VERSION 5.8 ;
BUSBITCHARS "[]" ;
DIVIDERCHAR "/" ;
UNITS
    DATABASE MICRONS 1000 ;
END UNITS

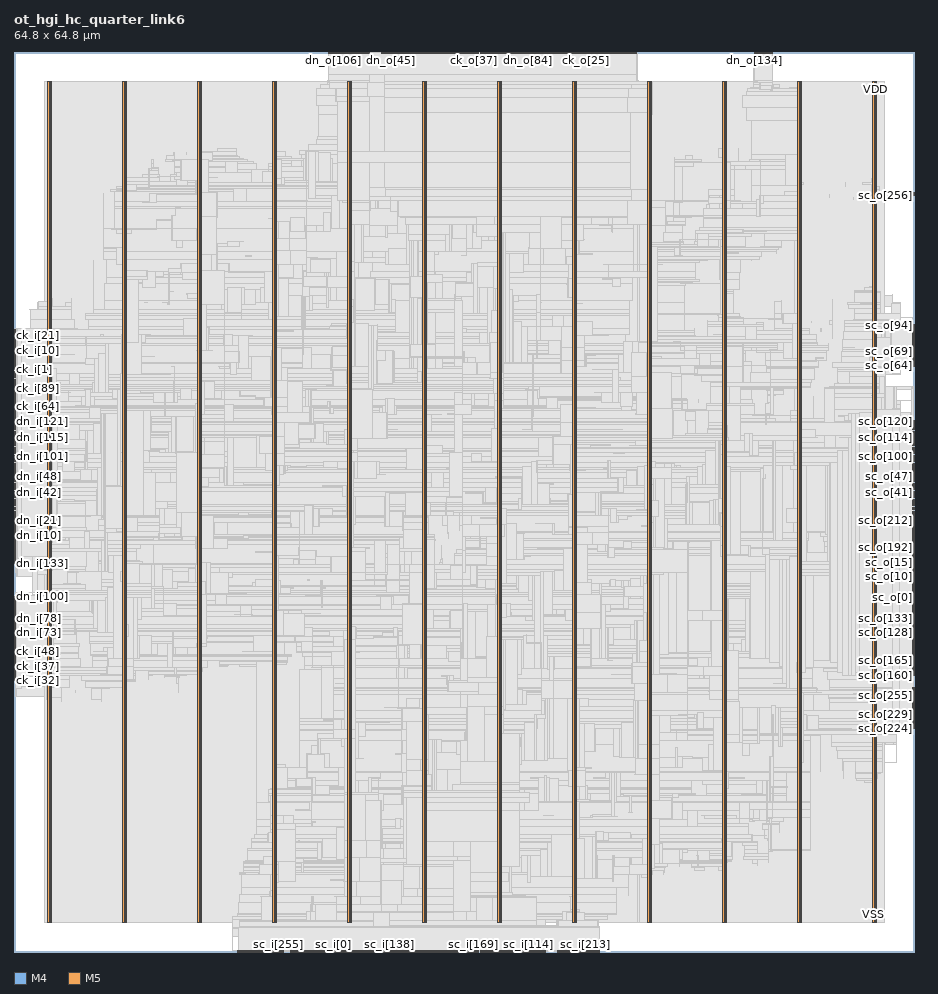
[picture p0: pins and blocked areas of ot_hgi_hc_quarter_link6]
MACRO ot_hgi_hc_quarter_link6
  FOREIGN ot_hgi_hc_quarter_link6 0 0 ;
  CLASS BLOCK ;
  SIZE 64.8 BY 64.8 ;
  PIN ck_i[0]
    DIRECTION INPUT ;
    USE SIGNAL ;
    PORT
      LAYER M4 ;
        RECT  0 41.808 0.084 41.832 ;
    END
  END ck_i[0]
  PIN ck_i[10]
    DIRECTION INPUT ;
    USE SIGNAL ;
    PORT
      LAYER M4 ;
        RECT  0 42.768 0.084 42.792 ;
    END
  END ck_i[10]
  PIN ck_i[11]
    DIRECTION INPUT ;
    USE SIGNAL ;
    PORT
      LAYER M4 ;
        RECT  0 42.864 0.084 42.888 ;
    END
  END ck_i[11]
  PIN ck_i[12]
    DIRECTION INPUT ;
    USE SIGNAL ;
    PORT
      LAYER M4 ;
        RECT  0 42.96 0.084 42.984 ;
    END
  END ck_i[12]
  PIN ck_i[13]
    DIRECTION INPUT ;
    USE SIGNAL ;
    PORT
      LAYER M4 ;
        RECT  0 43.056 0.084 43.08 ;
    END
  END ck_i[13]
  PIN ck_i[14]
    DIRECTION INPUT ;
    USE SIGNAL ;
    PORT
      LAYER M4 ;
        RECT  0 43.152 0.084 43.176 ;
    END
  END ck_i[14]
  PIN ck_i[15]
    DIRECTION INPUT ;
    USE SIGNAL ;
    PORT
      LAYER M4 ;
        RECT  0 43.248 0.084 43.272 ;
    END
  END ck_i[15]
  PIN ck_i[16]
    DIRECTION INPUT ;
    USE SIGNAL ;
    PORT
      LAYER M4 ;
        RECT  0 43.344 0.084 43.368 ;
    END
  END ck_i[16]
  PIN ck_i[17]
    DIRECTION INPUT ;
    USE SIGNAL ;
    PORT
      LAYER M4 ;
        RECT  0 43.44 0.084 43.464 ;
    END
  END ck_i[17]
  PIN ck_i[18]
    DIRECTION INPUT ;
    USE SIGNAL ;
    PORT
      LAYER M4 ;
        RECT  0 43.536 0.084 43.56 ;
    END
  END ck_i[18]
  PIN ck_i[19]
    DIRECTION INPUT ;
    USE SIGNAL ;
    PORT
      LAYER M4 ;
        RECT  0 43.632 0.084 43.656 ;
    END
  END ck_i[19]
  PIN ck_i[1]
    DIRECTION INPUT ;
    USE SIGNAL ;
    PORT
      LAYER M4 ;
        RECT  0 41.904 0.084 41.928 ;
    END
  END ck_i[1]
  PIN ck_i[20]
    DIRECTION INPUT ;
    USE SIGNAL ;
    PORT
      LAYER M4 ;
        RECT  0 43.728 0.084 43.752 ;
    END
  END ck_i[20]
  PIN ck_i[21]
    DIRECTION INPUT ;
    USE SIGNAL ;
    PORT
      LAYER M4 ;
        RECT  0 43.824 0.084 43.848 ;
    END
  END ck_i[21]
  PIN ck_i[22]
    DIRECTION INPUT ;
    USE SIGNAL ;
    PORT
      LAYER M4 ;
        RECT  0 43.92 0.084 43.944 ;
    END
  END ck_i[22]
  PIN ck_i[23]
    DIRECTION INPUT ;
    USE SIGNAL ;
    PORT
      LAYER M4 ;
        RECT  0 44.016 0.084 44.04 ;
    END
  END ck_i[23]
  PIN ck_i[24]
    DIRECTION INPUT ;
    USE SIGNAL ;
    PORT
      LAYER M4 ;
        RECT  0 44.112 0.084 44.136 ;
    END
  END ck_i[24]
  PIN ck_i[25]
    DIRECTION INPUT ;
    USE SIGNAL ;
    PORT
      LAYER M4 ;
        RECT  0 44.208 0.084 44.232 ;
    END
  END ck_i[25]
  PIN ck_i[26]
    DIRECTION INPUT ;
    USE SIGNAL ;
    PORT
      LAYER M4 ;
        RECT  0 44.304 0.084 44.328 ;
    END
  END ck_i[26]
  PIN ck_i[27]
    DIRECTION INPUT ;
    USE SIGNAL ;
    PORT
      LAYER M4 ;
        RECT  0 44.4 0.084 44.424 ;
    END
  END ck_i[27]
  PIN ck_i[28]
    DIRECTION INPUT ;
    USE SIGNAL ;
    PORT
      LAYER M4 ;
        RECT  0 44.496 0.084 44.52 ;
    END
  END ck_i[28]
  PIN ck_i[29]
    DIRECTION INPUT ;
    USE SIGNAL ;
    PORT
      LAYER M4 ;
        RECT  0 44.592 0.084 44.616 ;
    END
  END ck_i[29]
  PIN ck_i[2]
    DIRECTION INPUT ;
    USE SIGNAL ;
    PORT
      LAYER M4 ;
        RECT  0 42 0.084 42.024 ;
    END
  END ck_i[2]
  PIN ck_i[30]
    DIRECTION INPUT ;
    USE SIGNAL ;
    PORT
      LAYER M4 ;
        RECT  0 44.688 0.084 44.712 ;
    END
  END ck_i[30]
  PIN ck_i[31]
    DIRECTION INPUT ;
    USE SIGNAL ;
    PORT
      LAYER M4 ;
        RECT  0 44.784 0.084 44.808 ;
    END
  END ck_i[31]
  PIN ck_i[32]
    DIRECTION INPUT ;
    USE SIGNAL ;
    PORT
      LAYER M4 ;
        RECT  0 19.536 0.084 19.56 ;
    END
  END ck_i[32]
  PIN ck_i[33]
    DIRECTION INPUT ;
    USE SIGNAL ;
    PORT
      LAYER M4 ;
        RECT  0 19.632 0.084 19.656 ;
    END
  END ck_i[33]
  PIN ck_i[34]
    DIRECTION INPUT ;
    USE SIGNAL ;
    PORT
      LAYER M4 ;
        RECT  0 19.728 0.084 19.752 ;
    END
  END ck_i[34]
  PIN ck_i[35]
    DIRECTION INPUT ;
    USE SIGNAL ;
    PORT
      LAYER M4 ;
        RECT  0 19.824 0.084 19.848 ;
    END
  END ck_i[35]
  PIN ck_i[36]
    DIRECTION INPUT ;
    USE SIGNAL ;
    PORT
      LAYER M4 ;
        RECT  0 19.92 0.084 19.944 ;
    END
  END ck_i[36]
  PIN ck_i[37]
    DIRECTION INPUT ;
    USE SIGNAL ;
    PORT
      LAYER M4 ;
        RECT  0 20.016 0.084 20.04 ;
    END
  END ck_i[37]
  PIN ck_i[38]
    DIRECTION INPUT ;
    USE SIGNAL ;
    PORT
      LAYER M4 ;
        RECT  0 20.112 0.084 20.136 ;
    END
  END ck_i[38]
  PIN ck_i[39]
    DIRECTION INPUT ;
    USE SIGNAL ;
    PORT
      LAYER M4 ;
        RECT  0 20.208 0.084 20.232 ;
    END
  END ck_i[39]
  PIN ck_i[3]
    DIRECTION INPUT ;
    USE SIGNAL ;
    PORT
      LAYER M4 ;
        RECT  0 42.096 0.084 42.12 ;
    END
  END ck_i[3]
  PIN ck_i[40]
    DIRECTION INPUT ;
    USE SIGNAL ;
    PORT
      LAYER M4 ;
        RECT  0 20.304 0.084 20.328 ;
    END
  END ck_i[40]
  PIN ck_i[41]
    DIRECTION INPUT ;
    USE SIGNAL ;
    PORT
      LAYER M4 ;
        RECT  0 20.4 0.084 20.424 ;
    END
  END ck_i[41]
  PIN ck_i[42]
    DIRECTION INPUT ;
    USE SIGNAL ;
    PORT
      LAYER M4 ;
        RECT  0 20.496 0.084 20.52 ;
    END
  END ck_i[42]
  PIN ck_i[43]
    DIRECTION INPUT ;
    USE SIGNAL ;
    PORT
      LAYER M4 ;
        RECT  0 20.592 0.084 20.616 ;
    END
  END ck_i[43]
  PIN ck_i[44]
    DIRECTION INPUT ;
    USE SIGNAL ;
    PORT
      LAYER M4 ;
        RECT  0 20.688 0.084 20.712 ;
    END
  END ck_i[44]
  PIN ck_i[45]
    DIRECTION INPUT ;
    USE SIGNAL ;
    PORT
      LAYER M4 ;
        RECT  0 20.784 0.084 20.808 ;
    END
  END ck_i[45]
  PIN ck_i[46]
    DIRECTION INPUT ;
    USE SIGNAL ;
    PORT
      LAYER M4 ;
        RECT  0 20.88 0.084 20.904 ;
    END
  END ck_i[46]
  PIN ck_i[47]
    DIRECTION INPUT ;
    USE SIGNAL ;
    PORT
      LAYER M4 ;
        RECT  0 20.976 0.084 21 ;
    END
  END ck_i[47]
  PIN ck_i[48]
    DIRECTION INPUT ;
    USE SIGNAL ;
    PORT
      LAYER M4 ;
        RECT  0 21.072 0.084 21.096 ;
    END
  END ck_i[48]
  PIN ck_i[49]
    DIRECTION INPUT ;
    USE SIGNAL ;
    PORT
      LAYER M4 ;
        RECT  0 21.168 0.084 21.192 ;
    END
  END ck_i[49]
  PIN ck_i[4]
    DIRECTION INPUT ;
    USE SIGNAL ;
    PORT
      LAYER M4 ;
        RECT  0 42.192 0.084 42.216 ;
    END
  END ck_i[4]
  PIN ck_i[50]
    DIRECTION INPUT ;
    USE SIGNAL ;
    PORT
      LAYER M4 ;
        RECT  0 21.264 0.084 21.288 ;
    END
  END ck_i[50]
  PIN ck_i[51]
    DIRECTION INPUT ;
    USE SIGNAL ;
    PORT
      LAYER M4 ;
        RECT  0 21.36 0.084 21.384 ;
    END
  END ck_i[51]
  PIN ck_i[52]
    DIRECTION INPUT ;
    USE SIGNAL ;
    PORT
      LAYER M4 ;
        RECT  0 21.456 0.084 21.48 ;
    END
  END ck_i[52]
  PIN ck_i[53]
    DIRECTION INPUT ;
    USE SIGNAL ;
    PORT
      LAYER M4 ;
        RECT  0 21.552 0.084 21.576 ;
    END
  END ck_i[53]
  PIN ck_i[54]
    DIRECTION INPUT ;
    USE SIGNAL ;
    PORT
      LAYER M4 ;
        RECT  0 21.648 0.084 21.672 ;
    END
  END ck_i[54]
  PIN ck_i[55]
    DIRECTION INPUT ;
    USE SIGNAL ;
    PORT
      LAYER M4 ;
        RECT  0 21.744 0.084 21.768 ;
    END
  END ck_i[55]
  PIN ck_i[56]
    DIRECTION INPUT ;
    USE SIGNAL ;
    PORT
      LAYER M4 ;
        RECT  0 21.84 0.084 21.864 ;
    END
  END ck_i[56]
  PIN ck_i[57]
    DIRECTION INPUT ;
    USE SIGNAL ;
    PORT
      LAYER M4 ;
        RECT  0 21.936 0.084 21.96 ;
    END
  END ck_i[57]
  PIN ck_i[58]
    DIRECTION INPUT ;
    USE SIGNAL ;
    PORT
      LAYER M4 ;
        RECT  0 22.032 0.084 22.056 ;
    END
  END ck_i[58]
  PIN ck_i[59]
    DIRECTION INPUT ;
    USE SIGNAL ;
    PORT
      LAYER M4 ;
        RECT  0 22.128 0.084 22.152 ;
    END
  END ck_i[59]
  PIN ck_i[5]
    DIRECTION INPUT ;
    USE SIGNAL ;
    PORT
      LAYER M4 ;
        RECT  0 42.288 0.084 42.312 ;
    END
  END ck_i[5]
  PIN ck_i[60]
    DIRECTION INPUT ;
    USE SIGNAL ;
    PORT
      LAYER M4 ;
        RECT  0 22.224 0.084 22.248 ;
    END
  END ck_i[60]
  PIN ck_i[61]
    DIRECTION INPUT ;
    USE SIGNAL ;
    PORT
      LAYER M4 ;
        RECT  0 22.32 0.084 22.344 ;
    END
  END ck_i[61]
  PIN ck_i[62]
    DIRECTION INPUT ;
    USE SIGNAL ;
    PORT
      LAYER M4 ;
        RECT  0 22.416 0.084 22.44 ;
    END
  END ck_i[62]
  PIN ck_i[63]
    DIRECTION INPUT ;
    USE SIGNAL ;
    PORT
      LAYER M4 ;
        RECT  0 22.512 0.084 22.536 ;
    END
  END ck_i[63]
  PIN ck_i[64]
    DIRECTION INPUT ;
    USE SIGNAL ;
    PORT
      LAYER M4 ;
        RECT  0 38.736 0.084 38.76 ;
    END
  END ck_i[64]
  PIN ck_i[65]
    DIRECTION INPUT ;
    USE SIGNAL ;
    PORT
      LAYER M4 ;
        RECT  0 38.832 0.084 38.856 ;
    END
  END ck_i[65]
  PIN ck_i[66]
    DIRECTION INPUT ;
    USE SIGNAL ;
    PORT
      LAYER M4 ;
        RECT  0 38.928 0.084 38.952 ;
    END
  END ck_i[66]
  PIN ck_i[67]
    DIRECTION INPUT ;
    USE SIGNAL ;
    PORT
      LAYER M4 ;
        RECT  0 39.024 0.084 39.048 ;
    END
  END ck_i[67]
  PIN ck_i[68]
    DIRECTION INPUT ;
    USE SIGNAL ;
    PORT
      LAYER M4 ;
        RECT  0 39.12 0.084 39.144 ;
    END
  END ck_i[68]
  PIN ck_i[69]
    DIRECTION INPUT ;
    USE SIGNAL ;
    PORT
      LAYER M4 ;
        RECT  0 39.216 0.084 39.24 ;
    END
  END ck_i[69]
  PIN ck_i[6]
    DIRECTION INPUT ;
    USE SIGNAL ;
    PORT
      LAYER M4 ;
        RECT  0 42.384 0.084 42.408 ;
    END
  END ck_i[6]
  PIN ck_i[70]
    DIRECTION INPUT ;
    USE SIGNAL ;
    PORT
      LAYER M4 ;
        RECT  0 39.312 0.084 39.336 ;
    END
  END ck_i[70]
  PIN ck_i[71]
    DIRECTION INPUT ;
    USE SIGNAL ;
    PORT
      LAYER M4 ;
        RECT  0 39.408 0.084 39.432 ;
    END
  END ck_i[71]
  PIN ck_i[72]
    DIRECTION INPUT ;
    USE SIGNAL ;
    PORT
      LAYER M4 ;
        RECT  0 39.504 0.084 39.528 ;
    END
  END ck_i[72]
  PIN ck_i[73]
    DIRECTION INPUT ;
    USE SIGNAL ;
    PORT
      LAYER M4 ;
        RECT  0 39.6 0.084 39.624 ;
    END
  END ck_i[73]
  PIN ck_i[74]
    DIRECTION INPUT ;
    USE SIGNAL ;
    PORT
      LAYER M4 ;
        RECT  0 39.696 0.084 39.72 ;
    END
  END ck_i[74]
  PIN ck_i[75]
    DIRECTION INPUT ;
    USE SIGNAL ;
    PORT
      LAYER M4 ;
        RECT  0 39.792 0.084 39.816 ;
    END
  END ck_i[75]
  PIN ck_i[76]
    DIRECTION INPUT ;
    USE SIGNAL ;
    PORT
      LAYER M4 ;
        RECT  0 39.888 0.084 39.912 ;
    END
  END ck_i[76]
  PIN ck_i[77]
    DIRECTION INPUT ;
    USE SIGNAL ;
    PORT
      LAYER M4 ;
        RECT  0 39.984 0.084 40.008 ;
    END
  END ck_i[77]
  PIN ck_i[78]
    DIRECTION INPUT ;
    USE SIGNAL ;
    PORT
      LAYER M4 ;
        RECT  0 40.08 0.084 40.104 ;
    END
  END ck_i[78]
  PIN ck_i[79]
    DIRECTION INPUT ;
    USE SIGNAL ;
    PORT
      LAYER M4 ;
        RECT  0 40.176 0.084 40.2 ;
    END
  END ck_i[79]
  PIN ck_i[7]
    DIRECTION INPUT ;
    USE SIGNAL ;
    PORT
      LAYER M4 ;
        RECT  0 42.48 0.084 42.504 ;
    END
  END ck_i[7]
  PIN ck_i[80]
    DIRECTION INPUT ;
    USE SIGNAL ;
    PORT
      LAYER M4 ;
        RECT  0 40.272 0.084 40.296 ;
    END
  END ck_i[80]
  PIN ck_i[81]
    DIRECTION INPUT ;
    USE SIGNAL ;
    PORT
      LAYER M4 ;
        RECT  0 40.368 0.084 40.392 ;
    END
  END ck_i[81]
  PIN ck_i[82]
    DIRECTION INPUT ;
    USE SIGNAL ;
    PORT
      LAYER M4 ;
        RECT  0 40.464 0.084 40.488 ;
    END
  END ck_i[82]
  PIN ck_i[83]
    DIRECTION INPUT ;
    USE SIGNAL ;
    PORT
      LAYER M4 ;
        RECT  0 40.56 0.084 40.584 ;
    END
  END ck_i[83]
  PIN ck_i[84]
    DIRECTION INPUT ;
    USE SIGNAL ;
    PORT
      LAYER M4 ;
        RECT  0 40.656 0.084 40.68 ;
    END
  END ck_i[84]
  PIN ck_i[85]
    DIRECTION INPUT ;
    USE SIGNAL ;
    PORT
      LAYER M4 ;
        RECT  0 40.752 0.084 40.776 ;
    END
  END ck_i[85]
  PIN ck_i[86]
    DIRECTION INPUT ;
    USE SIGNAL ;
    PORT
      LAYER M4 ;
        RECT  0 40.848 0.084 40.872 ;
    END
  END ck_i[86]
  PIN ck_i[87]
    DIRECTION INPUT ;
    USE SIGNAL ;
    PORT
      LAYER M4 ;
        RECT  0 40.944 0.084 40.968 ;
    END
  END ck_i[87]
  PIN ck_i[88]
    DIRECTION INPUT ;
    USE SIGNAL ;
    PORT
      LAYER M4 ;
        RECT  0 41.04 0.084 41.064 ;
    END
  END ck_i[88]
  PIN ck_i[89]
    DIRECTION INPUT ;
    USE SIGNAL ;
    PORT
      LAYER M4 ;
        RECT  0 41.136 0.084 41.16 ;
    END
  END ck_i[89]
  PIN ck_i[8]
    DIRECTION INPUT ;
    USE SIGNAL ;
    PORT
      LAYER M4 ;
        RECT  0 42.576 0.084 42.6 ;
    END
  END ck_i[8]
  PIN ck_i[9]
    DIRECTION INPUT ;
    USE SIGNAL ;
    PORT
      LAYER M4 ;
        RECT  0 42.672 0.084 42.696 ;
    END
  END ck_i[9]
  PIN ck_o[0]
    DIRECTION OUTPUT ;
    USE SIGNAL ;
    PORT
      LAYER M5 ;
        RECT  38.736 64.716 38.76 64.8 ;
    END
  END ck_o[0]
  PIN ck_o[10]
    DIRECTION OUTPUT ;
    USE SIGNAL ;
    PORT
      LAYER M5 ;
        RECT  39.696 64.716 39.72 64.8 ;
    END
  END ck_o[10]
  PIN ck_o[11]
    DIRECTION OUTPUT ;
    USE SIGNAL ;
    PORT
      LAYER M5 ;
        RECT  39.792 64.716 39.816 64.8 ;
    END
  END ck_o[11]
  PIN ck_o[12]
    DIRECTION OUTPUT ;
    USE SIGNAL ;
    PORT
      LAYER M5 ;
        RECT  39.888 64.716 39.912 64.8 ;
    END
  END ck_o[12]
  PIN ck_o[13]
    DIRECTION OUTPUT ;
    USE SIGNAL ;
    PORT
      LAYER M5 ;
        RECT  39.984 64.716 40.008 64.8 ;
    END
  END ck_o[13]
  PIN ck_o[14]
    DIRECTION OUTPUT ;
    USE SIGNAL ;
    PORT
      LAYER M5 ;
        RECT  40.08 64.716 40.104 64.8 ;
    END
  END ck_o[14]
  PIN ck_o[15]
    DIRECTION OUTPUT ;
    USE SIGNAL ;
    PORT
      LAYER M5 ;
        RECT  40.176 64.716 40.2 64.8 ;
    END
  END ck_o[15]
  PIN ck_o[16]
    DIRECTION OUTPUT ;
    USE SIGNAL ;
    PORT
      LAYER M5 ;
        RECT  40.272 64.716 40.296 64.8 ;
    END
  END ck_o[16]
  PIN ck_o[17]
    DIRECTION OUTPUT ;
    USE SIGNAL ;
    PORT
      LAYER M5 ;
        RECT  40.368 64.716 40.392 64.8 ;
    END
  END ck_o[17]
  PIN ck_o[18]
    DIRECTION OUTPUT ;
    USE SIGNAL ;
    PORT
      LAYER M5 ;
        RECT  40.464 64.716 40.488 64.8 ;
    END
  END ck_o[18]
  PIN ck_o[19]
    DIRECTION OUTPUT ;
    USE SIGNAL ;
    PORT
      LAYER M5 ;
        RECT  40.56 64.716 40.584 64.8 ;
    END
  END ck_o[19]
  PIN ck_o[1]
    DIRECTION OUTPUT ;
    USE SIGNAL ;
    PORT
      LAYER M5 ;
        RECT  38.832 64.716 38.856 64.8 ;
    END
  END ck_o[1]
  PIN ck_o[20]
    DIRECTION OUTPUT ;
    USE SIGNAL ;
    PORT
      LAYER M5 ;
        RECT  40.656 64.716 40.68 64.8 ;
    END
  END ck_o[20]
  PIN ck_o[21]
    DIRECTION OUTPUT ;
    USE SIGNAL ;
    PORT
      LAYER M5 ;
        RECT  40.752 64.716 40.776 64.8 ;
    END
  END ck_o[21]
  PIN ck_o[22]
    DIRECTION OUTPUT ;
    USE SIGNAL ;
    PORT
      LAYER M5 ;
        RECT  40.848 64.716 40.872 64.8 ;
    END
  END ck_o[22]
  PIN ck_o[23]
    DIRECTION OUTPUT ;
    USE SIGNAL ;
    PORT
      LAYER M5 ;
        RECT  40.944 64.716 40.968 64.8 ;
    END
  END ck_o[23]
  PIN ck_o[24]
    DIRECTION OUTPUT ;
    USE SIGNAL ;
    PORT
      LAYER M5 ;
        RECT  41.04 64.716 41.064 64.8 ;
    END
  END ck_o[24]
  PIN ck_o[25]
    DIRECTION OUTPUT ;
    USE SIGNAL ;
    PORT
      LAYER M5 ;
        RECT  41.136 64.716 41.16 64.8 ;
    END
  END ck_o[25]
  PIN ck_o[26]
    DIRECTION OUTPUT ;
    USE SIGNAL ;
    PORT
      LAYER M5 ;
        RECT  41.232 64.716 41.256 64.8 ;
    END
  END ck_o[26]
  PIN ck_o[27]
    DIRECTION OUTPUT ;
    USE SIGNAL ;
    PORT
      LAYER M5 ;
        RECT  41.328 64.716 41.352 64.8 ;
    END
  END ck_o[27]
  PIN ck_o[28]
    DIRECTION OUTPUT ;
    USE SIGNAL ;
    PORT
      LAYER M5 ;
        RECT  41.424 64.716 41.448 64.8 ;
    END
  END ck_o[28]
  PIN ck_o[29]
    DIRECTION OUTPUT ;
    USE SIGNAL ;
    PORT
      LAYER M5 ;
        RECT  41.52 64.716 41.544 64.8 ;
    END
  END ck_o[29]
  PIN ck_o[2]
    DIRECTION OUTPUT ;
    USE SIGNAL ;
    PORT
      LAYER M5 ;
        RECT  38.928 64.716 38.952 64.8 ;
    END
  END ck_o[2]
  PIN ck_o[30]
    DIRECTION OUTPUT ;
    USE SIGNAL ;
    PORT
      LAYER M5 ;
        RECT  41.616 64.716 41.64 64.8 ;
    END
  END ck_o[30]
  PIN ck_o[31]
    DIRECTION OUTPUT ;
    USE SIGNAL ;
    PORT
      LAYER M5 ;
        RECT  41.712 64.716 41.736 64.8 ;
    END
  END ck_o[31]
  PIN ck_o[32]
    DIRECTION OUTPUT ;
    USE SIGNAL ;
    PORT
      LAYER M5 ;
        RECT  32.592 64.716 32.616 64.8 ;
    END
  END ck_o[32]
  PIN ck_o[33]
    DIRECTION OUTPUT ;
    USE SIGNAL ;
    PORT
      LAYER M5 ;
        RECT  32.688 64.716 32.712 64.8 ;
    END
  END ck_o[33]
  PIN ck_o[34]
    DIRECTION OUTPUT ;
    USE SIGNAL ;
    PORT
      LAYER M5 ;
        RECT  32.784 64.716 32.808 64.8 ;
    END
  END ck_o[34]
  PIN ck_o[35]
    DIRECTION OUTPUT ;
    USE SIGNAL ;
    PORT
      LAYER M5 ;
        RECT  32.88 64.716 32.904 64.8 ;
    END
  END ck_o[35]
  PIN ck_o[36]
    DIRECTION OUTPUT ;
    USE SIGNAL ;
    PORT
      LAYER M5 ;
        RECT  32.976 64.716 33 64.8 ;
    END
  END ck_o[36]
  PIN ck_o[37]
    DIRECTION OUTPUT ;
    USE SIGNAL ;
    PORT
      LAYER M5 ;
        RECT  33.072 64.716 33.096 64.8 ;
    END
  END ck_o[37]
  PIN ck_o[38]
    DIRECTION OUTPUT ;
    USE SIGNAL ;
    PORT
      LAYER M5 ;
        RECT  33.168 64.716 33.192 64.8 ;
    END
  END ck_o[38]
  PIN ck_o[39]
    DIRECTION OUTPUT ;
    USE SIGNAL ;
    PORT
      LAYER M5 ;
        RECT  33.264 64.716 33.288 64.8 ;
    END
  END ck_o[39]
  PIN ck_o[3]
    DIRECTION OUTPUT ;
    USE SIGNAL ;
    PORT
      LAYER M5 ;
        RECT  39.024 64.716 39.048 64.8 ;
    END
  END ck_o[3]
  PIN ck_o[40]
    DIRECTION OUTPUT ;
    USE SIGNAL ;
    PORT
      LAYER M5 ;
        RECT  33.36 64.716 33.384 64.8 ;
    END
  END ck_o[40]
  PIN ck_o[41]
    DIRECTION OUTPUT ;
    USE SIGNAL ;
    PORT
      LAYER M5 ;
        RECT  33.456 64.716 33.48 64.8 ;
    END
  END ck_o[41]
  PIN ck_o[42]
    DIRECTION OUTPUT ;
    USE SIGNAL ;
    PORT
      LAYER M5 ;
        RECT  33.552 64.716 33.576 64.8 ;
    END
  END ck_o[42]
  PIN ck_o[43]
    DIRECTION OUTPUT ;
    USE SIGNAL ;
    PORT
      LAYER M5 ;
        RECT  33.648 64.716 33.672 64.8 ;
    END
  END ck_o[43]
  PIN ck_o[44]
    DIRECTION OUTPUT ;
    USE SIGNAL ;
    PORT
      LAYER M5 ;
        RECT  33.744 64.716 33.768 64.8 ;
    END
  END ck_o[44]
  PIN ck_o[45]
    DIRECTION OUTPUT ;
    USE SIGNAL ;
    PORT
      LAYER M5 ;
        RECT  33.84 64.716 33.864 64.8 ;
    END
  END ck_o[45]
  PIN ck_o[46]
    DIRECTION OUTPUT ;
    USE SIGNAL ;
    PORT
      LAYER M5 ;
        RECT  33.936 64.716 33.96 64.8 ;
    END
  END ck_o[46]
  PIN ck_o[47]
    DIRECTION OUTPUT ;
    USE SIGNAL ;
    PORT
      LAYER M5 ;
        RECT  34.032 64.716 34.056 64.8 ;
    END
  END ck_o[47]
  PIN ck_o[48]
    DIRECTION OUTPUT ;
    USE SIGNAL ;
    PORT
      LAYER M5 ;
        RECT  34.128 64.716 34.152 64.8 ;
    END
  END ck_o[48]
  PIN ck_o[49]
    DIRECTION OUTPUT ;
    USE SIGNAL ;
    PORT
      LAYER M5 ;
        RECT  34.224 64.716 34.248 64.8 ;
    END
  END ck_o[49]
  PIN ck_o[4]
    DIRECTION OUTPUT ;
    USE SIGNAL ;
    PORT
      LAYER M5 ;
        RECT  39.12 64.716 39.144 64.8 ;
    END
  END ck_o[4]
  PIN ck_o[50]
    DIRECTION OUTPUT ;
    USE SIGNAL ;
    PORT
      LAYER M5 ;
        RECT  34.32 64.716 34.344 64.8 ;
    END
  END ck_o[50]
  PIN ck_o[51]
    DIRECTION OUTPUT ;
    USE SIGNAL ;
    PORT
      LAYER M5 ;
        RECT  34.416 64.716 34.44 64.8 ;
    END
  END ck_o[51]
  PIN ck_o[52]
    DIRECTION OUTPUT ;
    USE SIGNAL ;
    PORT
      LAYER M5 ;
        RECT  34.512 64.716 34.536 64.8 ;
    END
  END ck_o[52]
  PIN ck_o[53]
    DIRECTION OUTPUT ;
    USE SIGNAL ;
    PORT
      LAYER M5 ;
        RECT  34.608 64.716 34.632 64.8 ;
    END
  END ck_o[53]
  PIN ck_o[54]
    DIRECTION OUTPUT ;
    USE SIGNAL ;
    PORT
      LAYER M5 ;
        RECT  34.704 64.716 34.728 64.8 ;
    END
  END ck_o[54]
  PIN ck_o[55]
    DIRECTION OUTPUT ;
    USE SIGNAL ;
    PORT
      LAYER M5 ;
        RECT  34.8 64.716 34.824 64.8 ;
    END
  END ck_o[55]
  PIN ck_o[56]
    DIRECTION OUTPUT ;
    USE SIGNAL ;
    PORT
      LAYER M5 ;
        RECT  34.896 64.716 34.92 64.8 ;
    END
  END ck_o[56]
  PIN ck_o[57]
    DIRECTION OUTPUT ;
    USE SIGNAL ;
    PORT
      LAYER M5 ;
        RECT  34.992 64.716 35.016 64.8 ;
    END
  END ck_o[57]
  PIN ck_o[58]
    DIRECTION OUTPUT ;
    USE SIGNAL ;
    PORT
      LAYER M5 ;
        RECT  35.088 64.716 35.112 64.8 ;
    END
  END ck_o[58]
  PIN ck_o[59]
    DIRECTION OUTPUT ;
    USE SIGNAL ;
    PORT
      LAYER M5 ;
        RECT  35.184 64.716 35.208 64.8 ;
    END
  END ck_o[59]
  PIN ck_o[5]
    DIRECTION OUTPUT ;
    USE SIGNAL ;
    PORT
      LAYER M5 ;
        RECT  39.216 64.716 39.24 64.8 ;
    END
  END ck_o[5]
  PIN ck_o[60]
    DIRECTION OUTPUT ;
    USE SIGNAL ;
    PORT
      LAYER M5 ;
        RECT  35.28 64.716 35.304 64.8 ;
    END
  END ck_o[60]
  PIN ck_o[61]
    DIRECTION OUTPUT ;
    USE SIGNAL ;
    PORT
      LAYER M5 ;
        RECT  35.376 64.716 35.4 64.8 ;
    END
  END ck_o[61]
  PIN ck_o[62]
    DIRECTION OUTPUT ;
    USE SIGNAL ;
    PORT
      LAYER M5 ;
        RECT  35.472 64.716 35.496 64.8 ;
    END
  END ck_o[62]
  PIN ck_o[63]
    DIRECTION OUTPUT ;
    USE SIGNAL ;
    PORT
      LAYER M5 ;
        RECT  35.568 64.716 35.592 64.8 ;
    END
  END ck_o[63]
  PIN ck_o[64]
    DIRECTION OUTPUT ;
    USE SIGNAL ;
    PORT
      LAYER M5 ;
        RECT  29.52 64.716 29.544 64.8 ;
    END
  END ck_o[64]
  PIN ck_o[65]
    DIRECTION OUTPUT ;
    USE SIGNAL ;
    PORT
      LAYER M5 ;
        RECT  29.616 64.716 29.64 64.8 ;
    END
  END ck_o[65]
  PIN ck_o[66]
    DIRECTION OUTPUT ;
    USE SIGNAL ;
    PORT
      LAYER M5 ;
        RECT  29.712 64.716 29.736 64.8 ;
    END
  END ck_o[66]
  PIN ck_o[67]
    DIRECTION OUTPUT ;
    USE SIGNAL ;
    PORT
      LAYER M5 ;
        RECT  29.808 64.716 29.832 64.8 ;
    END
  END ck_o[67]
  PIN ck_o[68]
    DIRECTION OUTPUT ;
    USE SIGNAL ;
    PORT
      LAYER M5 ;
        RECT  29.904 64.716 29.928 64.8 ;
    END
  END ck_o[68]
  PIN ck_o[69]
    DIRECTION OUTPUT ;
    USE SIGNAL ;
    PORT
      LAYER M5 ;
        RECT  30 64.716 30.024 64.8 ;
    END
  END ck_o[69]
  PIN ck_o[6]
    DIRECTION OUTPUT ;
    USE SIGNAL ;
    PORT
      LAYER M5 ;
        RECT  39.312 64.716 39.336 64.8 ;
    END
  END ck_o[6]
  PIN ck_o[70]
    DIRECTION OUTPUT ;
    USE SIGNAL ;
    PORT
      LAYER M5 ;
        RECT  30.096 64.716 30.12 64.8 ;
    END
  END ck_o[70]
  PIN ck_o[71]
    DIRECTION OUTPUT ;
    USE SIGNAL ;
    PORT
      LAYER M5 ;
        RECT  30.192 64.716 30.216 64.8 ;
    END
  END ck_o[71]
  PIN ck_o[72]
    DIRECTION OUTPUT ;
    USE SIGNAL ;
    PORT
      LAYER M5 ;
        RECT  30.288 64.716 30.312 64.8 ;
    END
  END ck_o[72]
  PIN ck_o[73]
    DIRECTION OUTPUT ;
    USE SIGNAL ;
    PORT
      LAYER M5 ;
        RECT  30.384 64.716 30.408 64.8 ;
    END
  END ck_o[73]
  PIN ck_o[74]
    DIRECTION OUTPUT ;
    USE SIGNAL ;
    PORT
      LAYER M5 ;
        RECT  30.48 64.716 30.504 64.8 ;
    END
  END ck_o[74]
  PIN ck_o[75]
    DIRECTION OUTPUT ;
    USE SIGNAL ;
    PORT
      LAYER M5 ;
        RECT  30.576 64.716 30.6 64.8 ;
    END
  END ck_o[75]
  PIN ck_o[76]
    DIRECTION OUTPUT ;
    USE SIGNAL ;
    PORT
      LAYER M5 ;
        RECT  30.672 64.716 30.696 64.8 ;
    END
  END ck_o[76]
  PIN ck_o[77]
    DIRECTION OUTPUT ;
    USE SIGNAL ;
    PORT
      LAYER M5 ;
        RECT  30.768 64.716 30.792 64.8 ;
    END
  END ck_o[77]
  PIN ck_o[78]
    DIRECTION OUTPUT ;
    USE SIGNAL ;
    PORT
      LAYER M5 ;
        RECT  30.864 64.716 30.888 64.8 ;
    END
  END ck_o[78]
  PIN ck_o[79]
    DIRECTION OUTPUT ;
    USE SIGNAL ;
    PORT
      LAYER M5 ;
        RECT  30.96 64.716 30.984 64.8 ;
    END
  END ck_o[79]
  PIN ck_o[7]
    DIRECTION OUTPUT ;
    USE SIGNAL ;
    PORT
      LAYER M5 ;
        RECT  39.408 64.716 39.432 64.8 ;
    END
  END ck_o[7]
  PIN ck_o[80]
    DIRECTION OUTPUT ;
    USE SIGNAL ;
    PORT
      LAYER M5 ;
        RECT  31.056 64.716 31.08 64.8 ;
    END
  END ck_o[80]
  PIN ck_o[81]
    DIRECTION OUTPUT ;
    USE SIGNAL ;
    PORT
      LAYER M5 ;
        RECT  31.152 64.716 31.176 64.8 ;
    END
  END ck_o[81]
  PIN ck_o[82]
    DIRECTION OUTPUT ;
    USE SIGNAL ;
    PORT
      LAYER M5 ;
        RECT  31.248 64.716 31.272 64.8 ;
    END
  END ck_o[82]
  PIN ck_o[83]
    DIRECTION OUTPUT ;
    USE SIGNAL ;
    PORT
      LAYER M5 ;
        RECT  31.344 64.716 31.368 64.8 ;
    END
  END ck_o[83]
  PIN ck_o[84]
    DIRECTION OUTPUT ;
    USE SIGNAL ;
    PORT
      LAYER M5 ;
        RECT  31.44 64.716 31.464 64.8 ;
    END
  END ck_o[84]
  PIN ck_o[85]
    DIRECTION OUTPUT ;
    USE SIGNAL ;
    PORT
      LAYER M5 ;
        RECT  31.536 64.716 31.56 64.8 ;
    END
  END ck_o[85]
  PIN ck_o[86]
    DIRECTION OUTPUT ;
    USE SIGNAL ;
    PORT
      LAYER M5 ;
        RECT  31.632 64.716 31.656 64.8 ;
    END
  END ck_o[86]
  PIN ck_o[87]
    DIRECTION OUTPUT ;
    USE SIGNAL ;
    PORT
      LAYER M5 ;
        RECT  31.728 64.716 31.752 64.8 ;
    END
  END ck_o[87]
  PIN ck_o[88]
    DIRECTION OUTPUT ;
    USE SIGNAL ;
    PORT
      LAYER M5 ;
        RECT  31.824 64.716 31.848 64.8 ;
    END
  END ck_o[88]
  PIN ck_o[89]
    DIRECTION OUTPUT ;
    USE SIGNAL ;
    PORT
      LAYER M5 ;
        RECT  31.92 64.716 31.944 64.8 ;
    END
  END ck_o[89]
  PIN ck_o[8]
    DIRECTION OUTPUT ;
    USE SIGNAL ;
    PORT
      LAYER M5 ;
        RECT  39.504 64.716 39.528 64.8 ;
    END
  END ck_o[8]
  PIN ck_o[9]
    DIRECTION OUTPUT ;
    USE SIGNAL ;
    PORT
      LAYER M5 ;
        RECT  39.6 64.716 39.624 64.8 ;
    END
  END ck_o[9]
  PIN clk
    DIRECTION INPUT ;
    USE SIGNAL ;
    PORT
      LAYER M4 ;
        RECT  0 41.232 0.084 41.256 ;
    END
  END clk
  PIN dn_i[0]
    DIRECTION INPUT ;
    USE SIGNAL ;
    PORT
      LAYER M4 ;
        RECT  0 41.328 0.084 41.352 ;
    END
  END dn_i[0]
  PIN dn_i[100]
    DIRECTION INPUT ;
    USE SIGNAL ;
    PORT
      LAYER M4 ;
        RECT  0 25.584 0.084 25.608 ;
    END
  END dn_i[100]
  PIN dn_i[101]
    DIRECTION INPUT ;
    USE SIGNAL ;
    PORT
      LAYER M4 ;
        RECT  0 35.664 0.084 35.688 ;
    END
  END dn_i[101]
  PIN dn_i[102]
    DIRECTION INPUT ;
    USE SIGNAL ;
    PORT
      LAYER M4 ;
        RECT  0 35.76 0.084 35.784 ;
    END
  END dn_i[102]
  PIN dn_i[103]
    DIRECTION INPUT ;
    USE SIGNAL ;
    PORT
      LAYER M4 ;
        RECT  0 35.856 0.084 35.88 ;
    END
  END dn_i[103]
  PIN dn_i[104]
    DIRECTION INPUT ;
    USE SIGNAL ;
    PORT
      LAYER M4 ;
        RECT  0 35.952 0.084 35.976 ;
    END
  END dn_i[104]
  PIN dn_i[105]
    DIRECTION INPUT ;
    USE SIGNAL ;
    PORT
      LAYER M4 ;
        RECT  0 36.048 0.084 36.072 ;
    END
  END dn_i[105]
  PIN dn_i[106]
    DIRECTION INPUT ;
    USE SIGNAL ;
    PORT
      LAYER M4 ;
        RECT  0 36.144 0.084 36.168 ;
    END
  END dn_i[106]
  PIN dn_i[107]
    DIRECTION INPUT ;
    USE SIGNAL ;
    PORT
      LAYER M4 ;
        RECT  0 36.24 0.084 36.264 ;
    END
  END dn_i[107]
  PIN dn_i[108]
    DIRECTION INPUT ;
    USE SIGNAL ;
    PORT
      LAYER M4 ;
        RECT  0 36.336 0.084 36.36 ;
    END
  END dn_i[108]
  PIN dn_i[109]
    DIRECTION INPUT ;
    USE SIGNAL ;
    PORT
      LAYER M4 ;
        RECT  0 36.432 0.084 36.456 ;
    END
  END dn_i[109]
  PIN dn_i[10]
    DIRECTION INPUT ;
    USE SIGNAL ;
    PORT
      LAYER M4 ;
        RECT  0 30 0.084 30.024 ;
    END
  END dn_i[10]
  PIN dn_i[110]
    DIRECTION INPUT ;
    USE SIGNAL ;
    PORT
      LAYER M4 ;
        RECT  0 36.528 0.084 36.552 ;
    END
  END dn_i[110]
  PIN dn_i[111]
    DIRECTION INPUT ;
    USE SIGNAL ;
    PORT
      LAYER M4 ;
        RECT  0 36.624 0.084 36.648 ;
    END
  END dn_i[111]
  PIN dn_i[112]
    DIRECTION INPUT ;
    USE SIGNAL ;
    PORT
      LAYER M4 ;
        RECT  0 36.72 0.084 36.744 ;
    END
  END dn_i[112]
  PIN dn_i[113]
    DIRECTION INPUT ;
    USE SIGNAL ;
    PORT
      LAYER M4 ;
        RECT  0 36.816 0.084 36.84 ;
    END
  END dn_i[113]
  PIN dn_i[114]
    DIRECTION INPUT ;
    USE SIGNAL ;
    PORT
      LAYER M4 ;
        RECT  0 36.912 0.084 36.936 ;
    END
  END dn_i[114]
  PIN dn_i[115]
    DIRECTION INPUT ;
    USE SIGNAL ;
    PORT
      LAYER M4 ;
        RECT  0 37.008 0.084 37.032 ;
    END
  END dn_i[115]
  PIN dn_i[116]
    DIRECTION INPUT ;
    USE SIGNAL ;
    PORT
      LAYER M4 ;
        RECT  0 37.104 0.084 37.128 ;
    END
  END dn_i[116]
  PIN dn_i[117]
    DIRECTION INPUT ;
    USE SIGNAL ;
    PORT
      LAYER M4 ;
        RECT  0 37.2 0.084 37.224 ;
    END
  END dn_i[117]
  PIN dn_i[118]
    DIRECTION INPUT ;
    USE SIGNAL ;
    PORT
      LAYER M4 ;
        RECT  0 37.296 0.084 37.32 ;
    END
  END dn_i[118]
  PIN dn_i[119]
    DIRECTION INPUT ;
    USE SIGNAL ;
    PORT
      LAYER M4 ;
        RECT  0 37.392 0.084 37.416 ;
    END
  END dn_i[119]
  PIN dn_i[11]
    DIRECTION INPUT ;
    USE SIGNAL ;
    PORT
      LAYER M4 ;
        RECT  0 30.096 0.084 30.12 ;
    END
  END dn_i[11]
  PIN dn_i[120]
    DIRECTION INPUT ;
    USE SIGNAL ;
    PORT
      LAYER M4 ;
        RECT  0 37.488 0.084 37.512 ;
    END
  END dn_i[120]
  PIN dn_i[121]
    DIRECTION INPUT ;
    USE SIGNAL ;
    PORT
      LAYER M4 ;
        RECT  0 37.584 0.084 37.608 ;
    END
  END dn_i[121]
  PIN dn_i[122]
    DIRECTION INPUT ;
    USE SIGNAL ;
    PORT
      LAYER M4 ;
        RECT  0 37.68 0.084 37.704 ;
    END
  END dn_i[122]
  PIN dn_i[123]
    DIRECTION INPUT ;
    USE SIGNAL ;
    PORT
      LAYER M4 ;
        RECT  0 37.776 0.084 37.8 ;
    END
  END dn_i[123]
  PIN dn_i[124]
    DIRECTION INPUT ;
    USE SIGNAL ;
    PORT
      LAYER M4 ;
        RECT  0 37.872 0.084 37.896 ;
    END
  END dn_i[124]
  PIN dn_i[125]
    DIRECTION INPUT ;
    USE SIGNAL ;
    PORT
      LAYER M4 ;
        RECT  0 37.968 0.084 37.992 ;
    END
  END dn_i[125]
  PIN dn_i[126]
    DIRECTION INPUT ;
    USE SIGNAL ;
    PORT
      LAYER M4 ;
        RECT  0 38.064 0.084 38.088 ;
    END
  END dn_i[126]
  PIN dn_i[127]
    DIRECTION INPUT ;
    USE SIGNAL ;
    PORT
      LAYER M4 ;
        RECT  0 38.16 0.084 38.184 ;
    END
  END dn_i[127]
  PIN dn_i[128]
    DIRECTION INPUT ;
    USE SIGNAL ;
    PORT
      LAYER M4 ;
        RECT  0 38.256 0.084 38.28 ;
    END
  END dn_i[128]
  PIN dn_i[129]
    DIRECTION INPUT ;
    USE SIGNAL ;
    PORT
      LAYER M4 ;
        RECT  0 38.352 0.084 38.376 ;
    END
  END dn_i[129]
  PIN dn_i[12]
    DIRECTION INPUT ;
    USE SIGNAL ;
    PORT
      LAYER M4 ;
        RECT  0 30.192 0.084 30.216 ;
    END
  END dn_i[12]
  PIN dn_i[130]
    DIRECTION INPUT ;
    USE SIGNAL ;
    PORT
      LAYER M4 ;
        RECT  0 38.448 0.084 38.472 ;
    END
  END dn_i[130]
  PIN dn_i[131]
    DIRECTION INPUT ;
    USE SIGNAL ;
    PORT
      LAYER M4 ;
        RECT  0 38.544 0.084 38.568 ;
    END
  END dn_i[131]
  PIN dn_i[132]
    DIRECTION INPUT ;
    USE SIGNAL ;
    PORT
      LAYER M4 ;
        RECT  0 38.64 0.084 38.664 ;
    END
  END dn_i[132]
  PIN dn_i[133]
    DIRECTION INPUT ;
    USE SIGNAL ;
    PORT
      LAYER M4 ;
        RECT  0 27.984 0.084 28.008 ;
    END
  END dn_i[133]
  PIN dn_i[134]
    DIRECTION INPUT ;
    USE SIGNAL ;
    PORT
      LAYER M4 ;
        RECT  0 28.08 0.084 28.104 ;
    END
  END dn_i[134]
  PIN dn_i[135]
    DIRECTION INPUT ;
    USE SIGNAL ;
    PORT
      LAYER M4 ;
        RECT  0 28.176 0.084 28.2 ;
    END
  END dn_i[135]
  PIN dn_i[136]
    DIRECTION INPUT ;
    USE SIGNAL ;
    PORT
      LAYER M4 ;
        RECT  0 28.272 0.084 28.296 ;
    END
  END dn_i[136]
  PIN dn_i[137]
    DIRECTION INPUT ;
    USE SIGNAL ;
    PORT
      LAYER M4 ;
        RECT  0 28.368 0.084 28.392 ;
    END
  END dn_i[137]
  PIN dn_i[138]
    DIRECTION INPUT ;
    USE SIGNAL ;
    PORT
      LAYER M4 ;
        RECT  0 28.464 0.084 28.488 ;
    END
  END dn_i[138]
  PIN dn_i[139]
    DIRECTION INPUT ;
    USE SIGNAL ;
    PORT
      LAYER M4 ;
        RECT  0 28.56 0.084 28.584 ;
    END
  END dn_i[139]
  PIN dn_i[13]
    DIRECTION INPUT ;
    USE SIGNAL ;
    PORT
      LAYER M4 ;
        RECT  0 30.288 0.084 30.312 ;
    END
  END dn_i[13]
  PIN dn_i[14]
    DIRECTION INPUT ;
    USE SIGNAL ;
    PORT
      LAYER M4 ;
        RECT  0 30.384 0.084 30.408 ;
    END
  END dn_i[14]
  PIN dn_i[15]
    DIRECTION INPUT ;
    USE SIGNAL ;
    PORT
      LAYER M4 ;
        RECT  0 30.48 0.084 30.504 ;
    END
  END dn_i[15]
  PIN dn_i[16]
    DIRECTION INPUT ;
    USE SIGNAL ;
    PORT
      LAYER M4 ;
        RECT  0 30.576 0.084 30.6 ;
    END
  END dn_i[16]
  PIN dn_i[17]
    DIRECTION INPUT ;
    USE SIGNAL ;
    PORT
      LAYER M4 ;
        RECT  0 30.672 0.084 30.696 ;
    END
  END dn_i[17]
  PIN dn_i[18]
    DIRECTION INPUT ;
    USE SIGNAL ;
    PORT
      LAYER M4 ;
        RECT  0 30.768 0.084 30.792 ;
    END
  END dn_i[18]
  PIN dn_i[19]
    DIRECTION INPUT ;
    USE SIGNAL ;
    PORT
      LAYER M4 ;
        RECT  0 30.864 0.084 30.888 ;
    END
  END dn_i[19]
  PIN dn_i[1]
    DIRECTION INPUT ;
    USE SIGNAL ;
    PORT
      LAYER M4 ;
        RECT  0 41.424 0.084 41.448 ;
    END
  END dn_i[1]
  PIN dn_i[20]
    DIRECTION INPUT ;
    USE SIGNAL ;
    PORT
      LAYER M4 ;
        RECT  0 30.96 0.084 30.984 ;
    END
  END dn_i[20]
  PIN dn_i[21]
    DIRECTION INPUT ;
    USE SIGNAL ;
    PORT
      LAYER M4 ;
        RECT  0 31.056 0.084 31.08 ;
    END
  END dn_i[21]
  PIN dn_i[22]
    DIRECTION INPUT ;
    USE SIGNAL ;
    PORT
      LAYER M4 ;
        RECT  0 31.152 0.084 31.176 ;
    END
  END dn_i[22]
  PIN dn_i[23]
    DIRECTION INPUT ;
    USE SIGNAL ;
    PORT
      LAYER M4 ;
        RECT  0 31.248 0.084 31.272 ;
    END
  END dn_i[23]
  PIN dn_i[24]
    DIRECTION INPUT ;
    USE SIGNAL ;
    PORT
      LAYER M4 ;
        RECT  0 31.344 0.084 31.368 ;
    END
  END dn_i[24]
  PIN dn_i[25]
    DIRECTION INPUT ;
    USE SIGNAL ;
    PORT
      LAYER M4 ;
        RECT  0 31.44 0.084 31.464 ;
    END
  END dn_i[25]
  PIN dn_i[26]
    DIRECTION INPUT ;
    USE SIGNAL ;
    PORT
      LAYER M4 ;
        RECT  0 31.536 0.084 31.56 ;
    END
  END dn_i[26]
  PIN dn_i[27]
    DIRECTION INPUT ;
    USE SIGNAL ;
    PORT
      LAYER M4 ;
        RECT  0 31.632 0.084 31.656 ;
    END
  END dn_i[27]
  PIN dn_i[28]
    DIRECTION INPUT ;
    USE SIGNAL ;
    PORT
      LAYER M4 ;
        RECT  0 31.728 0.084 31.752 ;
    END
  END dn_i[28]
  PIN dn_i[29]
    DIRECTION INPUT ;
    USE SIGNAL ;
    PORT
      LAYER M4 ;
        RECT  0 31.824 0.084 31.848 ;
    END
  END dn_i[29]
  PIN dn_i[2]
    DIRECTION INPUT ;
    USE SIGNAL ;
    PORT
      LAYER M4 ;
        RECT  0 41.52 0.084 41.544 ;
    END
  END dn_i[2]
  PIN dn_i[30]
    DIRECTION INPUT ;
    USE SIGNAL ;
    PORT
      LAYER M4 ;
        RECT  0 31.92 0.084 31.944 ;
    END
  END dn_i[30]
  PIN dn_i[31]
    DIRECTION INPUT ;
    USE SIGNAL ;
    PORT
      LAYER M4 ;
        RECT  0 32.016 0.084 32.04 ;
    END
  END dn_i[31]
  PIN dn_i[32]
    DIRECTION INPUT ;
    USE SIGNAL ;
    PORT
      LAYER M4 ;
        RECT  0 32.112 0.084 32.136 ;
    END
  END dn_i[32]
  PIN dn_i[33]
    DIRECTION INPUT ;
    USE SIGNAL ;
    PORT
      LAYER M4 ;
        RECT  0 32.208 0.084 32.232 ;
    END
  END dn_i[33]
  PIN dn_i[34]
    DIRECTION INPUT ;
    USE SIGNAL ;
    PORT
      LAYER M4 ;
        RECT  0 32.304 0.084 32.328 ;
    END
  END dn_i[34]
  PIN dn_i[35]
    DIRECTION INPUT ;
    USE SIGNAL ;
    PORT
      LAYER M4 ;
        RECT  0 32.4 0.084 32.424 ;
    END
  END dn_i[35]
  PIN dn_i[36]
    DIRECTION INPUT ;
    USE SIGNAL ;
    PORT
      LAYER M4 ;
        RECT  0 32.496 0.084 32.52 ;
    END
  END dn_i[36]
  PIN dn_i[37]
    DIRECTION INPUT ;
    USE SIGNAL ;
    PORT
      LAYER M4 ;
        RECT  0 32.592 0.084 32.616 ;
    END
  END dn_i[37]
  PIN dn_i[38]
    DIRECTION INPUT ;
    USE SIGNAL ;
    PORT
      LAYER M4 ;
        RECT  0 32.688 0.084 32.712 ;
    END
  END dn_i[38]
  PIN dn_i[39]
    DIRECTION INPUT ;
    USE SIGNAL ;
    PORT
      LAYER M4 ;
        RECT  0 32.784 0.084 32.808 ;
    END
  END dn_i[39]
  PIN dn_i[3]
    DIRECTION INPUT ;
    USE SIGNAL ;
    PORT
      LAYER M4 ;
        RECT  0 41.616 0.084 41.64 ;
    END
  END dn_i[3]
  PIN dn_i[40]
    DIRECTION INPUT ;
    USE SIGNAL ;
    PORT
      LAYER M4 ;
        RECT  0 32.88 0.084 32.904 ;
    END
  END dn_i[40]
  PIN dn_i[41]
    DIRECTION INPUT ;
    USE SIGNAL ;
    PORT
      LAYER M4 ;
        RECT  0 32.976 0.084 33 ;
    END
  END dn_i[41]
  PIN dn_i[42]
    DIRECTION INPUT ;
    USE SIGNAL ;
    PORT
      LAYER M4 ;
        RECT  0 33.072 0.084 33.096 ;
    END
  END dn_i[42]
  PIN dn_i[43]
    DIRECTION INPUT ;
    USE SIGNAL ;
    PORT
      LAYER M4 ;
        RECT  0 33.168 0.084 33.192 ;
    END
  END dn_i[43]
  PIN dn_i[44]
    DIRECTION INPUT ;
    USE SIGNAL ;
    PORT
      LAYER M4 ;
        RECT  0 33.264 0.084 33.288 ;
    END
  END dn_i[44]
  PIN dn_i[45]
    DIRECTION INPUT ;
    USE SIGNAL ;
    PORT
      LAYER M4 ;
        RECT  0 33.36 0.084 33.384 ;
    END
  END dn_i[45]
  PIN dn_i[46]
    DIRECTION INPUT ;
    USE SIGNAL ;
    PORT
      LAYER M4 ;
        RECT  0 33.456 0.084 33.48 ;
    END
  END dn_i[46]
  PIN dn_i[47]
    DIRECTION INPUT ;
    USE SIGNAL ;
    PORT
      LAYER M4 ;
        RECT  0 33.552 0.084 33.576 ;
    END
  END dn_i[47]
  PIN dn_i[48]
    DIRECTION INPUT ;
    USE SIGNAL ;
    PORT
      LAYER M4 ;
        RECT  0 33.648 0.084 33.672 ;
    END
  END dn_i[48]
  PIN dn_i[49]
    DIRECTION INPUT ;
    USE SIGNAL ;
    PORT
      LAYER M4 ;
        RECT  0 33.744 0.084 33.768 ;
    END
  END dn_i[49]
  PIN dn_i[4]
    DIRECTION INPUT ;
    USE SIGNAL ;
    PORT
      LAYER M4 ;
        RECT  0 41.712 0.084 41.736 ;
    END
  END dn_i[4]
  PIN dn_i[50]
    DIRECTION INPUT ;
    USE SIGNAL ;
    PORT
      LAYER M4 ;
        RECT  0 33.84 0.084 33.864 ;
    END
  END dn_i[50]
  PIN dn_i[51]
    DIRECTION INPUT ;
    USE SIGNAL ;
    PORT
      LAYER M4 ;
        RECT  0 33.936 0.084 33.96 ;
    END
  END dn_i[51]
  PIN dn_i[52]
    DIRECTION INPUT ;
    USE SIGNAL ;
    PORT
      LAYER M4 ;
        RECT  0 34.032 0.084 34.056 ;
    END
  END dn_i[52]
  PIN dn_i[53]
    DIRECTION INPUT ;
    USE SIGNAL ;
    PORT
      LAYER M4 ;
        RECT  0 34.128 0.084 34.152 ;
    END
  END dn_i[53]
  PIN dn_i[54]
    DIRECTION INPUT ;
    USE SIGNAL ;
    PORT
      LAYER M4 ;
        RECT  0 34.224 0.084 34.248 ;
    END
  END dn_i[54]
  PIN dn_i[55]
    DIRECTION INPUT ;
    USE SIGNAL ;
    PORT
      LAYER M4 ;
        RECT  0 34.32 0.084 34.344 ;
    END
  END dn_i[55]
  PIN dn_i[56]
    DIRECTION INPUT ;
    USE SIGNAL ;
    PORT
      LAYER M4 ;
        RECT  0 34.416 0.084 34.44 ;
    END
  END dn_i[56]
  PIN dn_i[57]
    DIRECTION INPUT ;
    USE SIGNAL ;
    PORT
      LAYER M4 ;
        RECT  0 34.512 0.084 34.536 ;
    END
  END dn_i[57]
  PIN dn_i[58]
    DIRECTION INPUT ;
    USE SIGNAL ;
    PORT
      LAYER M4 ;
        RECT  0 34.608 0.084 34.632 ;
    END
  END dn_i[58]
  PIN dn_i[59]
    DIRECTION INPUT ;
    USE SIGNAL ;
    PORT
      LAYER M4 ;
        RECT  0 34.704 0.084 34.728 ;
    END
  END dn_i[59]
  PIN dn_i[5]
    DIRECTION INPUT ;
    USE SIGNAL ;
    PORT
      LAYER M4 ;
        RECT  0 29.52 0.084 29.544 ;
    END
  END dn_i[5]
  PIN dn_i[60]
    DIRECTION INPUT ;
    USE SIGNAL ;
    PORT
      LAYER M4 ;
        RECT  0 34.8 0.084 34.824 ;
    END
  END dn_i[60]
  PIN dn_i[61]
    DIRECTION INPUT ;
    USE SIGNAL ;
    PORT
      LAYER M4 ;
        RECT  0 34.896 0.084 34.92 ;
    END
  END dn_i[61]
  PIN dn_i[62]
    DIRECTION INPUT ;
    USE SIGNAL ;
    PORT
      LAYER M4 ;
        RECT  0 34.992 0.084 35.016 ;
    END
  END dn_i[62]
  PIN dn_i[63]
    DIRECTION INPUT ;
    USE SIGNAL ;
    PORT
      LAYER M4 ;
        RECT  0 35.088 0.084 35.112 ;
    END
  END dn_i[63]
  PIN dn_i[64]
    DIRECTION INPUT ;
    USE SIGNAL ;
    PORT
      LAYER M4 ;
        RECT  0 35.184 0.084 35.208 ;
    END
  END dn_i[64]
  PIN dn_i[65]
    DIRECTION INPUT ;
    USE SIGNAL ;
    PORT
      LAYER M4 ;
        RECT  0 35.28 0.084 35.304 ;
    END
  END dn_i[65]
  PIN dn_i[66]
    DIRECTION INPUT ;
    USE SIGNAL ;
    PORT
      LAYER M4 ;
        RECT  0 35.376 0.084 35.4 ;
    END
  END dn_i[66]
  PIN dn_i[67]
    DIRECTION INPUT ;
    USE SIGNAL ;
    PORT
      LAYER M4 ;
        RECT  0 35.472 0.084 35.496 ;
    END
  END dn_i[67]
  PIN dn_i[68]
    DIRECTION INPUT ;
    USE SIGNAL ;
    PORT
      LAYER M4 ;
        RECT  0 35.568 0.084 35.592 ;
    END
  END dn_i[68]
  PIN dn_i[69]
    DIRECTION INPUT ;
    USE SIGNAL ;
    PORT
      LAYER M4 ;
        RECT  0 22.608 0.084 22.632 ;
    END
  END dn_i[69]
  PIN dn_i[6]
    DIRECTION INPUT ;
    USE SIGNAL ;
    PORT
      LAYER M4 ;
        RECT  0 29.616 0.084 29.64 ;
    END
  END dn_i[6]
  PIN dn_i[70]
    DIRECTION INPUT ;
    USE SIGNAL ;
    PORT
      LAYER M4 ;
        RECT  0 22.704 0.084 22.728 ;
    END
  END dn_i[70]
  PIN dn_i[71]
    DIRECTION INPUT ;
    USE SIGNAL ;
    PORT
      LAYER M4 ;
        RECT  0 22.8 0.084 22.824 ;
    END
  END dn_i[71]
  PIN dn_i[72]
    DIRECTION INPUT ;
    USE SIGNAL ;
    PORT
      LAYER M4 ;
        RECT  0 22.896 0.084 22.92 ;
    END
  END dn_i[72]
  PIN dn_i[73]
    DIRECTION INPUT ;
    USE SIGNAL ;
    PORT
      LAYER M4 ;
        RECT  0 22.992 0.084 23.016 ;
    END
  END dn_i[73]
  PIN dn_i[74]
    DIRECTION INPUT ;
    USE SIGNAL ;
    PORT
      LAYER M4 ;
        RECT  0 23.088 0.084 23.112 ;
    END
  END dn_i[74]
  PIN dn_i[75]
    DIRECTION INPUT ;
    USE SIGNAL ;
    PORT
      LAYER M4 ;
        RECT  0 23.184 0.084 23.208 ;
    END
  END dn_i[75]
  PIN dn_i[76]
    DIRECTION INPUT ;
    USE SIGNAL ;
    PORT
      LAYER M4 ;
        RECT  0 23.28 0.084 23.304 ;
    END
  END dn_i[76]
  PIN dn_i[77]
    DIRECTION INPUT ;
    USE SIGNAL ;
    PORT
      LAYER M4 ;
        RECT  0 23.376 0.084 23.4 ;
    END
  END dn_i[77]
  PIN dn_i[78]
    DIRECTION INPUT ;
    USE SIGNAL ;
    PORT
      LAYER M4 ;
        RECT  0 23.472 0.084 23.496 ;
    END
  END dn_i[78]
  PIN dn_i[79]
    DIRECTION INPUT ;
    USE SIGNAL ;
    PORT
      LAYER M4 ;
        RECT  0 23.568 0.084 23.592 ;
    END
  END dn_i[79]
  PIN dn_i[7]
    DIRECTION INPUT ;
    USE SIGNAL ;
    PORT
      LAYER M4 ;
        RECT  0 29.712 0.084 29.736 ;
    END
  END dn_i[7]
  PIN dn_i[80]
    DIRECTION INPUT ;
    USE SIGNAL ;
    PORT
      LAYER M4 ;
        RECT  0 23.664 0.084 23.688 ;
    END
  END dn_i[80]
  PIN dn_i[81]
    DIRECTION INPUT ;
    USE SIGNAL ;
    PORT
      LAYER M4 ;
        RECT  0 23.76 0.084 23.784 ;
    END
  END dn_i[81]
  PIN dn_i[82]
    DIRECTION INPUT ;
    USE SIGNAL ;
    PORT
      LAYER M4 ;
        RECT  0 23.856 0.084 23.88 ;
    END
  END dn_i[82]
  PIN dn_i[83]
    DIRECTION INPUT ;
    USE SIGNAL ;
    PORT
      LAYER M4 ;
        RECT  0 23.952 0.084 23.976 ;
    END
  END dn_i[83]
  PIN dn_i[84]
    DIRECTION INPUT ;
    USE SIGNAL ;
    PORT
      LAYER M4 ;
        RECT  0 24.048 0.084 24.072 ;
    END
  END dn_i[84]
  PIN dn_i[85]
    DIRECTION INPUT ;
    USE SIGNAL ;
    PORT
      LAYER M4 ;
        RECT  0 24.144 0.084 24.168 ;
    END
  END dn_i[85]
  PIN dn_i[86]
    DIRECTION INPUT ;
    USE SIGNAL ;
    PORT
      LAYER M4 ;
        RECT  0 24.24 0.084 24.264 ;
    END
  END dn_i[86]
  PIN dn_i[87]
    DIRECTION INPUT ;
    USE SIGNAL ;
    PORT
      LAYER M4 ;
        RECT  0 24.336 0.084 24.36 ;
    END
  END dn_i[87]
  PIN dn_i[88]
    DIRECTION INPUT ;
    USE SIGNAL ;
    PORT
      LAYER M4 ;
        RECT  0 24.432 0.084 24.456 ;
    END
  END dn_i[88]
  PIN dn_i[89]
    DIRECTION INPUT ;
    USE SIGNAL ;
    PORT
      LAYER M4 ;
        RECT  0 24.528 0.084 24.552 ;
    END
  END dn_i[89]
  PIN dn_i[8]
    DIRECTION INPUT ;
    USE SIGNAL ;
    PORT
      LAYER M4 ;
        RECT  0 29.808 0.084 29.832 ;
    END
  END dn_i[8]
  PIN dn_i[90]
    DIRECTION INPUT ;
    USE SIGNAL ;
    PORT
      LAYER M4 ;
        RECT  0 24.624 0.084 24.648 ;
    END
  END dn_i[90]
  PIN dn_i[91]
    DIRECTION INPUT ;
    USE SIGNAL ;
    PORT
      LAYER M4 ;
        RECT  0 24.72 0.084 24.744 ;
    END
  END dn_i[91]
  PIN dn_i[92]
    DIRECTION INPUT ;
    USE SIGNAL ;
    PORT
      LAYER M4 ;
        RECT  0 24.816 0.084 24.84 ;
    END
  END dn_i[92]
  PIN dn_i[93]
    DIRECTION INPUT ;
    USE SIGNAL ;
    PORT
      LAYER M4 ;
        RECT  0 24.912 0.084 24.936 ;
    END
  END dn_i[93]
  PIN dn_i[94]
    DIRECTION INPUT ;
    USE SIGNAL ;
    PORT
      LAYER M4 ;
        RECT  0 25.008 0.084 25.032 ;
    END
  END dn_i[94]
  PIN dn_i[95]
    DIRECTION INPUT ;
    USE SIGNAL ;
    PORT
      LAYER M4 ;
        RECT  0 25.104 0.084 25.128 ;
    END
  END dn_i[95]
  PIN dn_i[96]
    DIRECTION INPUT ;
    USE SIGNAL ;
    PORT
      LAYER M4 ;
        RECT  0 25.2 0.084 25.224 ;
    END
  END dn_i[96]
  PIN dn_i[97]
    DIRECTION INPUT ;
    USE SIGNAL ;
    PORT
      LAYER M4 ;
        RECT  0 25.296 0.084 25.32 ;
    END
  END dn_i[97]
  PIN dn_i[98]
    DIRECTION INPUT ;
    USE SIGNAL ;
    PORT
      LAYER M4 ;
        RECT  0 25.392 0.084 25.416 ;
    END
  END dn_i[98]
  PIN dn_i[99]
    DIRECTION INPUT ;
    USE SIGNAL ;
    PORT
      LAYER M4 ;
        RECT  0 25.488 0.084 25.512 ;
    END
  END dn_i[99]
  PIN dn_i[9]
    DIRECTION INPUT ;
    USE SIGNAL ;
    PORT
      LAYER M4 ;
        RECT  0 29.904 0.084 29.928 ;
    END
  END dn_i[9]
  PIN dn_o[0]
    DIRECTION OUTPUT ;
    USE SIGNAL ;
    PORT
      LAYER M5 ;
        RECT  32.016 64.716 32.04 64.8 ;
    END
  END dn_o[0]
  PIN dn_o[100]
    DIRECTION OUTPUT ;
    USE SIGNAL ;
    PORT
      LAYER M5 ;
        RECT  38.544 64.716 38.568 64.8 ;
    END
  END dn_o[100]
  PIN dn_o[101]
    DIRECTION OUTPUT ;
    USE SIGNAL ;
    PORT
      LAYER M5 ;
        RECT  38.64 64.716 38.664 64.8 ;
    END
  END dn_o[101]
  PIN dn_o[102]
    DIRECTION OUTPUT ;
    USE SIGNAL ;
    PORT
      LAYER M5 ;
        RECT  22.608 64.716 22.632 64.8 ;
    END
  END dn_o[102]
  PIN dn_o[103]
    DIRECTION OUTPUT ;
    USE SIGNAL ;
    PORT
      LAYER M5 ;
        RECT  22.704 64.716 22.728 64.8 ;
    END
  END dn_o[103]
  PIN dn_o[104]
    DIRECTION OUTPUT ;
    USE SIGNAL ;
    PORT
      LAYER M5 ;
        RECT  22.8 64.716 22.824 64.8 ;
    END
  END dn_o[104]
  PIN dn_o[105]
    DIRECTION OUTPUT ;
    USE SIGNAL ;
    PORT
      LAYER M5 ;
        RECT  22.896 64.716 22.92 64.8 ;
    END
  END dn_o[105]
  PIN dn_o[106]
    DIRECTION OUTPUT ;
    USE SIGNAL ;
    PORT
      LAYER M5 ;
        RECT  22.992 64.716 23.016 64.8 ;
    END
  END dn_o[106]
  PIN dn_o[107]
    DIRECTION OUTPUT ;
    USE SIGNAL ;
    PORT
      LAYER M5 ;
        RECT  23.088 64.716 23.112 64.8 ;
    END
  END dn_o[107]
  PIN dn_o[108]
    DIRECTION OUTPUT ;
    USE SIGNAL ;
    PORT
      LAYER M5 ;
        RECT  23.184 64.716 23.208 64.8 ;
    END
  END dn_o[108]
  PIN dn_o[109]
    DIRECTION OUTPUT ;
    USE SIGNAL ;
    PORT
      LAYER M5 ;
        RECT  23.28 64.716 23.304 64.8 ;
    END
  END dn_o[109]
  PIN dn_o[10]
    DIRECTION OUTPUT ;
    USE SIGNAL ;
    PORT
      LAYER M5 ;
        RECT  42.192 64.716 42.216 64.8 ;
    END
  END dn_o[10]
  PIN dn_o[110]
    DIRECTION OUTPUT ;
    USE SIGNAL ;
    PORT
      LAYER M5 ;
        RECT  23.376 64.716 23.4 64.8 ;
    END
  END dn_o[110]
  PIN dn_o[111]
    DIRECTION OUTPUT ;
    USE SIGNAL ;
    PORT
      LAYER M5 ;
        RECT  23.472 64.716 23.496 64.8 ;
    END
  END dn_o[111]
  PIN dn_o[112]
    DIRECTION OUTPUT ;
    USE SIGNAL ;
    PORT
      LAYER M5 ;
        RECT  23.568 64.716 23.592 64.8 ;
    END
  END dn_o[112]
  PIN dn_o[113]
    DIRECTION OUTPUT ;
    USE SIGNAL ;
    PORT
      LAYER M5 ;
        RECT  23.664 64.716 23.688 64.8 ;
    END
  END dn_o[113]
  PIN dn_o[114]
    DIRECTION OUTPUT ;
    USE SIGNAL ;
    PORT
      LAYER M5 ;
        RECT  23.76 64.716 23.784 64.8 ;
    END
  END dn_o[114]
  PIN dn_o[115]
    DIRECTION OUTPUT ;
    USE SIGNAL ;
    PORT
      LAYER M5 ;
        RECT  23.856 64.716 23.88 64.8 ;
    END
  END dn_o[115]
  PIN dn_o[116]
    DIRECTION OUTPUT ;
    USE SIGNAL ;
    PORT
      LAYER M5 ;
        RECT  23.952 64.716 23.976 64.8 ;
    END
  END dn_o[116]
  PIN dn_o[117]
    DIRECTION OUTPUT ;
    USE SIGNAL ;
    PORT
      LAYER M5 ;
        RECT  24.048 64.716 24.072 64.8 ;
    END
  END dn_o[117]
  PIN dn_o[118]
    DIRECTION OUTPUT ;
    USE SIGNAL ;
    PORT
      LAYER M5 ;
        RECT  24.144 64.716 24.168 64.8 ;
    END
  END dn_o[118]
  PIN dn_o[119]
    DIRECTION OUTPUT ;
    USE SIGNAL ;
    PORT
      LAYER M5 ;
        RECT  24.24 64.716 24.264 64.8 ;
    END
  END dn_o[119]
  PIN dn_o[11]
    DIRECTION OUTPUT ;
    USE SIGNAL ;
    PORT
      LAYER M5 ;
        RECT  42.288 64.716 42.312 64.8 ;
    END
  END dn_o[11]
  PIN dn_o[120]
    DIRECTION OUTPUT ;
    USE SIGNAL ;
    PORT
      LAYER M5 ;
        RECT  24.336 64.716 24.36 64.8 ;
    END
  END dn_o[120]
  PIN dn_o[121]
    DIRECTION OUTPUT ;
    USE SIGNAL ;
    PORT
      LAYER M5 ;
        RECT  24.432 64.716 24.456 64.8 ;
    END
  END dn_o[121]
  PIN dn_o[122]
    DIRECTION OUTPUT ;
    USE SIGNAL ;
    PORT
      LAYER M5 ;
        RECT  24.528 64.716 24.552 64.8 ;
    END
  END dn_o[122]
  PIN dn_o[123]
    DIRECTION OUTPUT ;
    USE SIGNAL ;
    PORT
      LAYER M5 ;
        RECT  24.624 64.716 24.648 64.8 ;
    END
  END dn_o[123]
  PIN dn_o[124]
    DIRECTION OUTPUT ;
    USE SIGNAL ;
    PORT
      LAYER M5 ;
        RECT  24.72 64.716 24.744 64.8 ;
    END
  END dn_o[124]
  PIN dn_o[125]
    DIRECTION OUTPUT ;
    USE SIGNAL ;
    PORT
      LAYER M5 ;
        RECT  24.816 64.716 24.84 64.8 ;
    END
  END dn_o[125]
  PIN dn_o[126]
    DIRECTION OUTPUT ;
    USE SIGNAL ;
    PORT
      LAYER M5 ;
        RECT  24.912 64.716 24.936 64.8 ;
    END
  END dn_o[126]
  PIN dn_o[127]
    DIRECTION OUTPUT ;
    USE SIGNAL ;
    PORT
      LAYER M5 ;
        RECT  25.008 64.716 25.032 64.8 ;
    END
  END dn_o[127]
  PIN dn_o[128]
    DIRECTION OUTPUT ;
    USE SIGNAL ;
    PORT
      LAYER M5 ;
        RECT  25.104 64.716 25.128 64.8 ;
    END
  END dn_o[128]
  PIN dn_o[129]
    DIRECTION OUTPUT ;
    USE SIGNAL ;
    PORT
      LAYER M5 ;
        RECT  25.2 64.716 25.224 64.8 ;
    END
  END dn_o[129]
  PIN dn_o[12]
    DIRECTION OUTPUT ;
    USE SIGNAL ;
    PORT
      LAYER M5 ;
        RECT  42.384 64.716 42.408 64.8 ;
    END
  END dn_o[12]
  PIN dn_o[130]
    DIRECTION OUTPUT ;
    USE SIGNAL ;
    PORT
      LAYER M5 ;
        RECT  25.296 64.716 25.32 64.8 ;
    END
  END dn_o[130]
  PIN dn_o[131]
    DIRECTION OUTPUT ;
    USE SIGNAL ;
    PORT
      LAYER M5 ;
        RECT  25.392 64.716 25.416 64.8 ;
    END
  END dn_o[131]
  PIN dn_o[132]
    DIRECTION OUTPUT ;
    USE SIGNAL ;
    PORT
      LAYER M5 ;
        RECT  25.488 64.716 25.512 64.8 ;
    END
  END dn_o[132]
  PIN dn_o[133]
    DIRECTION OUTPUT ;
    USE SIGNAL ;
    PORT
      LAYER M5 ;
        RECT  25.584 64.716 25.608 64.8 ;
    END
  END dn_o[133]
  PIN dn_o[134]
    DIRECTION OUTPUT ;
    USE SIGNAL ;
    PORT
      LAYER M5 ;
        RECT  53.328 64.716 53.352 64.8 ;
    END
  END dn_o[134]
  PIN dn_o[135]
    DIRECTION OUTPUT ;
    USE SIGNAL ;
    PORT
      LAYER M5 ;
        RECT  53.424 64.716 53.448 64.8 ;
    END
  END dn_o[135]
  PIN dn_o[136]
    DIRECTION OUTPUT ;
    USE SIGNAL ;
    PORT
      LAYER M5 ;
        RECT  53.52 64.716 53.544 64.8 ;
    END
  END dn_o[136]
  PIN dn_o[137]
    DIRECTION OUTPUT ;
    USE SIGNAL ;
    PORT
      LAYER M5 ;
        RECT  53.616 64.716 53.64 64.8 ;
    END
  END dn_o[137]
  PIN dn_o[138]
    DIRECTION OUTPUT ;
    USE SIGNAL ;
    PORT
      LAYER M5 ;
        RECT  53.712 64.716 53.736 64.8 ;
    END
  END dn_o[138]
  PIN dn_o[139]
    DIRECTION OUTPUT ;
    USE SIGNAL ;
    PORT
      LAYER M5 ;
        RECT  53.808 64.716 53.832 64.8 ;
    END
  END dn_o[139]
  PIN dn_o[13]
    DIRECTION OUTPUT ;
    USE SIGNAL ;
    PORT
      LAYER M5 ;
        RECT  42.48 64.716 42.504 64.8 ;
    END
  END dn_o[13]
  PIN dn_o[14]
    DIRECTION OUTPUT ;
    USE SIGNAL ;
    PORT
      LAYER M5 ;
        RECT  42.576 64.716 42.6 64.8 ;
    END
  END dn_o[14]
  PIN dn_o[15]
    DIRECTION OUTPUT ;
    USE SIGNAL ;
    PORT
      LAYER M5 ;
        RECT  42.672 64.716 42.696 64.8 ;
    END
  END dn_o[15]
  PIN dn_o[16]
    DIRECTION OUTPUT ;
    USE SIGNAL ;
    PORT
      LAYER M5 ;
        RECT  42.768 64.716 42.792 64.8 ;
    END
  END dn_o[16]
  PIN dn_o[17]
    DIRECTION OUTPUT ;
    USE SIGNAL ;
    PORT
      LAYER M5 ;
        RECT  42.864 64.716 42.888 64.8 ;
    END
  END dn_o[17]
  PIN dn_o[18]
    DIRECTION OUTPUT ;
    USE SIGNAL ;
    PORT
      LAYER M5 ;
        RECT  42.96 64.716 42.984 64.8 ;
    END
  END dn_o[18]
  PIN dn_o[19]
    DIRECTION OUTPUT ;
    USE SIGNAL ;
    PORT
      LAYER M5 ;
        RECT  43.056 64.716 43.08 64.8 ;
    END
  END dn_o[19]
  PIN dn_o[1]
    DIRECTION OUTPUT ;
    USE SIGNAL ;
    PORT
      LAYER M5 ;
        RECT  32.112 64.716 32.136 64.8 ;
    END
  END dn_o[1]
  PIN dn_o[20]
    DIRECTION OUTPUT ;
    USE SIGNAL ;
    PORT
      LAYER M5 ;
        RECT  43.152 64.716 43.176 64.8 ;
    END
  END dn_o[20]
  PIN dn_o[21]
    DIRECTION OUTPUT ;
    USE SIGNAL ;
    PORT
      LAYER M5 ;
        RECT  43.248 64.716 43.272 64.8 ;
    END
  END dn_o[21]
  PIN dn_o[22]
    DIRECTION OUTPUT ;
    USE SIGNAL ;
    PORT
      LAYER M5 ;
        RECT  43.344 64.716 43.368 64.8 ;
    END
  END dn_o[22]
  PIN dn_o[23]
    DIRECTION OUTPUT ;
    USE SIGNAL ;
    PORT
      LAYER M5 ;
        RECT  43.44 64.716 43.464 64.8 ;
    END
  END dn_o[23]
  PIN dn_o[24]
    DIRECTION OUTPUT ;
    USE SIGNAL ;
    PORT
      LAYER M5 ;
        RECT  43.536 64.716 43.56 64.8 ;
    END
  END dn_o[24]
  PIN dn_o[25]
    DIRECTION OUTPUT ;
    USE SIGNAL ;
    PORT
      LAYER M5 ;
        RECT  43.632 64.716 43.656 64.8 ;
    END
  END dn_o[25]
  PIN dn_o[26]
    DIRECTION OUTPUT ;
    USE SIGNAL ;
    PORT
      LAYER M5 ;
        RECT  43.728 64.716 43.752 64.8 ;
    END
  END dn_o[26]
  PIN dn_o[27]
    DIRECTION OUTPUT ;
    USE SIGNAL ;
    PORT
      LAYER M5 ;
        RECT  43.824 64.716 43.848 64.8 ;
    END
  END dn_o[27]
  PIN dn_o[28]
    DIRECTION OUTPUT ;
    USE SIGNAL ;
    PORT
      LAYER M5 ;
        RECT  43.92 64.716 43.944 64.8 ;
    END
  END dn_o[28]
  PIN dn_o[29]
    DIRECTION OUTPUT ;
    USE SIGNAL ;
    PORT
      LAYER M5 ;
        RECT  44.016 64.716 44.04 64.8 ;
    END
  END dn_o[29]
  PIN dn_o[2]
    DIRECTION OUTPUT ;
    USE SIGNAL ;
    PORT
      LAYER M5 ;
        RECT  32.208 64.716 32.232 64.8 ;
    END
  END dn_o[2]
  PIN dn_o[30]
    DIRECTION OUTPUT ;
    USE SIGNAL ;
    PORT
      LAYER M5 ;
        RECT  44.112 64.716 44.136 64.8 ;
    END
  END dn_o[30]
  PIN dn_o[31]
    DIRECTION OUTPUT ;
    USE SIGNAL ;
    PORT
      LAYER M5 ;
        RECT  44.208 64.716 44.232 64.8 ;
    END
  END dn_o[31]
  PIN dn_o[32]
    DIRECTION OUTPUT ;
    USE SIGNAL ;
    PORT
      LAYER M5 ;
        RECT  44.304 64.716 44.328 64.8 ;
    END
  END dn_o[32]
  PIN dn_o[33]
    DIRECTION OUTPUT ;
    USE SIGNAL ;
    PORT
      LAYER M5 ;
        RECT  44.4 64.716 44.424 64.8 ;
    END
  END dn_o[33]
  PIN dn_o[34]
    DIRECTION OUTPUT ;
    USE SIGNAL ;
    PORT
      LAYER M5 ;
        RECT  44.496 64.716 44.52 64.8 ;
    END
  END dn_o[34]
  PIN dn_o[35]
    DIRECTION OUTPUT ;
    USE SIGNAL ;
    PORT
      LAYER M5 ;
        RECT  44.592 64.716 44.616 64.8 ;
    END
  END dn_o[35]
  PIN dn_o[36]
    DIRECTION OUTPUT ;
    USE SIGNAL ;
    PORT
      LAYER M5 ;
        RECT  44.688 64.716 44.712 64.8 ;
    END
  END dn_o[36]
  PIN dn_o[37]
    DIRECTION OUTPUT ;
    USE SIGNAL ;
    PORT
      LAYER M5 ;
        RECT  44.784 64.716 44.808 64.8 ;
    END
  END dn_o[37]
  PIN dn_o[38]
    DIRECTION OUTPUT ;
    USE SIGNAL ;
    PORT
      LAYER M5 ;
        RECT  26.448 64.716 26.472 64.8 ;
    END
  END dn_o[38]
  PIN dn_o[39]
    DIRECTION OUTPUT ;
    USE SIGNAL ;
    PORT
      LAYER M5 ;
        RECT  26.544 64.716 26.568 64.8 ;
    END
  END dn_o[39]
  PIN dn_o[3]
    DIRECTION OUTPUT ;
    USE SIGNAL ;
    PORT
      LAYER M5 ;
        RECT  32.304 64.716 32.328 64.8 ;
    END
  END dn_o[3]
  PIN dn_o[40]
    DIRECTION OUTPUT ;
    USE SIGNAL ;
    PORT
      LAYER M5 ;
        RECT  26.64 64.716 26.664 64.8 ;
    END
  END dn_o[40]
  PIN dn_o[41]
    DIRECTION OUTPUT ;
    USE SIGNAL ;
    PORT
      LAYER M5 ;
        RECT  26.736 64.716 26.76 64.8 ;
    END
  END dn_o[41]
  PIN dn_o[42]
    DIRECTION OUTPUT ;
    USE SIGNAL ;
    PORT
      LAYER M5 ;
        RECT  26.832 64.716 26.856 64.8 ;
    END
  END dn_o[42]
  PIN dn_o[43]
    DIRECTION OUTPUT ;
    USE SIGNAL ;
    PORT
      LAYER M5 ;
        RECT  26.928 64.716 26.952 64.8 ;
    END
  END dn_o[43]
  PIN dn_o[44]
    DIRECTION OUTPUT ;
    USE SIGNAL ;
    PORT
      LAYER M5 ;
        RECT  27.024 64.716 27.048 64.8 ;
    END
  END dn_o[44]
  PIN dn_o[45]
    DIRECTION OUTPUT ;
    USE SIGNAL ;
    PORT
      LAYER M5 ;
        RECT  27.12 64.716 27.144 64.8 ;
    END
  END dn_o[45]
  PIN dn_o[46]
    DIRECTION OUTPUT ;
    USE SIGNAL ;
    PORT
      LAYER M5 ;
        RECT  27.216 64.716 27.24 64.8 ;
    END
  END dn_o[46]
  PIN dn_o[47]
    DIRECTION OUTPUT ;
    USE SIGNAL ;
    PORT
      LAYER M5 ;
        RECT  27.312 64.716 27.336 64.8 ;
    END
  END dn_o[47]
  PIN dn_o[48]
    DIRECTION OUTPUT ;
    USE SIGNAL ;
    PORT
      LAYER M5 ;
        RECT  27.408 64.716 27.432 64.8 ;
    END
  END dn_o[48]
  PIN dn_o[49]
    DIRECTION OUTPUT ;
    USE SIGNAL ;
    PORT
      LAYER M5 ;
        RECT  27.504 64.716 27.528 64.8 ;
    END
  END dn_o[49]
  PIN dn_o[4]
    DIRECTION OUTPUT ;
    USE SIGNAL ;
    PORT
      LAYER M5 ;
        RECT  32.4 64.716 32.424 64.8 ;
    END
  END dn_o[4]
  PIN dn_o[50]
    DIRECTION OUTPUT ;
    USE SIGNAL ;
    PORT
      LAYER M5 ;
        RECT  27.6 64.716 27.624 64.8 ;
    END
  END dn_o[50]
  PIN dn_o[51]
    DIRECTION OUTPUT ;
    USE SIGNAL ;
    PORT
      LAYER M5 ;
        RECT  27.696 64.716 27.72 64.8 ;
    END
  END dn_o[51]
  PIN dn_o[52]
    DIRECTION OUTPUT ;
    USE SIGNAL ;
    PORT
      LAYER M5 ;
        RECT  27.792 64.716 27.816 64.8 ;
    END
  END dn_o[52]
  PIN dn_o[53]
    DIRECTION OUTPUT ;
    USE SIGNAL ;
    PORT
      LAYER M5 ;
        RECT  27.888 64.716 27.912 64.8 ;
    END
  END dn_o[53]
  PIN dn_o[54]
    DIRECTION OUTPUT ;
    USE SIGNAL ;
    PORT
      LAYER M5 ;
        RECT  27.984 64.716 28.008 64.8 ;
    END
  END dn_o[54]
  PIN dn_o[55]
    DIRECTION OUTPUT ;
    USE SIGNAL ;
    PORT
      LAYER M5 ;
        RECT  28.08 64.716 28.104 64.8 ;
    END
  END dn_o[55]
  PIN dn_o[56]
    DIRECTION OUTPUT ;
    USE SIGNAL ;
    PORT
      LAYER M5 ;
        RECT  28.176 64.716 28.2 64.8 ;
    END
  END dn_o[56]
  PIN dn_o[57]
    DIRECTION OUTPUT ;
    USE SIGNAL ;
    PORT
      LAYER M5 ;
        RECT  28.272 64.716 28.296 64.8 ;
    END
  END dn_o[57]
  PIN dn_o[58]
    DIRECTION OUTPUT ;
    USE SIGNAL ;
    PORT
      LAYER M5 ;
        RECT  28.368 64.716 28.392 64.8 ;
    END
  END dn_o[58]
  PIN dn_o[59]
    DIRECTION OUTPUT ;
    USE SIGNAL ;
    PORT
      LAYER M5 ;
        RECT  28.464 64.716 28.488 64.8 ;
    END
  END dn_o[59]
  PIN dn_o[5]
    DIRECTION OUTPUT ;
    USE SIGNAL ;
    PORT
      LAYER M5 ;
        RECT  32.496 64.716 32.52 64.8 ;
    END
  END dn_o[5]
  PIN dn_o[60]
    DIRECTION OUTPUT ;
    USE SIGNAL ;
    PORT
      LAYER M5 ;
        RECT  28.56 64.716 28.584 64.8 ;
    END
  END dn_o[60]
  PIN dn_o[61]
    DIRECTION OUTPUT ;
    USE SIGNAL ;
    PORT
      LAYER M5 ;
        RECT  28.656 64.716 28.68 64.8 ;
    END
  END dn_o[61]
  PIN dn_o[62]
    DIRECTION OUTPUT ;
    USE SIGNAL ;
    PORT
      LAYER M5 ;
        RECT  28.752 64.716 28.776 64.8 ;
    END
  END dn_o[62]
  PIN dn_o[63]
    DIRECTION OUTPUT ;
    USE SIGNAL ;
    PORT
      LAYER M5 ;
        RECT  28.848 64.716 28.872 64.8 ;
    END
  END dn_o[63]
  PIN dn_o[64]
    DIRECTION OUTPUT ;
    USE SIGNAL ;
    PORT
      LAYER M5 ;
        RECT  28.944 64.716 28.968 64.8 ;
    END
  END dn_o[64]
  PIN dn_o[65]
    DIRECTION OUTPUT ;
    USE SIGNAL ;
    PORT
      LAYER M5 ;
        RECT  29.04 64.716 29.064 64.8 ;
    END
  END dn_o[65]
  PIN dn_o[66]
    DIRECTION OUTPUT ;
    USE SIGNAL ;
    PORT
      LAYER M5 ;
        RECT  29.136 64.716 29.16 64.8 ;
    END
  END dn_o[66]
  PIN dn_o[67]
    DIRECTION OUTPUT ;
    USE SIGNAL ;
    PORT
      LAYER M5 ;
        RECT  29.232 64.716 29.256 64.8 ;
    END
  END dn_o[67]
  PIN dn_o[68]
    DIRECTION OUTPUT ;
    USE SIGNAL ;
    PORT
      LAYER M5 ;
        RECT  29.328 64.716 29.352 64.8 ;
    END
  END dn_o[68]
  PIN dn_o[69]
    DIRECTION OUTPUT ;
    USE SIGNAL ;
    PORT
      LAYER M5 ;
        RECT  29.424 64.716 29.448 64.8 ;
    END
  END dn_o[69]
  PIN dn_o[6]
    DIRECTION OUTPUT ;
    USE SIGNAL ;
    PORT
      LAYER M5 ;
        RECT  41.808 64.716 41.832 64.8 ;
    END
  END dn_o[6]
  PIN dn_o[70]
    DIRECTION OUTPUT ;
    USE SIGNAL ;
    PORT
      LAYER M5 ;
        RECT  35.664 64.716 35.688 64.8 ;
    END
  END dn_o[70]
  PIN dn_o[71]
    DIRECTION OUTPUT ;
    USE SIGNAL ;
    PORT
      LAYER M5 ;
        RECT  35.76 64.716 35.784 64.8 ;
    END
  END dn_o[71]
  PIN dn_o[72]
    DIRECTION OUTPUT ;
    USE SIGNAL ;
    PORT
      LAYER M5 ;
        RECT  35.856 64.716 35.88 64.8 ;
    END
  END dn_o[72]
  PIN dn_o[73]
    DIRECTION OUTPUT ;
    USE SIGNAL ;
    PORT
      LAYER M5 ;
        RECT  35.952 64.716 35.976 64.8 ;
    END
  END dn_o[73]
  PIN dn_o[74]
    DIRECTION OUTPUT ;
    USE SIGNAL ;
    PORT
      LAYER M5 ;
        RECT  36.048 64.716 36.072 64.8 ;
    END
  END dn_o[74]
  PIN dn_o[75]
    DIRECTION OUTPUT ;
    USE SIGNAL ;
    PORT
      LAYER M5 ;
        RECT  36.144 64.716 36.168 64.8 ;
    END
  END dn_o[75]
  PIN dn_o[76]
    DIRECTION OUTPUT ;
    USE SIGNAL ;
    PORT
      LAYER M5 ;
        RECT  36.24 64.716 36.264 64.8 ;
    END
  END dn_o[76]
  PIN dn_o[77]
    DIRECTION OUTPUT ;
    USE SIGNAL ;
    PORT
      LAYER M5 ;
        RECT  36.336 64.716 36.36 64.8 ;
    END
  END dn_o[77]
  PIN dn_o[78]
    DIRECTION OUTPUT ;
    USE SIGNAL ;
    PORT
      LAYER M5 ;
        RECT  36.432 64.716 36.456 64.8 ;
    END
  END dn_o[78]
  PIN dn_o[79]
    DIRECTION OUTPUT ;
    USE SIGNAL ;
    PORT
      LAYER M5 ;
        RECT  36.528 64.716 36.552 64.8 ;
    END
  END dn_o[79]
  PIN dn_o[7]
    DIRECTION OUTPUT ;
    USE SIGNAL ;
    PORT
      LAYER M5 ;
        RECT  41.904 64.716 41.928 64.8 ;
    END
  END dn_o[7]
  PIN dn_o[80]
    DIRECTION OUTPUT ;
    USE SIGNAL ;
    PORT
      LAYER M5 ;
        RECT  36.624 64.716 36.648 64.8 ;
    END
  END dn_o[80]
  PIN dn_o[81]
    DIRECTION OUTPUT ;
    USE SIGNAL ;
    PORT
      LAYER M5 ;
        RECT  36.72 64.716 36.744 64.8 ;
    END
  END dn_o[81]
  PIN dn_o[82]
    DIRECTION OUTPUT ;
    USE SIGNAL ;
    PORT
      LAYER M5 ;
        RECT  36.816 64.716 36.84 64.8 ;
    END
  END dn_o[82]
  PIN dn_o[83]
    DIRECTION OUTPUT ;
    USE SIGNAL ;
    PORT
      LAYER M5 ;
        RECT  36.912 64.716 36.936 64.8 ;
    END
  END dn_o[83]
  PIN dn_o[84]
    DIRECTION OUTPUT ;
    USE SIGNAL ;
    PORT
      LAYER M5 ;
        RECT  37.008 64.716 37.032 64.8 ;
    END
  END dn_o[84]
  PIN dn_o[85]
    DIRECTION OUTPUT ;
    USE SIGNAL ;
    PORT
      LAYER M5 ;
        RECT  37.104 64.716 37.128 64.8 ;
    END
  END dn_o[85]
  PIN dn_o[86]
    DIRECTION OUTPUT ;
    USE SIGNAL ;
    PORT
      LAYER M5 ;
        RECT  37.2 64.716 37.224 64.8 ;
    END
  END dn_o[86]
  PIN dn_o[87]
    DIRECTION OUTPUT ;
    USE SIGNAL ;
    PORT
      LAYER M5 ;
        RECT  37.296 64.716 37.32 64.8 ;
    END
  END dn_o[87]
  PIN dn_o[88]
    DIRECTION OUTPUT ;
    USE SIGNAL ;
    PORT
      LAYER M5 ;
        RECT  37.392 64.716 37.416 64.8 ;
    END
  END dn_o[88]
  PIN dn_o[89]
    DIRECTION OUTPUT ;
    USE SIGNAL ;
    PORT
      LAYER M5 ;
        RECT  37.488 64.716 37.512 64.8 ;
    END
  END dn_o[89]
  PIN dn_o[8]
    DIRECTION OUTPUT ;
    USE SIGNAL ;
    PORT
      LAYER M5 ;
        RECT  42 64.716 42.024 64.8 ;
    END
  END dn_o[8]
  PIN dn_o[90]
    DIRECTION OUTPUT ;
    USE SIGNAL ;
    PORT
      LAYER M5 ;
        RECT  37.584 64.716 37.608 64.8 ;
    END
  END dn_o[90]
  PIN dn_o[91]
    DIRECTION OUTPUT ;
    USE SIGNAL ;
    PORT
      LAYER M5 ;
        RECT  37.68 64.716 37.704 64.8 ;
    END
  END dn_o[91]
  PIN dn_o[92]
    DIRECTION OUTPUT ;
    USE SIGNAL ;
    PORT
      LAYER M5 ;
        RECT  37.776 64.716 37.8 64.8 ;
    END
  END dn_o[92]
  PIN dn_o[93]
    DIRECTION OUTPUT ;
    USE SIGNAL ;
    PORT
      LAYER M5 ;
        RECT  37.872 64.716 37.896 64.8 ;
    END
  END dn_o[93]
  PIN dn_o[94]
    DIRECTION OUTPUT ;
    USE SIGNAL ;
    PORT
      LAYER M5 ;
        RECT  37.968 64.716 37.992 64.8 ;
    END
  END dn_o[94]
  PIN dn_o[95]
    DIRECTION OUTPUT ;
    USE SIGNAL ;
    PORT
      LAYER M5 ;
        RECT  38.064 64.716 38.088 64.8 ;
    END
  END dn_o[95]
  PIN dn_o[96]
    DIRECTION OUTPUT ;
    USE SIGNAL ;
    PORT
      LAYER M5 ;
        RECT  38.16 64.716 38.184 64.8 ;
    END
  END dn_o[96]
  PIN dn_o[97]
    DIRECTION OUTPUT ;
    USE SIGNAL ;
    PORT
      LAYER M5 ;
        RECT  38.256 64.716 38.28 64.8 ;
    END
  END dn_o[97]
  PIN dn_o[98]
    DIRECTION OUTPUT ;
    USE SIGNAL ;
    PORT
      LAYER M5 ;
        RECT  38.352 64.716 38.376 64.8 ;
    END
  END dn_o[98]
  PIN dn_o[99]
    DIRECTION OUTPUT ;
    USE SIGNAL ;
    PORT
      LAYER M5 ;
        RECT  38.448 64.716 38.472 64.8 ;
    END
  END dn_o[99]
  PIN dn_o[9]
    DIRECTION OUTPUT ;
    USE SIGNAL ;
    PORT
      LAYER M5 ;
        RECT  42.096 64.716 42.12 64.8 ;
    END
  END dn_o[9]
  PIN fb_i[0]
    DIRECTION INPUT ;
    USE SIGNAL ;
    PORT
      LAYER M4 ;
        RECT  0 28.656 0.084 28.68 ;
    END
  END fb_i[0]
  PIN fb_i[1]
    DIRECTION INPUT ;
    USE SIGNAL ;
    PORT
      LAYER M4 ;
        RECT  0 28.752 0.084 28.776 ;
    END
  END fb_i[1]
  PIN fb_i[2]
    DIRECTION INPUT ;
    USE SIGNAL ;
    PORT
      LAYER M4 ;
        RECT  0 28.848 0.084 28.872 ;
    END
  END fb_i[2]
  PIN fb_i[3]
    DIRECTION INPUT ;
    USE SIGNAL ;
    PORT
      LAYER M4 ;
        RECT  0 28.944 0.084 28.968 ;
    END
  END fb_i[3]
  PIN fb_i[4]
    DIRECTION INPUT ;
    USE SIGNAL ;
    PORT
      LAYER M4 ;
        RECT  0 29.04 0.084 29.064 ;
    END
  END fb_i[4]
  PIN fb_i[5]
    DIRECTION INPUT ;
    USE SIGNAL ;
    PORT
      LAYER M4 ;
        RECT  0 29.136 0.084 29.16 ;
    END
  END fb_i[5]
  PIN fb_i[6]
    DIRECTION INPUT ;
    USE SIGNAL ;
    PORT
      LAYER M4 ;
        RECT  0 29.232 0.084 29.256 ;
    END
  END fb_i[6]
  PIN fb_i[7]
    DIRECTION INPUT ;
    USE SIGNAL ;
    PORT
      LAYER M4 ;
        RECT  0 29.328 0.084 29.352 ;
    END
  END fb_i[7]
  PIN fb_o[0]
    DIRECTION OUTPUT ;
    USE SIGNAL ;
    PORT
      LAYER M5 ;
        RECT  53.904 64.716 53.928 64.8 ;
    END
  END fb_o[0]
  PIN fb_o[1]
    DIRECTION OUTPUT ;
    USE SIGNAL ;
    PORT
      LAYER M5 ;
        RECT  54 64.716 54.024 64.8 ;
    END
  END fb_o[1]
  PIN fb_o[2]
    DIRECTION OUTPUT ;
    USE SIGNAL ;
    PORT
      LAYER M5 ;
        RECT  54.096 64.716 54.12 64.8 ;
    END
  END fb_o[2]
  PIN fb_o[3]
    DIRECTION OUTPUT ;
    USE SIGNAL ;
    PORT
      LAYER M5 ;
        RECT  54.192 64.716 54.216 64.8 ;
    END
  END fb_o[3]
  PIN fb_o[4]
    DIRECTION OUTPUT ;
    USE SIGNAL ;
    PORT
      LAYER M5 ;
        RECT  54.288 64.716 54.312 64.8 ;
    END
  END fb_o[4]
  PIN fb_o[5]
    DIRECTION OUTPUT ;
    USE SIGNAL ;
    PORT
      LAYER M5 ;
        RECT  54.384 64.716 54.408 64.8 ;
    END
  END fb_o[5]
  PIN fb_o[6]
    DIRECTION OUTPUT ;
    USE SIGNAL ;
    PORT
      LAYER M5 ;
        RECT  54.48 64.716 54.504 64.8 ;
    END
  END fb_o[6]
  PIN fb_o[7]
    DIRECTION OUTPUT ;
    USE SIGNAL ;
    PORT
      LAYER M5 ;
        RECT  54.576 64.716 54.6 64.8 ;
    END
  END fb_o[7]
  PIN rst_n
    DIRECTION INPUT ;
    USE SIGNAL ;
    PORT
      LAYER M4 ;
        RECT  0 29.424 0.084 29.448 ;
    END
  END rst_n
  PIN sc_i[0]
    DIRECTION INPUT ;
    USE SIGNAL ;
    PORT
      LAYER M5 ;
        RECT  22.992 0 23.016 0.084 ;
    END
  END sc_i[0]
  PIN sc_i[100]
    DIRECTION INPUT ;
    USE SIGNAL ;
    PORT
      LAYER M5 ;
        RECT  35.664 0 35.688 0.084 ;
    END
  END sc_i[100]
  PIN sc_i[101]
    DIRECTION INPUT ;
    USE SIGNAL ;
    PORT
      LAYER M5 ;
        RECT  35.76 0 35.784 0.084 ;
    END
  END sc_i[101]
  PIN sc_i[102]
    DIRECTION INPUT ;
    USE SIGNAL ;
    PORT
      LAYER M5 ;
        RECT  35.856 0 35.88 0.084 ;
    END
  END sc_i[102]
  PIN sc_i[103]
    DIRECTION INPUT ;
    USE SIGNAL ;
    PORT
      LAYER M5 ;
        RECT  35.952 0 35.976 0.084 ;
    END
  END sc_i[103]
  PIN sc_i[104]
    DIRECTION INPUT ;
    USE SIGNAL ;
    PORT
      LAYER M5 ;
        RECT  36.048 0 36.072 0.084 ;
    END
  END sc_i[104]
  PIN sc_i[105]
    DIRECTION INPUT ;
    USE SIGNAL ;
    PORT
      LAYER M5 ;
        RECT  36.144 0 36.168 0.084 ;
    END
  END sc_i[105]
  PIN sc_i[106]
    DIRECTION INPUT ;
    USE SIGNAL ;
    PORT
      LAYER M5 ;
        RECT  36.24 0 36.264 0.084 ;
    END
  END sc_i[106]
  PIN sc_i[107]
    DIRECTION INPUT ;
    USE SIGNAL ;
    PORT
      LAYER M5 ;
        RECT  36.336 0 36.36 0.084 ;
    END
  END sc_i[107]
  PIN sc_i[108]
    DIRECTION INPUT ;
    USE SIGNAL ;
    PORT
      LAYER M5 ;
        RECT  36.432 0 36.456 0.084 ;
    END
  END sc_i[108]
  PIN sc_i[109]
    DIRECTION INPUT ;
    USE SIGNAL ;
    PORT
      LAYER M5 ;
        RECT  36.528 0 36.552 0.084 ;
    END
  END sc_i[109]
  PIN sc_i[10]
    DIRECTION INPUT ;
    USE SIGNAL ;
    PORT
      LAYER M5 ;
        RECT  23.952 0 23.976 0.084 ;
    END
  END sc_i[10]
  PIN sc_i[110]
    DIRECTION INPUT ;
    USE SIGNAL ;
    PORT
      LAYER M5 ;
        RECT  36.624 0 36.648 0.084 ;
    END
  END sc_i[110]
  PIN sc_i[111]
    DIRECTION INPUT ;
    USE SIGNAL ;
    PORT
      LAYER M5 ;
        RECT  36.72 0 36.744 0.084 ;
    END
  END sc_i[111]
  PIN sc_i[112]
    DIRECTION INPUT ;
    USE SIGNAL ;
    PORT
      LAYER M5 ;
        RECT  36.816 0 36.84 0.084 ;
    END
  END sc_i[112]
  PIN sc_i[113]
    DIRECTION INPUT ;
    USE SIGNAL ;
    PORT
      LAYER M5 ;
        RECT  36.912 0 36.936 0.084 ;
    END
  END sc_i[113]
  PIN sc_i[114]
    DIRECTION INPUT ;
    USE SIGNAL ;
    PORT
      LAYER M5 ;
        RECT  37.008 0 37.032 0.084 ;
    END
  END sc_i[114]
  PIN sc_i[115]
    DIRECTION INPUT ;
    USE SIGNAL ;
    PORT
      LAYER M5 ;
        RECT  37.104 0 37.128 0.084 ;
    END
  END sc_i[115]
  PIN sc_i[116]
    DIRECTION INPUT ;
    USE SIGNAL ;
    PORT
      LAYER M5 ;
        RECT  37.2 0 37.224 0.084 ;
    END
  END sc_i[116]
  PIN sc_i[117]
    DIRECTION INPUT ;
    USE SIGNAL ;
    PORT
      LAYER M5 ;
        RECT  37.296 0 37.32 0.084 ;
    END
  END sc_i[117]
  PIN sc_i[118]
    DIRECTION INPUT ;
    USE SIGNAL ;
    PORT
      LAYER M5 ;
        RECT  37.392 0 37.416 0.084 ;
    END
  END sc_i[118]
  PIN sc_i[119]
    DIRECTION INPUT ;
    USE SIGNAL ;
    PORT
      LAYER M5 ;
        RECT  37.488 0 37.512 0.084 ;
    END
  END sc_i[119]
  PIN sc_i[11]
    DIRECTION INPUT ;
    USE SIGNAL ;
    PORT
      LAYER M5 ;
        RECT  24.048 0 24.072 0.084 ;
    END
  END sc_i[11]
  PIN sc_i[120]
    DIRECTION INPUT ;
    USE SIGNAL ;
    PORT
      LAYER M5 ;
        RECT  37.584 0 37.608 0.084 ;
    END
  END sc_i[120]
  PIN sc_i[121]
    DIRECTION INPUT ;
    USE SIGNAL ;
    PORT
      LAYER M5 ;
        RECT  37.68 0 37.704 0.084 ;
    END
  END sc_i[121]
  PIN sc_i[122]
    DIRECTION INPUT ;
    USE SIGNAL ;
    PORT
      LAYER M5 ;
        RECT  37.776 0 37.8 0.084 ;
    END
  END sc_i[122]
  PIN sc_i[123]
    DIRECTION INPUT ;
    USE SIGNAL ;
    PORT
      LAYER M5 ;
        RECT  37.872 0 37.896 0.084 ;
    END
  END sc_i[123]
  PIN sc_i[124]
    DIRECTION INPUT ;
    USE SIGNAL ;
    PORT
      LAYER M5 ;
        RECT  37.968 0 37.992 0.084 ;
    END
  END sc_i[124]
  PIN sc_i[125]
    DIRECTION INPUT ;
    USE SIGNAL ;
    PORT
      LAYER M5 ;
        RECT  38.064 0 38.088 0.084 ;
    END
  END sc_i[125]
  PIN sc_i[126]
    DIRECTION INPUT ;
    USE SIGNAL ;
    PORT
      LAYER M5 ;
        RECT  38.16 0 38.184 0.084 ;
    END
  END sc_i[126]
  PIN sc_i[127]
    DIRECTION INPUT ;
    USE SIGNAL ;
    PORT
      LAYER M5 ;
        RECT  38.256 0 38.28 0.084 ;
    END
  END sc_i[127]
  PIN sc_i[128]
    DIRECTION INPUT ;
    USE SIGNAL ;
    PORT
      LAYER M5 ;
        RECT  26.064 0 26.088 0.084 ;
    END
  END sc_i[128]
  PIN sc_i[129]
    DIRECTION INPUT ;
    USE SIGNAL ;
    PORT
      LAYER M5 ;
        RECT  26.16 0 26.184 0.084 ;
    END
  END sc_i[129]
  PIN sc_i[12]
    DIRECTION INPUT ;
    USE SIGNAL ;
    PORT
      LAYER M5 ;
        RECT  24.144 0 24.168 0.084 ;
    END
  END sc_i[12]
  PIN sc_i[130]
    DIRECTION INPUT ;
    USE SIGNAL ;
    PORT
      LAYER M5 ;
        RECT  26.256 0 26.28 0.084 ;
    END
  END sc_i[130]
  PIN sc_i[131]
    DIRECTION INPUT ;
    USE SIGNAL ;
    PORT
      LAYER M5 ;
        RECT  26.352 0 26.376 0.084 ;
    END
  END sc_i[131]
  PIN sc_i[132]
    DIRECTION INPUT ;
    USE SIGNAL ;
    PORT
      LAYER M5 ;
        RECT  26.448 0 26.472 0.084 ;
    END
  END sc_i[132]
  PIN sc_i[133]
    DIRECTION INPUT ;
    USE SIGNAL ;
    PORT
      LAYER M5 ;
        RECT  26.544 0 26.568 0.084 ;
    END
  END sc_i[133]
  PIN sc_i[134]
    DIRECTION INPUT ;
    USE SIGNAL ;
    PORT
      LAYER M5 ;
        RECT  26.64 0 26.664 0.084 ;
    END
  END sc_i[134]
  PIN sc_i[135]
    DIRECTION INPUT ;
    USE SIGNAL ;
    PORT
      LAYER M5 ;
        RECT  26.736 0 26.76 0.084 ;
    END
  END sc_i[135]
  PIN sc_i[136]
    DIRECTION INPUT ;
    USE SIGNAL ;
    PORT
      LAYER M5 ;
        RECT  26.832 0 26.856 0.084 ;
    END
  END sc_i[136]
  PIN sc_i[137]
    DIRECTION INPUT ;
    USE SIGNAL ;
    PORT
      LAYER M5 ;
        RECT  26.928 0 26.952 0.084 ;
    END
  END sc_i[137]
  PIN sc_i[138]
    DIRECTION INPUT ;
    USE SIGNAL ;
    PORT
      LAYER M5 ;
        RECT  27.024 0 27.048 0.084 ;
    END
  END sc_i[138]
  PIN sc_i[139]
    DIRECTION INPUT ;
    USE SIGNAL ;
    PORT
      LAYER M5 ;
        RECT  27.12 0 27.144 0.084 ;
    END
  END sc_i[139]
  PIN sc_i[13]
    DIRECTION INPUT ;
    USE SIGNAL ;
    PORT
      LAYER M5 ;
        RECT  24.24 0 24.264 0.084 ;
    END
  END sc_i[13]
  PIN sc_i[140]
    DIRECTION INPUT ;
    USE SIGNAL ;
    PORT
      LAYER M5 ;
        RECT  27.216 0 27.24 0.084 ;
    END
  END sc_i[140]
  PIN sc_i[141]
    DIRECTION INPUT ;
    USE SIGNAL ;
    PORT
      LAYER M5 ;
        RECT  27.312 0 27.336 0.084 ;
    END
  END sc_i[141]
  PIN sc_i[142]
    DIRECTION INPUT ;
    USE SIGNAL ;
    PORT
      LAYER M5 ;
        RECT  27.408 0 27.432 0.084 ;
    END
  END sc_i[142]
  PIN sc_i[143]
    DIRECTION INPUT ;
    USE SIGNAL ;
    PORT
      LAYER M5 ;
        RECT  27.504 0 27.528 0.084 ;
    END
  END sc_i[143]
  PIN sc_i[144]
    DIRECTION INPUT ;
    USE SIGNAL ;
    PORT
      LAYER M5 ;
        RECT  27.6 0 27.624 0.084 ;
    END
  END sc_i[144]
  PIN sc_i[145]
    DIRECTION INPUT ;
    USE SIGNAL ;
    PORT
      LAYER M5 ;
        RECT  27.696 0 27.72 0.084 ;
    END
  END sc_i[145]
  PIN sc_i[146]
    DIRECTION INPUT ;
    USE SIGNAL ;
    PORT
      LAYER M5 ;
        RECT  27.792 0 27.816 0.084 ;
    END
  END sc_i[146]
  PIN sc_i[147]
    DIRECTION INPUT ;
    USE SIGNAL ;
    PORT
      LAYER M5 ;
        RECT  27.888 0 27.912 0.084 ;
    END
  END sc_i[147]
  PIN sc_i[148]
    DIRECTION INPUT ;
    USE SIGNAL ;
    PORT
      LAYER M5 ;
        RECT  27.984 0 28.008 0.084 ;
    END
  END sc_i[148]
  PIN sc_i[149]
    DIRECTION INPUT ;
    USE SIGNAL ;
    PORT
      LAYER M5 ;
        RECT  28.08 0 28.104 0.084 ;
    END
  END sc_i[149]
  PIN sc_i[14]
    DIRECTION INPUT ;
    USE SIGNAL ;
    PORT
      LAYER M5 ;
        RECT  24.336 0 24.36 0.084 ;
    END
  END sc_i[14]
  PIN sc_i[150]
    DIRECTION INPUT ;
    USE SIGNAL ;
    PORT
      LAYER M5 ;
        RECT  28.176 0 28.2 0.084 ;
    END
  END sc_i[150]
  PIN sc_i[151]
    DIRECTION INPUT ;
    USE SIGNAL ;
    PORT
      LAYER M5 ;
        RECT  28.272 0 28.296 0.084 ;
    END
  END sc_i[151]
  PIN sc_i[152]
    DIRECTION INPUT ;
    USE SIGNAL ;
    PORT
      LAYER M5 ;
        RECT  28.368 0 28.392 0.084 ;
    END
  END sc_i[152]
  PIN sc_i[153]
    DIRECTION INPUT ;
    USE SIGNAL ;
    PORT
      LAYER M5 ;
        RECT  28.464 0 28.488 0.084 ;
    END
  END sc_i[153]
  PIN sc_i[154]
    DIRECTION INPUT ;
    USE SIGNAL ;
    PORT
      LAYER M5 ;
        RECT  28.56 0 28.584 0.084 ;
    END
  END sc_i[154]
  PIN sc_i[155]
    DIRECTION INPUT ;
    USE SIGNAL ;
    PORT
      LAYER M5 ;
        RECT  28.656 0 28.68 0.084 ;
    END
  END sc_i[155]
  PIN sc_i[156]
    DIRECTION INPUT ;
    USE SIGNAL ;
    PORT
      LAYER M5 ;
        RECT  28.752 0 28.776 0.084 ;
    END
  END sc_i[156]
  PIN sc_i[157]
    DIRECTION INPUT ;
    USE SIGNAL ;
    PORT
      LAYER M5 ;
        RECT  28.848 0 28.872 0.084 ;
    END
  END sc_i[157]
  PIN sc_i[158]
    DIRECTION INPUT ;
    USE SIGNAL ;
    PORT
      LAYER M5 ;
        RECT  28.944 0 28.968 0.084 ;
    END
  END sc_i[158]
  PIN sc_i[159]
    DIRECTION INPUT ;
    USE SIGNAL ;
    PORT
      LAYER M5 ;
        RECT  29.04 0 29.064 0.084 ;
    END
  END sc_i[159]
  PIN sc_i[15]
    DIRECTION INPUT ;
    USE SIGNAL ;
    PORT
      LAYER M5 ;
        RECT  24.432 0 24.456 0.084 ;
    END
  END sc_i[15]
  PIN sc_i[160]
    DIRECTION INPUT ;
    USE SIGNAL ;
    PORT
      LAYER M5 ;
        RECT  32.208 0 32.232 0.084 ;
    END
  END sc_i[160]
  PIN sc_i[161]
    DIRECTION INPUT ;
    USE SIGNAL ;
    PORT
      LAYER M5 ;
        RECT  32.304 0 32.328 0.084 ;
    END
  END sc_i[161]
  PIN sc_i[162]
    DIRECTION INPUT ;
    USE SIGNAL ;
    PORT
      LAYER M5 ;
        RECT  32.4 0 32.424 0.084 ;
    END
  END sc_i[162]
  PIN sc_i[163]
    DIRECTION INPUT ;
    USE SIGNAL ;
    PORT
      LAYER M5 ;
        RECT  32.496 0 32.52 0.084 ;
    END
  END sc_i[163]
  PIN sc_i[164]
    DIRECTION INPUT ;
    USE SIGNAL ;
    PORT
      LAYER M5 ;
        RECT  32.592 0 32.616 0.084 ;
    END
  END sc_i[164]
  PIN sc_i[165]
    DIRECTION INPUT ;
    USE SIGNAL ;
    PORT
      LAYER M5 ;
        RECT  32.688 0 32.712 0.084 ;
    END
  END sc_i[165]
  PIN sc_i[166]
    DIRECTION INPUT ;
    USE SIGNAL ;
    PORT
      LAYER M5 ;
        RECT  32.784 0 32.808 0.084 ;
    END
  END sc_i[166]
  PIN sc_i[167]
    DIRECTION INPUT ;
    USE SIGNAL ;
    PORT
      LAYER M5 ;
        RECT  32.88 0 32.904 0.084 ;
    END
  END sc_i[167]
  PIN sc_i[168]
    DIRECTION INPUT ;
    USE SIGNAL ;
    PORT
      LAYER M5 ;
        RECT  32.976 0 33 0.084 ;
    END
  END sc_i[168]
  PIN sc_i[169]
    DIRECTION INPUT ;
    USE SIGNAL ;
    PORT
      LAYER M5 ;
        RECT  33.072 0 33.096 0.084 ;
    END
  END sc_i[169]
  PIN sc_i[16]
    DIRECTION INPUT ;
    USE SIGNAL ;
    PORT
      LAYER M5 ;
        RECT  24.528 0 24.552 0.084 ;
    END
  END sc_i[16]
  PIN sc_i[170]
    DIRECTION INPUT ;
    USE SIGNAL ;
    PORT
      LAYER M5 ;
        RECT  33.168 0 33.192 0.084 ;
    END
  END sc_i[170]
  PIN sc_i[171]
    DIRECTION INPUT ;
    USE SIGNAL ;
    PORT
      LAYER M5 ;
        RECT  33.264 0 33.288 0.084 ;
    END
  END sc_i[171]
  PIN sc_i[172]
    DIRECTION INPUT ;
    USE SIGNAL ;
    PORT
      LAYER M5 ;
        RECT  33.36 0 33.384 0.084 ;
    END
  END sc_i[172]
  PIN sc_i[173]
    DIRECTION INPUT ;
    USE SIGNAL ;
    PORT
      LAYER M5 ;
        RECT  33.456 0 33.48 0.084 ;
    END
  END sc_i[173]
  PIN sc_i[174]
    DIRECTION INPUT ;
    USE SIGNAL ;
    PORT
      LAYER M5 ;
        RECT  33.552 0 33.576 0.084 ;
    END
  END sc_i[174]
  PIN sc_i[175]
    DIRECTION INPUT ;
    USE SIGNAL ;
    PORT
      LAYER M5 ;
        RECT  33.648 0 33.672 0.084 ;
    END
  END sc_i[175]
  PIN sc_i[176]
    DIRECTION INPUT ;
    USE SIGNAL ;
    PORT
      LAYER M5 ;
        RECT  33.744 0 33.768 0.084 ;
    END
  END sc_i[176]
  PIN sc_i[177]
    DIRECTION INPUT ;
    USE SIGNAL ;
    PORT
      LAYER M5 ;
        RECT  33.84 0 33.864 0.084 ;
    END
  END sc_i[177]
  PIN sc_i[178]
    DIRECTION INPUT ;
    USE SIGNAL ;
    PORT
      LAYER M5 ;
        RECT  33.936 0 33.96 0.084 ;
    END
  END sc_i[178]
  PIN sc_i[179]
    DIRECTION INPUT ;
    USE SIGNAL ;
    PORT
      LAYER M5 ;
        RECT  34.032 0 34.056 0.084 ;
    END
  END sc_i[179]
  PIN sc_i[17]
    DIRECTION INPUT ;
    USE SIGNAL ;
    PORT
      LAYER M5 ;
        RECT  24.624 0 24.648 0.084 ;
    END
  END sc_i[17]
  PIN sc_i[180]
    DIRECTION INPUT ;
    USE SIGNAL ;
    PORT
      LAYER M5 ;
        RECT  34.128 0 34.152 0.084 ;
    END
  END sc_i[180]
  PIN sc_i[181]
    DIRECTION INPUT ;
    USE SIGNAL ;
    PORT
      LAYER M5 ;
        RECT  34.224 0 34.248 0.084 ;
    END
  END sc_i[181]
  PIN sc_i[182]
    DIRECTION INPUT ;
    USE SIGNAL ;
    PORT
      LAYER M5 ;
        RECT  34.32 0 34.344 0.084 ;
    END
  END sc_i[182]
  PIN sc_i[183]
    DIRECTION INPUT ;
    USE SIGNAL ;
    PORT
      LAYER M5 ;
        RECT  34.416 0 34.44 0.084 ;
    END
  END sc_i[183]
  PIN sc_i[184]
    DIRECTION INPUT ;
    USE SIGNAL ;
    PORT
      LAYER M5 ;
        RECT  34.512 0 34.536 0.084 ;
    END
  END sc_i[184]
  PIN sc_i[185]
    DIRECTION INPUT ;
    USE SIGNAL ;
    PORT
      LAYER M5 ;
        RECT  34.608 0 34.632 0.084 ;
    END
  END sc_i[185]
  PIN sc_i[186]
    DIRECTION INPUT ;
    USE SIGNAL ;
    PORT
      LAYER M5 ;
        RECT  34.704 0 34.728 0.084 ;
    END
  END sc_i[186]
  PIN sc_i[187]
    DIRECTION INPUT ;
    USE SIGNAL ;
    PORT
      LAYER M5 ;
        RECT  34.8 0 34.824 0.084 ;
    END
  END sc_i[187]
  PIN sc_i[188]
    DIRECTION INPUT ;
    USE SIGNAL ;
    PORT
      LAYER M5 ;
        RECT  34.896 0 34.92 0.084 ;
    END
  END sc_i[188]
  PIN sc_i[189]
    DIRECTION INPUT ;
    USE SIGNAL ;
    PORT
      LAYER M5 ;
        RECT  34.992 0 35.016 0.084 ;
    END
  END sc_i[189]
  PIN sc_i[18]
    DIRECTION INPUT ;
    USE SIGNAL ;
    PORT
      LAYER M5 ;
        RECT  24.72 0 24.744 0.084 ;
    END
  END sc_i[18]
  PIN sc_i[190]
    DIRECTION INPUT ;
    USE SIGNAL ;
    PORT
      LAYER M5 ;
        RECT  35.088 0 35.112 0.084 ;
    END
  END sc_i[190]
  PIN sc_i[191]
    DIRECTION INPUT ;
    USE SIGNAL ;
    PORT
      LAYER M5 ;
        RECT  35.184 0 35.208 0.084 ;
    END
  END sc_i[191]
  PIN sc_i[192]
    DIRECTION INPUT ;
    USE SIGNAL ;
    PORT
      LAYER M5 ;
        RECT  39.12 0 39.144 0.084 ;
    END
  END sc_i[192]
  PIN sc_i[193]
    DIRECTION INPUT ;
    USE SIGNAL ;
    PORT
      LAYER M5 ;
        RECT  39.216 0 39.24 0.084 ;
    END
  END sc_i[193]
  PIN sc_i[194]
    DIRECTION INPUT ;
    USE SIGNAL ;
    PORT
      LAYER M5 ;
        RECT  39.312 0 39.336 0.084 ;
    END
  END sc_i[194]
  PIN sc_i[195]
    DIRECTION INPUT ;
    USE SIGNAL ;
    PORT
      LAYER M5 ;
        RECT  39.408 0 39.432 0.084 ;
    END
  END sc_i[195]
  PIN sc_i[196]
    DIRECTION INPUT ;
    USE SIGNAL ;
    PORT
      LAYER M5 ;
        RECT  39.504 0 39.528 0.084 ;
    END
  END sc_i[196]
  PIN sc_i[197]
    DIRECTION INPUT ;
    USE SIGNAL ;
    PORT
      LAYER M5 ;
        RECT  39.6 0 39.624 0.084 ;
    END
  END sc_i[197]
  PIN sc_i[198]
    DIRECTION INPUT ;
    USE SIGNAL ;
    PORT
      LAYER M5 ;
        RECT  39.696 0 39.72 0.084 ;
    END
  END sc_i[198]
  PIN sc_i[199]
    DIRECTION INPUT ;
    USE SIGNAL ;
    PORT
      LAYER M5 ;
        RECT  39.792 0 39.816 0.084 ;
    END
  END sc_i[199]
  PIN sc_i[19]
    DIRECTION INPUT ;
    USE SIGNAL ;
    PORT
      LAYER M5 ;
        RECT  24.816 0 24.84 0.084 ;
    END
  END sc_i[19]
  PIN sc_i[1]
    DIRECTION INPUT ;
    USE SIGNAL ;
    PORT
      LAYER M5 ;
        RECT  23.088 0 23.112 0.084 ;
    END
  END sc_i[1]
  PIN sc_i[200]
    DIRECTION INPUT ;
    USE SIGNAL ;
    PORT
      LAYER M5 ;
        RECT  39.888 0 39.912 0.084 ;
    END
  END sc_i[200]
  PIN sc_i[201]
    DIRECTION INPUT ;
    USE SIGNAL ;
    PORT
      LAYER M5 ;
        RECT  39.984 0 40.008 0.084 ;
    END
  END sc_i[201]
  PIN sc_i[202]
    DIRECTION INPUT ;
    USE SIGNAL ;
    PORT
      LAYER M5 ;
        RECT  40.08 0 40.104 0.084 ;
    END
  END sc_i[202]
  PIN sc_i[203]
    DIRECTION INPUT ;
    USE SIGNAL ;
    PORT
      LAYER M5 ;
        RECT  40.176 0 40.2 0.084 ;
    END
  END sc_i[203]
  PIN sc_i[204]
    DIRECTION INPUT ;
    USE SIGNAL ;
    PORT
      LAYER M5 ;
        RECT  40.272 0 40.296 0.084 ;
    END
  END sc_i[204]
  PIN sc_i[205]
    DIRECTION INPUT ;
    USE SIGNAL ;
    PORT
      LAYER M5 ;
        RECT  40.368 0 40.392 0.084 ;
    END
  END sc_i[205]
  PIN sc_i[206]
    DIRECTION INPUT ;
    USE SIGNAL ;
    PORT
      LAYER M5 ;
        RECT  40.464 0 40.488 0.084 ;
    END
  END sc_i[206]
  PIN sc_i[207]
    DIRECTION INPUT ;
    USE SIGNAL ;
    PORT
      LAYER M5 ;
        RECT  40.56 0 40.584 0.084 ;
    END
  END sc_i[207]
  PIN sc_i[208]
    DIRECTION INPUT ;
    USE SIGNAL ;
    PORT
      LAYER M5 ;
        RECT  40.656 0 40.68 0.084 ;
    END
  END sc_i[208]
  PIN sc_i[209]
    DIRECTION INPUT ;
    USE SIGNAL ;
    PORT
      LAYER M5 ;
        RECT  40.752 0 40.776 0.084 ;
    END
  END sc_i[209]
  PIN sc_i[20]
    DIRECTION INPUT ;
    USE SIGNAL ;
    PORT
      LAYER M5 ;
        RECT  24.912 0 24.936 0.084 ;
    END
  END sc_i[20]
  PIN sc_i[210]
    DIRECTION INPUT ;
    USE SIGNAL ;
    PORT
      LAYER M5 ;
        RECT  40.848 0 40.872 0.084 ;
    END
  END sc_i[210]
  PIN sc_i[211]
    DIRECTION INPUT ;
    USE SIGNAL ;
    PORT
      LAYER M5 ;
        RECT  40.944 0 40.968 0.084 ;
    END
  END sc_i[211]
  PIN sc_i[212]
    DIRECTION INPUT ;
    USE SIGNAL ;
    PORT
      LAYER M5 ;
        RECT  41.04 0 41.064 0.084 ;
    END
  END sc_i[212]
  PIN sc_i[213]
    DIRECTION INPUT ;
    USE SIGNAL ;
    PORT
      LAYER M5 ;
        RECT  41.136 0 41.16 0.084 ;
    END
  END sc_i[213]
  PIN sc_i[214]
    DIRECTION INPUT ;
    USE SIGNAL ;
    PORT
      LAYER M5 ;
        RECT  41.232 0 41.256 0.084 ;
    END
  END sc_i[214]
  PIN sc_i[215]
    DIRECTION INPUT ;
    USE SIGNAL ;
    PORT
      LAYER M5 ;
        RECT  41.328 0 41.352 0.084 ;
    END
  END sc_i[215]
  PIN sc_i[216]
    DIRECTION INPUT ;
    USE SIGNAL ;
    PORT
      LAYER M5 ;
        RECT  41.424 0 41.448 0.084 ;
    END
  END sc_i[216]
  PIN sc_i[217]
    DIRECTION INPUT ;
    USE SIGNAL ;
    PORT
      LAYER M5 ;
        RECT  41.52 0 41.544 0.084 ;
    END
  END sc_i[217]
  PIN sc_i[218]
    DIRECTION INPUT ;
    USE SIGNAL ;
    PORT
      LAYER M5 ;
        RECT  41.616 0 41.64 0.084 ;
    END
  END sc_i[218]
  PIN sc_i[219]
    DIRECTION INPUT ;
    USE SIGNAL ;
    PORT
      LAYER M5 ;
        RECT  41.712 0 41.736 0.084 ;
    END
  END sc_i[219]
  PIN sc_i[21]
    DIRECTION INPUT ;
    USE SIGNAL ;
    PORT
      LAYER M5 ;
        RECT  25.008 0 25.032 0.084 ;
    END
  END sc_i[21]
  PIN sc_i[220]
    DIRECTION INPUT ;
    USE SIGNAL ;
    PORT
      LAYER M5 ;
        RECT  41.808 0 41.832 0.084 ;
    END
  END sc_i[220]
  PIN sc_i[221]
    DIRECTION INPUT ;
    USE SIGNAL ;
    PORT
      LAYER M5 ;
        RECT  41.904 0 41.928 0.084 ;
    END
  END sc_i[221]
  PIN sc_i[222]
    DIRECTION INPUT ;
    USE SIGNAL ;
    PORT
      LAYER M5 ;
        RECT  42 0 42.024 0.084 ;
    END
  END sc_i[222]
  PIN sc_i[223]
    DIRECTION INPUT ;
    USE SIGNAL ;
    PORT
      LAYER M5 ;
        RECT  42.096 0 42.12 0.084 ;
    END
  END sc_i[223]
  PIN sc_i[224]
    DIRECTION INPUT ;
    USE SIGNAL ;
    PORT
      LAYER M5 ;
        RECT  16.08 0 16.104 0.084 ;
    END
  END sc_i[224]
  PIN sc_i[225]
    DIRECTION INPUT ;
    USE SIGNAL ;
    PORT
      LAYER M5 ;
        RECT  16.176 0 16.2 0.084 ;
    END
  END sc_i[225]
  PIN sc_i[226]
    DIRECTION INPUT ;
    USE SIGNAL ;
    PORT
      LAYER M5 ;
        RECT  16.272 0 16.296 0.084 ;
    END
  END sc_i[226]
  PIN sc_i[227]
    DIRECTION INPUT ;
    USE SIGNAL ;
    PORT
      LAYER M5 ;
        RECT  16.368 0 16.392 0.084 ;
    END
  END sc_i[227]
  PIN sc_i[228]
    DIRECTION INPUT ;
    USE SIGNAL ;
    PORT
      LAYER M5 ;
        RECT  16.464 0 16.488 0.084 ;
    END
  END sc_i[228]
  PIN sc_i[229]
    DIRECTION INPUT ;
    USE SIGNAL ;
    PORT
      LAYER M5 ;
        RECT  16.56 0 16.584 0.084 ;
    END
  END sc_i[229]
  PIN sc_i[22]
    DIRECTION INPUT ;
    USE SIGNAL ;
    PORT
      LAYER M5 ;
        RECT  25.104 0 25.128 0.084 ;
    END
  END sc_i[22]
  PIN sc_i[230]
    DIRECTION INPUT ;
    USE SIGNAL ;
    PORT
      LAYER M5 ;
        RECT  16.656 0 16.68 0.084 ;
    END
  END sc_i[230]
  PIN sc_i[231]
    DIRECTION INPUT ;
    USE SIGNAL ;
    PORT
      LAYER M5 ;
        RECT  16.752 0 16.776 0.084 ;
    END
  END sc_i[231]
  PIN sc_i[232]
    DIRECTION INPUT ;
    USE SIGNAL ;
    PORT
      LAYER M5 ;
        RECT  16.848 0 16.872 0.084 ;
    END
  END sc_i[232]
  PIN sc_i[233]
    DIRECTION INPUT ;
    USE SIGNAL ;
    PORT
      LAYER M5 ;
        RECT  16.944 0 16.968 0.084 ;
    END
  END sc_i[233]
  PIN sc_i[234]
    DIRECTION INPUT ;
    USE SIGNAL ;
    PORT
      LAYER M5 ;
        RECT  17.04 0 17.064 0.084 ;
    END
  END sc_i[234]
  PIN sc_i[235]
    DIRECTION INPUT ;
    USE SIGNAL ;
    PORT
      LAYER M5 ;
        RECT  17.136 0 17.16 0.084 ;
    END
  END sc_i[235]
  PIN sc_i[236]
    DIRECTION INPUT ;
    USE SIGNAL ;
    PORT
      LAYER M5 ;
        RECT  17.232 0 17.256 0.084 ;
    END
  END sc_i[236]
  PIN sc_i[237]
    DIRECTION INPUT ;
    USE SIGNAL ;
    PORT
      LAYER M5 ;
        RECT  17.328 0 17.352 0.084 ;
    END
  END sc_i[237]
  PIN sc_i[238]
    DIRECTION INPUT ;
    USE SIGNAL ;
    PORT
      LAYER M5 ;
        RECT  17.424 0 17.448 0.084 ;
    END
  END sc_i[238]
  PIN sc_i[239]
    DIRECTION INPUT ;
    USE SIGNAL ;
    PORT
      LAYER M5 ;
        RECT  17.52 0 17.544 0.084 ;
    END
  END sc_i[239]
  PIN sc_i[23]
    DIRECTION INPUT ;
    USE SIGNAL ;
    PORT
      LAYER M5 ;
        RECT  25.2 0 25.224 0.084 ;
    END
  END sc_i[23]
  PIN sc_i[240]
    DIRECTION INPUT ;
    USE SIGNAL ;
    PORT
      LAYER M5 ;
        RECT  17.616 0 17.64 0.084 ;
    END
  END sc_i[240]
  PIN sc_i[241]
    DIRECTION INPUT ;
    USE SIGNAL ;
    PORT
      LAYER M5 ;
        RECT  17.712 0 17.736 0.084 ;
    END
  END sc_i[241]
  PIN sc_i[242]
    DIRECTION INPUT ;
    USE SIGNAL ;
    PORT
      LAYER M5 ;
        RECT  17.808 0 17.832 0.084 ;
    END
  END sc_i[242]
  PIN sc_i[243]
    DIRECTION INPUT ;
    USE SIGNAL ;
    PORT
      LAYER M5 ;
        RECT  17.904 0 17.928 0.084 ;
    END
  END sc_i[243]
  PIN sc_i[244]
    DIRECTION INPUT ;
    USE SIGNAL ;
    PORT
      LAYER M5 ;
        RECT  18 0 18.024 0.084 ;
    END
  END sc_i[244]
  PIN sc_i[245]
    DIRECTION INPUT ;
    USE SIGNAL ;
    PORT
      LAYER M5 ;
        RECT  18.096 0 18.12 0.084 ;
    END
  END sc_i[245]
  PIN sc_i[246]
    DIRECTION INPUT ;
    USE SIGNAL ;
    PORT
      LAYER M5 ;
        RECT  18.192 0 18.216 0.084 ;
    END
  END sc_i[246]
  PIN sc_i[247]
    DIRECTION INPUT ;
    USE SIGNAL ;
    PORT
      LAYER M5 ;
        RECT  18.288 0 18.312 0.084 ;
    END
  END sc_i[247]
  PIN sc_i[248]
    DIRECTION INPUT ;
    USE SIGNAL ;
    PORT
      LAYER M5 ;
        RECT  18.384 0 18.408 0.084 ;
    END
  END sc_i[248]
  PIN sc_i[249]
    DIRECTION INPUT ;
    USE SIGNAL ;
    PORT
      LAYER M5 ;
        RECT  18.48 0 18.504 0.084 ;
    END
  END sc_i[249]
  PIN sc_i[24]
    DIRECTION INPUT ;
    USE SIGNAL ;
    PORT
      LAYER M5 ;
        RECT  25.296 0 25.32 0.084 ;
    END
  END sc_i[24]
  PIN sc_i[250]
    DIRECTION INPUT ;
    USE SIGNAL ;
    PORT
      LAYER M5 ;
        RECT  18.576 0 18.6 0.084 ;
    END
  END sc_i[250]
  PIN sc_i[251]
    DIRECTION INPUT ;
    USE SIGNAL ;
    PORT
      LAYER M5 ;
        RECT  18.672 0 18.696 0.084 ;
    END
  END sc_i[251]
  PIN sc_i[252]
    DIRECTION INPUT ;
    USE SIGNAL ;
    PORT
      LAYER M5 ;
        RECT  18.768 0 18.792 0.084 ;
    END
  END sc_i[252]
  PIN sc_i[253]
    DIRECTION INPUT ;
    USE SIGNAL ;
    PORT
      LAYER M5 ;
        RECT  18.864 0 18.888 0.084 ;
    END
  END sc_i[253]
  PIN sc_i[254]
    DIRECTION INPUT ;
    USE SIGNAL ;
    PORT
      LAYER M5 ;
        RECT  18.96 0 18.984 0.084 ;
    END
  END sc_i[254]
  PIN sc_i[255]
    DIRECTION INPUT ;
    USE SIGNAL ;
    PORT
      LAYER M5 ;
        RECT  19.056 0 19.08 0.084 ;
    END
  END sc_i[255]
  PIN sc_i[256]
    DIRECTION INPUT ;
    USE SIGNAL ;
    PORT
      LAYER M5 ;
        RECT  19.152 0 19.176 0.084 ;
    END
  END sc_i[256]
  PIN sc_i[257]
    DIRECTION INPUT ;
    USE SIGNAL ;
    PORT
      LAYER M5 ;
        RECT  19.248 0 19.272 0.084 ;
    END
  END sc_i[257]
  PIN sc_i[258]
    DIRECTION INPUT ;
    USE SIGNAL ;
    PORT
      LAYER M5 ;
        RECT  19.344 0 19.368 0.084 ;
    END
  END sc_i[258]
  PIN sc_i[25]
    DIRECTION INPUT ;
    USE SIGNAL ;
    PORT
      LAYER M5 ;
        RECT  25.392 0 25.416 0.084 ;
    END
  END sc_i[25]
  PIN sc_i[26]
    DIRECTION INPUT ;
    USE SIGNAL ;
    PORT
      LAYER M5 ;
        RECT  25.488 0 25.512 0.084 ;
    END
  END sc_i[26]
  PIN sc_i[27]
    DIRECTION INPUT ;
    USE SIGNAL ;
    PORT
      LAYER M5 ;
        RECT  25.584 0 25.608 0.084 ;
    END
  END sc_i[27]
  PIN sc_i[28]
    DIRECTION INPUT ;
    USE SIGNAL ;
    PORT
      LAYER M5 ;
        RECT  25.68 0 25.704 0.084 ;
    END
  END sc_i[28]
  PIN sc_i[29]
    DIRECTION INPUT ;
    USE SIGNAL ;
    PORT
      LAYER M5 ;
        RECT  25.776 0 25.8 0.084 ;
    END
  END sc_i[29]
  PIN sc_i[2]
    DIRECTION INPUT ;
    USE SIGNAL ;
    PORT
      LAYER M5 ;
        RECT  23.184 0 23.208 0.084 ;
    END
  END sc_i[2]
  PIN sc_i[30]
    DIRECTION INPUT ;
    USE SIGNAL ;
    PORT
      LAYER M5 ;
        RECT  25.872 0 25.896 0.084 ;
    END
  END sc_i[30]
  PIN sc_i[31]
    DIRECTION INPUT ;
    USE SIGNAL ;
    PORT
      LAYER M5 ;
        RECT  25.968 0 25.992 0.084 ;
    END
  END sc_i[31]
  PIN sc_i[32]
    DIRECTION INPUT ;
    USE SIGNAL ;
    PORT
      LAYER M5 ;
        RECT  29.136 0 29.16 0.084 ;
    END
  END sc_i[32]
  PIN sc_i[33]
    DIRECTION INPUT ;
    USE SIGNAL ;
    PORT
      LAYER M5 ;
        RECT  29.232 0 29.256 0.084 ;
    END
  END sc_i[33]
  PIN sc_i[34]
    DIRECTION INPUT ;
    USE SIGNAL ;
    PORT
      LAYER M5 ;
        RECT  29.328 0 29.352 0.084 ;
    END
  END sc_i[34]
  PIN sc_i[35]
    DIRECTION INPUT ;
    USE SIGNAL ;
    PORT
      LAYER M5 ;
        RECT  29.424 0 29.448 0.084 ;
    END
  END sc_i[35]
  PIN sc_i[36]
    DIRECTION INPUT ;
    USE SIGNAL ;
    PORT
      LAYER M5 ;
        RECT  29.52 0 29.544 0.084 ;
    END
  END sc_i[36]
  PIN sc_i[37]
    DIRECTION INPUT ;
    USE SIGNAL ;
    PORT
      LAYER M5 ;
        RECT  29.616 0 29.64 0.084 ;
    END
  END sc_i[37]
  PIN sc_i[38]
    DIRECTION INPUT ;
    USE SIGNAL ;
    PORT
      LAYER M5 ;
        RECT  29.712 0 29.736 0.084 ;
    END
  END sc_i[38]
  PIN sc_i[39]
    DIRECTION INPUT ;
    USE SIGNAL ;
    PORT
      LAYER M5 ;
        RECT  29.808 0 29.832 0.084 ;
    END
  END sc_i[39]
  PIN sc_i[3]
    DIRECTION INPUT ;
    USE SIGNAL ;
    PORT
      LAYER M5 ;
        RECT  23.28 0 23.304 0.084 ;
    END
  END sc_i[3]
  PIN sc_i[40]
    DIRECTION INPUT ;
    USE SIGNAL ;
    PORT
      LAYER M5 ;
        RECT  29.904 0 29.928 0.084 ;
    END
  END sc_i[40]
  PIN sc_i[41]
    DIRECTION INPUT ;
    USE SIGNAL ;
    PORT
      LAYER M5 ;
        RECT  30 0 30.024 0.084 ;
    END
  END sc_i[41]
  PIN sc_i[42]
    DIRECTION INPUT ;
    USE SIGNAL ;
    PORT
      LAYER M5 ;
        RECT  30.096 0 30.12 0.084 ;
    END
  END sc_i[42]
  PIN sc_i[43]
    DIRECTION INPUT ;
    USE SIGNAL ;
    PORT
      LAYER M5 ;
        RECT  30.192 0 30.216 0.084 ;
    END
  END sc_i[43]
  PIN sc_i[44]
    DIRECTION INPUT ;
    USE SIGNAL ;
    PORT
      LAYER M5 ;
        RECT  30.288 0 30.312 0.084 ;
    END
  END sc_i[44]
  PIN sc_i[45]
    DIRECTION INPUT ;
    USE SIGNAL ;
    PORT
      LAYER M5 ;
        RECT  30.384 0 30.408 0.084 ;
    END
  END sc_i[45]
  PIN sc_i[46]
    DIRECTION INPUT ;
    USE SIGNAL ;
    PORT
      LAYER M5 ;
        RECT  30.48 0 30.504 0.084 ;
    END
  END sc_i[46]
  PIN sc_i[47]
    DIRECTION INPUT ;
    USE SIGNAL ;
    PORT
      LAYER M5 ;
        RECT  30.576 0 30.6 0.084 ;
    END
  END sc_i[47]
  PIN sc_i[48]
    DIRECTION INPUT ;
    USE SIGNAL ;
    PORT
      LAYER M5 ;
        RECT  30.672 0 30.696 0.084 ;
    END
  END sc_i[48]
  PIN sc_i[49]
    DIRECTION INPUT ;
    USE SIGNAL ;
    PORT
      LAYER M5 ;
        RECT  30.768 0 30.792 0.084 ;
    END
  END sc_i[49]
  PIN sc_i[4]
    DIRECTION INPUT ;
    USE SIGNAL ;
    PORT
      LAYER M5 ;
        RECT  23.376 0 23.4 0.084 ;
    END
  END sc_i[4]
  PIN sc_i[50]
    DIRECTION INPUT ;
    USE SIGNAL ;
    PORT
      LAYER M5 ;
        RECT  30.864 0 30.888 0.084 ;
    END
  END sc_i[50]
  PIN sc_i[51]
    DIRECTION INPUT ;
    USE SIGNAL ;
    PORT
      LAYER M5 ;
        RECT  30.96 0 30.984 0.084 ;
    END
  END sc_i[51]
  PIN sc_i[52]
    DIRECTION INPUT ;
    USE SIGNAL ;
    PORT
      LAYER M5 ;
        RECT  31.056 0 31.08 0.084 ;
    END
  END sc_i[52]
  PIN sc_i[53]
    DIRECTION INPUT ;
    USE SIGNAL ;
    PORT
      LAYER M5 ;
        RECT  31.152 0 31.176 0.084 ;
    END
  END sc_i[53]
  PIN sc_i[54]
    DIRECTION INPUT ;
    USE SIGNAL ;
    PORT
      LAYER M5 ;
        RECT  31.248 0 31.272 0.084 ;
    END
  END sc_i[54]
  PIN sc_i[55]
    DIRECTION INPUT ;
    USE SIGNAL ;
    PORT
      LAYER M5 ;
        RECT  31.344 0 31.368 0.084 ;
    END
  END sc_i[55]
  PIN sc_i[56]
    DIRECTION INPUT ;
    USE SIGNAL ;
    PORT
      LAYER M5 ;
        RECT  31.44 0 31.464 0.084 ;
    END
  END sc_i[56]
  PIN sc_i[57]
    DIRECTION INPUT ;
    USE SIGNAL ;
    PORT
      LAYER M5 ;
        RECT  31.536 0 31.56 0.084 ;
    END
  END sc_i[57]
  PIN sc_i[58]
    DIRECTION INPUT ;
    USE SIGNAL ;
    PORT
      LAYER M5 ;
        RECT  31.632 0 31.656 0.084 ;
    END
  END sc_i[58]
  PIN sc_i[59]
    DIRECTION INPUT ;
    USE SIGNAL ;
    PORT
      LAYER M5 ;
        RECT  31.728 0 31.752 0.084 ;
    END
  END sc_i[59]
  PIN sc_i[5]
    DIRECTION INPUT ;
    USE SIGNAL ;
    PORT
      LAYER M5 ;
        RECT  23.472 0 23.496 0.084 ;
    END
  END sc_i[5]
  PIN sc_i[60]
    DIRECTION INPUT ;
    USE SIGNAL ;
    PORT
      LAYER M5 ;
        RECT  31.824 0 31.848 0.084 ;
    END
  END sc_i[60]
  PIN sc_i[61]
    DIRECTION INPUT ;
    USE SIGNAL ;
    PORT
      LAYER M5 ;
        RECT  31.92 0 31.944 0.084 ;
    END
  END sc_i[61]
  PIN sc_i[62]
    DIRECTION INPUT ;
    USE SIGNAL ;
    PORT
      LAYER M5 ;
        RECT  32.016 0 32.04 0.084 ;
    END
  END sc_i[62]
  PIN sc_i[63]
    DIRECTION INPUT ;
    USE SIGNAL ;
    PORT
      LAYER M5 ;
        RECT  32.112 0 32.136 0.084 ;
    END
  END sc_i[63]
  PIN sc_i[64]
    DIRECTION INPUT ;
    USE SIGNAL ;
    PORT
      LAYER M5 ;
        RECT  19.92 0 19.944 0.084 ;
    END
  END sc_i[64]
  PIN sc_i[65]
    DIRECTION INPUT ;
    USE SIGNAL ;
    PORT
      LAYER M5 ;
        RECT  20.016 0 20.04 0.084 ;
    END
  END sc_i[65]
  PIN sc_i[66]
    DIRECTION INPUT ;
    USE SIGNAL ;
    PORT
      LAYER M5 ;
        RECT  20.112 0 20.136 0.084 ;
    END
  END sc_i[66]
  PIN sc_i[67]
    DIRECTION INPUT ;
    USE SIGNAL ;
    PORT
      LAYER M5 ;
        RECT  20.208 0 20.232 0.084 ;
    END
  END sc_i[67]
  PIN sc_i[68]
    DIRECTION INPUT ;
    USE SIGNAL ;
    PORT
      LAYER M5 ;
        RECT  20.304 0 20.328 0.084 ;
    END
  END sc_i[68]
  PIN sc_i[69]
    DIRECTION INPUT ;
    USE SIGNAL ;
    PORT
      LAYER M5 ;
        RECT  20.4 0 20.424 0.084 ;
    END
  END sc_i[69]
  PIN sc_i[6]
    DIRECTION INPUT ;
    USE SIGNAL ;
    PORT
      LAYER M5 ;
        RECT  23.568 0 23.592 0.084 ;
    END
  END sc_i[6]
  PIN sc_i[70]
    DIRECTION INPUT ;
    USE SIGNAL ;
    PORT
      LAYER M5 ;
        RECT  20.496 0 20.52 0.084 ;
    END
  END sc_i[70]
  PIN sc_i[71]
    DIRECTION INPUT ;
    USE SIGNAL ;
    PORT
      LAYER M5 ;
        RECT  20.592 0 20.616 0.084 ;
    END
  END sc_i[71]
  PIN sc_i[72]
    DIRECTION INPUT ;
    USE SIGNAL ;
    PORT
      LAYER M5 ;
        RECT  20.688 0 20.712 0.084 ;
    END
  END sc_i[72]
  PIN sc_i[73]
    DIRECTION INPUT ;
    USE SIGNAL ;
    PORT
      LAYER M5 ;
        RECT  20.784 0 20.808 0.084 ;
    END
  END sc_i[73]
  PIN sc_i[74]
    DIRECTION INPUT ;
    USE SIGNAL ;
    PORT
      LAYER M5 ;
        RECT  20.88 0 20.904 0.084 ;
    END
  END sc_i[74]
  PIN sc_i[75]
    DIRECTION INPUT ;
    USE SIGNAL ;
    PORT
      LAYER M5 ;
        RECT  20.976 0 21 0.084 ;
    END
  END sc_i[75]
  PIN sc_i[76]
    DIRECTION INPUT ;
    USE SIGNAL ;
    PORT
      LAYER M5 ;
        RECT  21.072 0 21.096 0.084 ;
    END
  END sc_i[76]
  PIN sc_i[77]
    DIRECTION INPUT ;
    USE SIGNAL ;
    PORT
      LAYER M5 ;
        RECT  21.168 0 21.192 0.084 ;
    END
  END sc_i[77]
  PIN sc_i[78]
    DIRECTION INPUT ;
    USE SIGNAL ;
    PORT
      LAYER M5 ;
        RECT  21.264 0 21.288 0.084 ;
    END
  END sc_i[78]
  PIN sc_i[79]
    DIRECTION INPUT ;
    USE SIGNAL ;
    PORT
      LAYER M5 ;
        RECT  21.36 0 21.384 0.084 ;
    END
  END sc_i[79]
  PIN sc_i[7]
    DIRECTION INPUT ;
    USE SIGNAL ;
    PORT
      LAYER M5 ;
        RECT  23.664 0 23.688 0.084 ;
    END
  END sc_i[7]
  PIN sc_i[80]
    DIRECTION INPUT ;
    USE SIGNAL ;
    PORT
      LAYER M5 ;
        RECT  21.456 0 21.48 0.084 ;
    END
  END sc_i[80]
  PIN sc_i[81]
    DIRECTION INPUT ;
    USE SIGNAL ;
    PORT
      LAYER M5 ;
        RECT  21.552 0 21.576 0.084 ;
    END
  END sc_i[81]
  PIN sc_i[82]
    DIRECTION INPUT ;
    USE SIGNAL ;
    PORT
      LAYER M5 ;
        RECT  21.648 0 21.672 0.084 ;
    END
  END sc_i[82]
  PIN sc_i[83]
    DIRECTION INPUT ;
    USE SIGNAL ;
    PORT
      LAYER M5 ;
        RECT  21.744 0 21.768 0.084 ;
    END
  END sc_i[83]
  PIN sc_i[84]
    DIRECTION INPUT ;
    USE SIGNAL ;
    PORT
      LAYER M5 ;
        RECT  21.84 0 21.864 0.084 ;
    END
  END sc_i[84]
  PIN sc_i[85]
    DIRECTION INPUT ;
    USE SIGNAL ;
    PORT
      LAYER M5 ;
        RECT  21.936 0 21.96 0.084 ;
    END
  END sc_i[85]
  PIN sc_i[86]
    DIRECTION INPUT ;
    USE SIGNAL ;
    PORT
      LAYER M5 ;
        RECT  22.032 0 22.056 0.084 ;
    END
  END sc_i[86]
  PIN sc_i[87]
    DIRECTION INPUT ;
    USE SIGNAL ;
    PORT
      LAYER M5 ;
        RECT  22.128 0 22.152 0.084 ;
    END
  END sc_i[87]
  PIN sc_i[88]
    DIRECTION INPUT ;
    USE SIGNAL ;
    PORT
      LAYER M5 ;
        RECT  22.224 0 22.248 0.084 ;
    END
  END sc_i[88]
  PIN sc_i[89]
    DIRECTION INPUT ;
    USE SIGNAL ;
    PORT
      LAYER M5 ;
        RECT  22.32 0 22.344 0.084 ;
    END
  END sc_i[89]
  PIN sc_i[8]
    DIRECTION INPUT ;
    USE SIGNAL ;
    PORT
      LAYER M5 ;
        RECT  23.76 0 23.784 0.084 ;
    END
  END sc_i[8]
  PIN sc_i[90]
    DIRECTION INPUT ;
    USE SIGNAL ;
    PORT
      LAYER M5 ;
        RECT  22.416 0 22.44 0.084 ;
    END
  END sc_i[90]
  PIN sc_i[91]
    DIRECTION INPUT ;
    USE SIGNAL ;
    PORT
      LAYER M5 ;
        RECT  22.512 0 22.536 0.084 ;
    END
  END sc_i[91]
  PIN sc_i[92]
    DIRECTION INPUT ;
    USE SIGNAL ;
    PORT
      LAYER M5 ;
        RECT  22.608 0 22.632 0.084 ;
    END
  END sc_i[92]
  PIN sc_i[93]
    DIRECTION INPUT ;
    USE SIGNAL ;
    PORT
      LAYER M5 ;
        RECT  22.704 0 22.728 0.084 ;
    END
  END sc_i[93]
  PIN sc_i[94]
    DIRECTION INPUT ;
    USE SIGNAL ;
    PORT
      LAYER M5 ;
        RECT  22.8 0 22.824 0.084 ;
    END
  END sc_i[94]
  PIN sc_i[95]
    DIRECTION INPUT ;
    USE SIGNAL ;
    PORT
      LAYER M5 ;
        RECT  22.896 0 22.92 0.084 ;
    END
  END sc_i[95]
  PIN sc_i[96]
    DIRECTION INPUT ;
    USE SIGNAL ;
    PORT
      LAYER M5 ;
        RECT  35.28 0 35.304 0.084 ;
    END
  END sc_i[96]
  PIN sc_i[97]
    DIRECTION INPUT ;
    USE SIGNAL ;
    PORT
      LAYER M5 ;
        RECT  35.376 0 35.4 0.084 ;
    END
  END sc_i[97]
  PIN sc_i[98]
    DIRECTION INPUT ;
    USE SIGNAL ;
    PORT
      LAYER M5 ;
        RECT  35.472 0 35.496 0.084 ;
    END
  END sc_i[98]
  PIN sc_i[99]
    DIRECTION INPUT ;
    USE SIGNAL ;
    PORT
      LAYER M5 ;
        RECT  35.568 0 35.592 0.084 ;
    END
  END sc_i[99]
  PIN sc_i[9]
    DIRECTION INPUT ;
    USE SIGNAL ;
    PORT
      LAYER M5 ;
        RECT  23.856 0 23.88 0.084 ;
    END
  END sc_i[9]
  PIN sc_o[0]
    DIRECTION OUTPUT ;
    USE SIGNAL ;
    PORT
      LAYER M4 ;
        RECT  64.716 26.064 64.8 26.088 ;
    END
  END sc_o[0]
  PIN sc_o[100]
    DIRECTION OUTPUT ;
    USE SIGNAL ;
    PORT
      LAYER M4 ;
        RECT  64.716 35.664 64.8 35.688 ;
    END
  END sc_o[100]
  PIN sc_o[101]
    DIRECTION OUTPUT ;
    USE SIGNAL ;
    PORT
      LAYER M4 ;
        RECT  64.716 35.76 64.8 35.784 ;
    END
  END sc_o[101]
  PIN sc_o[102]
    DIRECTION OUTPUT ;
    USE SIGNAL ;
    PORT
      LAYER M4 ;
        RECT  64.716 35.856 64.8 35.88 ;
    END
  END sc_o[102]
  PIN sc_o[103]
    DIRECTION OUTPUT ;
    USE SIGNAL ;
    PORT
      LAYER M4 ;
        RECT  64.716 35.952 64.8 35.976 ;
    END
  END sc_o[103]
  PIN sc_o[104]
    DIRECTION OUTPUT ;
    USE SIGNAL ;
    PORT
      LAYER M4 ;
        RECT  64.716 36.048 64.8 36.072 ;
    END
  END sc_o[104]
  PIN sc_o[105]
    DIRECTION OUTPUT ;
    USE SIGNAL ;
    PORT
      LAYER M4 ;
        RECT  64.716 36.144 64.8 36.168 ;
    END
  END sc_o[105]
  PIN sc_o[106]
    DIRECTION OUTPUT ;
    USE SIGNAL ;
    PORT
      LAYER M4 ;
        RECT  64.716 36.24 64.8 36.264 ;
    END
  END sc_o[106]
  PIN sc_o[107]
    DIRECTION OUTPUT ;
    USE SIGNAL ;
    PORT
      LAYER M4 ;
        RECT  64.716 36.336 64.8 36.36 ;
    END
  END sc_o[107]
  PIN sc_o[108]
    DIRECTION OUTPUT ;
    USE SIGNAL ;
    PORT
      LAYER M4 ;
        RECT  64.716 36.432 64.8 36.456 ;
    END
  END sc_o[108]
  PIN sc_o[109]
    DIRECTION OUTPUT ;
    USE SIGNAL ;
    PORT
      LAYER M4 ;
        RECT  64.716 36.528 64.8 36.552 ;
    END
  END sc_o[109]
  PIN sc_o[10]
    DIRECTION OUTPUT ;
    USE SIGNAL ;
    PORT
      LAYER M4 ;
        RECT  64.716 27.024 64.8 27.048 ;
    END
  END sc_o[10]
  PIN sc_o[110]
    DIRECTION OUTPUT ;
    USE SIGNAL ;
    PORT
      LAYER M4 ;
        RECT  64.716 36.624 64.8 36.648 ;
    END
  END sc_o[110]
  PIN sc_o[111]
    DIRECTION OUTPUT ;
    USE SIGNAL ;
    PORT
      LAYER M4 ;
        RECT  64.716 36.72 64.8 36.744 ;
    END
  END sc_o[111]
  PIN sc_o[112]
    DIRECTION OUTPUT ;
    USE SIGNAL ;
    PORT
      LAYER M4 ;
        RECT  64.716 36.816 64.8 36.84 ;
    END
  END sc_o[112]
  PIN sc_o[113]
    DIRECTION OUTPUT ;
    USE SIGNAL ;
    PORT
      LAYER M4 ;
        RECT  64.716 36.912 64.8 36.936 ;
    END
  END sc_o[113]
  PIN sc_o[114]
    DIRECTION OUTPUT ;
    USE SIGNAL ;
    PORT
      LAYER M4 ;
        RECT  64.716 37.008 64.8 37.032 ;
    END
  END sc_o[114]
  PIN sc_o[115]
    DIRECTION OUTPUT ;
    USE SIGNAL ;
    PORT
      LAYER M4 ;
        RECT  64.716 37.104 64.8 37.128 ;
    END
  END sc_o[115]
  PIN sc_o[116]
    DIRECTION OUTPUT ;
    USE SIGNAL ;
    PORT
      LAYER M4 ;
        RECT  64.716 37.2 64.8 37.224 ;
    END
  END sc_o[116]
  PIN sc_o[117]
    DIRECTION OUTPUT ;
    USE SIGNAL ;
    PORT
      LAYER M4 ;
        RECT  64.716 37.296 64.8 37.32 ;
    END
  END sc_o[117]
  PIN sc_o[118]
    DIRECTION OUTPUT ;
    USE SIGNAL ;
    PORT
      LAYER M4 ;
        RECT  64.716 37.392 64.8 37.416 ;
    END
  END sc_o[118]
  PIN sc_o[119]
    DIRECTION OUTPUT ;
    USE SIGNAL ;
    PORT
      LAYER M4 ;
        RECT  64.716 37.488 64.8 37.512 ;
    END
  END sc_o[119]
  PIN sc_o[11]
    DIRECTION OUTPUT ;
    USE SIGNAL ;
    PORT
      LAYER M4 ;
        RECT  64.716 27.12 64.8 27.144 ;
    END
  END sc_o[11]
  PIN sc_o[120]
    DIRECTION OUTPUT ;
    USE SIGNAL ;
    PORT
      LAYER M4 ;
        RECT  64.716 37.584 64.8 37.608 ;
    END
  END sc_o[120]
  PIN sc_o[121]
    DIRECTION OUTPUT ;
    USE SIGNAL ;
    PORT
      LAYER M4 ;
        RECT  64.716 37.68 64.8 37.704 ;
    END
  END sc_o[121]
  PIN sc_o[122]
    DIRECTION OUTPUT ;
    USE SIGNAL ;
    PORT
      LAYER M4 ;
        RECT  64.716 37.776 64.8 37.8 ;
    END
  END sc_o[122]
  PIN sc_o[123]
    DIRECTION OUTPUT ;
    USE SIGNAL ;
    PORT
      LAYER M4 ;
        RECT  64.716 37.872 64.8 37.896 ;
    END
  END sc_o[123]
  PIN sc_o[124]
    DIRECTION OUTPUT ;
    USE SIGNAL ;
    PORT
      LAYER M4 ;
        RECT  64.716 37.968 64.8 37.992 ;
    END
  END sc_o[124]
  PIN sc_o[125]
    DIRECTION OUTPUT ;
    USE SIGNAL ;
    PORT
      LAYER M4 ;
        RECT  64.716 38.064 64.8 38.088 ;
    END
  END sc_o[125]
  PIN sc_o[126]
    DIRECTION OUTPUT ;
    USE SIGNAL ;
    PORT
      LAYER M4 ;
        RECT  64.716 38.16 64.8 38.184 ;
    END
  END sc_o[126]
  PIN sc_o[127]
    DIRECTION OUTPUT ;
    USE SIGNAL ;
    PORT
      LAYER M4 ;
        RECT  64.716 38.256 64.8 38.28 ;
    END
  END sc_o[127]
  PIN sc_o[128]
    DIRECTION OUTPUT ;
    USE SIGNAL ;
    PORT
      LAYER M4 ;
        RECT  64.716 22.992 64.8 23.016 ;
    END
  END sc_o[128]
  PIN sc_o[129]
    DIRECTION OUTPUT ;
    USE SIGNAL ;
    PORT
      LAYER M4 ;
        RECT  64.716 23.088 64.8 23.112 ;
    END
  END sc_o[129]
  PIN sc_o[12]
    DIRECTION OUTPUT ;
    USE SIGNAL ;
    PORT
      LAYER M4 ;
        RECT  64.716 27.216 64.8 27.24 ;
    END
  END sc_o[12]
  PIN sc_o[130]
    DIRECTION OUTPUT ;
    USE SIGNAL ;
    PORT
      LAYER M4 ;
        RECT  64.716 23.184 64.8 23.208 ;
    END
  END sc_o[130]
  PIN sc_o[131]
    DIRECTION OUTPUT ;
    USE SIGNAL ;
    PORT
      LAYER M4 ;
        RECT  64.716 23.28 64.8 23.304 ;
    END
  END sc_o[131]
  PIN sc_o[132]
    DIRECTION OUTPUT ;
    USE SIGNAL ;
    PORT
      LAYER M4 ;
        RECT  64.716 23.376 64.8 23.4 ;
    END
  END sc_o[132]
  PIN sc_o[133]
    DIRECTION OUTPUT ;
    USE SIGNAL ;
    PORT
      LAYER M4 ;
        RECT  64.716 23.472 64.8 23.496 ;
    END
  END sc_o[133]
  PIN sc_o[134]
    DIRECTION OUTPUT ;
    USE SIGNAL ;
    PORT
      LAYER M4 ;
        RECT  64.716 23.568 64.8 23.592 ;
    END
  END sc_o[134]
  PIN sc_o[135]
    DIRECTION OUTPUT ;
    USE SIGNAL ;
    PORT
      LAYER M4 ;
        RECT  64.716 23.664 64.8 23.688 ;
    END
  END sc_o[135]
  PIN sc_o[136]
    DIRECTION OUTPUT ;
    USE SIGNAL ;
    PORT
      LAYER M4 ;
        RECT  64.716 23.76 64.8 23.784 ;
    END
  END sc_o[136]
  PIN sc_o[137]
    DIRECTION OUTPUT ;
    USE SIGNAL ;
    PORT
      LAYER M4 ;
        RECT  64.716 23.856 64.8 23.88 ;
    END
  END sc_o[137]
  PIN sc_o[138]
    DIRECTION OUTPUT ;
    USE SIGNAL ;
    PORT
      LAYER M4 ;
        RECT  64.716 23.952 64.8 23.976 ;
    END
  END sc_o[138]
  PIN sc_o[139]
    DIRECTION OUTPUT ;
    USE SIGNAL ;
    PORT
      LAYER M4 ;
        RECT  64.716 24.048 64.8 24.072 ;
    END
  END sc_o[139]
  PIN sc_o[13]
    DIRECTION OUTPUT ;
    USE SIGNAL ;
    PORT
      LAYER M4 ;
        RECT  64.716 27.312 64.8 27.336 ;
    END
  END sc_o[13]
  PIN sc_o[140]
    DIRECTION OUTPUT ;
    USE SIGNAL ;
    PORT
      LAYER M4 ;
        RECT  64.716 24.144 64.8 24.168 ;
    END
  END sc_o[140]
  PIN sc_o[141]
    DIRECTION OUTPUT ;
    USE SIGNAL ;
    PORT
      LAYER M4 ;
        RECT  64.716 24.24 64.8 24.264 ;
    END
  END sc_o[141]
  PIN sc_o[142]
    DIRECTION OUTPUT ;
    USE SIGNAL ;
    PORT
      LAYER M4 ;
        RECT  64.716 24.336 64.8 24.36 ;
    END
  END sc_o[142]
  PIN sc_o[143]
    DIRECTION OUTPUT ;
    USE SIGNAL ;
    PORT
      LAYER M4 ;
        RECT  64.716 24.432 64.8 24.456 ;
    END
  END sc_o[143]
  PIN sc_o[144]
    DIRECTION OUTPUT ;
    USE SIGNAL ;
    PORT
      LAYER M4 ;
        RECT  64.716 24.528 64.8 24.552 ;
    END
  END sc_o[144]
  PIN sc_o[145]
    DIRECTION OUTPUT ;
    USE SIGNAL ;
    PORT
      LAYER M4 ;
        RECT  64.716 24.624 64.8 24.648 ;
    END
  END sc_o[145]
  PIN sc_o[146]
    DIRECTION OUTPUT ;
    USE SIGNAL ;
    PORT
      LAYER M4 ;
        RECT  64.716 24.72 64.8 24.744 ;
    END
  END sc_o[146]
  PIN sc_o[147]
    DIRECTION OUTPUT ;
    USE SIGNAL ;
    PORT
      LAYER M4 ;
        RECT  64.716 24.816 64.8 24.84 ;
    END
  END sc_o[147]
  PIN sc_o[148]
    DIRECTION OUTPUT ;
    USE SIGNAL ;
    PORT
      LAYER M4 ;
        RECT  64.716 24.912 64.8 24.936 ;
    END
  END sc_o[148]
  PIN sc_o[149]
    DIRECTION OUTPUT ;
    USE SIGNAL ;
    PORT
      LAYER M4 ;
        RECT  64.716 25.008 64.8 25.032 ;
    END
  END sc_o[149]
  PIN sc_o[14]
    DIRECTION OUTPUT ;
    USE SIGNAL ;
    PORT
      LAYER M4 ;
        RECT  64.716 27.408 64.8 27.432 ;
    END
  END sc_o[14]
  PIN sc_o[150]
    DIRECTION OUTPUT ;
    USE SIGNAL ;
    PORT
      LAYER M4 ;
        RECT  64.716 25.104 64.8 25.128 ;
    END
  END sc_o[150]
  PIN sc_o[151]
    DIRECTION OUTPUT ;
    USE SIGNAL ;
    PORT
      LAYER M4 ;
        RECT  64.716 25.2 64.8 25.224 ;
    END
  END sc_o[151]
  PIN sc_o[152]
    DIRECTION OUTPUT ;
    USE SIGNAL ;
    PORT
      LAYER M4 ;
        RECT  64.716 25.296 64.8 25.32 ;
    END
  END sc_o[152]
  PIN sc_o[153]
    DIRECTION OUTPUT ;
    USE SIGNAL ;
    PORT
      LAYER M4 ;
        RECT  64.716 25.392 64.8 25.416 ;
    END
  END sc_o[153]
  PIN sc_o[154]
    DIRECTION OUTPUT ;
    USE SIGNAL ;
    PORT
      LAYER M4 ;
        RECT  64.716 25.488 64.8 25.512 ;
    END
  END sc_o[154]
  PIN sc_o[155]
    DIRECTION OUTPUT ;
    USE SIGNAL ;
    PORT
      LAYER M4 ;
        RECT  64.716 25.584 64.8 25.608 ;
    END
  END sc_o[155]
  PIN sc_o[156]
    DIRECTION OUTPUT ;
    USE SIGNAL ;
    PORT
      LAYER M4 ;
        RECT  64.716 25.68 64.8 25.704 ;
    END
  END sc_o[156]
  PIN sc_o[157]
    DIRECTION OUTPUT ;
    USE SIGNAL ;
    PORT
      LAYER M4 ;
        RECT  64.716 25.776 64.8 25.8 ;
    END
  END sc_o[157]
  PIN sc_o[158]
    DIRECTION OUTPUT ;
    USE SIGNAL ;
    PORT
      LAYER M4 ;
        RECT  64.716 25.872 64.8 25.896 ;
    END
  END sc_o[158]
  PIN sc_o[159]
    DIRECTION OUTPUT ;
    USE SIGNAL ;
    PORT
      LAYER M4 ;
        RECT  64.716 25.968 64.8 25.992 ;
    END
  END sc_o[159]
  PIN sc_o[15]
    DIRECTION OUTPUT ;
    USE SIGNAL ;
    PORT
      LAYER M4 ;
        RECT  64.716 27.504 64.8 27.528 ;
    END
  END sc_o[15]
  PIN sc_o[160]
    DIRECTION OUTPUT ;
    USE SIGNAL ;
    PORT
      LAYER M4 ;
        RECT  64.716 19.92 64.8 19.944 ;
    END
  END sc_o[160]
  PIN sc_o[161]
    DIRECTION OUTPUT ;
    USE SIGNAL ;
    PORT
      LAYER M4 ;
        RECT  64.716 20.016 64.8 20.04 ;
    END
  END sc_o[161]
  PIN sc_o[162]
    DIRECTION OUTPUT ;
    USE SIGNAL ;
    PORT
      LAYER M4 ;
        RECT  64.716 20.112 64.8 20.136 ;
    END
  END sc_o[162]
  PIN sc_o[163]
    DIRECTION OUTPUT ;
    USE SIGNAL ;
    PORT
      LAYER M4 ;
        RECT  64.716 20.208 64.8 20.232 ;
    END
  END sc_o[163]
  PIN sc_o[164]
    DIRECTION OUTPUT ;
    USE SIGNAL ;
    PORT
      LAYER M4 ;
        RECT  64.716 20.304 64.8 20.328 ;
    END
  END sc_o[164]
  PIN sc_o[165]
    DIRECTION OUTPUT ;
    USE SIGNAL ;
    PORT
      LAYER M4 ;
        RECT  64.716 20.4 64.8 20.424 ;
    END
  END sc_o[165]
  PIN sc_o[166]
    DIRECTION OUTPUT ;
    USE SIGNAL ;
    PORT
      LAYER M4 ;
        RECT  64.716 20.496 64.8 20.52 ;
    END
  END sc_o[166]
  PIN sc_o[167]
    DIRECTION OUTPUT ;
    USE SIGNAL ;
    PORT
      LAYER M4 ;
        RECT  64.716 20.592 64.8 20.616 ;
    END
  END sc_o[167]
  PIN sc_o[168]
    DIRECTION OUTPUT ;
    USE SIGNAL ;
    PORT
      LAYER M4 ;
        RECT  64.716 20.688 64.8 20.712 ;
    END
  END sc_o[168]
  PIN sc_o[169]
    DIRECTION OUTPUT ;
    USE SIGNAL ;
    PORT
      LAYER M4 ;
        RECT  64.716 20.784 64.8 20.808 ;
    END
  END sc_o[169]
  PIN sc_o[16]
    DIRECTION OUTPUT ;
    USE SIGNAL ;
    PORT
      LAYER M4 ;
        RECT  64.716 27.6 64.8 27.624 ;
    END
  END sc_o[16]
  PIN sc_o[170]
    DIRECTION OUTPUT ;
    USE SIGNAL ;
    PORT
      LAYER M4 ;
        RECT  64.716 20.88 64.8 20.904 ;
    END
  END sc_o[170]
  PIN sc_o[171]
    DIRECTION OUTPUT ;
    USE SIGNAL ;
    PORT
      LAYER M4 ;
        RECT  64.716 20.976 64.8 21 ;
    END
  END sc_o[171]
  PIN sc_o[172]
    DIRECTION OUTPUT ;
    USE SIGNAL ;
    PORT
      LAYER M4 ;
        RECT  64.716 21.072 64.8 21.096 ;
    END
  END sc_o[172]
  PIN sc_o[173]
    DIRECTION OUTPUT ;
    USE SIGNAL ;
    PORT
      LAYER M4 ;
        RECT  64.716 21.168 64.8 21.192 ;
    END
  END sc_o[173]
  PIN sc_o[174]
    DIRECTION OUTPUT ;
    USE SIGNAL ;
    PORT
      LAYER M4 ;
        RECT  64.716 21.264 64.8 21.288 ;
    END
  END sc_o[174]
  PIN sc_o[175]
    DIRECTION OUTPUT ;
    USE SIGNAL ;
    PORT
      LAYER M4 ;
        RECT  64.716 21.36 64.8 21.384 ;
    END
  END sc_o[175]
  PIN sc_o[176]
    DIRECTION OUTPUT ;
    USE SIGNAL ;
    PORT
      LAYER M4 ;
        RECT  64.716 21.456 64.8 21.48 ;
    END
  END sc_o[176]
  PIN sc_o[177]
    DIRECTION OUTPUT ;
    USE SIGNAL ;
    PORT
      LAYER M4 ;
        RECT  64.716 21.552 64.8 21.576 ;
    END
  END sc_o[177]
  PIN sc_o[178]
    DIRECTION OUTPUT ;
    USE SIGNAL ;
    PORT
      LAYER M4 ;
        RECT  64.716 21.648 64.8 21.672 ;
    END
  END sc_o[178]
  PIN sc_o[179]
    DIRECTION OUTPUT ;
    USE SIGNAL ;
    PORT
      LAYER M4 ;
        RECT  64.716 21.744 64.8 21.768 ;
    END
  END sc_o[179]
  PIN sc_o[17]
    DIRECTION OUTPUT ;
    USE SIGNAL ;
    PORT
      LAYER M4 ;
        RECT  64.716 27.696 64.8 27.72 ;
    END
  END sc_o[17]
  PIN sc_o[180]
    DIRECTION OUTPUT ;
    USE SIGNAL ;
    PORT
      LAYER M4 ;
        RECT  64.716 21.84 64.8 21.864 ;
    END
  END sc_o[180]
  PIN sc_o[181]
    DIRECTION OUTPUT ;
    USE SIGNAL ;
    PORT
      LAYER M4 ;
        RECT  64.716 21.936 64.8 21.96 ;
    END
  END sc_o[181]
  PIN sc_o[182]
    DIRECTION OUTPUT ;
    USE SIGNAL ;
    PORT
      LAYER M4 ;
        RECT  64.716 22.032 64.8 22.056 ;
    END
  END sc_o[182]
  PIN sc_o[183]
    DIRECTION OUTPUT ;
    USE SIGNAL ;
    PORT
      LAYER M4 ;
        RECT  64.716 22.128 64.8 22.152 ;
    END
  END sc_o[183]
  PIN sc_o[184]
    DIRECTION OUTPUT ;
    USE SIGNAL ;
    PORT
      LAYER M4 ;
        RECT  64.716 22.224 64.8 22.248 ;
    END
  END sc_o[184]
  PIN sc_o[185]
    DIRECTION OUTPUT ;
    USE SIGNAL ;
    PORT
      LAYER M4 ;
        RECT  64.716 22.32 64.8 22.344 ;
    END
  END sc_o[185]
  PIN sc_o[186]
    DIRECTION OUTPUT ;
    USE SIGNAL ;
    PORT
      LAYER M4 ;
        RECT  64.716 22.416 64.8 22.44 ;
    END
  END sc_o[186]
  PIN sc_o[187]
    DIRECTION OUTPUT ;
    USE SIGNAL ;
    PORT
      LAYER M4 ;
        RECT  64.716 22.512 64.8 22.536 ;
    END
  END sc_o[187]
  PIN sc_o[188]
    DIRECTION OUTPUT ;
    USE SIGNAL ;
    PORT
      LAYER M4 ;
        RECT  64.716 22.608 64.8 22.632 ;
    END
  END sc_o[188]
  PIN sc_o[189]
    DIRECTION OUTPUT ;
    USE SIGNAL ;
    PORT
      LAYER M4 ;
        RECT  64.716 22.704 64.8 22.728 ;
    END
  END sc_o[189]
  PIN sc_o[18]
    DIRECTION OUTPUT ;
    USE SIGNAL ;
    PORT
      LAYER M4 ;
        RECT  64.716 27.792 64.8 27.816 ;
    END
  END sc_o[18]
  PIN sc_o[190]
    DIRECTION OUTPUT ;
    USE SIGNAL ;
    PORT
      LAYER M4 ;
        RECT  64.716 22.8 64.8 22.824 ;
    END
  END sc_o[190]
  PIN sc_o[191]
    DIRECTION OUTPUT ;
    USE SIGNAL ;
    PORT
      LAYER M4 ;
        RECT  64.716 22.896 64.8 22.92 ;
    END
  END sc_o[191]
  PIN sc_o[192]
    DIRECTION OUTPUT ;
    USE SIGNAL ;
    PORT
      LAYER M4 ;
        RECT  64.716 29.136 64.8 29.16 ;
    END
  END sc_o[192]
  PIN sc_o[193]
    DIRECTION OUTPUT ;
    USE SIGNAL ;
    PORT
      LAYER M4 ;
        RECT  64.716 29.232 64.8 29.256 ;
    END
  END sc_o[193]
  PIN sc_o[194]
    DIRECTION OUTPUT ;
    USE SIGNAL ;
    PORT
      LAYER M4 ;
        RECT  64.716 29.328 64.8 29.352 ;
    END
  END sc_o[194]
  PIN sc_o[195]
    DIRECTION OUTPUT ;
    USE SIGNAL ;
    PORT
      LAYER M4 ;
        RECT  64.716 29.424 64.8 29.448 ;
    END
  END sc_o[195]
  PIN sc_o[196]
    DIRECTION OUTPUT ;
    USE SIGNAL ;
    PORT
      LAYER M4 ;
        RECT  64.716 29.52 64.8 29.544 ;
    END
  END sc_o[196]
  PIN sc_o[197]
    DIRECTION OUTPUT ;
    USE SIGNAL ;
    PORT
      LAYER M4 ;
        RECT  64.716 29.616 64.8 29.64 ;
    END
  END sc_o[197]
  PIN sc_o[198]
    DIRECTION OUTPUT ;
    USE SIGNAL ;
    PORT
      LAYER M4 ;
        RECT  64.716 29.712 64.8 29.736 ;
    END
  END sc_o[198]
  PIN sc_o[199]
    DIRECTION OUTPUT ;
    USE SIGNAL ;
    PORT
      LAYER M4 ;
        RECT  64.716 29.808 64.8 29.832 ;
    END
  END sc_o[199]
  PIN sc_o[19]
    DIRECTION OUTPUT ;
    USE SIGNAL ;
    PORT
      LAYER M4 ;
        RECT  64.716 27.888 64.8 27.912 ;
    END
  END sc_o[19]
  PIN sc_o[1]
    DIRECTION OUTPUT ;
    USE SIGNAL ;
    PORT
      LAYER M4 ;
        RECT  64.716 26.16 64.8 26.184 ;
    END
  END sc_o[1]
  PIN sc_o[200]
    DIRECTION OUTPUT ;
    USE SIGNAL ;
    PORT
      LAYER M4 ;
        RECT  64.716 29.904 64.8 29.928 ;
    END
  END sc_o[200]
  PIN sc_o[201]
    DIRECTION OUTPUT ;
    USE SIGNAL ;
    PORT
      LAYER M4 ;
        RECT  64.716 30 64.8 30.024 ;
    END
  END sc_o[201]
  PIN sc_o[202]
    DIRECTION OUTPUT ;
    USE SIGNAL ;
    PORT
      LAYER M4 ;
        RECT  64.716 30.096 64.8 30.12 ;
    END
  END sc_o[202]
  PIN sc_o[203]
    DIRECTION OUTPUT ;
    USE SIGNAL ;
    PORT
      LAYER M4 ;
        RECT  64.716 30.192 64.8 30.216 ;
    END
  END sc_o[203]
  PIN sc_o[204]
    DIRECTION OUTPUT ;
    USE SIGNAL ;
    PORT
      LAYER M4 ;
        RECT  64.716 30.288 64.8 30.312 ;
    END
  END sc_o[204]
  PIN sc_o[205]
    DIRECTION OUTPUT ;
    USE SIGNAL ;
    PORT
      LAYER M4 ;
        RECT  64.716 30.384 64.8 30.408 ;
    END
  END sc_o[205]
  PIN sc_o[206]
    DIRECTION OUTPUT ;
    USE SIGNAL ;
    PORT
      LAYER M4 ;
        RECT  64.716 30.48 64.8 30.504 ;
    END
  END sc_o[206]
  PIN sc_o[207]
    DIRECTION OUTPUT ;
    USE SIGNAL ;
    PORT
      LAYER M4 ;
        RECT  64.716 30.576 64.8 30.6 ;
    END
  END sc_o[207]
  PIN sc_o[208]
    DIRECTION OUTPUT ;
    USE SIGNAL ;
    PORT
      LAYER M4 ;
        RECT  64.716 30.672 64.8 30.696 ;
    END
  END sc_o[208]
  PIN sc_o[209]
    DIRECTION OUTPUT ;
    USE SIGNAL ;
    PORT
      LAYER M4 ;
        RECT  64.716 30.768 64.8 30.792 ;
    END
  END sc_o[209]
  PIN sc_o[20]
    DIRECTION OUTPUT ;
    USE SIGNAL ;
    PORT
      LAYER M4 ;
        RECT  64.716 27.984 64.8 28.008 ;
    END
  END sc_o[20]
  PIN sc_o[210]
    DIRECTION OUTPUT ;
    USE SIGNAL ;
    PORT
      LAYER M4 ;
        RECT  64.716 30.864 64.8 30.888 ;
    END
  END sc_o[210]
  PIN sc_o[211]
    DIRECTION OUTPUT ;
    USE SIGNAL ;
    PORT
      LAYER M4 ;
        RECT  64.716 30.96 64.8 30.984 ;
    END
  END sc_o[211]
  PIN sc_o[212]
    DIRECTION OUTPUT ;
    USE SIGNAL ;
    PORT
      LAYER M4 ;
        RECT  64.716 31.056 64.8 31.08 ;
    END
  END sc_o[212]
  PIN sc_o[213]
    DIRECTION OUTPUT ;
    USE SIGNAL ;
    PORT
      LAYER M4 ;
        RECT  64.716 31.152 64.8 31.176 ;
    END
  END sc_o[213]
  PIN sc_o[214]
    DIRECTION OUTPUT ;
    USE SIGNAL ;
    PORT
      LAYER M4 ;
        RECT  64.716 31.248 64.8 31.272 ;
    END
  END sc_o[214]
  PIN sc_o[215]
    DIRECTION OUTPUT ;
    USE SIGNAL ;
    PORT
      LAYER M4 ;
        RECT  64.716 31.344 64.8 31.368 ;
    END
  END sc_o[215]
  PIN sc_o[216]
    DIRECTION OUTPUT ;
    USE SIGNAL ;
    PORT
      LAYER M4 ;
        RECT  64.716 31.44 64.8 31.464 ;
    END
  END sc_o[216]
  PIN sc_o[217]
    DIRECTION OUTPUT ;
    USE SIGNAL ;
    PORT
      LAYER M4 ;
        RECT  64.716 31.536 64.8 31.56 ;
    END
  END sc_o[217]
  PIN sc_o[218]
    DIRECTION OUTPUT ;
    USE SIGNAL ;
    PORT
      LAYER M4 ;
        RECT  64.716 31.632 64.8 31.656 ;
    END
  END sc_o[218]
  PIN sc_o[219]
    DIRECTION OUTPUT ;
    USE SIGNAL ;
    PORT
      LAYER M4 ;
        RECT  64.716 31.728 64.8 31.752 ;
    END
  END sc_o[219]
  PIN sc_o[21]
    DIRECTION OUTPUT ;
    USE SIGNAL ;
    PORT
      LAYER M4 ;
        RECT  64.716 28.08 64.8 28.104 ;
    END
  END sc_o[21]
  PIN sc_o[220]
    DIRECTION OUTPUT ;
    USE SIGNAL ;
    PORT
      LAYER M4 ;
        RECT  64.716 31.824 64.8 31.848 ;
    END
  END sc_o[220]
  PIN sc_o[221]
    DIRECTION OUTPUT ;
    USE SIGNAL ;
    PORT
      LAYER M4 ;
        RECT  64.716 31.92 64.8 31.944 ;
    END
  END sc_o[221]
  PIN sc_o[222]
    DIRECTION OUTPUT ;
    USE SIGNAL ;
    PORT
      LAYER M4 ;
        RECT  64.716 32.016 64.8 32.04 ;
    END
  END sc_o[222]
  PIN sc_o[223]
    DIRECTION OUTPUT ;
    USE SIGNAL ;
    PORT
      LAYER M4 ;
        RECT  64.716 32.112 64.8 32.136 ;
    END
  END sc_o[223]
  PIN sc_o[224]
    DIRECTION OUTPUT ;
    USE SIGNAL ;
    PORT
      LAYER M4 ;
        RECT  64.716 16.08 64.8 16.104 ;
    END
  END sc_o[224]
  PIN sc_o[225]
    DIRECTION OUTPUT ;
    USE SIGNAL ;
    PORT
      LAYER M4 ;
        RECT  64.716 16.176 64.8 16.2 ;
    END
  END sc_o[225]
  PIN sc_o[226]
    DIRECTION OUTPUT ;
    USE SIGNAL ;
    PORT
      LAYER M4 ;
        RECT  64.716 16.272 64.8 16.296 ;
    END
  END sc_o[226]
  PIN sc_o[227]
    DIRECTION OUTPUT ;
    USE SIGNAL ;
    PORT
      LAYER M4 ;
        RECT  64.716 16.368 64.8 16.392 ;
    END
  END sc_o[227]
  PIN sc_o[228]
    DIRECTION OUTPUT ;
    USE SIGNAL ;
    PORT
      LAYER M4 ;
        RECT  64.716 16.464 64.8 16.488 ;
    END
  END sc_o[228]
  PIN sc_o[229]
    DIRECTION OUTPUT ;
    USE SIGNAL ;
    PORT
      LAYER M4 ;
        RECT  64.716 16.56 64.8 16.584 ;
    END
  END sc_o[229]
  PIN sc_o[22]
    DIRECTION OUTPUT ;
    USE SIGNAL ;
    PORT
      LAYER M4 ;
        RECT  64.716 28.176 64.8 28.2 ;
    END
  END sc_o[22]
  PIN sc_o[230]
    DIRECTION OUTPUT ;
    USE SIGNAL ;
    PORT
      LAYER M4 ;
        RECT  64.716 16.656 64.8 16.68 ;
    END
  END sc_o[230]
  PIN sc_o[231]
    DIRECTION OUTPUT ;
    USE SIGNAL ;
    PORT
      LAYER M4 ;
        RECT  64.716 16.752 64.8 16.776 ;
    END
  END sc_o[231]
  PIN sc_o[232]
    DIRECTION OUTPUT ;
    USE SIGNAL ;
    PORT
      LAYER M4 ;
        RECT  64.716 16.848 64.8 16.872 ;
    END
  END sc_o[232]
  PIN sc_o[233]
    DIRECTION OUTPUT ;
    USE SIGNAL ;
    PORT
      LAYER M4 ;
        RECT  64.716 16.944 64.8 16.968 ;
    END
  END sc_o[233]
  PIN sc_o[234]
    DIRECTION OUTPUT ;
    USE SIGNAL ;
    PORT
      LAYER M4 ;
        RECT  64.716 17.04 64.8 17.064 ;
    END
  END sc_o[234]
  PIN sc_o[235]
    DIRECTION OUTPUT ;
    USE SIGNAL ;
    PORT
      LAYER M4 ;
        RECT  64.716 17.136 64.8 17.16 ;
    END
  END sc_o[235]
  PIN sc_o[236]
    DIRECTION OUTPUT ;
    USE SIGNAL ;
    PORT
      LAYER M4 ;
        RECT  64.716 17.232 64.8 17.256 ;
    END
  END sc_o[236]
  PIN sc_o[237]
    DIRECTION OUTPUT ;
    USE SIGNAL ;
    PORT
      LAYER M4 ;
        RECT  64.716 17.328 64.8 17.352 ;
    END
  END sc_o[237]
  PIN sc_o[238]
    DIRECTION OUTPUT ;
    USE SIGNAL ;
    PORT
      LAYER M4 ;
        RECT  64.716 17.424 64.8 17.448 ;
    END
  END sc_o[238]
  PIN sc_o[239]
    DIRECTION OUTPUT ;
    USE SIGNAL ;
    PORT
      LAYER M4 ;
        RECT  64.716 17.52 64.8 17.544 ;
    END
  END sc_o[239]
  PIN sc_o[23]
    DIRECTION OUTPUT ;
    USE SIGNAL ;
    PORT
      LAYER M4 ;
        RECT  64.716 28.272 64.8 28.296 ;
    END
  END sc_o[23]
  PIN sc_o[240]
    DIRECTION OUTPUT ;
    USE SIGNAL ;
    PORT
      LAYER M4 ;
        RECT  64.716 17.616 64.8 17.64 ;
    END
  END sc_o[240]
  PIN sc_o[241]
    DIRECTION OUTPUT ;
    USE SIGNAL ;
    PORT
      LAYER M4 ;
        RECT  64.716 17.712 64.8 17.736 ;
    END
  END sc_o[241]
  PIN sc_o[242]
    DIRECTION OUTPUT ;
    USE SIGNAL ;
    PORT
      LAYER M4 ;
        RECT  64.716 17.808 64.8 17.832 ;
    END
  END sc_o[242]
  PIN sc_o[243]
    DIRECTION OUTPUT ;
    USE SIGNAL ;
    PORT
      LAYER M4 ;
        RECT  64.716 17.904 64.8 17.928 ;
    END
  END sc_o[243]
  PIN sc_o[244]
    DIRECTION OUTPUT ;
    USE SIGNAL ;
    PORT
      LAYER M4 ;
        RECT  64.716 18 64.8 18.024 ;
    END
  END sc_o[244]
  PIN sc_o[245]
    DIRECTION OUTPUT ;
    USE SIGNAL ;
    PORT
      LAYER M4 ;
        RECT  64.716 18.096 64.8 18.12 ;
    END
  END sc_o[245]
  PIN sc_o[246]
    DIRECTION OUTPUT ;
    USE SIGNAL ;
    PORT
      LAYER M4 ;
        RECT  64.716 18.192 64.8 18.216 ;
    END
  END sc_o[246]
  PIN sc_o[247]
    DIRECTION OUTPUT ;
    USE SIGNAL ;
    PORT
      LAYER M4 ;
        RECT  64.716 18.288 64.8 18.312 ;
    END
  END sc_o[247]
  PIN sc_o[248]
    DIRECTION OUTPUT ;
    USE SIGNAL ;
    PORT
      LAYER M4 ;
        RECT  64.716 18.384 64.8 18.408 ;
    END
  END sc_o[248]
  PIN sc_o[249]
    DIRECTION OUTPUT ;
    USE SIGNAL ;
    PORT
      LAYER M4 ;
        RECT  64.716 18.48 64.8 18.504 ;
    END
  END sc_o[249]
  PIN sc_o[24]
    DIRECTION OUTPUT ;
    USE SIGNAL ;
    PORT
      LAYER M4 ;
        RECT  64.716 28.368 64.8 28.392 ;
    END
  END sc_o[24]
  PIN sc_o[250]
    DIRECTION OUTPUT ;
    USE SIGNAL ;
    PORT
      LAYER M4 ;
        RECT  64.716 18.576 64.8 18.6 ;
    END
  END sc_o[250]
  PIN sc_o[251]
    DIRECTION OUTPUT ;
    USE SIGNAL ;
    PORT
      LAYER M4 ;
        RECT  64.716 18.672 64.8 18.696 ;
    END
  END sc_o[251]
  PIN sc_o[252]
    DIRECTION OUTPUT ;
    USE SIGNAL ;
    PORT
      LAYER M4 ;
        RECT  64.716 18.768 64.8 18.792 ;
    END
  END sc_o[252]
  PIN sc_o[253]
    DIRECTION OUTPUT ;
    USE SIGNAL ;
    PORT
      LAYER M4 ;
        RECT  64.716 18.864 64.8 18.888 ;
    END
  END sc_o[253]
  PIN sc_o[254]
    DIRECTION OUTPUT ;
    USE SIGNAL ;
    PORT
      LAYER M4 ;
        RECT  64.716 18.96 64.8 18.984 ;
    END
  END sc_o[254]
  PIN sc_o[255]
    DIRECTION OUTPUT ;
    USE SIGNAL ;
    PORT
      LAYER M4 ;
        RECT  64.716 19.056 64.8 19.08 ;
    END
  END sc_o[255]
  PIN sc_o[256]
    DIRECTION OUTPUT ;
    USE SIGNAL ;
    PORT
      LAYER M4 ;
        RECT  64.716 54.48 64.8 54.504 ;
    END
  END sc_o[256]
  PIN sc_o[257]
    DIRECTION OUTPUT ;
    USE SIGNAL ;
    PORT
      LAYER M4 ;
        RECT  64.716 54.576 64.8 54.6 ;
    END
  END sc_o[257]
  PIN sc_o[258]
    DIRECTION OUTPUT ;
    USE SIGNAL ;
    PORT
      LAYER M4 ;
        RECT  64.716 54.672 64.8 54.696 ;
    END
  END sc_o[258]
  PIN sc_o[25]
    DIRECTION OUTPUT ;
    USE SIGNAL ;
    PORT
      LAYER M4 ;
        RECT  64.716 28.464 64.8 28.488 ;
    END
  END sc_o[25]
  PIN sc_o[26]
    DIRECTION OUTPUT ;
    USE SIGNAL ;
    PORT
      LAYER M4 ;
        RECT  64.716 28.56 64.8 28.584 ;
    END
  END sc_o[26]
  PIN sc_o[27]
    DIRECTION OUTPUT ;
    USE SIGNAL ;
    PORT
      LAYER M4 ;
        RECT  64.716 28.656 64.8 28.68 ;
    END
  END sc_o[27]
  PIN sc_o[28]
    DIRECTION OUTPUT ;
    USE SIGNAL ;
    PORT
      LAYER M4 ;
        RECT  64.716 28.752 64.8 28.776 ;
    END
  END sc_o[28]
  PIN sc_o[29]
    DIRECTION OUTPUT ;
    USE SIGNAL ;
    PORT
      LAYER M4 ;
        RECT  64.716 28.848 64.8 28.872 ;
    END
  END sc_o[29]
  PIN sc_o[2]
    DIRECTION OUTPUT ;
    USE SIGNAL ;
    PORT
      LAYER M4 ;
        RECT  64.716 26.256 64.8 26.28 ;
    END
  END sc_o[2]
  PIN sc_o[30]
    DIRECTION OUTPUT ;
    USE SIGNAL ;
    PORT
      LAYER M4 ;
        RECT  64.716 28.944 64.8 28.968 ;
    END
  END sc_o[30]
  PIN sc_o[31]
    DIRECTION OUTPUT ;
    USE SIGNAL ;
    PORT
      LAYER M4 ;
        RECT  64.716 29.04 64.8 29.064 ;
    END
  END sc_o[31]
  PIN sc_o[32]
    DIRECTION OUTPUT ;
    USE SIGNAL ;
    PORT
      LAYER M4 ;
        RECT  64.716 32.208 64.8 32.232 ;
    END
  END sc_o[32]
  PIN sc_o[33]
    DIRECTION OUTPUT ;
    USE SIGNAL ;
    PORT
      LAYER M4 ;
        RECT  64.716 32.304 64.8 32.328 ;
    END
  END sc_o[33]
  PIN sc_o[34]
    DIRECTION OUTPUT ;
    USE SIGNAL ;
    PORT
      LAYER M4 ;
        RECT  64.716 32.4 64.8 32.424 ;
    END
  END sc_o[34]
  PIN sc_o[35]
    DIRECTION OUTPUT ;
    USE SIGNAL ;
    PORT
      LAYER M4 ;
        RECT  64.716 32.496 64.8 32.52 ;
    END
  END sc_o[35]
  PIN sc_o[36]
    DIRECTION OUTPUT ;
    USE SIGNAL ;
    PORT
      LAYER M4 ;
        RECT  64.716 32.592 64.8 32.616 ;
    END
  END sc_o[36]
  PIN sc_o[37]
    DIRECTION OUTPUT ;
    USE SIGNAL ;
    PORT
      LAYER M4 ;
        RECT  64.716 32.688 64.8 32.712 ;
    END
  END sc_o[37]
  PIN sc_o[38]
    DIRECTION OUTPUT ;
    USE SIGNAL ;
    PORT
      LAYER M4 ;
        RECT  64.716 32.784 64.8 32.808 ;
    END
  END sc_o[38]
  PIN sc_o[39]
    DIRECTION OUTPUT ;
    USE SIGNAL ;
    PORT
      LAYER M4 ;
        RECT  64.716 32.88 64.8 32.904 ;
    END
  END sc_o[39]
  PIN sc_o[3]
    DIRECTION OUTPUT ;
    USE SIGNAL ;
    PORT
      LAYER M4 ;
        RECT  64.716 26.352 64.8 26.376 ;
    END
  END sc_o[3]
  PIN sc_o[40]
    DIRECTION OUTPUT ;
    USE SIGNAL ;
    PORT
      LAYER M4 ;
        RECT  64.716 32.976 64.8 33 ;
    END
  END sc_o[40]
  PIN sc_o[41]
    DIRECTION OUTPUT ;
    USE SIGNAL ;
    PORT
      LAYER M4 ;
        RECT  64.716 33.072 64.8 33.096 ;
    END
  END sc_o[41]
  PIN sc_o[42]
    DIRECTION OUTPUT ;
    USE SIGNAL ;
    PORT
      LAYER M4 ;
        RECT  64.716 33.168 64.8 33.192 ;
    END
  END sc_o[42]
  PIN sc_o[43]
    DIRECTION OUTPUT ;
    USE SIGNAL ;
    PORT
      LAYER M4 ;
        RECT  64.716 33.264 64.8 33.288 ;
    END
  END sc_o[43]
  PIN sc_o[44]
    DIRECTION OUTPUT ;
    USE SIGNAL ;
    PORT
      LAYER M4 ;
        RECT  64.716 33.36 64.8 33.384 ;
    END
  END sc_o[44]
  PIN sc_o[45]
    DIRECTION OUTPUT ;
    USE SIGNAL ;
    PORT
      LAYER M4 ;
        RECT  64.716 33.456 64.8 33.48 ;
    END
  END sc_o[45]
  PIN sc_o[46]
    DIRECTION OUTPUT ;
    USE SIGNAL ;
    PORT
      LAYER M4 ;
        RECT  64.716 33.552 64.8 33.576 ;
    END
  END sc_o[46]
  PIN sc_o[47]
    DIRECTION OUTPUT ;
    USE SIGNAL ;
    PORT
      LAYER M4 ;
        RECT  64.716 33.648 64.8 33.672 ;
    END
  END sc_o[47]
  PIN sc_o[48]
    DIRECTION OUTPUT ;
    USE SIGNAL ;
    PORT
      LAYER M4 ;
        RECT  64.716 33.744 64.8 33.768 ;
    END
  END sc_o[48]
  PIN sc_o[49]
    DIRECTION OUTPUT ;
    USE SIGNAL ;
    PORT
      LAYER M4 ;
        RECT  64.716 33.84 64.8 33.864 ;
    END
  END sc_o[49]
  PIN sc_o[4]
    DIRECTION OUTPUT ;
    USE SIGNAL ;
    PORT
      LAYER M4 ;
        RECT  64.716 26.448 64.8 26.472 ;
    END
  END sc_o[4]
  PIN sc_o[50]
    DIRECTION OUTPUT ;
    USE SIGNAL ;
    PORT
      LAYER M4 ;
        RECT  64.716 33.936 64.8 33.96 ;
    END
  END sc_o[50]
  PIN sc_o[51]
    DIRECTION OUTPUT ;
    USE SIGNAL ;
    PORT
      LAYER M4 ;
        RECT  64.716 34.032 64.8 34.056 ;
    END
  END sc_o[51]
  PIN sc_o[52]
    DIRECTION OUTPUT ;
    USE SIGNAL ;
    PORT
      LAYER M4 ;
        RECT  64.716 34.128 64.8 34.152 ;
    END
  END sc_o[52]
  PIN sc_o[53]
    DIRECTION OUTPUT ;
    USE SIGNAL ;
    PORT
      LAYER M4 ;
        RECT  64.716 34.224 64.8 34.248 ;
    END
  END sc_o[53]
  PIN sc_o[54]
    DIRECTION OUTPUT ;
    USE SIGNAL ;
    PORT
      LAYER M4 ;
        RECT  64.716 34.32 64.8 34.344 ;
    END
  END sc_o[54]
  PIN sc_o[55]
    DIRECTION OUTPUT ;
    USE SIGNAL ;
    PORT
      LAYER M4 ;
        RECT  64.716 34.416 64.8 34.44 ;
    END
  END sc_o[55]
  PIN sc_o[56]
    DIRECTION OUTPUT ;
    USE SIGNAL ;
    PORT
      LAYER M4 ;
        RECT  64.716 34.512 64.8 34.536 ;
    END
  END sc_o[56]
  PIN sc_o[57]
    DIRECTION OUTPUT ;
    USE SIGNAL ;
    PORT
      LAYER M4 ;
        RECT  64.716 34.608 64.8 34.632 ;
    END
  END sc_o[57]
  PIN sc_o[58]
    DIRECTION OUTPUT ;
    USE SIGNAL ;
    PORT
      LAYER M4 ;
        RECT  64.716 34.704 64.8 34.728 ;
    END
  END sc_o[58]
  PIN sc_o[59]
    DIRECTION OUTPUT ;
    USE SIGNAL ;
    PORT
      LAYER M4 ;
        RECT  64.716 34.8 64.8 34.824 ;
    END
  END sc_o[59]
  PIN sc_o[5]
    DIRECTION OUTPUT ;
    USE SIGNAL ;
    PORT
      LAYER M4 ;
        RECT  64.716 26.544 64.8 26.568 ;
    END
  END sc_o[5]
  PIN sc_o[60]
    DIRECTION OUTPUT ;
    USE SIGNAL ;
    PORT
      LAYER M4 ;
        RECT  64.716 34.896 64.8 34.92 ;
    END
  END sc_o[60]
  PIN sc_o[61]
    DIRECTION OUTPUT ;
    USE SIGNAL ;
    PORT
      LAYER M4 ;
        RECT  64.716 34.992 64.8 35.016 ;
    END
  END sc_o[61]
  PIN sc_o[62]
    DIRECTION OUTPUT ;
    USE SIGNAL ;
    PORT
      LAYER M4 ;
        RECT  64.716 35.088 64.8 35.112 ;
    END
  END sc_o[62]
  PIN sc_o[63]
    DIRECTION OUTPUT ;
    USE SIGNAL ;
    PORT
      LAYER M4 ;
        RECT  64.716 35.184 64.8 35.208 ;
    END
  END sc_o[63]
  PIN sc_o[64]
    DIRECTION OUTPUT ;
    USE SIGNAL ;
    PORT
      LAYER M4 ;
        RECT  64.716 42.192 64.8 42.216 ;
    END
  END sc_o[64]
  PIN sc_o[65]
    DIRECTION OUTPUT ;
    USE SIGNAL ;
    PORT
      LAYER M4 ;
        RECT  64.716 42.288 64.8 42.312 ;
    END
  END sc_o[65]
  PIN sc_o[66]
    DIRECTION OUTPUT ;
    USE SIGNAL ;
    PORT
      LAYER M4 ;
        RECT  64.716 42.384 64.8 42.408 ;
    END
  END sc_o[66]
  PIN sc_o[67]
    DIRECTION OUTPUT ;
    USE SIGNAL ;
    PORT
      LAYER M4 ;
        RECT  64.716 42.48 64.8 42.504 ;
    END
  END sc_o[67]
  PIN sc_o[68]
    DIRECTION OUTPUT ;
    USE SIGNAL ;
    PORT
      LAYER M4 ;
        RECT  64.716 42.576 64.8 42.6 ;
    END
  END sc_o[68]
  PIN sc_o[69]
    DIRECTION OUTPUT ;
    USE SIGNAL ;
    PORT
      LAYER M4 ;
        RECT  64.716 42.672 64.8 42.696 ;
    END
  END sc_o[69]
  PIN sc_o[6]
    DIRECTION OUTPUT ;
    USE SIGNAL ;
    PORT
      LAYER M4 ;
        RECT  64.716 26.64 64.8 26.664 ;
    END
  END sc_o[6]
  PIN sc_o[70]
    DIRECTION OUTPUT ;
    USE SIGNAL ;
    PORT
      LAYER M4 ;
        RECT  64.716 42.768 64.8 42.792 ;
    END
  END sc_o[70]
  PIN sc_o[71]
    DIRECTION OUTPUT ;
    USE SIGNAL ;
    PORT
      LAYER M4 ;
        RECT  64.716 42.864 64.8 42.888 ;
    END
  END sc_o[71]
  PIN sc_o[72]
    DIRECTION OUTPUT ;
    USE SIGNAL ;
    PORT
      LAYER M4 ;
        RECT  64.716 42.96 64.8 42.984 ;
    END
  END sc_o[72]
  PIN sc_o[73]
    DIRECTION OUTPUT ;
    USE SIGNAL ;
    PORT
      LAYER M4 ;
        RECT  64.716 43.056 64.8 43.08 ;
    END
  END sc_o[73]
  PIN sc_o[74]
    DIRECTION OUTPUT ;
    USE SIGNAL ;
    PORT
      LAYER M4 ;
        RECT  64.716 43.152 64.8 43.176 ;
    END
  END sc_o[74]
  PIN sc_o[75]
    DIRECTION OUTPUT ;
    USE SIGNAL ;
    PORT
      LAYER M4 ;
        RECT  64.716 43.248 64.8 43.272 ;
    END
  END sc_o[75]
  PIN sc_o[76]
    DIRECTION OUTPUT ;
    USE SIGNAL ;
    PORT
      LAYER M4 ;
        RECT  64.716 43.344 64.8 43.368 ;
    END
  END sc_o[76]
  PIN sc_o[77]
    DIRECTION OUTPUT ;
    USE SIGNAL ;
    PORT
      LAYER M4 ;
        RECT  64.716 43.44 64.8 43.464 ;
    END
  END sc_o[77]
  PIN sc_o[78]
    DIRECTION OUTPUT ;
    USE SIGNAL ;
    PORT
      LAYER M4 ;
        RECT  64.716 43.536 64.8 43.56 ;
    END
  END sc_o[78]
  PIN sc_o[79]
    DIRECTION OUTPUT ;
    USE SIGNAL ;
    PORT
      LAYER M4 ;
        RECT  64.716 43.632 64.8 43.656 ;
    END
  END sc_o[79]
  PIN sc_o[7]
    DIRECTION OUTPUT ;
    USE SIGNAL ;
    PORT
      LAYER M4 ;
        RECT  64.716 26.736 64.8 26.76 ;
    END
  END sc_o[7]
  PIN sc_o[80]
    DIRECTION OUTPUT ;
    USE SIGNAL ;
    PORT
      LAYER M4 ;
        RECT  64.716 43.728 64.8 43.752 ;
    END
  END sc_o[80]
  PIN sc_o[81]
    DIRECTION OUTPUT ;
    USE SIGNAL ;
    PORT
      LAYER M4 ;
        RECT  64.716 43.824 64.8 43.848 ;
    END
  END sc_o[81]
  PIN sc_o[82]
    DIRECTION OUTPUT ;
    USE SIGNAL ;
    PORT
      LAYER M4 ;
        RECT  64.716 43.92 64.8 43.944 ;
    END
  END sc_o[82]
  PIN sc_o[83]
    DIRECTION OUTPUT ;
    USE SIGNAL ;
    PORT
      LAYER M4 ;
        RECT  64.716 44.016 64.8 44.04 ;
    END
  END sc_o[83]
  PIN sc_o[84]
    DIRECTION OUTPUT ;
    USE SIGNAL ;
    PORT
      LAYER M4 ;
        RECT  64.716 44.112 64.8 44.136 ;
    END
  END sc_o[84]
  PIN sc_o[85]
    DIRECTION OUTPUT ;
    USE SIGNAL ;
    PORT
      LAYER M4 ;
        RECT  64.716 44.208 64.8 44.232 ;
    END
  END sc_o[85]
  PIN sc_o[86]
    DIRECTION OUTPUT ;
    USE SIGNAL ;
    PORT
      LAYER M4 ;
        RECT  64.716 44.304 64.8 44.328 ;
    END
  END sc_o[86]
  PIN sc_o[87]
    DIRECTION OUTPUT ;
    USE SIGNAL ;
    PORT
      LAYER M4 ;
        RECT  64.716 44.4 64.8 44.424 ;
    END
  END sc_o[87]
  PIN sc_o[88]
    DIRECTION OUTPUT ;
    USE SIGNAL ;
    PORT
      LAYER M4 ;
        RECT  64.716 44.496 64.8 44.52 ;
    END
  END sc_o[88]
  PIN sc_o[89]
    DIRECTION OUTPUT ;
    USE SIGNAL ;
    PORT
      LAYER M4 ;
        RECT  64.716 44.592 64.8 44.616 ;
    END
  END sc_o[89]
  PIN sc_o[8]
    DIRECTION OUTPUT ;
    USE SIGNAL ;
    PORT
      LAYER M4 ;
        RECT  64.716 26.832 64.8 26.856 ;
    END
  END sc_o[8]
  PIN sc_o[90]
    DIRECTION OUTPUT ;
    USE SIGNAL ;
    PORT
      LAYER M4 ;
        RECT  64.716 44.688 64.8 44.712 ;
    END
  END sc_o[90]
  PIN sc_o[91]
    DIRECTION OUTPUT ;
    USE SIGNAL ;
    PORT
      LAYER M4 ;
        RECT  64.716 44.784 64.8 44.808 ;
    END
  END sc_o[91]
  PIN sc_o[92]
    DIRECTION OUTPUT ;
    USE SIGNAL ;
    PORT
      LAYER M4 ;
        RECT  64.716 44.88 64.8 44.904 ;
    END
  END sc_o[92]
  PIN sc_o[93]
    DIRECTION OUTPUT ;
    USE SIGNAL ;
    PORT
      LAYER M4 ;
        RECT  64.716 44.976 64.8 45 ;
    END
  END sc_o[93]
  PIN sc_o[94]
    DIRECTION OUTPUT ;
    USE SIGNAL ;
    PORT
      LAYER M4 ;
        RECT  64.716 45.072 64.8 45.096 ;
    END
  END sc_o[94]
  PIN sc_o[95]
    DIRECTION OUTPUT ;
    USE SIGNAL ;
    PORT
      LAYER M4 ;
        RECT  64.716 45.168 64.8 45.192 ;
    END
  END sc_o[95]
  PIN sc_o[96]
    DIRECTION OUTPUT ;
    USE SIGNAL ;
    PORT
      LAYER M4 ;
        RECT  64.716 35.28 64.8 35.304 ;
    END
  END sc_o[96]
  PIN sc_o[97]
    DIRECTION OUTPUT ;
    USE SIGNAL ;
    PORT
      LAYER M4 ;
        RECT  64.716 35.376 64.8 35.4 ;
    END
  END sc_o[97]
  PIN sc_o[98]
    DIRECTION OUTPUT ;
    USE SIGNAL ;
    PORT
      LAYER M4 ;
        RECT  64.716 35.472 64.8 35.496 ;
    END
  END sc_o[98]
  PIN sc_o[99]
    DIRECTION OUTPUT ;
    USE SIGNAL ;
    PORT
      LAYER M4 ;
        RECT  64.716 35.568 64.8 35.592 ;
    END
  END sc_o[99]
  PIN sc_o[9]
    DIRECTION OUTPUT ;
    USE SIGNAL ;
    PORT
      LAYER M4 ;
        RECT  64.716 26.928 64.8 26.952 ;
    END
  END sc_o[9]
  PIN VDD
    DIRECTION INOUT ;
    USE POWER ;
    PORT
      LAYER M5 ;
        RECT  61.992 2.151 62.112 62.649 ;
        RECT  56.592 2.151 56.712 62.649 ;
        RECT  51.192 2.151 51.312 62.649 ;
        RECT  45.792 2.151 45.912 62.649 ;
        RECT  40.392 2.151 40.512 62.649 ;
        RECT  34.992 2.151 35.112 62.649 ;
        RECT  29.592 2.151 29.712 62.649 ;
        RECT  24.192 2.151 24.312 62.649 ;
        RECT  18.792 2.151 18.912 62.649 ;
        RECT  13.392 2.151 13.512 62.649 ;
        RECT  7.992 2.151 8.112 62.649 ;
        RECT  2.592 2.151 2.712 62.649 ;
    END
  END VDD
  PIN VSS
    DIRECTION INOUT ;
    USE GROUND ;
    PORT
      LAYER M5 ;
        RECT  61.8 2.137 61.92 62.663 ;
        RECT  56.4 2.137 56.52 62.663 ;
        RECT  51 2.137 51.12 62.663 ;
        RECT  45.6 2.137 45.72 62.663 ;
        RECT  40.2 2.137 40.32 62.663 ;
        RECT  34.8 2.137 34.92 62.663 ;
        RECT  29.4 2.137 29.52 62.663 ;
        RECT  24 2.137 24.12 62.663 ;
        RECT  18.6 2.137 18.72 62.663 ;
        RECT  13.2 2.137 13.32 62.663 ;
        RECT  7.8 2.137 7.92 62.663 ;
        RECT  2.4 2.137 2.52 62.663 ;
    END
  END VSS
  # OT_OBS_CLOSED layer=M5 d_um=1.536 added=185
  OBS
    LAYER RVTN ;
     RECT  2.16 2.16 62.64 2.295 ;
     RECT  2.16 2.565 62.64 2.835 ;
     RECT  2.16 3.105 62.64 3.375 ;
     RECT  2.16 3.645 62.64 3.915 ;
     RECT  2.16 4.185 62.64 4.455 ;
     RECT  2.16 4.725 62.64 4.995 ;
     RECT  2.16 5.265 62.64 5.535 ;
     RECT  2.16 5.805 62.64 6.075 ;
     RECT  2.16 6.345 62.64 6.615 ;
     RECT  2.16 6.885 62.64 7.155 ;
     RECT  2.16 7.425 62.64 7.695 ;
     RECT  2.16 7.965 62.64 8.235 ;
     RECT  2.16 8.505 62.64 8.775 ;
     RECT  2.16 9.045 62.64 9.315 ;
     RECT  2.16 9.585 62.64 9.855 ;
     RECT  2.16 10.125 62.64 10.395 ;
     RECT  2.16 10.665 62.64 10.935 ;
     RECT  2.16 11.205 62.64 11.475 ;
     RECT  2.16 11.745 62.64 12.015 ;
     RECT  2.16 12.285 62.64 12.555 ;
     RECT  2.16 12.825 62.64 13.095 ;
     RECT  2.16 13.365 62.64 13.635 ;
     RECT  2.16 13.905 62.64 14.175 ;
     RECT  2.16 14.445 62.64 14.715 ;
     RECT  2.16 14.985 62.64 15.255 ;
     RECT  2.16 15.525 62.64 15.795 ;
     RECT  2.16 16.065 62.64 16.335 ;
     RECT  2.16 16.605 62.64 16.875 ;
     RECT  2.16 17.145 62.64 17.415 ;
     RECT  2.16 17.685 62.64 17.955 ;
     RECT  2.16 18.225 62.64 18.495 ;
     RECT  2.16 18.765 62.64 19.035 ;
     RECT  2.16 19.305 62.64 19.575 ;
     RECT  2.16 19.845 62.64 20.115 ;
     RECT  2.16 20.385 62.64 20.655 ;
     RECT  2.16 20.925 62.64 21.195 ;
     RECT  2.16 21.465 62.64 21.735 ;
     RECT  2.16 22.005 62.64 22.275 ;
     RECT  2.16 22.545 62.64 22.815 ;
     RECT  2.16 23.085 62.64 23.355 ;
     RECT  2.16 23.625 62.64 23.895 ;
     RECT  2.16 24.165 62.64 24.435 ;
     RECT  2.16 24.705 62.64 24.975 ;
     RECT  2.16 25.245 62.64 25.515 ;
     RECT  2.16 25.785 62.64 26.055 ;
     RECT  2.16 26.325 62.64 26.595 ;
     RECT  2.16 26.865 62.64 27.135 ;
     RECT  2.16 27.405 62.64 27.675 ;
     RECT  2.16 27.945 62.64 28.215 ;
     RECT  2.16 28.485 62.64 28.755 ;
     RECT  2.16 29.025 62.64 29.295 ;
     RECT  2.16 29.565 62.64 29.835 ;
     RECT  2.16 30.105 62.64 30.375 ;
     RECT  2.16 30.645 62.64 30.915 ;
     RECT  2.16 31.185 62.64 31.455 ;
     RECT  2.16 31.725 62.64 31.995 ;
     RECT  2.16 32.265 62.64 32.535 ;
     RECT  2.16 32.805 62.64 33.075 ;
     RECT  2.16 33.345 62.64 33.615 ;
     RECT  2.16 33.885 62.64 34.155 ;
     RECT  2.16 34.425 62.64 34.695 ;
     RECT  2.16 34.965 62.64 35.235 ;
     RECT  2.16 35.505 62.64 35.775 ;
     RECT  2.16 36.045 62.64 36.315 ;
     RECT  2.16 36.585 62.64 36.855 ;
     RECT  2.16 37.125 62.64 37.395 ;
     RECT  2.16 37.665 62.64 37.935 ;
     RECT  2.16 38.205 62.64 38.475 ;
     RECT  2.16 38.745 62.64 39.015 ;
     RECT  2.16 39.285 62.64 39.555 ;
     RECT  2.16 39.825 62.64 40.095 ;
     RECT  2.16 40.365 62.64 40.635 ;
     RECT  2.16 40.905 62.64 41.175 ;
     RECT  2.16 41.445 62.64 41.715 ;
     RECT  2.16 41.985 62.64 42.255 ;
     RECT  2.16 42.525 62.64 42.795 ;
     RECT  2.16 43.065 62.64 43.335 ;
     RECT  2.16 43.605 62.64 43.875 ;
     RECT  2.16 44.145 62.64 44.415 ;
     RECT  2.16 44.685 62.64 44.955 ;
     RECT  2.16 45.225 62.64 45.495 ;
     RECT  2.16 45.765 62.64 46.035 ;
     RECT  2.16 46.305 62.64 46.575 ;
     RECT  2.16 46.845 62.64 47.115 ;
     RECT  2.16 47.385 62.64 47.655 ;
     RECT  2.16 47.925 62.64 48.195 ;
     RECT  2.16 48.465 62.64 48.735 ;
     RECT  2.16 49.005 62.64 49.275 ;
     RECT  2.16 49.545 62.64 49.815 ;
     RECT  2.16 50.085 62.64 50.355 ;
     RECT  2.16 50.625 62.64 50.895 ;
     RECT  2.16 51.165 62.64 51.435 ;
     RECT  2.16 51.705 62.64 51.975 ;
     RECT  2.16 52.245 62.64 52.515 ;
     RECT  2.16 52.785 62.64 53.055 ;
     RECT  2.16 53.325 62.64 53.595 ;
     RECT  2.16 53.865 62.64 54.135 ;
     RECT  2.16 54.405 62.64 54.675 ;
     RECT  2.16 54.945 62.64 55.215 ;
     RECT  2.16 55.485 62.64 55.755 ;
     RECT  2.16 56.025 62.64 56.295 ;
     RECT  2.16 56.565 62.64 56.835 ;
     RECT  2.16 57.105 62.64 57.375 ;
     RECT  2.16 57.645 62.64 57.915 ;
     RECT  2.16 58.185 62.64 58.455 ;
     RECT  2.16 58.725 62.64 58.995 ;
     RECT  2.16 59.265 62.64 59.535 ;
     RECT  2.16 59.805 62.64 60.075 ;
     RECT  2.16 60.345 62.64 60.615 ;
     RECT  2.16 60.885 62.64 61.155 ;
     RECT  2.16 61.425 62.64 61.695 ;
     RECT  2.16 61.965 62.64 62.235 ;
     RECT  2.16 62.505 62.64 62.64 ;
    LAYER RVTP ;
     RECT  2.16 2.295 62.64 2.565 ;
     RECT  2.16 2.835 62.64 3.105 ;
     RECT  2.16 3.375 62.64 3.645 ;
     RECT  2.16 3.915 62.64 4.185 ;
     RECT  2.16 4.455 62.64 4.725 ;
     RECT  2.16 4.995 62.64 5.265 ;
     RECT  2.16 5.535 62.64 5.805 ;
     RECT  2.16 6.075 62.64 6.345 ;
     RECT  2.16 6.615 62.64 6.885 ;
     RECT  2.16 7.155 62.64 7.425 ;
     RECT  2.16 7.695 62.64 7.965 ;
     RECT  2.16 8.235 62.64 8.505 ;
     RECT  2.16 8.775 62.64 9.045 ;
     RECT  2.16 9.315 62.64 9.585 ;
     RECT  2.16 9.855 62.64 10.125 ;
     RECT  2.16 10.395 62.64 10.665 ;
     RECT  2.16 10.935 62.64 11.205 ;
     RECT  2.16 11.475 62.64 11.745 ;
     RECT  2.16 12.015 62.64 12.285 ;
     RECT  2.16 12.555 62.64 12.825 ;
     RECT  2.16 13.095 62.64 13.365 ;
     RECT  2.16 13.635 62.64 13.905 ;
     RECT  2.16 14.175 62.64 14.445 ;
     RECT  2.16 14.715 62.64 14.985 ;
     RECT  2.16 15.255 62.64 15.525 ;
     RECT  2.16 15.795 62.64 16.065 ;
     RECT  2.16 16.335 62.64 16.605 ;
     RECT  2.16 16.875 62.64 17.145 ;
     RECT  2.16 17.415 62.64 17.685 ;
     RECT  2.16 17.955 62.64 18.225 ;
     RECT  2.16 18.495 62.64 18.765 ;
     RECT  2.16 19.035 62.64 19.305 ;
     RECT  2.16 19.575 62.64 19.845 ;
     RECT  2.16 20.115 62.64 20.385 ;
     RECT  2.16 20.655 62.64 20.925 ;
     RECT  2.16 21.195 62.64 21.465 ;
     RECT  2.16 21.735 62.64 22.005 ;
     RECT  2.16 22.275 62.64 22.545 ;
     RECT  2.16 22.815 62.64 23.085 ;
     RECT  2.16 23.355 62.64 23.625 ;
     RECT  2.16 23.895 62.64 24.165 ;
     RECT  2.16 24.435 62.64 24.705 ;
     RECT  2.16 24.975 62.64 25.245 ;
     RECT  2.16 25.515 62.64 25.785 ;
     RECT  2.16 26.055 62.64 26.325 ;
     RECT  2.16 26.595 62.64 26.865 ;
     RECT  2.16 27.135 62.64 27.405 ;
     RECT  2.16 27.675 62.64 27.945 ;
     RECT  2.16 28.215 62.64 28.485 ;
     RECT  2.16 28.755 62.64 29.025 ;
     RECT  2.16 29.295 62.64 29.565 ;
     RECT  2.16 29.835 62.64 30.105 ;
     RECT  2.16 30.375 62.64 30.645 ;
     RECT  2.16 30.915 62.64 31.185 ;
     RECT  2.16 31.455 62.64 31.725 ;
     RECT  2.16 31.995 62.64 32.265 ;
     RECT  2.16 32.535 62.64 32.805 ;
     RECT  2.16 33.075 62.64 33.345 ;
     RECT  2.16 33.615 62.64 33.885 ;
     RECT  2.16 34.155 62.64 34.425 ;
     RECT  2.16 34.695 62.64 34.965 ;
     RECT  2.16 35.235 62.64 35.505 ;
     RECT  2.16 35.775 62.64 36.045 ;
     RECT  2.16 36.315 62.64 36.585 ;
     RECT  2.16 36.855 62.64 37.125 ;
     RECT  2.16 37.395 62.64 37.665 ;
     RECT  2.16 37.935 62.64 38.205 ;
     RECT  2.16 38.475 62.64 38.745 ;
     RECT  2.16 39.015 62.64 39.285 ;
     RECT  2.16 39.555 62.64 39.825 ;
     RECT  2.16 40.095 62.64 40.365 ;
     RECT  2.16 40.635 62.64 40.905 ;
     RECT  2.16 41.175 62.64 41.445 ;
     RECT  2.16 41.715 62.64 41.985 ;
     RECT  2.16 42.255 62.64 42.525 ;
     RECT  2.16 42.795 62.64 43.065 ;
     RECT  2.16 43.335 62.64 43.605 ;
     RECT  2.16 43.875 62.64 44.145 ;
     RECT  2.16 44.415 62.64 44.685 ;
     RECT  2.16 44.955 62.64 45.225 ;
     RECT  2.16 45.495 62.64 45.765 ;
     RECT  2.16 46.035 62.64 46.305 ;
     RECT  2.16 46.575 62.64 46.845 ;
     RECT  2.16 47.115 62.64 47.385 ;
     RECT  2.16 47.655 62.64 47.925 ;
     RECT  2.16 48.195 62.64 48.465 ;
     RECT  2.16 48.735 62.64 49.005 ;
     RECT  2.16 49.275 62.64 49.545 ;
     RECT  2.16 49.815 62.64 50.085 ;
     RECT  2.16 50.355 62.64 50.625 ;
     RECT  2.16 50.895 62.64 51.165 ;
     RECT  2.16 51.435 62.64 51.705 ;
     RECT  2.16 51.975 62.64 52.245 ;
     RECT  2.16 52.515 62.64 52.785 ;
     RECT  2.16 53.055 62.64 53.325 ;
     RECT  2.16 53.595 62.64 53.865 ;
     RECT  2.16 54.135 62.64 54.405 ;
     RECT  2.16 54.675 62.64 54.945 ;
     RECT  2.16 55.215 62.64 55.485 ;
     RECT  2.16 55.755 62.64 56.025 ;
     RECT  2.16 56.295 62.64 56.565 ;
     RECT  2.16 56.835 62.64 57.105 ;
     RECT  2.16 57.375 62.64 57.645 ;
     RECT  2.16 57.915 62.64 58.185 ;
     RECT  2.16 58.455 62.64 58.725 ;
     RECT  2.16 58.995 62.64 59.265 ;
     RECT  2.16 59.535 62.64 59.805 ;
     RECT  2.16 60.075 62.64 60.345 ;
     RECT  2.16 60.615 62.64 60.885 ;
     RECT  2.16 61.155 62.64 61.425 ;
     RECT  2.16 61.695 62.64 61.965 ;
     RECT  2.16 62.235 62.64 62.505 ;
    LAYER M1 ;
     RECT  2.16 2.151 62.64 62.649 ;
    LAYER M2 ;
     RECT  0.031 30.582 0.103 30.87 ;
     RECT  0.103 30.456 0.131 30.87 ;
     RECT  0.103 18.54 0.139 18.558 ;
     RECT  0.103 20.43 0.139 20.988 ;
     RECT  0.103 27.72 0.139 29.358 ;
     RECT  0.103 22.59 0.203 22.914 ;
     RECT  0.103 36.792 0.203 37.89 ;
     RECT  0.139 18.432 0.211 18.558 ;
     RECT  0.139 27.342 0.211 29.628 ;
     RECT  0.103 39.222 0.499 39.24 ;
     RECT  0.139 20.43 0.535 21.456 ;
     RECT  0.203 22.59 0.535 22.608 ;
     RECT  0.103 32.616 0.535 33.372 ;
     RECT  0.499 39.222 0.535 39.582 ;
     RECT  0.103 42.3 0.535 42.318 ;
     RECT  0.103 35.856 0.563 35.874 ;
     RECT  0.103 25.866 1.327 25.884 ;
     RECT  0.211 27.072 1.327 29.628 ;
     RECT  1.327 25.866 1.687 29.628 ;
     RECT  0.131 30.456 1.687 30.6 ;
     RECT  1.687 25.866 1.723 30.6 ;
     RECT  1.147 46.242 1.723 46.26 ;
     RECT  0.211 18.432 2.16 19.098 ;
     RECT  0.535 20.358 2.16 22.608 ;
     RECT  1.723 25.722 2.16 30.6 ;
     RECT  0.535 32.616 2.16 33.984 ;
     RECT  0.203 36.792 2.16 37.422 ;
     RECT  0.535 39.222 2.16 39.888 ;
     RECT  0.535 42.3 2.16 42.624 ;
     RECT  1.975 45.27 2.16 45.288 ;
     RECT  1.723 46.242 2.16 46.8 ;
     RECT  2.16 2.151 24.259 62.649 ;
     RECT  24.259 2.151 24.503 62.694 ;
     RECT  25.915 1.152 26.195 1.17 ;
     RECT  24.503 2.151 28.111 62.649 ;
     RECT  28.111 2.106 28.679 62.649 ;
     RECT  28.867 1.152 29.075 1.17 ;
     RECT  29.983 1.152 30.083 1.17 ;
     RECT  28.679 2.151 41.323 62.649 ;
     RECT  41.323 2.106 41.639 62.649 ;
     RECT  41.639 2.151 44.887 62.649 ;
     RECT  44.887 2.151 45.023 62.694 ;
     RECT  45.023 2.151 62.64 62.649 ;
     RECT  62.64 14.958 62.735 45.684 ;
     RECT  62.64 46.476 63.239 47.304 ;
     RECT  62.735 41.616 63.275 45.684 ;
     RECT  62.735 14.958 63.311 40.698 ;
     RECT  63.275 41.616 63.311 41.976 ;
     RECT  63.275 42.966 63.311 45.684 ;
     RECT  62.64 54.486 63.311 54.666 ;
     RECT  63.311 15.498 63.347 40.698 ;
     RECT  63.347 15.606 63.383 40.698 ;
     RECT  62.64 13.644 63.563 13.662 ;
     RECT  63.383 19.926 63.563 40.698 ;
     RECT  63.563 19.926 63.815 39.744 ;
     RECT  63.311 41.616 63.815 41.634 ;
     RECT  63.239 46.746 63.815 46.764 ;
     RECT  63.815 19.926 63.851 29.556 ;
     RECT  63.815 30.816 63.851 31.788 ;
     RECT  63.815 32.85 63.851 37.224 ;
     RECT  63.815 38.178 63.851 38.844 ;
     RECT  63.311 42.966 63.851 42.984 ;
     RECT  63.311 43.776 63.851 45.684 ;
     RECT  63.311 54.486 63.851 54.504 ;
     RECT  63.383 16.002 63.887 19.026 ;
     RECT  63.851 20.466 63.887 22.464 ;
     RECT  63.851 27.612 63.887 28.008 ;
     RECT  63.851 28.764 63.887 29.556 ;
     RECT  63.851 44.388 63.887 44.676 ;
     RECT  63.887 16.416 63.923 19.026 ;
     RECT  63.887 20.466 63.923 22.374 ;
     RECT  63.851 24.174 63.923 26.784 ;
     RECT  63.923 16.614 63.959 18.324 ;
     RECT  63.923 20.898 63.959 22.374 ;
     RECT  63.923 24.174 63.959 24.966 ;
     RECT  63.959 16.614 63.995 16.83 ;
     RECT  63.959 24.948 63.995 24.966 ;
     RECT  63.995 16.614 64.031 16.632 ;
     RECT  63.959 21.636 64.031 22.374 ;
     RECT  63.851 36.558 64.579 37.224 ;
     RECT  63.851 38.448 64.579 38.844 ;
     RECT  63.851 33.966 64.607 34.956 ;
     RECT  63.563 40.536 64.607 40.698 ;
     RECT  63.887 29.34 64.615 29.556 ;
     RECT  64.607 34.056 64.643 34.956 ;
     RECT  64.579 36.558 64.643 38.844 ;
     RECT  63.887 27.648 64.679 28.008 ;
     RECT  63.851 32.85 64.679 33.066 ;
     RECT  64.643 34.056 64.679 34.146 ;
     RECT  64.643 36.558 64.679 38.466 ;
     RECT  63.815 39.726 64.679 39.744 ;
     RECT  63.887 44.658 64.679 44.676 ;
     RECT  63.959 18.306 64.715 18.324 ;
     RECT  64.031 22.356 64.715 22.374 ;
     RECT  63.959 24.174 64.715 24.192 ;
     RECT  63.923 25.992 64.715 26.784 ;
     RECT  64.679 27.99 64.715 28.008 ;
     RECT  64.615 29.34 64.715 30.024 ;
     RECT  63.851 31.77 64.715 31.788 ;
     RECT  64.679 33.048 64.715 33.066 ;
     RECT  64.679 34.128 64.715 34.146 ;
     RECT  64.679 36.558 64.715 36.576 ;
     RECT  64.679 37.908 64.715 38.466 ;
     RECT  63.851 45.666 64.715 45.684 ;
     RECT  64.715 37.908 64.787 37.926 ;
     RECT  64.607 40.68 64.787 40.698 ;
    LAYER M3 ;
     RECT  30.924 0.091 30.942 0.317 ;
     RECT  40.752 0.091 40.77 0.317 ;
     RECT  28.044 0.091 28.674 0.475 ;
     RECT  28.044 0.475 28.89 0.523 ;
     RECT  22.284 0.091 22.302 0.571 ;
     RECT  15.732 0.091 15.75 1.099 ;
     RECT  18.288 0.571 18.306 1.099 ;
     RECT  19.044 0.571 19.062 1.099 ;
     RECT  26.208 0.523 26.694 1.099 ;
     RECT  30.384 0.571 30.69 1.099 ;
     RECT  21.744 0.571 22.302 1.147 ;
     RECT  23.472 0.571 23.49 1.147 ;
     RECT  26.172 1.099 26.694 1.147 ;
     RECT  28.044 0.523 29.034 1.147 ;
     RECT  19.944 0.571 20.538 1.675 ;
     RECT  21.744 1.147 22.374 1.675 ;
     RECT  35.136 0.571 35.154 1.675 ;
     RECT  36.144 1.627 36.162 1.675 ;
     RECT  15.732 1.099 16.218 1.723 ;
     RECT  18.288 1.099 19.062 1.723 ;
     RECT  19.944 1.675 20.574 1.723 ;
     RECT  21.744 1.675 22.626 1.723 ;
     RECT  23.472 1.147 23.922 1.723 ;
     RECT  25.164 0.091 25.182 1.723 ;
     RECT  25.92 1.147 26.694 1.723 ;
     RECT  28.044 1.147 29.07 1.723 ;
     RECT  29.988 1.099 30.69 1.723 ;
     RECT  31.968 1.195 31.986 1.723 ;
     RECT  32.832 0.523 32.85 1.723 ;
     RECT  33.66 0.571 33.678 1.723 ;
     RECT  35.136 1.675 36.162 1.723 ;
     RECT  37.62 1.675 37.638 1.723 ;
     RECT  39.924 0.571 39.942 1.723 ;
     RECT  41.616 0.571 41.634 1.723 ;
     RECT  15.732 1.723 38.178 1.771 ;
     RECT  39.024 1.723 40.122 1.771 ;
     RECT  40.932 1.723 42.066 1.771 ;
     RECT  15.732 1.771 38.286 2.371 ;
     RECT  39.024 1.771 42.066 2.371 ;
     RECT  2.415 2.143 2.505 2.413 ;
     RECT  7.815 2.143 7.905 2.413 ;
     RECT  13.215 2.143 13.305 2.413 ;
     RECT  45.615 2.143 45.705 2.413 ;
     RECT  51.015 2.143 51.105 2.413 ;
     RECT  56.415 2.143 56.505 2.413 ;
     RECT  61.815 2.143 61.905 2.413 ;
     RECT  15.732 2.371 42.75 2.525 ;
     RECT  16.056 2.525 42.75 2.731 ;
     RECT  16.056 2.731 43.398 2.759 ;
     RECT  16.164 2.759 43.398 3.569 ;
     RECT  16.2 3.569 43.398 4.145 ;
     RECT  16.38 4.145 43.398 4.621 ;
     RECT  44.208 4.081 44.226 4.621 ;
     RECT  45.615 2.413 45.897 5.341 ;
     RECT  16.38 4.621 44.226 5.575 ;
     RECT  16.236 5.575 44.334 5.611 ;
     RECT  45.18 5.341 45.897 5.611 ;
     RECT  16.236 5.611 45.954 5.693 ;
     RECT  46.728 5.611 46.746 5.701 ;
     RECT  16.488 5.693 45.954 5.845 ;
     RECT  46.728 5.701 46.818 5.845 ;
     RECT  48.96 5.845 48.978 5.881 ;
     RECT  49.716 5.845 49.734 5.881 ;
     RECT  51.015 2.413 51.297 5.881 ;
     RECT  16.488 5.845 46.818 6.115 ;
     RECT  48.96 5.881 49.734 6.115 ;
     RECT  16.488 6.115 46.926 6.151 ;
     RECT  48.78 6.115 49.734 6.151 ;
     RECT  50.688 5.881 51.297 6.151 ;
     RECT  53.496 6.241 53.514 6.349 ;
     RECT  16.488 6.151 47.034 6.385 ;
     RECT  47.88 6.151 47.898 6.385 ;
     RECT  48.78 6.151 51.297 6.385 ;
     RECT  53.208 6.349 53.514 6.385 ;
     RECT  16.488 6.385 51.297 6.421 ;
     RECT  16.488 6.421 51.354 6.539 ;
     RECT  16.632 6.539 51.354 6.547 ;
     RECT  16.632 6.547 51.642 6.575 ;
     RECT  16.632 6.575 49.194 6.611 ;
     RECT  50.04 6.575 51.642 6.691 ;
     RECT  53.136 6.385 53.514 6.691 ;
     RECT  54.324 6.421 54.342 6.691 ;
     RECT  52.488 6.691 54.342 6.845 ;
     RECT  50.04 6.691 51.714 6.961 ;
     RECT  50.04 6.961 51.75 7.079 ;
     RECT  52.56 6.845 54.342 7.115 ;
     RECT  54.288 7.115 54.342 7.231 ;
     RECT  16.776 6.611 49.194 7.321 ;
     RECT  50.04 7.079 51.714 7.321 ;
     RECT  56.415 2.413 56.697 7.321 ;
     RECT  56.415 7.321 57.33 7.339 ;
     RECT  52.56 7.115 53.55 7.349 ;
     RECT  54.288 7.231 54.63 7.385 ;
     RECT  56.34 7.339 57.33 7.385 ;
     RECT  16.776 7.321 51.714 7.421 ;
     RECT  52.56 7.349 53.514 7.699 ;
     RECT  17.1 7.421 51.714 7.897 ;
     RECT  52.452 7.699 53.514 7.897 ;
     RECT  17.1 7.897 53.514 7.925 ;
     RECT  54.288 7.385 54.342 8.041 ;
     RECT  54.252 8.041 54.342 8.167 ;
     RECT  17.1 7.925 53.154 8.195 ;
     RECT  17.28 8.195 53.154 8.429 ;
     RECT  17.28 8.429 52.902 8.465 ;
     RECT  54.036 8.167 54.342 8.851 ;
     RECT  17.424 8.465 52.902 9.005 ;
     RECT  53.856 8.851 54.342 9.211 ;
     RECT  55.08 8.581 55.098 9.211 ;
     RECT  49.212 9.005 52.902 9.275 ;
     RECT  53.856 9.211 55.098 9.275 ;
     RECT  54.18 9.275 55.098 9.391 ;
     RECT  17.424 9.005 48.474 9.509 ;
     RECT  52.956 9.391 53.334 9.509 ;
     RECT  54.18 9.391 55.422 9.661 ;
     RECT  56.415 7.385 57.33 9.661 ;
     RECT  48.132 9.509 48.474 10.201 ;
     RECT  49.212 9.275 52.218 10.201 ;
     RECT  52.956 9.509 53.226 10.267 ;
     RECT  54.18 9.661 57.33 10.267 ;
     RECT  17.424 9.509 47.394 10.741 ;
     RECT  48.132 10.201 52.218 10.741 ;
     RECT  52.956 10.267 57.33 10.741 ;
     RECT  17.424 10.741 57.33 10.769 ;
     RECT  18.288 10.769 57.33 10.859 ;
     RECT  18.288 10.859 55.638 11.237 ;
     RECT  18.288 11.237 49.086 11.405 ;
     RECT  49.824 11.237 55.638 11.405 ;
     RECT  18.288 11.405 48.798 11.669 ;
     RECT  18.432 11.669 48.798 11.777 ;
     RECT  54.288 11.405 55.638 11.821 ;
     RECT  18.576 11.777 48.798 11.849 ;
     RECT  54.288 11.821 55.674 11.939 ;
     RECT  49.824 11.405 53.478 12.091 ;
     RECT  61.815 2.413 62.097 12.181 ;
     RECT  49.536 12.091 53.478 12.325 ;
     RECT  54.288 11.939 55.638 12.325 ;
     RECT  18.615 11.849 48.798 12.361 ;
     RECT  49.536 12.325 55.638 12.361 ;
     RECT  61.236 12.181 62.097 12.361 ;
     RECT  60.624 12.361 62.097 12.487 ;
     RECT  60.552 12.487 62.097 12.523 ;
     RECT  60.552 12.523 62.19 12.829 ;
     RECT  18.615 12.361 55.638 12.901 ;
     RECT  56.415 10.859 57.33 12.901 ;
     RECT  60.552 12.829 62.37 12.901 ;
     RECT  18.615 12.901 57.33 13.019 ;
     RECT  59.688 12.523 59.706 13.099 ;
     RECT  18.615 13.019 19.674 13.289 ;
     RECT  18.615 13.289 19.53 13.469 ;
     RECT  59.616 13.099 59.706 13.711 ;
     RECT  60.552 12.901 62.55 13.711 ;
     RECT  59.616 13.711 62.55 13.945 ;
     RECT  59.256 13.945 62.55 14.521 ;
     RECT  59.22 14.521 62.55 14.791 ;
     RECT  63.54 13.639 63.558 14.953 ;
     RECT  58.824 14.791 62.55 15.061 ;
     RECT  63.288 14.953 63.558 15.061 ;
     RECT  20.52 13.019 57.33 15.215 ;
     RECT  48.456 15.215 57.33 15.565 ;
     RECT  58.068 12.991 58.086 15.565 ;
     RECT  48.456 15.565 58.086 15.691 ;
     RECT  58.824 15.061 63.558 15.691 ;
     RECT  20.52 15.215 47.682 15.961 ;
     RECT  48.456 15.691 63.558 15.961 ;
     RECT  20.52 15.961 63.558 15.997 ;
     RECT  20.52 15.997 63.882 16.411 ;
     RECT  20.52 16.411 63.918 16.609 ;
     RECT  20.52 16.609 64.026 16.835 ;
     RECT  23.004 16.835 64.026 17.411 ;
     RECT  58.68 17.411 64.026 17.995 ;
     RECT  2.415 2.413 2.697 18.157 ;
     RECT  6.3 18.031 6.318 18.193 ;
     RECT  58.68 17.995 64.71 18.265 ;
     RECT  2.34 18.157 2.697 18.301 ;
     RECT  3.42 18.031 3.438 18.301 ;
     RECT  58.644 18.265 64.71 18.329 ;
     RECT  0.144 18.427 0.162 18.499 ;
     RECT  0.144 18.499 0.198 18.535 ;
     RECT  23.004 17.411 57.546 18.535 ;
     RECT  58.644 18.329 64.026 18.535 ;
     RECT  7.815 2.413 8.097 18.697 ;
     RECT  4.392 18.697 4.41 18.797 ;
     RECT  23.004 18.535 64.026 18.797 ;
     RECT  58.68 18.797 64.026 18.893 ;
     RECT  23.004 18.797 57.87 18.959 ;
     RECT  0.108 18.535 0.198 19.003 ;
     RECT  5.58 18.193 6.318 19.003 ;
     RECT  23.004 18.959 57.798 19.031 ;
     RECT  58.68 18.893 63.918 19.031 ;
     RECT  5.58 19.003 6.894 19.039 ;
     RECT  7.776 18.697 8.097 19.039 ;
     RECT  2.34 18.301 3.438 19.075 ;
     RECT  5.58 19.039 8.097 19.075 ;
     RECT  11.844 18.661 11.862 19.309 ;
     RECT  5.112 19.075 8.097 19.507 ;
     RECT  0.108 19.003 0.558 19.565 ;
     RECT  5.112 19.507 8.73 19.579 ;
     RECT  2.34 19.075 4.014 19.615 ;
     RECT  58.68 19.031 63.882 19.651 ;
     RECT  0.144 19.565 0.558 19.661 ;
     RECT  23.004 19.031 57.51 19.679 ;
     RECT  11.7 19.309 11.862 19.741 ;
     RECT  10.836 19.741 10.854 19.849 ;
     RECT  11.7 19.741 11.898 19.849 ;
     RECT  10.836 19.849 11.898 19.885 ;
     RECT  2.304 19.615 4.014 19.921 ;
     RECT  4.824 19.579 8.73 19.921 ;
     RECT  9.684 19.651 9.702 19.921 ;
     RECT  10.836 19.885 12.402 19.921 ;
     RECT  10.836 19.921 12.438 19.963 ;
     RECT  13.215 2.413 13.497 19.963 ;
     RECT  9.684 19.921 9.99 20.011 ;
     RECT  10.836 19.963 13.497 20.011 ;
     RECT  2.304 19.921 8.73 20.047 ;
     RECT  9.684 20.011 13.497 20.191 ;
     RECT  58.536 19.651 63.882 20.191 ;
     RECT  2.268 20.047 8.73 20.281 ;
     RECT  9.684 20.191 13.59 20.281 ;
     RECT  20.52 16.835 22.158 20.345 ;
     RECT  28.296 19.679 57.51 20.417 ;
     RECT  0.18 19.661 0.558 20.425 ;
     RECT  58.284 20.191 63.882 20.429 ;
     RECT  2.268 20.281 13.59 20.461 ;
     RECT  63.288 20.429 63.882 20.461 ;
     RECT  2.268 20.461 13.914 20.489 ;
     RECT  23.004 19.679 27.558 20.491 ;
     RECT  28.296 20.417 49.194 20.491 ;
     RECT  49.968 20.417 57.51 20.491 ;
     RECT  58.284 20.429 62.55 20.491 ;
     RECT  2.268 20.489 4.806 20.525 ;
     RECT  14.796 20.551 14.814 20.587 ;
     RECT  16.272 20.551 16.29 20.587 ;
     RECT  17.424 10.769 17.442 20.587 ;
     RECT  14.796 20.587 15.39 20.623 ;
     RECT  20.916 20.345 22.158 20.623 ;
     RECT  23.004 20.491 49.194 20.623 ;
     RECT  20.916 20.623 49.194 20.651 ;
     RECT  18.615 13.469 18.897 20.695 ;
     RECT  14.796 20.623 15.462 20.731 ;
     RECT  16.272 20.587 17.442 20.731 ;
     RECT  18.576 20.695 18.897 20.731 ;
     RECT  0.108 20.425 0.558 20.813 ;
     RECT  18.576 20.731 19.602 20.857 ;
     RECT  63.288 20.461 63.918 20.893 ;
     RECT  14.76 20.731 17.442 20.929 ;
     RECT  18.576 20.857 19.674 20.929 ;
     RECT  5.616 20.489 13.914 20.965 ;
     RECT  14.76 20.929 19.674 20.965 ;
     RECT  5.616 20.965 19.674 21.001 ;
     RECT  2.304 20.525 4.806 21.119 ;
     RECT  23.832 20.651 49.194 21.155 ;
     RECT  28.296 21.155 49.194 21.235 ;
     RECT  49.968 20.491 62.55 21.235 ;
     RECT  5.616 21.001 19.71 21.271 ;
     RECT  20.916 20.651 22.878 21.271 ;
     RECT  5.616 21.271 19.962 21.361 ;
     RECT  5.508 21.361 19.962 21.389 ;
     RECT  12.42 21.389 19.962 21.425 ;
     RECT  2.304 21.119 4.662 21.505 ;
     RECT  28.296 21.235 62.55 21.505 ;
     RECT  63.288 20.893 63.954 21.505 ;
     RECT  20.736 21.271 22.878 21.541 ;
     RECT  2.232 21.505 4.662 21.581 ;
     RECT  20.304 21.541 22.878 21.631 ;
     RECT  28.296 21.505 63.954 21.631 ;
     RECT  20.304 21.631 23.022 21.643 ;
     RECT  23.832 21.155 27.522 21.643 ;
     RECT  28.296 21.631 64.026 21.839 ;
     RECT  20.304 21.643 27.522 21.965 ;
     RECT  2.304 21.581 4.662 21.973 ;
     RECT  58.32 21.839 64.026 22.027 ;
     RECT  0.108 20.813 0.162 22.081 ;
     RECT  23.796 21.965 27.522 22.081 ;
     RECT  28.296 21.839 57.51 22.081 ;
     RECT  2.304 21.973 4.734 22.199 ;
     RECT  5.508 21.389 11.646 22.243 ;
     RECT  0.108 22.081 0.558 22.253 ;
     RECT  12.456 21.425 19.458 22.279 ;
     RECT  20.304 21.965 23.022 22.279 ;
     RECT  5.4 22.243 11.646 22.351 ;
     RECT  12.456 22.279 23.022 22.351 ;
     RECT  58.32 22.027 64.71 22.379 ;
     RECT  23.796 22.081 57.51 22.613 ;
     RECT  53.568 22.613 57.51 22.621 ;
     RECT  58.32 22.379 64.638 22.621 ;
     RECT  5.4 22.351 23.022 22.711 ;
     RECT  23.796 22.613 52.794 22.711 ;
     RECT  53.568 22.621 64.638 22.739 ;
     RECT  0.108 22.253 0.198 22.919 ;
     RECT  53.604 22.739 64.638 22.925 ;
     RECT  0.108 22.919 0.126 22.928 ;
     RECT  64.62 22.925 64.638 23.021 ;
     RECT  2.304 22.199 4.518 23.089 ;
     RECT  5.4 22.711 52.794 23.089 ;
     RECT  2.304 23.089 52.794 23.179 ;
     RECT  2.268 23.179 52.794 23.275 ;
     RECT  53.604 22.925 63.882 23.309 ;
     RECT  1.728 23.275 52.794 23.557 ;
     RECT  53.604 23.309 62.73 23.557 ;
     RECT  0.324 23.755 0.342 23.851 ;
     RECT  1.728 23.557 62.73 24.125 ;
     RECT  1.728 24.125 16.326 24.139 ;
     RECT  17.1 24.125 62.73 24.197 ;
     RECT  64.692 24.139 64.71 24.197 ;
     RECT  63.792 23.309 63.882 24.403 ;
     RECT  58.068 24.197 62.73 24.439 ;
     RECT  63.792 24.403 63.918 24.439 ;
     RECT  1.332 24.139 16.326 24.503 ;
     RECT  17.1 24.197 57.186 24.665 ;
     RECT  58.068 24.439 63.918 24.749 ;
     RECT  63.828 24.749 63.918 24.871 ;
     RECT  6.264 24.503 16.326 24.943 ;
     RECT  17.1 24.665 26.406 24.943 ;
     RECT  63.828 24.871 63.954 24.943 ;
     RECT  6.264 24.943 26.406 25.007 ;
     RECT  27.144 24.665 57.186 25.015 ;
     RECT  58.068 24.749 62.694 25.079 ;
     RECT  6.264 25.007 14.526 25.285 ;
     RECT  1.332 24.503 5.454 25.321 ;
     RECT  6.228 25.285 14.526 25.321 ;
     RECT  0.108 23.851 0.342 25.517 ;
     RECT  15.3 25.007 26.406 25.591 ;
     RECT  27.144 25.015 57.222 25.591 ;
     RECT  0.108 25.517 0.162 25.661 ;
     RECT  63.828 24.943 63.99 25.675 ;
     RECT  1.332 25.321 14.526 25.745 ;
     RECT  2.304 25.745 14.526 25.753 ;
     RECT  15.3 25.591 57.33 25.753 ;
     RECT  2.304 25.753 57.33 25.853 ;
     RECT  0.108 25.661 0.126 25.889 ;
     RECT  58.068 25.079 62.442 25.987 ;
     RECT  2.304 25.853 26.802 26.051 ;
     RECT  27.756 25.853 57.33 26.131 ;
     RECT  58.068 25.987 62.514 26.131 ;
     RECT  63.828 25.675 64.71 26.155 ;
     RECT  2.304 26.051 5.166 26.159 ;
     RECT  6.264 26.051 26.802 26.285 ;
     RECT  27.756 26.131 62.514 26.347 ;
     RECT  63.252 26.155 64.71 26.347 ;
     RECT  1.332 25.745 1.35 26.357 ;
     RECT  27.756 26.347 64.71 26.357 ;
     RECT  14.832 26.285 26.802 26.393 ;
     RECT  2.304 26.159 5.13 26.429 ;
     RECT  3.528 26.429 4.77 26.519 ;
     RECT  6.264 26.285 13.986 26.627 ;
     RECT  63.792 26.357 64.71 26.699 ;
     RECT  6.264 26.627 10.026 26.789 ;
     RECT  27.756 26.357 62.694 27.139 ;
     RECT  63.792 26.699 63.882 27.139 ;
     RECT  2.304 26.429 2.697 27.175 ;
     RECT  14.832 26.393 25.974 27.211 ;
     RECT  26.712 26.393 26.802 27.211 ;
     RECT  14.832 27.211 26.91 27.307 ;
     RECT  14.76 27.307 26.91 27.329 ;
     RECT  27.756 27.139 63.882 27.329 ;
     RECT  0.216 27.067 0.234 27.337 ;
     RECT  3.816 26.519 4.482 27.337 ;
     RECT  3.816 27.337 4.626 27.403 ;
     RECT  3.816 27.403 4.734 27.409 ;
     RECT  6.3 26.789 10.026 27.409 ;
     RECT  10.764 26.627 13.986 27.409 ;
     RECT  1.692 27.175 2.697 27.481 ;
     RECT  28.584 27.329 63.882 27.509 ;
     RECT  1.692 27.481 2.754 27.571 ;
     RECT  3.816 27.409 5.166 27.571 ;
     RECT  64.692 26.699 64.71 27.595 ;
     RECT  0.144 27.337 0.234 27.607 ;
     RECT  64.656 27.595 64.71 27.671 ;
     RECT  6.3 27.409 13.986 27.679 ;
     RECT  14.76 27.329 25.974 27.679 ;
     RECT  0.144 27.607 0.27 27.715 ;
     RECT  0.108 27.715 0.27 27.751 ;
     RECT  1.692 27.571 5.166 27.751 ;
     RECT  63.288 27.509 63.882 27.821 ;
     RECT  26.748 27.329 26.91 27.877 ;
     RECT  27.756 27.329 27.81 27.877 ;
     RECT  28.584 27.509 62.514 27.905 ;
     RECT  0.108 27.751 0.522 27.913 ;
     RECT  26.748 27.877 27.81 27.917 ;
     RECT  28.584 27.905 30.834 27.917 ;
     RECT  63.288 27.821 63.846 27.917 ;
     RECT  6.3 27.679 25.974 27.931 ;
     RECT  6.084 27.931 25.974 27.941 ;
     RECT  30.636 27.917 30.834 28.013 ;
     RECT  64.692 27.671 64.71 28.013 ;
     RECT  6.084 27.941 9.234 28.139 ;
     RECT  6.084 28.139 9.054 28.175 ;
     RECT  30.672 28.013 30.834 28.283 ;
     RECT  30.78 28.283 30.834 28.319 ;
     RECT  26.748 27.917 26.874 28.381 ;
     RECT  31.68 27.905 62.514 28.517 ;
     RECT  63.324 27.917 63.846 28.645 ;
     RECT  26.712 28.381 26.874 28.679 ;
     RECT  31.68 28.517 57.186 28.679 ;
     RECT  58.068 28.517 62.514 28.679 ;
     RECT  31.68 28.679 57.15 28.715 ;
     RECT  58.284 28.679 62.514 28.751 ;
     RECT  58.32 28.751 62.514 28.759 ;
     RECT  63.288 28.645 63.846 28.759 ;
     RECT  1.692 27.751 5.238 28.831 ;
     RECT  6.084 28.175 8.802 28.831 ;
     RECT  27.756 27.917 27.774 28.831 ;
     RECT  28.584 27.917 29.862 28.831 ;
     RECT  31.86 28.715 57.15 28.985 ;
     RECT  1.692 28.831 8.802 29.065 ;
     RECT  27.756 28.831 29.862 29.069 ;
     RECT  32.472 28.985 57.15 29.117 ;
     RECT  58.32 28.759 63.882 29.165 ;
     RECT  30.78 28.319 30.798 29.255 ;
     RECT  10.008 27.941 25.974 29.335 ;
     RECT  0.108 27.913 0.558 29.357 ;
     RECT  1.692 29.065 9.126 29.371 ;
     RECT  9.936 29.335 25.974 29.371 ;
     RECT  26.748 28.679 26.874 29.371 ;
     RECT  27.756 29.069 27.774 29.371 ;
     RECT  58.32 29.165 63.846 29.533 ;
     RECT  1.692 29.371 25.974 29.605 ;
     RECT  26.748 29.371 27.774 29.605 ;
     RECT  32.508 29.117 57.15 29.605 ;
     RECT  28.584 29.069 29.862 29.659 ;
     RECT  1.692 29.605 27.774 29.707 ;
     RECT  64.692 29.227 64.71 29.731 ;
     RECT  32.508 29.605 57.186 29.759 ;
     RECT  1.152 29.707 27.774 29.831 ;
     RECT  0.108 29.357 0.162 29.837 ;
     RECT  1.152 29.831 6.57 29.837 ;
     RECT  7.344 29.831 27.774 29.875 ;
     RECT  28.584 29.659 30.258 29.875 ;
     RECT  58.284 29.533 63.846 29.911 ;
     RECT  7.344 29.875 30.258 29.933 ;
     RECT  12.528 29.933 30.258 30.029 ;
     RECT  64.62 29.731 64.71 30.029 ;
     RECT  12.528 30.029 29.862 30.065 ;
     RECT  31.284 29.803 31.302 30.145 ;
     RECT  31.212 30.145 31.302 30.173 ;
     RECT  32.868 29.759 57.186 30.181 ;
     RECT  58.068 29.911 63.846 30.181 ;
     RECT  7.344 29.933 11.538 30.299 ;
     RECT  32.868 30.181 63.846 30.299 ;
     RECT  1.692 29.837 6.57 30.335 ;
     RECT  1.692 30.335 5.238 30.569 ;
     RECT  0.108 29.837 0.126 30.577 ;
     RECT  6.048 30.335 6.57 30.721 ;
     RECT  7.344 30.299 8.097 30.721 ;
     RECT  8.856 30.299 11.538 30.721 ;
     RECT  12.528 30.065 14.454 30.721 ;
     RECT  31.212 30.173 31.23 30.721 ;
     RECT  0.036 30.577 0.126 30.875 ;
     RECT  8.856 30.721 14.454 30.919 ;
     RECT  15.336 30.065 29.862 30.919 ;
     RECT  64.62 30.029 64.638 30.941 ;
     RECT  0.108 30.875 0.126 31.099 ;
     RECT  6.048 30.721 8.097 31.145 ;
     RECT  6.3 31.145 8.097 31.261 ;
     RECT  8.856 30.919 29.862 31.261 ;
     RECT  6.3 31.261 29.862 31.379 ;
     RECT  1.692 30.569 5.13 31.387 ;
     RECT  32.904 30.299 63.846 31.421 ;
     RECT  30.852 30.721 31.23 31.423 ;
     RECT  32.04 30.343 32.094 31.423 ;
     RECT  32.904 31.421 57.474 31.423 ;
     RECT  0.108 31.099 0.162 31.435 ;
     RECT  6.336 31.379 29.862 31.531 ;
     RECT  30.78 31.423 31.23 31.531 ;
     RECT  6.336 31.531 31.23 31.621 ;
     RECT  32.04 31.423 57.474 31.621 ;
     RECT  6.336 31.621 57.474 31.805 ;
     RECT  64.692 31.765 64.71 31.949 ;
     RECT  58.248 31.421 63.846 32.027 ;
     RECT  11.016 31.805 57.474 32.099 ;
     RECT  58.248 32.027 62.406 32.161 ;
     RECT  11.016 32.099 57.186 32.225 ;
     RECT  1.692 31.387 5.526 32.269 ;
     RECT  6.336 31.805 10.206 32.269 ;
     RECT  64.62 32.107 64.638 32.285 ;
     RECT  34.74 32.225 57.186 32.297 ;
     RECT  34.74 32.297 57.114 32.459 ;
     RECT  58.212 32.161 62.406 32.467 ;
     RECT  1.692 32.269 10.206 32.525 ;
     RECT  58.14 32.467 62.406 32.729 ;
     RECT  58.644 32.729 62.406 32.837 ;
     RECT  2.304 32.525 10.206 32.845 ;
     RECT  0.108 31.435 0.27 33.007 ;
     RECT  0.108 33.007 0.486 33.043 ;
     RECT  34.74 32.459 57.078 33.043 ;
     RECT  2.304 32.845 10.242 33.151 ;
     RECT  11.016 32.225 33.966 33.151 ;
     RECT  58.68 32.837 62.406 33.151 ;
     RECT  63.216 32.027 63.846 33.151 ;
     RECT  2.304 33.151 33.966 33.421 ;
     RECT  34.704 33.043 57.078 33.421 ;
     RECT  2.304 33.421 57.078 33.449 ;
     RECT  58.68 33.151 63.846 33.691 ;
     RECT  30.888 33.449 57.078 33.781 ;
     RECT  2.304 33.449 30.078 33.809 ;
     RECT  64.656 32.683 64.71 33.835 ;
     RECT  2.304 33.809 9.126 33.845 ;
     RECT  58.572 33.691 63.846 33.925 ;
     RECT  64.62 33.835 64.71 33.931 ;
     RECT  2.304 33.845 9.054 33.953 ;
     RECT  2.304 33.953 4.77 34.027 ;
     RECT  58.068 33.925 63.846 34.027 ;
     RECT  64.584 33.931 64.71 34.027 ;
     RECT  30.888 33.781 57.222 34.079 ;
     RECT  30.888 34.079 57.078 34.115 ;
     RECT  58.068 34.027 64.71 34.151 ;
     RECT  0.108 33.043 0.558 34.157 ;
     RECT  0.18 34.157 0.558 34.349 ;
     RECT  9.9 33.809 30.078 34.501 ;
     RECT  30.888 34.115 57.006 34.501 ;
     RECT  2.268 34.027 4.77 34.619 ;
     RECT  0.18 34.349 0.27 34.685 ;
     RECT  4.356 34.619 4.77 34.735 ;
     RECT  5.544 33.953 9.054 34.735 ;
     RECT  9.9 34.501 57.006 34.735 ;
     RECT  58.068 34.151 64.638 34.763 ;
     RECT  4.356 34.735 57.006 34.861 ;
     RECT  58.068 34.763 63.846 34.861 ;
     RECT  2.268 34.619 3.51 34.933 ;
     RECT  64.62 34.763 64.638 34.961 ;
     RECT  2.196 34.933 3.51 35.213 ;
     RECT  4.356 34.861 63.846 35.213 ;
     RECT  4.356 35.213 8.982 35.231 ;
     RECT  2.304 35.213 3.51 35.563 ;
     RECT  4.356 35.231 8.91 35.563 ;
     RECT  9.756 35.213 63.846 35.699 ;
     RECT  0.252 34.685 0.27 35.803 ;
     RECT  0.252 35.803 0.558 35.851 ;
     RECT  0.108 35.851 0.558 35.879 ;
     RECT  0.108 35.879 0.27 35.888 ;
     RECT  38.736 35.699 63.846 35.969 ;
     RECT  9.756 35.699 37.746 36.049 ;
     RECT  2.304 35.563 8.91 36.121 ;
     RECT  9.684 36.049 37.746 36.121 ;
     RECT  2.304 36.121 37.746 36.139 ;
     RECT  64.692 35.947 64.71 36.235 ;
     RECT  2.268 36.139 37.746 36.275 ;
     RECT  38.808 35.969 63.846 36.275 ;
     RECT  39.024 36.275 63.846 36.311 ;
     RECT  39.024 36.311 58.338 36.689 ;
     RECT  0.252 35.888 0.27 36.787 ;
     RECT  39.024 36.689 51.462 36.851 ;
     RECT  64.656 36.235 64.71 36.859 ;
     RECT  39.024 36.851 51.426 37.049 ;
     RECT  2.304 36.275 37.746 37.051 ;
     RECT  39.024 37.049 51.39 37.051 ;
     RECT  2.304 37.051 51.39 37.157 ;
     RECT  52.272 36.689 58.338 37.201 ;
     RECT  59.112 36.311 63.846 37.201 ;
     RECT  2.304 37.157 47.466 37.291 ;
     RECT  48.312 37.157 51.39 37.355 ;
     RECT  2.268 37.291 47.466 37.463 ;
     RECT  49.932 37.355 51.39 37.625 ;
     RECT  49.932 37.625 51.354 37.697 ;
     RECT  0.108 36.787 0.27 37.771 ;
     RECT  64.62 36.859 64.71 37.867 ;
     RECT  50.004 37.697 51.354 37.895 ;
     RECT  0.108 37.771 0.342 37.901 ;
     RECT  64.584 37.867 64.71 37.903 ;
     RECT  0.108 37.901 0.27 37.904 ;
     RECT  2.304 37.463 47.466 38.011 ;
     RECT  2.304 38.011 47.502 38.129 ;
     RECT  52.272 37.201 63.846 38.129 ;
     RECT  2.304 38.129 47.466 38.165 ;
     RECT  52.272 38.129 58.338 38.201 ;
     RECT  59.076 38.129 63.846 38.201 ;
     RECT  48.456 37.355 49.05 38.281 ;
     RECT  2.304 38.165 46.314 38.399 ;
     RECT  52.272 38.201 54.81 38.399 ;
     RECT  55.908 38.201 58.338 38.399 ;
     RECT  55.908 38.399 57.582 38.435 ;
     RECT  52.272 38.399 54.414 38.669 ;
     RECT  54.108 38.669 54.414 38.765 ;
     RECT  2.304 38.399 5.418 38.821 ;
     RECT  48.312 38.281 49.05 38.939 ;
     RECT  6.192 38.399 46.314 38.975 ;
     RECT  55.908 38.435 56.697 38.975 ;
     RECT  47.16 38.165 47.466 39.019 ;
     RECT  48.312 38.939 48.51 39.019 ;
     RECT  50.004 37.895 51.297 39.019 ;
     RECT  2.268 38.821 5.418 39.047 ;
     RECT  59.076 38.201 63.81 39.047 ;
     RECT  44.46 38.975 46.314 39.055 ;
     RECT  47.16 39.019 48.51 39.055 ;
     RECT  6.192 38.975 43.722 39.119 ;
     RECT  63.252 39.047 63.81 39.119 ;
     RECT  2.304 39.047 5.418 39.181 ;
     RECT  6.192 39.119 38.322 39.181 ;
     RECT  0.252 37.904 0.27 39.217 ;
     RECT  2.304 39.181 38.322 39.245 ;
     RECT  0.108 39.217 0.27 39.253 ;
     RECT  5.796 39.245 38.322 39.341 ;
     RECT  49.824 39.019 51.297 39.361 ;
     RECT  52.272 38.669 53.334 39.361 ;
     RECT  63.54 39.119 63.81 39.389 ;
     RECT  49.824 39.361 53.334 39.479 ;
     RECT  54.108 38.765 54.126 39.487 ;
     RECT  44.46 39.055 48.51 39.515 ;
     RECT  50.148 39.479 53.19 39.515 ;
     RECT  54.108 39.487 54.342 39.515 ;
     RECT  0.108 39.253 0.558 39.533 ;
     RECT  54.252 39.515 54.342 39.595 ;
     RECT  2.304 39.245 4.842 39.659 ;
     RECT  39.096 39.119 43.722 39.721 ;
     RECT  44.46 39.515 48.474 39.721 ;
     RECT  49.248 39.559 49.266 39.749 ;
     RECT  52.272 39.515 53.19 39.749 ;
     RECT  5.796 39.341 36.99 39.785 ;
     RECT  39.096 39.721 48.474 39.785 ;
     RECT  39.096 39.785 48.402 39.857 ;
     RECT  39.096 39.857 48.114 39.869 ;
     RECT  59.076 39.047 62.442 39.901 ;
     RECT  0.252 39.533 0.558 39.917 ;
     RECT  63.54 39.389 63.558 39.929 ;
     RECT  37.728 39.341 38.322 39.931 ;
     RECT  39.096 39.869 48.006 39.931 ;
     RECT  37.728 39.931 48.006 39.965 ;
     RECT  0.252 39.917 0.522 40.013 ;
     RECT  57.564 38.435 57.582 40.019 ;
     RECT  3.924 39.659 4.842 40.027 ;
     RECT  5.796 39.785 12.006 40.027 ;
     RECT  54.252 39.595 54.63 40.099 ;
     RECT  54.252 40.099 54.846 40.171 ;
     RECT  59.076 39.901 62.694 40.199 ;
     RECT  2.304 39.659 3.078 40.441 ;
     RECT  3.924 40.027 12.006 40.441 ;
     RECT  12.78 39.785 36.99 40.441 ;
     RECT  54.252 40.171 55.386 40.441 ;
     RECT  2.304 40.441 12.006 40.459 ;
     RECT  52.272 39.749 53.082 40.531 ;
     RECT  54.18 40.441 55.386 40.531 ;
     RECT  64.584 37.903 64.782 40.559 ;
     RECT  2.232 40.459 12.006 40.603 ;
     RECT  12.78 40.441 37.026 40.603 ;
     RECT  52.272 40.531 55.386 40.603 ;
     RECT  56.196 38.975 56.697 40.603 ;
     RECT  58.32 38.399 58.338 40.603 ;
     RECT  59.076 40.199 62.298 40.603 ;
     RECT  58.32 40.603 62.298 40.631 ;
     RECT  52.272 40.603 56.697 40.675 ;
     RECT  64.764 40.559 64.782 40.703 ;
     RECT  2.232 40.603 37.026 40.711 ;
     RECT  37.8 39.965 48.006 40.711 ;
     RECT  50.148 39.515 51.498 40.711 ;
     RECT  52.272 40.675 57.33 40.711 ;
     RECT  58.716 40.631 62.298 40.739 ;
     RECT  2.232 40.711 48.006 40.865 ;
     RECT  59.076 40.739 62.298 40.901 ;
     RECT  59.076 40.901 59.382 40.937 ;
     RECT  50.148 40.711 57.33 40.981 ;
     RECT  59.292 40.937 59.382 41.009 ;
     RECT  50.148 40.981 57.438 41.021 ;
     RECT  50.148 41.021 52.866 41.071 ;
     RECT  49.644 41.071 52.866 41.107 ;
     RECT  2.232 40.865 3.978 41.131 ;
     RECT  4.716 40.865 48.006 41.135 ;
     RECT  53.604 41.021 57.438 41.251 ;
     RECT  0.252 40.013 0.27 41.261 ;
     RECT  4.716 41.135 43.65 41.369 ;
     RECT  44.532 41.135 48.006 41.369 ;
     RECT  60.156 40.901 62.298 41.413 ;
     RECT  0.324 41.323 0.342 41.453 ;
     RECT  49.5 41.107 52.866 41.485 ;
     RECT  49.14 41.485 52.866 41.521 ;
     RECT  2.196 41.131 3.978 41.683 ;
     RECT  4.716 41.369 43.542 41.683 ;
     RECT  1.26 41.611 1.278 41.707 ;
     RECT  1.152 41.707 1.278 41.741 ;
     RECT  59.292 41.009 59.31 41.791 ;
     RECT  60.156 41.413 62.73 41.791 ;
     RECT  1.152 41.741 1.17 41.885 ;
     RECT  59.292 41.791 62.73 41.953 ;
     RECT  63.792 41.611 63.81 41.953 ;
     RECT  48.996 41.521 52.866 42.025 ;
     RECT  53.604 41.251 57.654 42.025 ;
     RECT  48.996 42.025 57.654 42.061 ;
     RECT  59.292 41.953 63.81 42.061 ;
     RECT  44.568 41.369 48.006 42.151 ;
     RECT  48.996 42.061 57.942 42.179 ;
     RECT  48.996 42.179 53.118 42.215 ;
     RECT  44.496 42.151 48.006 42.259 ;
     RECT  48.996 42.215 49.338 42.259 ;
     RECT  2.196 41.683 43.542 42.379 ;
     RECT  1.98 42.379 43.542 42.449 ;
     RECT  58.932 42.061 63.81 42.449 ;
     RECT  50.148 42.215 53.118 42.485 ;
     RECT  54.072 42.179 57.942 42.565 ;
     RECT  0.108 42.295 0.126 42.601 ;
     RECT  44.496 42.259 49.338 42.755 ;
     RECT  36.396 42.449 43.542 42.763 ;
     RECT  44.496 42.755 48.294 42.763 ;
     RECT  0.108 42.601 0.558 42.797 ;
     RECT  59.544 42.449 63.81 42.859 ;
     RECT  1.152 42.859 1.17 43.037 ;
     RECT  36.396 42.763 48.294 43.061 ;
     RECT  49.14 42.755 49.338 43.069 ;
     RECT  50.148 42.485 52.686 43.069 ;
     RECT  54.072 42.565 58.482 43.141 ;
     RECT  0.108 42.797 0.342 43.181 ;
     RECT  44.964 43.061 48.294 43.181 ;
     RECT  59.544 42.859 63.846 43.259 ;
     RECT  0.18 43.181 0.342 43.277 ;
     RECT  36.396 43.061 44.01 43.303 ;
     RECT  53.46 43.141 58.482 43.339 ;
     RECT  59.652 43.259 63.846 43.373 ;
     RECT  49.14 43.069 52.686 43.531 ;
     RECT  53.46 43.339 58.662 43.531 ;
     RECT  45.468 43.181 48.294 43.565 ;
     RECT  0.216 43.277 0.342 43.579 ;
     RECT  49.14 43.531 58.662 43.637 ;
     RECT  1.98 42.449 35.622 43.645 ;
     RECT  36.36 43.303 44.01 43.645 ;
     RECT  45.615 43.565 48.294 43.681 ;
     RECT  49.14 43.637 57.87 43.681 ;
     RECT  1.98 43.645 44.01 43.799 ;
     RECT  45.615 43.681 57.87 43.799 ;
     RECT  58.644 43.637 58.662 43.799 ;
     RECT  0.216 43.579 0.414 43.853 ;
     RECT  45.615 43.799 57.834 43.871 ;
     RECT  0.216 43.853 0.234 43.901 ;
     RECT  45.615 43.871 57.798 44.069 ;
     RECT  59.652 43.373 62.442 44.069 ;
     RECT  1.98 43.799 38.646 44.203 ;
     RECT  1.728 44.203 38.646 44.299 ;
     RECT  45.615 44.069 52.686 44.339 ;
     RECT  45.615 44.339 49.086 44.375 ;
     RECT  63.216 43.373 63.846 44.383 ;
     RECT  64.692 43.723 64.71 44.395 ;
     RECT  45.615 44.375 49.014 44.419 ;
     RECT  39.42 43.799 44.01 44.477 ;
     RECT  53.46 44.069 57.798 44.477 ;
     RECT  39.528 44.477 44.01 44.491 ;
     RECT  45.576 44.419 49.014 44.609 ;
     RECT  63.216 44.383 63.882 44.621 ;
     RECT  59.724 44.069 62.442 44.681 ;
     RECT  64.656 44.395 64.71 44.681 ;
     RECT  45.615 44.609 49.014 44.753 ;
     RECT  53.46 44.477 57.294 44.753 ;
     RECT  1.152 44.299 38.646 44.789 ;
     RECT  1.152 44.789 4.59 44.879 ;
     RECT  39.528 44.491 44.298 44.879 ;
     RECT  58.032 44.689 58.122 44.879 ;
     RECT  0.108 44.779 0.126 44.909 ;
     RECT  48.996 44.753 49.014 44.915 ;
     RECT  54.72 44.753 57.294 44.915 ;
     RECT  5.328 44.789 38.646 45.031 ;
     RECT  49.896 44.339 52.686 45.031 ;
     RECT  53.46 44.753 53.982 45.031 ;
     RECT  59.76 44.681 62.442 45.067 ;
     RECT  63.216 44.621 63.846 45.067 ;
     RECT  49.896 45.031 53.982 45.149 ;
     RECT  49.896 45.149 52.578 45.185 ;
     RECT  58.932 44.185 58.95 45.193 ;
     RECT  59.76 45.067 63.846 45.221 ;
     RECT  53.46 45.149 53.982 45.293 ;
     RECT  49.896 45.185 52.506 45.419 ;
     RECT  57.42 45.301 57.438 45.419 ;
     RECT  49.896 45.419 49.914 45.455 ;
     RECT  58.716 45.193 58.95 45.491 ;
     RECT  59.76 45.221 63.81 45.491 ;
     RECT  1.152 44.879 4.338 45.527 ;
     RECT  5.328 45.031 38.79 45.535 ;
     RECT  60.444 45.491 63.81 45.563 ;
     RECT  54.72 44.915 56.697 45.571 ;
     RECT  54.324 45.571 56.697 45.629 ;
     RECT  50.688 45.419 52.506 45.689 ;
     RECT  64.692 44.681 64.71 45.689 ;
     RECT  50.688 45.689 52.326 45.725 ;
     RECT  5.112 45.535 38.79 45.841 ;
     RECT  39.564 44.879 44.298 45.841 ;
     RECT  5.112 45.841 44.298 45.959 ;
     RECT  50.688 45.725 52.254 45.959 ;
     RECT  54.756 45.629 56.697 45.959 ;
     RECT  60.516 45.563 63.81 45.959 ;
     RECT  50.688 45.959 51.786 45.968 ;
     RECT  54.756 45.959 55.35 45.995 ;
     RECT  1.152 45.527 4.122 46.265 ;
     RECT  5.688 45.959 44.298 46.265 ;
     RECT  60.516 45.959 62.406 46.345 ;
     RECT  1.728 46.265 4.122 46.499 ;
     RECT  60.084 46.345 62.406 46.651 ;
     RECT  63.144 45.959 63.81 46.724 ;
     RECT  45.615 44.753 48.258 46.741 ;
     RECT  3.672 46.499 4.122 46.769 ;
     RECT  60.012 46.651 62.406 46.769 ;
     RECT  63.216 46.724 63.81 46.769 ;
     RECT  1.728 46.499 2.754 46.805 ;
     RECT  54.756 45.995 55.278 46.805 ;
     RECT  55.26 46.805 55.278 46.877 ;
     RECT  6.516 46.265 44.298 46.921 ;
     RECT  58.932 45.491 58.95 46.949 ;
     RECT  2.415 46.805 2.754 47.039 ;
     RECT  4.104 46.769 4.122 47.039 ;
     RECT  63.216 46.769 63.234 47.309 ;
     RECT  51.015 45.968 51.786 47.419 ;
     RECT  60.516 46.769 62.406 47.453 ;
     RECT  50.976 47.419 51.786 47.579 ;
     RECT  60.516 47.453 62.37 47.579 ;
     RECT  60.516 47.579 62.097 47.651 ;
     RECT  51.015 47.579 51.786 47.731 ;
     RECT  61.2 47.651 62.097 47.849 ;
     RECT  61.56 47.849 62.097 47.885 ;
     RECT  45.615 46.741 48.294 48.001 ;
     RECT  6.516 46.921 44.514 48.119 ;
     RECT  45.615 48.001 48.366 48.235 ;
     RECT  45.615 48.235 48.834 48.271 ;
     RECT  45.615 48.271 49.338 48.425 ;
     RECT  51.015 47.731 52.218 48.433 ;
     RECT  6.66 48.119 44.514 48.541 ;
     RECT  45.615 48.425 49.086 48.541 ;
     RECT  6.66 48.541 49.086 48.569 ;
     RECT  50.796 48.433 52.218 48.901 ;
     RECT  25.668 48.569 49.086 48.965 ;
     RECT  45.615 48.965 49.086 49.621 ;
     RECT  5.688 46.265 5.706 49.775 ;
     RECT  45.615 49.621 49.338 49.783 ;
     RECT  50.796 48.901 52.29 49.855 ;
     RECT  53.1 49.819 53.118 49.855 ;
     RECT  6.66 48.569 24.822 49.891 ;
     RECT  45.615 49.783 49.95 49.891 ;
     RECT  50.796 49.855 53.118 49.891 ;
     RECT  45.615 49.891 53.658 50.089 ;
     RECT  6.444 49.891 25.002 50.431 ;
     RECT  25.776 48.965 44.586 50.431 ;
     RECT  45.615 50.089 53.802 50.431 ;
     RECT  54.864 50.323 54.882 50.431 ;
     RECT  45.615 50.431 54.882 50.557 ;
     RECT  45.615 50.557 55.026 50.701 ;
     RECT  45.615 50.701 55.278 50.729 ;
     RECT  45.615 50.729 52.686 50.819 ;
     RECT  53.712 50.729 55.278 50.819 ;
     RECT  45.615 50.819 49.23 50.927 ;
     RECT  45.615 50.927 48.222 51.089 ;
     RECT  46.764 51.089 48.222 51.125 ;
     RECT  48.996 50.927 49.23 51.125 ;
     RECT  54.036 50.819 55.278 51.241 ;
     RECT  56.196 45.959 56.697 51.241 ;
     RECT  50.004 50.819 52.686 51.511 ;
     RECT  50.004 51.511 53.082 51.709 ;
     RECT  54.036 51.241 56.697 51.709 ;
     RECT  49.068 51.125 49.23 51.745 ;
     RECT  50.004 51.709 56.697 51.745 ;
     RECT  46.764 51.125 48.15 51.809 ;
     RECT  49.068 51.745 56.697 51.935 ;
     RECT  6.444 50.431 44.586 52.079 ;
     RECT  49.32 51.935 56.697 52.169 ;
     RECT  46.908 51.809 48.15 52.321 ;
     RECT  46.908 52.321 48.366 52.349 ;
     RECT  47.052 52.349 48.366 52.619 ;
     RECT  47.448 52.619 48.366 52.861 ;
     RECT  47.448 52.861 48.762 52.979 ;
     RECT  49.608 52.169 56.697 53.015 ;
     RECT  47.448 52.979 48.582 53.021 ;
     RECT  49.644 53.015 56.697 53.555 ;
     RECT  7.2 52.079 44.586 53.563 ;
     RECT  7.2 53.563 44.766 53.671 ;
     RECT  45.615 51.089 45.897 53.671 ;
     RECT  49.86 53.555 50.058 53.789 ;
     RECT  47.448 53.021 47.934 53.941 ;
     RECT  7.2 53.671 45.897 54.059 ;
     RECT  50.796 53.555 56.697 54.059 ;
     RECT  61.815 47.885 62.097 54.067 ;
     RECT  47.448 53.941 48.15 54.095 ;
     RECT  50.796 54.059 52.29 54.095 ;
     RECT  60.444 54.175 60.462 54.329 ;
     RECT  61.776 54.067 62.097 54.445 ;
     RECT  49.968 53.789 50.058 54.481 ;
     RECT  50.796 54.095 51.894 54.481 ;
     RECT  61.776 54.445 62.334 54.481 ;
     RECT  58.716 54.337 58.734 54.509 ;
     RECT  63.828 54.472 63.846 54.509 ;
     RECT  6.444 52.079 6.462 54.599 ;
     RECT  60.804 54.481 60.822 54.599 ;
     RECT  63.288 54.565 63.306 54.701 ;
     RECT  7.2 54.059 15.822 54.751 ;
     RECT  49.968 54.481 51.894 54.869 ;
     RECT  61.74 54.481 62.334 54.869 ;
     RECT  6.912 54.751 15.822 54.905 ;
     RECT  49.968 54.869 49.986 54.905 ;
     RECT  50.832 54.869 51.894 54.905 ;
     RECT  7.38 54.905 15.822 54.985 ;
     RECT  16.704 54.059 45.897 54.985 ;
     RECT  61.74 54.869 62.298 55.111 ;
     RECT  7.38 54.985 45.897 55.139 ;
     RECT  61.704 55.111 62.298 55.139 ;
     RECT  7.815 55.139 45.897 55.175 ;
     RECT  53.064 54.059 56.697 55.211 ;
     RECT  56.415 55.211 56.697 55.255 ;
     RECT  61.704 55.139 62.097 55.255 ;
     RECT  12.492 55.175 45.897 55.409 ;
     RECT  56.415 55.255 56.826 55.409 ;
     RECT  59.868 55.111 59.886 55.409 ;
     RECT  61.056 55.255 62.097 55.409 ;
     RECT  7.815 55.175 11.718 55.445 ;
     RECT  61.704 55.409 62.097 55.679 ;
     RECT  7.815 55.445 10.458 55.787 ;
     RECT  9.252 55.787 10.458 55.949 ;
     RECT  11.232 55.445 11.718 55.949 ;
     RECT  11.52 55.949 11.718 56.101 ;
     RECT  12.492 55.409 17.082 56.101 ;
     RECT  11.52 56.101 17.082 56.129 ;
     RECT  17.856 55.409 45.897 56.219 ;
     RECT  9.756 55.949 10.386 56.255 ;
     RECT  16.056 56.129 17.082 56.335 ;
     RECT  53.064 55.211 55.53 56.335 ;
     RECT  9.864 56.255 10.386 56.489 ;
     RECT  11.52 56.129 15.21 56.489 ;
     RECT  11.52 56.489 11.934 56.525 ;
     RECT  12.888 56.489 15.21 56.525 ;
     RECT  18.324 56.219 45.897 56.525 ;
     RECT  47.52 54.095 48.15 56.533 ;
     RECT  51.015 54.905 51.894 56.605 ;
     RECT  52.632 56.335 55.53 56.605 ;
     RECT  18.324 56.525 19.962 56.759 ;
     RECT  9.864 56.489 10.062 56.795 ;
     RECT  16.056 56.335 17.478 56.795 ;
     RECT  47.52 56.533 48.906 56.875 ;
     RECT  16.056 56.795 17.226 56.903 ;
     RECT  51.015 56.605 55.53 56.903 ;
     RECT  12.996 56.525 15.21 56.909 ;
     RECT  11.52 56.525 11.538 56.911 ;
     RECT  13.215 56.909 15.21 56.911 ;
     RECT  16.056 56.903 16.794 56.911 ;
     RECT  47.52 56.875 49.374 56.911 ;
     RECT  9.9 56.795 10.062 57.029 ;
     RECT  13.215 56.911 16.794 57.029 ;
     RECT  47.52 56.911 49.518 57.029 ;
     RECT  9.9 57.029 9.918 57.065 ;
     RECT  10.872 56.911 11.538 57.065 ;
     RECT  13.215 57.029 16.686 57.065 ;
     RECT  47.52 57.029 49.23 57.065 ;
     RECT  52.956 56.903 55.53 57.065 ;
     RECT  13.215 57.065 16.506 57.137 ;
     RECT  51.015 56.903 51.297 57.181 ;
     RECT  47.52 57.065 47.538 57.209 ;
     RECT  13.215 57.137 16.218 57.299 ;
     RECT  18.615 56.759 19.962 57.299 ;
     RECT  10.944 57.065 11.538 57.335 ;
     RECT  13.215 57.299 16.074 57.335 ;
     RECT  48.348 57.065 48.834 57.335 ;
     RECT  11.448 57.335 11.538 57.451 ;
     RECT  20.7 56.525 45.897 57.451 ;
     RECT  53.064 57.065 55.53 57.451 ;
     RECT  56.415 55.409 56.697 57.451 ;
     RECT  11.448 57.451 11.574 57.569 ;
     RECT  12.384 57.451 12.402 57.569 ;
     RECT  13.215 57.335 16.002 57.605 ;
     RECT  18.615 57.299 19.53 57.605 ;
     RECT  20.52 57.451 45.897 57.713 ;
     RECT  14.616 57.605 16.002 57.839 ;
     RECT  14.616 57.839 14.634 57.875 ;
     RECT  15.984 57.839 16.002 57.875 ;
     RECT  50.724 57.181 51.297 57.875 ;
     RECT  52.128 56.903 52.146 57.875 ;
     RECT  21.168 57.713 45.897 58.145 ;
     RECT  21.78 58.145 45.897 58.523 ;
     RECT  21.852 58.523 45.897 58.685 ;
     RECT  53.064 57.451 56.697 59.881 ;
     RECT  21.888 58.685 45.897 60.313 ;
     RECT  52.74 59.881 56.697 60.781 ;
     RECT  21.888 60.313 45.99 60.961 ;
     RECT  21.78 60.961 45.99 61.655 ;
     RECT  52.416 60.781 56.697 61.655 ;
     RECT  52.74 61.655 56.697 61.925 ;
     RECT  21.78 61.655 45.954 62.159 ;
     RECT  52.776 61.925 56.697 62.159 ;
     RECT  53.028 62.159 55.098 62.231 ;
     RECT  55.836 62.159 56.697 62.231 ;
     RECT  2.415 47.039 2.697 62.387 ;
     RECT  7.815 55.787 8.097 62.387 ;
     RECT  13.215 57.605 13.497 62.387 ;
     RECT  18.615 57.605 18.897 62.387 ;
     RECT  51.015 57.875 51.297 62.387 ;
     RECT  56.415 62.231 56.697 62.387 ;
     RECT  61.815 55.679 62.097 62.387 ;
     RECT  53.208 62.231 55.098 62.429 ;
     RECT  22.068 62.159 45.954 62.465 ;
     RECT  53.208 62.429 54.27 62.465 ;
     RECT  53.208 62.465 54.162 62.573 ;
     RECT  22.572 62.465 45.954 62.609 ;
     RECT  2.415 62.387 2.505 62.657 ;
     RECT  7.815 62.387 7.905 62.657 ;
     RECT  13.215 62.387 13.305 62.657 ;
     RECT  18.615 62.387 18.705 62.657 ;
     RECT  22.572 62.609 45.705 62.657 ;
     RECT  51.015 62.387 51.105 62.657 ;
     RECT  56.415 62.387 56.505 62.657 ;
     RECT  61.815 62.387 61.905 62.657 ;
     RECT  53.208 62.573 54.054 62.669 ;
     RECT  22.572 62.657 45.018 62.699 ;
     RECT  22.572 62.699 44.982 62.717 ;
     RECT  22.572 62.717 25.29 62.765 ;
     RECT  32.04 62.717 44.982 62.765 ;
     RECT  25.02 62.765 25.29 63.245 ;
     RECT  26.208 62.717 31.23 63.245 ;
     RECT  32.04 62.765 44.91 63.245 ;
     RECT  53.208 62.669 53.946 63.245 ;
     RECT  53.208 63.245 53.622 63.293 ;
     RECT  27 63.245 31.23 63.821 ;
     RECT  32.04 63.245 34.182 63.821 ;
     RECT  35.208 63.245 38.682 63.821 ;
     RECT  40.068 63.245 40.122 63.821 ;
     RECT  27 63.821 29.358 63.869 ;
     RECT  32.832 63.821 33.678 63.869 ;
     RECT  37.944 63.821 38.682 63.869 ;
     RECT  40.932 63.245 44.91 63.869 ;
     RECT  53.208 63.293 53.226 63.869 ;
     RECT  38.556 63.869 38.682 64.507 ;
     RECT  22.932 62.765 24.282 64.541 ;
     RECT  32.832 63.869 32.886 64.589 ;
     RECT  22.932 64.541 24.246 64.637 ;
     RECT  27 63.869 28.854 64.637 ;
     RECT  30.492 63.821 30.726 64.637 ;
     RECT  22.932 64.637 24.174 64.685 ;
     RECT  25.02 63.245 25.038 64.685 ;
     RECT  26.208 63.245 26.226 64.685 ;
     RECT  27 64.637 27.594 64.685 ;
     RECT  28.404 64.637 28.854 64.685 ;
     RECT  30.492 64.637 30.51 64.685 ;
     RECT  32.04 63.821 32.058 64.685 ;
     RECT  32.868 64.589 32.886 64.685 ;
     RECT  33.66 63.869 33.678 64.685 ;
     RECT  35.208 63.821 36.954 64.685 ;
     RECT  38.556 64.507 39.042 64.685 ;
     RECT  40.104 63.821 40.122 64.685 ;
     RECT  40.932 63.869 40.95 64.685 ;
     RECT  42.012 63.869 42.678 64.685 ;
     RECT  43.632 63.869 44.91 64.685 ;
    LAYER M4 ;
     RECT  0.06 27.984 0.097 44.808 ;
     RECT  0.06 19.536 0.133 25.608 ;
     RECT  0.133 19.536 0.137 25.656 ;
     RECT  0.097 27.984 0.137 44.904 ;
     RECT  0.137 19.632 0.173 25.656 ;
     RECT  0.137 28.08 0.173 44.904 ;
     RECT  0.173 19.728 0.209 25.656 ;
     RECT  0.173 28.176 0.209 44.904 ;
     RECT  0.209 28.272 0.245 44.904 ;
     RECT  0.245 28.368 0.569 44.904 ;
     RECT  0.209 19.824 2.408 25.656 ;
     RECT  0.569 28.464 2.408 44.904 ;
     RECT  2.408 2.148 2.512 62.652 ;
     RECT  2.512 2.418 2.704 62.382 ;
     RECT  2.704 29.52 2.765 38.28 ;
     RECT  2.704 39.6 2.765 44.904 ;
     RECT  2.765 31.104 2.801 37.992 ;
     RECT  2.765 43.008 2.801 44.904 ;
     RECT  2.704 20.688 2.837 25.32 ;
     RECT  2.837 20.688 2.873 21.528 ;
     RECT  2.765 29.616 2.873 29.688 ;
     RECT  2.765 39.6 3.053 42.024 ;
     RECT  2.837 22.56 3.089 25.32 ;
     RECT  2.801 31.104 3.089 33.576 ;
     RECT  3.053 39.6 3.089 40.968 ;
     RECT  3.053 42 3.089 42.024 ;
     RECT  3.089 25.2 3.125 25.32 ;
     RECT  2.873 20.688 3.161 21.48 ;
     RECT  3.089 31.44 3.161 33.576 ;
     RECT  2.801 34.656 3.161 37.992 ;
     RECT  3.089 23.856 3.197 23.976 ;
     RECT  3.125 25.296 3.233 25.32 ;
     RECT  2.801 43.008 3.233 43.608 ;
     RECT  3.089 40.272 3.341 40.968 ;
     RECT  3.161 21.456 3.377 21.48 ;
     RECT  3.161 32.448 3.377 32.856 ;
     RECT  2.873 29.664 3.733 29.688 ;
     RECT  3.733 29.664 3.949 29.88 ;
     RECT  3.949 29.616 4.021 29.88 ;
     RECT  3.341 40.272 4.097 40.296 ;
     RECT  3.089 22.848 4.345 22.872 ;
     RECT  3.197 23.952 4.345 23.976 ;
     RECT  3.377 32.448 4.385 32.568 ;
     RECT  3.233 43.008 4.385 43.032 ;
     RECT  4.345 22.848 4.421 23.976 ;
     RECT  4.421 22.848 4.493 23.304 ;
     RECT  3.161 36.912 4.709 37.992 ;
     RECT  4.021 29.088 5.101 29.88 ;
     RECT  3.161 35.28 5.101 35.832 ;
     RECT  5.101 34.752 5.132 35.832 ;
     RECT  4.709 36.912 5.132 37.56 ;
     RECT  4.741 44.304 5.132 44.328 ;
     RECT  3.161 31.44 5.137 31.464 ;
     RECT  4.385 32.448 5.137 32.472 ;
     RECT  4.417 39.312 5.173 39.336 ;
     RECT  5.101 40.464 5.173 40.488 ;
     RECT  5.132 43.728 5.219 44.328 ;
     RECT  5.132 34.752 5.321 37.56 ;
     RECT  5.101 29.088 5.465 30.264 ;
     RECT  5.173 39.312 5.501 40.488 ;
     RECT  5.101 25.296 5.605 25.32 ;
     RECT  5.501 40.32 5.641 40.488 ;
     RECT  5.605 24.432 5.677 25.32 ;
     RECT  5.321 35.856 5.713 37.56 ;
     RECT  4.493 23.28 5.749 23.304 ;
     RECT  5.677 24.384 5.749 25.32 ;
     RECT  5.641 40.32 5.785 41.016 ;
     RECT  5.137 42.336 5.785 42.744 ;
     RECT  5.501 39.312 5.825 39.336 ;
     RECT  5.137 31.44 5.965 32.472 ;
     RECT  5.749 23.28 6.037 25.32 ;
     RECT  5.965 31.44 6.037 33.288 ;
     RECT  5.321 34.752 6.037 34.872 ;
     RECT  4.705 27.408 6.073 27.432 ;
     RECT  5.785 40.32 6.109 42.744 ;
     RECT  5.219 44.304 6.217 44.328 ;
     RECT  5.713 35.856 6.253 38.04 ;
     RECT  6.073 27.408 6.289 27.96 ;
     RECT  5.465 29.088 6.289 29.64 ;
     RECT  6.037 31.44 6.325 34.872 ;
     RECT  6.253 35.856 6.325 38.76 ;
     RECT  5.713 21.648 6.433 21.672 ;
     RECT  6.325 31.44 6.433 38.76 ;
     RECT  6.217 44.304 6.473 44.472 ;
     RECT  6.289 27.408 6.524 29.64 ;
     RECT  6.433 31.248 6.524 38.76 ;
     RECT  6.037 23.04 6.577 25.32 ;
     RECT  6.109 40.32 6.577 43.128 ;
     RECT  6.524 27.408 6.611 38.76 ;
     RECT  6.253 19.968 6.661 19.992 ;
     RECT  6.577 23.04 6.721 25.512 ;
     RECT  6.661 19.968 6.744 20.568 ;
     RECT  6.433 21.648 6.744 21.96 ;
     RECT  6.611 27.408 6.761 30.216 ;
     RECT  6.761 27.408 6.829 28.536 ;
     RECT  6.577 40.32 6.833 43.848 ;
     RECT  6.833 40.32 7.117 40.488 ;
     RECT  6.744 19.968 7.153 21.96 ;
     RECT  6.721 23.04 7.153 26.232 ;
     RECT  7.153 19.968 7.189 26.232 ;
     RECT  6.829 27.36 7.189 28.536 ;
     RECT  7.009 52.032 7.369 52.056 ;
     RECT  6.611 31.248 7.441 38.76 ;
     RECT  7.117 39.888 7.441 40.488 ;
     RECT  6.833 41.616 7.765 43.848 ;
     RECT  7.189 19.968 7.808 28.536 ;
     RECT  6.761 29.616 7.808 30.216 ;
     RECT  7.441 31.248 7.808 40.488 ;
     RECT  7.765 41.616 7.808 44.472 ;
     RECT  7.381 49.488 7.808 49.512 ;
     RECT  6.469 50.688 7.808 50.712 ;
     RECT  7.369 51.744 7.808 52.056 ;
     RECT  7.369 54.864 7.808 54.888 ;
     RECT  7.808 2.148 7.912 62.652 ;
     RECT  7.912 2.418 8.104 62.382 ;
     RECT  8.104 51.744 8.489 52.056 ;
     RECT  8.104 19.632 8.579 25.56 ;
     RECT  8.579 19.632 8.705 19.656 ;
     RECT  8.104 54.864 8.813 55.272 ;
     RECT  8.579 21.12 8.921 25.56 ;
     RECT  8.921 21.12 9.065 22.776 ;
     RECT  8.104 26.544 9.065 28.008 ;
     RECT  8.104 40.224 9.137 40.44 ;
     RECT  8.921 23.952 9.209 25.56 ;
     RECT  8.104 41.616 9.209 44.472 ;
     RECT  8.104 48.24 9.277 49.032 ;
     RECT  8.104 31.44 9.353 39 ;
     RECT  9.209 43.872 9.461 44.472 ;
     RECT  9.385 46.752 9.641 46.776 ;
     RECT  8.813 55.008 9.731 55.272 ;
     RECT  9.277 54 9.781 54.024 ;
     RECT  9.353 36.096 9.821 39 ;
     RECT  9.461 44.4 9.821 44.472 ;
     RECT  9.821 36.096 9.857 38.568 ;
     RECT  9.209 24.72 9.877 25.56 ;
     RECT  9.065 26.544 9.877 27.912 ;
     RECT  9.065 21.456 9.893 22.776 ;
     RECT  9.857 37.44 9.893 38.568 ;
     RECT  8.104 29.856 10.033 29.88 ;
     RECT  9.137 40.224 10.033 40.296 ;
     RECT  9.877 24.72 10.109 27.912 ;
     RECT  9.209 42.864 10.145 42.888 ;
     RECT  9.353 31.44 10.211 34.536 ;
     RECT  10.211 31.44 10.217 31.992 ;
     RECT  9.277 47.856 10.217 49.032 ;
     RECT  8.489 52.032 10.249 52.056 ;
     RECT  10.249 52.032 10.289 52.728 ;
     RECT  9.781 54 10.289 54.6 ;
     RECT  9.893 21.456 10.321 22.2 ;
     RECT  9.685 56.4 10.325 56.424 ;
     RECT  10.033 29.616 10.415 29.88 ;
     RECT  10.415 29.616 10.453 30.168 ;
     RECT  10.217 31.44 10.453 31.944 ;
     RECT  10.453 29.616 10.469 31.944 ;
     RECT  9.857 36.096 10.501 36.168 ;
     RECT  10.109 26.208 10.685 27.912 ;
     RECT  10.217 48.624 10.757 49.032 ;
     RECT  10.109 24.72 10.789 25.08 ;
     RECT  9.893 38.544 10.825 38.568 ;
     RECT  10.033 39.552 10.825 40.296 ;
     RECT  10.469 29.856 10.829 31.944 ;
     RECT  9.821 44.4 10.861 44.424 ;
     RECT  10.501 35.952 10.897 36.168 ;
     RECT  10.825 38.544 10.909 40.296 ;
     RECT  10.321 21.36 11.029 22.2 ;
     RECT  11.029 20.736 11.041 22.2 ;
     RECT  10.681 46.752 11.077 46.776 ;
     RECT  10.717 45.552 11.117 45.576 ;
     RECT  11.077 46.656 11.125 46.776 ;
     RECT  10.757 48.768 11.125 49.032 ;
     RECT  10.897 35.952 11.149 36.264 ;
     RECT  9.893 37.44 11.149 37.464 ;
     RECT  11.125 46.656 11.171 47.592 ;
     RECT  10.211 33.36 11.293 34.536 ;
     RECT  9.209 41.616 11.297 41.64 ;
     RECT  11.149 35.952 11.329 37.464 ;
     RECT  10.909 38.544 11.329 38.568 ;
     RECT  10.289 52.704 11.329 52.728 ;
     RECT  11.329 51.888 11.365 52.728 ;
     RECT  11.041 20.496 11.401 22.2 ;
     RECT  10.685 26.208 11.405 27.528 ;
     RECT  11.365 51.216 11.405 53.064 ;
     RECT  11.405 51.216 11.413 51.912 ;
     RECT  11.401 20.496 11.441 23.016 ;
     RECT  10.909 39.552 11.468 40.296 ;
     RECT  11.441 21.504 11.507 23.016 ;
     RECT  11.171 47.568 11.513 47.592 ;
     RECT  11.441 20.496 11.545 20.52 ;
     RECT  10.357 55.824 11.545 55.848 ;
     RECT  11.468 39.552 11.555 41.064 ;
     RECT  11.365 42.144 11.555 42.168 ;
     RECT  11.329 35.952 11.617 38.568 ;
     RECT  11.405 53.04 11.617 53.064 ;
     RECT  11.617 53.04 11.657 53.592 ;
     RECT  11.413 51.216 11.689 51.24 ;
     RECT  10.829 30.144 11.693 31.944 ;
     RECT  11.293 33.216 11.699 34.536 ;
     RECT  11.617 35.904 11.701 38.568 ;
     RECT  11.545 19.968 11.729 20.52 ;
     RECT  10.789 24.24 11.729 25.08 ;
     RECT  11.405 26.208 11.765 26.664 ;
     RECT  11.555 39.552 11.801 40.296 ;
     RECT  11.699 33.36 11.869 34.536 ;
     RECT  11.801 40.272 11.945 40.296 ;
     RECT  11.693 30.144 11.989 31.704 ;
     RECT  11.125 48.768 11.989 49.176 ;
     RECT  11.545 55.584 11.989 55.848 ;
     RECT  11.437 57.024 11.989 57.048 ;
     RECT  11.869 33.36 12.017 34.824 ;
     RECT  11.657 53.568 12.017 53.592 ;
     RECT  11.989 55.584 12.035 57.048 ;
     RECT  11.989 29.904 12.049 31.704 ;
     RECT  12.035 55.584 12.076 56.904 ;
     RECT  12.049 29.808 12.157 31.704 ;
     RECT  11.989 48.768 12.157 49.56 ;
     RECT  11.689 50.736 12.161 51.24 ;
     RECT  10.861 44.304 12.197 44.424 ;
     RECT  12.197 44.4 12.227 44.424 ;
     RECT  12.409 47.376 12.517 47.4 ;
     RECT  11.765 26.64 12.589 26.664 ;
     RECT  12.181 45.6 12.841 45.624 ;
     RECT  11.701 36.048 12.949 38.568 ;
     RECT  12.841 45.456 13.021 45.624 ;
     RECT  12.949 35.808 13.057 38.568 ;
     RECT  12.589 26.64 13.093 27.624 ;
     RECT  12.157 29.664 13.093 31.704 ;
     RECT  10.289 54.576 13.093 54.6 ;
     RECT  12.076 55.584 13.093 55.8 ;
     RECT  12.161 51.216 13.165 51.24 ;
     RECT  11.729 19.968 13.208 19.992 ;
     RECT  11.507 21.936 13.208 22.584 ;
     RECT  11.729 24.24 13.208 24.744 ;
     RECT  13.093 26.64 13.208 27.912 ;
     RECT  13.093 29.04 13.208 31.704 ;
     RECT  12.017 34.128 13.208 34.824 ;
     RECT  13.057 35.808 13.208 39.528 ;
     RECT  13.165 43.296 13.208 43.32 ;
     RECT  13.021 44.976 13.208 45.624 ;
     RECT  12.517 47.04 13.208 47.4 ;
     RECT  12.157 48.432 13.208 49.56 ;
     RECT  13.165 51.216 13.208 52.056 ;
     RECT  13.093 54.576 13.208 55.8 ;
     RECT  12.076 56.88 13.208 56.904 ;
     RECT  13.208 2.148 13.312 62.652 ;
     RECT  13.312 2.418 13.504 62.382 ;
     RECT  13.504 38.688 13.709 41.064 ;
     RECT  13.504 22.032 13.715 23.4 ;
     RECT  13.504 35.808 13.715 37.032 ;
     RECT  13.504 48.432 13.715 51 ;
     RECT  13.715 22.032 13.859 22.824 ;
     RECT  13.504 25.68 13.861 28.056 ;
     RECT  13.504 43.296 13.889 47.304 ;
     RECT  13.859 22.56 13.925 22.824 ;
     RECT  13.889 43.296 13.997 45 ;
     RECT  13.504 33.552 14.003 33.576 ;
     RECT  13.997 44.448 14.069 45 ;
     RECT  13.861 25.824 14.141 28.056 ;
     RECT  13.997 43.296 14.285 43.32 ;
     RECT  13.504 57.024 14.285 57.576 ;
     RECT  13.504 53.664 14.321 53.688 ;
     RECT  13.504 29.04 14.357 31.464 ;
     RECT  13.504 52.032 14.357 52.056 ;
     RECT  13.709 39.888 14.429 41.064 ;
     RECT  13.504 54.672 14.627 54.696 ;
     RECT  13.715 49.008 14.637 51 ;
     RECT  14.533 52.896 14.645 53.016 ;
     RECT  14.645 52.992 14.668 53.016 ;
     RECT  13.504 55.776 14.681 55.8 ;
     RECT  13.504 34.752 14.773 34.776 ;
     RECT  14.749 42.144 14.821 42.168 ;
     RECT  13.889 46.272 14.965 47.304 ;
     RECT  13.925 22.752 14.969 22.824 ;
     RECT  14.429 39.888 14.969 40.44 ;
     RECT  14.069 44.448 15.073 44.472 ;
     RECT  14.773 33.792 15.109 34.776 ;
     RECT  15.109 33.792 15.145 34.92 ;
     RECT  14.965 46.272 15.145 47.688 ;
     RECT  13.709 38.688 15.149 38.712 ;
     RECT  15.145 33.6 15.289 34.92 ;
     RECT  15.145 46.08 15.361 47.688 ;
     RECT  14.637 50.832 15.361 51 ;
     RECT  15.289 33.6 15.397 34.968 ;
     RECT  13.715 36.048 15.397 37.032 ;
     RECT  14.677 21.264 15.401 21.288 ;
     RECT  14.357 29.04 15.401 29.784 ;
     RECT  14.141 25.824 15.437 27.336 ;
     RECT  14.969 22.752 15.469 22.776 ;
     RECT  14.637 49.008 15.469 49.608 ;
     RECT  15.469 48.96 15.509 49.608 ;
     RECT  14.821 42.048 15.541 42.168 ;
     RECT  15.541 42.048 15.577 42.456 ;
     RECT  15.437 26.976 15.725 27.336 ;
     RECT  15.073 43.68 15.761 44.472 ;
     RECT  15.733 39.408 15.82 39.432 ;
     RECT  15.397 33.6 15.833 37.032 ;
     RECT  15.725 27.312 15.869 27.336 ;
     RECT  15.469 22.704 16.013 22.776 ;
     RECT  15.325 38.208 16.013 38.232 ;
     RECT  15.577 41.616 16.049 42.456 ;
     RECT  15.721 0.096 16.115 0.12 ;
     RECT  16.049 42.048 16.165 42.456 ;
     RECT  15.761 43.68 16.165 44.424 ;
     RECT  16.117 1.728 16.189 1.752 ;
     RECT  14.357 31.44 16.189 31.464 ;
     RECT  16.189 1.104 16.21 1.752 ;
     RECT  16.21 1.104 16.22 1.8 ;
     RECT  14.969 40.416 16.261 40.44 ;
     RECT  15.361 50.832 16.265 51.192 ;
     RECT  16.261 40.032 16.301 40.44 ;
     RECT  15.361 46.08 16.369 47.88 ;
     RECT  16.369 45.552 16.409 47.88 ;
     RECT  14.821 56.88 16.481 56.904 ;
     RECT  16.265 51.168 16.517 51.192 ;
     RECT  15.401 29.76 16.549 29.784 ;
     RECT  15.833 33.6 16.553 33.816 ;
     RECT  16.409 46.608 16.589 47.88 ;
     RECT  16.22 1.104 16.595 2.28 ;
     RECT  16.225 5.664 16.661 5.688 ;
     RECT  15.437 25.824 16.733 25.848 ;
     RECT  16.409 45.552 16.805 45.576 ;
     RECT  15.509 48.96 16.837 49.032 ;
     RECT  16.165 42.048 16.877 44.424 ;
     RECT  16.549 29.76 16.913 29.976 ;
     RECT  16.189 31.44 16.913 31.656 ;
     RECT  16.877 42.048 17.089 42.84 ;
     RECT  16.693 50.112 17.129 50.136 ;
     RECT  15.865 24.288 17.201 24.312 ;
     RECT  16.877 44.4 17.201 44.424 ;
     RECT  16.441 21.648 17.269 21.672 ;
     RECT  16.013 22.752 17.269 22.776 ;
     RECT  16.301 40.032 17.377 40.056 ;
     RECT  16.589 46.608 17.381 47.688 ;
     RECT  17.161 26.352 17.413 26.616 ;
     RECT  17.377 39.888 17.417 40.056 ;
     RECT  15.833 34.896 17.449 37.032 ;
     RECT  17.612 5.616 17.653 5.64 ;
     RECT  17.381 46.752 17.773 47.688 ;
     RECT  17.417 39.888 17.948 39.912 ;
     RECT  16.595 1.728 17.953 2.28 ;
     RECT  17.653 5.616 17.989 6.264 ;
     RECT  17.773 46.752 18.025 47.88 ;
     RECT  16.837 48.912 18.025 49.032 ;
     RECT  17.449 34.896 18.097 37.176 ;
     RECT  17.125 7.968 18.284 7.992 ;
     RECT  18.284 7.968 18.325 8.568 ;
     RECT  18.277 0.576 18.421 0.6 ;
     RECT  17.765 3.984 18.421 4.008 ;
     RECT  17.948 39.312 18.457 39.912 ;
     RECT  17.089 41.136 18.457 42.84 ;
     RECT  16.913 31.44 18.529 31.464 ;
     RECT  18.457 39.312 18.529 42.84 ;
     RECT  18.529 38.736 18.565 42.84 ;
     RECT  17.953 1.728 18.608 2.904 ;
     RECT  18.421 3.984 18.608 4.392 ;
     RECT  17.989 5.616 18.608 6.888 ;
     RECT  18.325 7.92 18.608 8.568 ;
     RECT  18.449 9.648 18.608 9.672 ;
     RECT  18.469 11.232 18.608 11.256 ;
     RECT  17.269 21.648 18.608 22.776 ;
     RECT  18.601 23.856 18.608 23.88 ;
     RECT  17.413 26.352 18.608 26.808 ;
     RECT  17.377 28.8 18.608 28.824 ;
     RECT  16.913 29.952 18.608 29.976 ;
     RECT  18.529 31.44 18.608 31.704 ;
     RECT  16.553 33.6 18.608 33.624 ;
     RECT  18.097 34.656 18.608 37.176 ;
     RECT  18.565 38.736 18.608 43.32 ;
     RECT  18.277 45.552 18.608 45.576 ;
     RECT  18.025 46.752 18.608 49.032 ;
     RECT  18.349 52.8 18.608 52.824 ;
     RECT  17.953 55.104 18.608 55.128 ;
     RECT  17.305 56.352 18.608 56.376 ;
     RECT  18.421 0.144 18.611 0.6 ;
     RECT  18.608 1.728 18.712 62.652 ;
     RECT  18.712 1.728 18.904 62.382 ;
     RECT  18.611 0.576 18.908 0.6 ;
     RECT  18.904 1.728 18.908 2.28 ;
     RECT  18.904 39.888 18.929 43.704 ;
     RECT  18.908 0.576 18.995 2.28 ;
     RECT  18.904 5.04 19.043 6.504 ;
     RECT  18.904 45.744 19.073 52.584 ;
     RECT  18.904 28.272 19.081 28.536 ;
     RECT  18.904 33.6 19.145 36.936 ;
     RECT  18.995 1.728 19.187 2.28 ;
     RECT  18.904 25.824 19.217 26.76 ;
     RECT  18.929 39.888 19.253 43.512 ;
     RECT  18.904 55.248 19.283 57.144 ;
     RECT  18.904 7.92 19.379 9.816 ;
     RECT  19.145 34.368 19.397 36.936 ;
     RECT  19.397 34.464 19.475 36.936 ;
     RECT  19.475 34.464 19.505 35.352 ;
     RECT  19.283 55.248 19.505 55.752 ;
     RECT  19.043 5.712 19.577 6.504 ;
     RECT  19.505 34.464 19.577 35.064 ;
     RECT  18.904 38.112 19.667 38.76 ;
     RECT  19.253 39.888 19.667 42.072 ;
     RECT  19.577 34.656 19.685 35.064 ;
     RECT  18.904 13.248 19.708 13.272 ;
     RECT  19.073 45.744 19.757 48.504 ;
     RECT  18.904 22.56 19.793 24.6 ;
     RECT  19.073 49.488 19.859 52.584 ;
     RECT  18.904 31.44 19.897 31.704 ;
     RECT  19.859 51.888 19.897 52.584 ;
     RECT  19.685 34.896 19.901 35.064 ;
     RECT  19.859 49.488 19.901 50.712 ;
     RECT  19.901 49.488 19.907 50.52 ;
     RECT  19.897 30.816 19.909 31.704 ;
     RECT  19.217 25.824 19.937 26.232 ;
     RECT  18.995 0.576 19.969 0.6 ;
     RECT  19.187 1.728 19.969 2.184 ;
     RECT  19.667 39.888 20.045 40.488 ;
     RECT  19.081 28.272 20.101 28.296 ;
     RECT  19.379 9.216 20.117 9.816 ;
     RECT  19.969 0.576 20.149 2.184 ;
     RECT  19.757 48.48 20.149 48.504 ;
     RECT  19.907 49.488 20.149 50.232 ;
     RECT  19.937 26.208 20.153 26.232 ;
     RECT  18.904 44.688 20.153 44.712 ;
     RECT  19.793 22.56 20.197 23.352 ;
     RECT  19.577 5.712 20.204 5.736 ;
     RECT  19.379 7.92 20.245 7.944 ;
     RECT  20.204 5.088 20.291 5.736 ;
     RECT  20.117 9.216 20.291 9.24 ;
     RECT  18.904 11.76 20.293 11.784 ;
     RECT  20.293 11.76 20.369 12.552 ;
     RECT  19.667 38.208 20.437 38.76 ;
     RECT  20.245 7.872 20.473 7.944 ;
     RECT  20.101 27.888 20.501 28.296 ;
     RECT  20.149 0.576 20.531 2.28 ;
     RECT  20.501 27.888 20.545 29.112 ;
     RECT  19.909 30.576 20.545 31.704 ;
     RECT  19.475 36.336 20.549 36.936 ;
     RECT  20.473 7.872 20.585 8.04 ;
     RECT  20.545 27.888 20.585 31.704 ;
     RECT  20.531 1.68 20.627 2.28 ;
     RECT  19.793 24.336 20.693 24.6 ;
     RECT  20.197 22.368 20.725 23.352 ;
     RECT  20.437 38.208 20.725 38.808 ;
     RECT  20.045 39.888 20.725 39.912 ;
     RECT  20.291 5.712 20.732 5.736 ;
     RECT  19.933 6.816 20.732 6.84 ;
     RECT  19.757 45.744 20.732 47.304 ;
     RECT  20.732 44.928 20.761 47.304 ;
     RECT  20.149 48.48 20.761 50.232 ;
     RECT  20.689 41.04 20.773 41.064 ;
     RECT  19.667 42.048 20.773 42.072 ;
     RECT  19.253 43.488 20.773 43.512 ;
     RECT  19.505 55.536 20.833 55.752 ;
     RECT  19.283 57.024 20.833 57.144 ;
     RECT  20.732 5.712 20.873 6.84 ;
     RECT  19.897 51.888 20.909 52.92 ;
     RECT  20.693 24.336 20.915 24.408 ;
     RECT  20.585 30.048 20.941 31.704 ;
     RECT  20.761 44.928 20.945 50.232 ;
     RECT  20.909 51.888 20.972 52.344 ;
     RECT  20.945 44.928 20.981 49.992 ;
     RECT  20.725 38.208 21.013 39.912 ;
     RECT  20.833 55.536 21.013 57.144 ;
     RECT  20.981 44.928 21.017 47.928 ;
     RECT  19.901 34.896 21.049 34.92 ;
     RECT  20.972 51.36 21.059 52.344 ;
     RECT  20.627 1.728 21.085 2.28 ;
     RECT  20.873 5.712 21.125 5.736 ;
     RECT  18.904 54.048 21.125 54.072 ;
     RECT  21.013 38.208 21.193 40.536 ;
     RECT  21.013 55.536 21.193 57.624 ;
     RECT  21.157 26.784 21.269 26.808 ;
     RECT  21.017 46.224 21.299 47.928 ;
     RECT  20.293 10.224 21.301 10.248 ;
     RECT  20.981 48.912 21.341 49.992 ;
     RECT  21.085 1.728 21.373 2.904 ;
     RECT  20.549 36.672 21.373 36.936 ;
     RECT  21.193 38.016 21.373 40.536 ;
     RECT  21.373 1.728 21.395 3.432 ;
     RECT  21.301 10.224 21.397 10.824 ;
     RECT  20.369 11.952 21.404 12.552 ;
     RECT  21.061 14.256 21.409 14.28 ;
     RECT  21.397 9.072 21.443 10.824 ;
     RECT  21.395 3.408 21.445 3.432 ;
     RECT  21.443 10.8 21.445 10.824 ;
     RECT  21.404 11.808 21.445 12.552 ;
     RECT  21.373 36.672 21.449 40.536 ;
     RECT  20.773 42.048 21.449 43.512 ;
     RECT  21.443 9.072 21.485 9.384 ;
     RECT  20.725 21.648 21.485 23.352 ;
     RECT  20.941 30.048 21.485 32.136 ;
     RECT  21.299 46.224 21.485 47.304 ;
     RECT  21.485 21.648 21.491 22.776 ;
     RECT  21.445 10.8 21.521 12.552 ;
     RECT  21.445 3.408 21.529 4.008 ;
     RECT  21.485 30.624 21.593 32.136 ;
     RECT  21.449 36.672 21.593 39.24 ;
     RECT  21.529 3.408 21.683 3.432 ;
     RECT  20.585 27.888 21.685 28.344 ;
     RECT  21.521 11.376 21.701 12.552 ;
     RECT  21.193 54.24 21.701 57.624 ;
     RECT  21.685 27.888 21.731 28.92 ;
     RECT  21.485 9.36 21.737 9.384 ;
     RECT  21.731 28.176 21.772 28.92 ;
     RECT  21.059 51.84 21.773 52.344 ;
     RECT  21.449 40.512 21.809 40.536 ;
     RECT  20.531 0.576 21.817 0.6 ;
     RECT  21.409 14.256 21.829 14.856 ;
     RECT  21.341 49.92 21.845 49.992 ;
     RECT  20.873 6.72 21.877 6.84 ;
     RECT  20.585 7.872 21.877 7.896 ;
     RECT  21.829 14.256 21.916 15.72 ;
     RECT  21.593 30.624 21.917 31.944 ;
     RECT  21.701 55.488 21.917 57.624 ;
     RECT  21.917 30.672 21.989 31.944 ;
     RECT  20.977 25.68 22.057 25.704 ;
     RECT  21.916 14.256 22.097 15.432 ;
     RECT  20.915 24.384 22.097 24.408 ;
     RECT  22.057 25.68 22.124 26.76 ;
     RECT  21.877 6.672 22.133 7.896 ;
     RECT  22.133 6.816 22.201 7.896 ;
     RECT  22.124 24.816 22.211 26.76 ;
     RECT  22.211 26.208 22.241 26.76 ;
     RECT  21.049 34.896 22.273 35.064 ;
     RECT  21.773 51.888 22.273 52.344 ;
     RECT  22.213 0.096 22.313 0.12 ;
     RECT  21.593 36.672 22.313 38.04 ;
     RECT  21.395 1.728 22.345 2.28 ;
     RECT  21.341 48.912 22.345 48.936 ;
     RECT  22.097 14.256 22.381 14.28 ;
     RECT  22.241 26.208 22.421 26.232 ;
     RECT  22.345 1.152 22.451 2.28 ;
     RECT  21.485 46.704 22.489 47.304 ;
     RECT  22.489 46.416 22.501 47.304 ;
     RECT  22.345 48.624 22.501 48.936 ;
     RECT  22.313 36.672 22.525 37.464 ;
     RECT  21.593 39.216 22.561 39.24 ;
     RECT  22.525 36.576 22.637 37.464 ;
     RECT  22.501 46.416 22.637 48.936 ;
     RECT  22.556 62.736 22.693 62.76 ;
     RECT  21.491 22.752 22.705 22.776 ;
     RECT  22.561 39.216 22.705 39.624 ;
     RECT  21.772 28.176 22.741 28.2 ;
     RECT  21.701 11.376 22.745 11.976 ;
     RECT  22.381 13.296 22.745 14.28 ;
     RECT  21.017 44.928 22.745 45.048 ;
     RECT  22.637 46.896 22.777 48.936 ;
     RECT  21.845 49.92 22.777 49.944 ;
     RECT  22.741 28.176 22.781 28.488 ;
     RECT  22.705 38.784 22.781 39.624 ;
     RECT  22.273 51.888 22.781 53.256 ;
     RECT  21.917 55.488 22.781 57.576 ;
     RECT  21.449 42.048 22.789 43.032 ;
     RECT  22.813 45.12 22.849 45.144 ;
     RECT  22.781 52.08 22.849 53.256 ;
     RECT  21.701 54.24 22.849 54.504 ;
     RECT  22.789 41.856 22.885 43.032 ;
     RECT  22.451 1.68 22.931 2.28 ;
     RECT  22.489 40.752 22.957 40.824 ;
     RECT  22.885 41.856 22.957 43.56 ;
     RECT  21.989 31.44 22.961 31.944 ;
     RECT  22.781 55.488 22.961 57.144 ;
     RECT  22.957 40.752 22.972 43.56 ;
     RECT  22.097 15.408 22.981 15.432 ;
     RECT  22.273 16.704 22.981 16.728 ;
     RECT  22.781 38.784 23.033 39.24 ;
     RECT  22.693 62.16 23.036 62.76 ;
     RECT  23.036 62.16 23.137 63.288 ;
     RECT  23.137 61.68 23.173 63.288 ;
     RECT  22.201 6.816 23.209 8.184 ;
     RECT  23.209 6.816 23.245 9 ;
     RECT  22.777 46.896 23.245 49.944 ;
     RECT  22.273 34.896 23.281 35.304 ;
     RECT  23.173 61.248 23.317 63.288 ;
     RECT  22.745 11.952 23.389 11.976 ;
     RECT  22.745 13.296 23.389 13.32 ;
     RECT  23.317 61.008 23.461 63.288 ;
     RECT  22.789 64.656 23.461 64.68 ;
     RECT  22.849 52.08 23.468 54.504 ;
     RECT  22.961 55.488 23.468 56.808 ;
     RECT  23.461 0.576 23.545 0.6 ;
     RECT  22.981 15.408 23.569 16.728 ;
     RECT  22.237 33.552 23.677 33.576 ;
     RECT  22.777 5.184 23.749 5.208 ;
     RECT  21.491 21.648 23.749 21.672 ;
     RECT  22.705 22.752 23.749 23.16 ;
     RECT  23.389 11.952 23.785 13.32 ;
     RECT  23.569 14.784 23.785 16.728 ;
     RECT  23.461 61.008 23.795 64.68 ;
     RECT  22.637 36.576 23.821 36.936 ;
     RECT  23.795 63.792 23.825 64.68 ;
     RECT  23.795 61.008 23.845 62.76 ;
     RECT  22.931 1.728 23.893 2.28 ;
     RECT  23.749 5.088 23.893 5.208 ;
     RECT  23.245 6.672 23.893 9 ;
     RECT  22.849 45.12 23.929 45.24 ;
     RECT  23.065 3.984 23.965 4.008 ;
     RECT  23.893 5.04 23.965 5.208 ;
     RECT  22.961 31.44 23.965 31.752 ;
     RECT  23.677 32.784 23.965 33.576 ;
     RECT  23.893 1.152 23.987 2.28 ;
     RECT  23.987 1.728 24.008 2.28 ;
     RECT  23.965 3.984 24.008 5.208 ;
     RECT  23.893 6.288 24.008 9 ;
     RECT  23.797 10.848 24.008 10.872 ;
     RECT  23.785 11.952 24.008 16.728 ;
     RECT  23.137 19.344 24.008 19.368 ;
     RECT  21.445 20.496 24.008 20.52 ;
     RECT  23.749 21.648 24.008 23.16 ;
     RECT  22.789 27.312 24.008 27.336 ;
     RECT  22.781 28.464 24.008 28.488 ;
     RECT  23.965 31.44 24.008 33.576 ;
     RECT  23.281 34.848 24.008 35.304 ;
     RECT  23.821 36.576 24.008 37.656 ;
     RECT  23.033 39.216 24.008 39.24 ;
     RECT  22.972 40.752 24.008 43.032 ;
     RECT  23.929 44.16 24.008 45.24 ;
     RECT  23.245 46.896 24.008 50.424 ;
     RECT  23.468 52.08 24.008 56.808 ;
     RECT  23.845 60.72 24.008 62.76 ;
     RECT  23.825 64.512 24.293 64.68 ;
     RECT  24.008 1.728 24.304 62.76 ;
     RECT  24.304 7.968 24.419 9 ;
     RECT  24.304 28.848 24.445 28.872 ;
     RECT  24.304 1.728 24.473 6.792 ;
     RECT  24.304 30.768 24.473 33.048 ;
     RECT  24.473 3.888 24.509 6.792 ;
     RECT  24.304 34.08 24.509 37.656 ;
     RECT  24.304 42.144 24.515 57.576 ;
     RECT  24.293 64.608 24.515 64.68 ;
     RECT  24.515 49.536 24.545 57.576 ;
     RECT  24.473 30.768 24.581 32.808 ;
     RECT  24.515 42.144 24.581 48.456 ;
     RECT  24.304 22.56 24.625 23.4 ;
     RECT  24.509 3.984 24.659 6.792 ;
     RECT  24.509 36.912 24.689 37.656 ;
     RECT  24.509 34.08 24.733 35.928 ;
     RECT  24.304 59.28 24.733 62.76 ;
     RECT  24.304 10.272 24.797 12.36 ;
     RECT  24.304 13.92 24.833 16.536 ;
     RECT  24.304 21.552 24.905 21.576 ;
     RECT  24.659 3.984 24.977 4.008 ;
     RECT  24.659 5.04 25.013 6.792 ;
     RECT  25.013 5.712 25.049 6.792 ;
     RECT  24.545 49.68 25.049 57.576 ;
     RECT  24.515 64.656 25.049 64.68 ;
     RECT  24.733 59.28 25.085 60.456 ;
     RECT  24.833 13.92 25.157 13.944 ;
     RECT  24.304 38.976 25.157 39.384 ;
     RECT  25.049 49.68 25.157 54.984 ;
     RECT  24.733 61.584 25.189 62.76 ;
     RECT  24.473 1.728 25.229 2.28 ;
     RECT  25.085 59.76 25.229 60.456 ;
     RECT  25.153 0.096 25.237 0.12 ;
     RECT  25.229 60.384 25.301 60.456 ;
     RECT  25.189 61.584 25.301 63.24 ;
     RECT  24.304 26.784 25.331 27.336 ;
     RECT  25.049 6.768 25.333 6.792 ;
     RECT  24.833 15.552 25.337 16.536 ;
     RECT  25.333 6.768 25.369 6.84 ;
     RECT  24.797 10.704 25.549 12.36 ;
     RECT  24.304 40.56 25.549 40.968 ;
     RECT  24.581 42.144 25.549 45.24 ;
     RECT  25.549 40.56 25.553 45.24 ;
     RECT  25.285 29.088 25.589 29.112 ;
     RECT  25.157 51.504 25.619 54.984 ;
     RECT  25.301 61.584 25.619 62.712 ;
     RECT  24.689 37.632 25.621 37.656 ;
     RECT  25.301 60.384 25.625 60.408 ;
     RECT  25.619 62.112 25.625 62.712 ;
     RECT  25.619 53.376 25.661 54.984 ;
     RECT  25.621 37.632 25.724 37.704 ;
     RECT  25.553 40.56 25.765 45.144 ;
     RECT  25.549 10.704 25.769 12.552 ;
     RECT  25.724 37.008 25.769 37.704 ;
     RECT  25.769 37.008 25.811 37.656 ;
     RECT  25.369 6.768 25.837 6.888 ;
     RECT  24.419 7.968 25.837 8.568 ;
     RECT  25.657 3.408 25.907 3.432 ;
     RECT  24.625 22.56 25.913 22.776 ;
     RECT  25.331 26.784 25.913 26.856 ;
     RECT  25.765 40.464 25.913 45.144 ;
     RECT  24.581 46.224 25.985 48.456 ;
     RECT  25.985 46.608 26.021 48.456 ;
     RECT  25.661 53.52 26.053 54.984 ;
     RECT  25.049 55.968 26.053 57.576 ;
     RECT  24.733 34.08 26.129 35.352 ;
     RECT  25.913 40.896 26.147 45.144 ;
     RECT  25.229 1.728 26.161 1.848 ;
     RECT  25.837 6.768 26.161 8.568 ;
     RECT  25.769 10.704 26.161 11.4 ;
     RECT  26.147 40.896 26.173 43.32 ;
     RECT  26.053 53.52 26.189 57.576 ;
     RECT  26.161 1.104 26.197 1.848 ;
     RECT  26.147 44.64 26.201 45.144 ;
     RECT  25.049 5.712 26.233 5.736 ;
     RECT  26.161 6.768 26.233 8.904 ;
     RECT  26.189 53.52 26.273 57.624 ;
     RECT  25.157 38.976 26.305 39.24 ;
     RECT  26.129 34.368 26.309 35.352 ;
     RECT  25.769 12.528 26.377 12.552 ;
     RECT  26.377 12.528 26.417 12.936 ;
     RECT  26.377 2.832 26.461 2.856 ;
     RECT  26.233 5.712 26.525 8.904 ;
     RECT  25.913 22.752 26.557 22.776 ;
     RECT  26.305 38.784 26.557 39.24 ;
     RECT  26.485 63.216 26.579 63.24 ;
     RECT  25.625 62.112 26.593 62.184 ;
     RECT  26.161 10.224 26.633 11.4 ;
     RECT  26.593 61.584 26.693 62.184 ;
     RECT  24.581 31.44 26.701 32.808 ;
     RECT  26.701 30.624 26.737 32.808 ;
     RECT  25.619 51.504 26.737 52.296 ;
     RECT  26.525 5.712 26.741 7.8 ;
     RECT  26.309 34.368 26.741 34.392 ;
     RECT  25.811 37.632 26.773 37.656 ;
     RECT  26.557 38.784 26.773 39.336 ;
     RECT  25.157 49.68 26.773 50.04 ;
     RECT  26.773 37.008 26.857 39.864 ;
     RECT  26.197 0.528 26.867 1.848 ;
     RECT  26.857 37.008 26.921 37.608 ;
     RECT  26.737 51.456 26.921 52.296 ;
     RECT  26.773 49.536 26.953 50.472 ;
     RECT  26.693 61.584 26.953 62.712 ;
     RECT  26.021 46.608 26.989 48.408 ;
     RECT  25.337 16.512 27.029 16.536 ;
     RECT  26.737 30.624 27.029 33.048 ;
     RECT  26.989 46.08 27.065 48.408 ;
     RECT  26.197 64.656 27.089 64.68 ;
     RECT  26.273 53.52 27.097 57.528 ;
     RECT  27.065 46.08 27.173 48.12 ;
     RECT  26.953 61.008 27.197 62.712 ;
     RECT  26.173 40.944 27.245 43.32 ;
     RECT  26.867 0.528 27.251 0.552 ;
     RECT  27.197 60.96 27.28 62.712 ;
     RECT  26.557 22.752 27.313 23.016 ;
     RECT  27.245 40.992 27.317 43.32 ;
     RECT  26.125 25.632 27.349 25.656 ;
     RECT  26.857 38.688 27.425 39.864 ;
     RECT  27.317 40.992 27.425 43.272 ;
     RECT  26.201 44.64 27.457 44.664 ;
     RECT  27.173 46.08 27.457 47.016 ;
     RECT  27.457 44.64 27.461 47.016 ;
     RECT  26.867 1.728 27.493 1.848 ;
     RECT  26.881 2.88 27.493 2.904 ;
     RECT  26.525 8.88 27.493 8.904 ;
     RECT  27.425 38.688 27.533 39.336 ;
     RECT  27.493 1.728 27.589 2.904 ;
     RECT  27.313 22.752 27.596 23.352 ;
     RECT  26.921 37.584 27.605 37.608 ;
     RECT  27.533 39.216 27.605 39.336 ;
     RECT  26.701 17.616 27.637 17.64 ;
     RECT  26.921 51.744 27.637 52.296 ;
     RECT  27.097 53.328 27.637 57.528 ;
     RECT  27.596 22.128 27.641 23.352 ;
     RECT  27.641 22.128 27.677 23.016 ;
     RECT  27.677 22.128 27.683 22.776 ;
     RECT  27.349 5.088 27.709 5.112 ;
     RECT  24.304 20.496 27.709 20.52 ;
     RECT  27.709 20.496 27.749 21.144 ;
     RECT  25.913 26.784 27.781 26.808 ;
     RECT  27.781 59.808 27.817 59.832 ;
     RECT  27.28 60.912 27.817 62.712 ;
     RECT  26.741 6.288 27.853 7.8 ;
     RECT  27.493 8.88 27.857 9.624 ;
     RECT  26.417 12.912 27.877 12.936 ;
     RECT  27.457 14.256 27.877 14.28 ;
     RECT  27.845 15.984 27.877 16.008 ;
     RECT  27.857 9.6 27.893 9.624 ;
     RECT  27.877 12.912 27.923 14.28 ;
     RECT  26.633 10.656 27.925 11.352 ;
     RECT  27.877 15.264 27.929 16.008 ;
     RECT  27.925 10.656 27.965 11.976 ;
     RECT  27.637 17.52 27.971 17.64 ;
     RECT  27.029 30.624 27.98 31.704 ;
     RECT  27.589 1.728 28.019 3.432 ;
     RECT  27.98 30.384 28.037 31.704 ;
     RECT  28.037 30.384 28.067 30.408 ;
     RECT  28.019 1.728 28.073 2.856 ;
     RECT  27.929 15.264 28.105 15.432 ;
     RECT  27.817 59.808 28.105 62.712 ;
     RECT  27.709 4.752 28.109 5.112 ;
     RECT  27.923 13.104 28.145 13.464 ;
     RECT  28.037 31.44 28.177 31.704 ;
     RECT  27.029 33.024 28.177 33.048 ;
     RECT  27.853 6.192 28.259 7.8 ;
     RECT  27.971 17.616 28.285 17.64 ;
     RECT  26.953 49.536 28.285 50.664 ;
     RECT  27.637 51.744 28.285 57.528 ;
     RECT  28.213 16.56 28.297 16.584 ;
     RECT  28.213 34.752 28.297 34.776 ;
     RECT  28.021 29.04 28.361 29.064 ;
     RECT  27.349 25.056 28.429 25.656 ;
     RECT  28.429 24.624 28.433 25.656 ;
     RECT  27.781 26.784 28.453 26.856 ;
     RECT  27.349 27.888 28.453 27.912 ;
     RECT  27.461 44.64 28.46 46.92 ;
     RECT  28.259 6.288 28.465 7.8 ;
     RECT  27.749 21.12 28.465 21.144 ;
     RECT  27.683 22.128 28.465 22.2 ;
     RECT  27.425 42 28.501 42.744 ;
     RECT  28.46 43.728 28.501 46.92 ;
     RECT  27.173 48.096 28.501 48.12 ;
     RECT  28.285 49.536 28.501 57.528 ;
     RECT  28.501 42 28.645 57.528 ;
     RECT  28.033 0.096 28.729 0.12 ;
     RECT  28.645 42 28.753 57.624 ;
     RECT  28.105 58.992 28.753 62.712 ;
     RECT  28.109 4.752 28.837 4.776 ;
     RECT  27.089 63.792 28.865 64.68 ;
     RECT  28.861 0.144 29.005 0.504 ;
     RECT  28.501 9.696 29.005 9.816 ;
     RECT  27.965 11.136 29.005 11.976 ;
     RECT  28.145 13.104 29.005 13.128 ;
     RECT  27.425 40.992 29.029 41.016 ;
     RECT  28.753 42 29.029 62.712 ;
     RECT  28.213 36.192 29.041 36.216 ;
     RECT  28.837 3.984 29.141 4.776 ;
     RECT  28.105 14.688 29.149 15.432 ;
     RECT  28.285 17.616 29.185 18.264 ;
     RECT  28.465 21.12 29.257 22.2 ;
     RECT  29.005 9.696 29.269 13.128 ;
     RECT  29.149 14.64 29.269 15.432 ;
     RECT  28.465 6.288 29.329 8.52 ;
     RECT  29.257 21.12 29.365 22.824 ;
     RECT  29.029 40.992 29.365 62.712 ;
     RECT  28.073 1.728 29.408 2.28 ;
     RECT  29.141 3.984 29.408 5.112 ;
     RECT  29.329 6.096 29.408 8.52 ;
     RECT  29.269 9.696 29.408 15.432 ;
     RECT  29.185 17.472 29.408 18.264 ;
     RECT  29.365 21.12 29.408 23.352 ;
     RECT  28.433 24.624 29.408 25.08 ;
     RECT  28.453 26.784 29.408 27.912 ;
     RECT  28.177 31.44 29.408 33.048 ;
     RECT  29.041 36.096 29.408 36.216 ;
     RECT  27.605 39.312 29.408 39.336 ;
     RECT  29.365 40.992 29.408 62.808 ;
     RECT  29.408 1.728 29.555 62.808 ;
     RECT  29.005 0.144 29.651 0.552 ;
     RECT  29.555 1.728 29.704 62.712 ;
     RECT  29.704 56.256 29.765 58.152 ;
     RECT  29.704 42 29.801 49.032 ;
     RECT  29.704 4.56 29.909 4.776 ;
     RECT  29.704 1.728 29.977 2.28 ;
     RECT  29.704 31.44 29.981 32.76 ;
     RECT  29.909 4.752 30.017 4.776 ;
     RECT  29.704 37.488 30.076 37.512 ;
     RECT  29.704 60.384 30.089 62.712 ;
     RECT  29.704 6.096 30.161 15.288 ;
     RECT  29.704 23.328 30.197 24.648 ;
     RECT  29.704 26.208 30.275 27.912 ;
     RECT  30.161 6.288 30.305 15.288 ;
     RECT  29.704 29.664 30.313 29.688 ;
     RECT  29.801 47.04 30.313 49.032 ;
     RECT  29.765 56.352 30.316 58.152 ;
     RECT  29.801 42 30.323 46.056 ;
     RECT  30.313 47.04 30.341 48.984 ;
     RECT  28.865 63.792 30.373 64.632 ;
     RECT  30.305 6.48 30.413 15.288 ;
     RECT  30.413 6.864 30.449 15.288 ;
     RECT  30.275 26.208 30.449 27.336 ;
     RECT  30.373 63.792 30.521 64.68 ;
     RECT  29.704 50.256 30.557 55.176 ;
     RECT  29.977 0.576 30.629 2.28 ;
     RECT  29.704 3.456 30.697 3.48 ;
     RECT  30.697 3.408 30.733 3.48 ;
     RECT  30.521 63.792 30.737 64.632 ;
     RECT  30.629 0.576 30.757 1.848 ;
     RECT  30.449 14.352 30.773 15.288 ;
     RECT  29.704 38.688 30.809 38.712 ;
     RECT  30.323 42 30.844 43.272 ;
     RECT  30.341 47.04 30.853 48.744 ;
     RECT  30.089 60.432 30.853 62.712 ;
     RECT  30.737 63.792 30.853 63.816 ;
     RECT  29.704 35.904 30.881 36.456 ;
     RECT  30.757 0.144 30.898 1.848 ;
     RECT  30.697 59.28 30.899 59.304 ;
     RECT  30.853 60.432 30.989 63.816 ;
     RECT  30.898 0.096 30.995 1.848 ;
     RECT  29.981 31.44 31.052 31.704 ;
     RECT  29.981 32.736 31.052 32.76 ;
     RECT  30.769 19.872 31.129 19.896 ;
     RECT  30.995 0.144 31.139 0.168 ;
     RECT  31.052 31.44 31.139 32.76 ;
     RECT  29.704 21.12 31.169 22.056 ;
     RECT  31.129 19.248 31.201 19.896 ;
     RECT  30.449 6.864 31.205 13.128 ;
     RECT  30.989 63.792 31.241 63.816 ;
     RECT  31.169 21.12 31.309 21.672 ;
     RECT  31.201 18.768 31.331 19.896 ;
     RECT  31.139 32.736 31.333 32.76 ;
     RECT  30.197 23.328 31.373 23.88 ;
     RECT  30.557 50.448 31.373 55.176 ;
     RECT  30.316 56.352 31.373 57.576 ;
     RECT  31.333 32.736 31.379 32.904 ;
     RECT  30.449 26.832 31.417 27.336 ;
     RECT  31.379 32.88 31.421 32.904 ;
     RECT  30.989 60.432 31.429 62.712 ;
     RECT  30.733 2.832 31.457 3.48 ;
     RECT  31.373 50.448 31.529 57.576 ;
     RECT  31.529 51.36 31.565 57.576 ;
     RECT  31.565 55.824 31.571 57.576 ;
     RECT  31.571 56.976 31.573 57.576 ;
     RECT  31.237 58.656 31.573 58.68 ;
     RECT  31.331 19.248 31.637 19.896 ;
     RECT  31.139 31.44 31.637 31.704 ;
     RECT  30.881 35.904 31.676 36.024 ;
     RECT  31.429 60.384 31.705 62.712 ;
     RECT  31.573 56.976 31.709 58.68 ;
     RECT  30.995 1.2 31.741 1.848 ;
     RECT  31.457 2.832 31.741 3.432 ;
     RECT  31.676 35.856 31.745 36.024 ;
     RECT  31.709 57.456 31.745 58.68 ;
     RECT  31.745 35.856 31.763 35.88 ;
     RECT  30.853 47.04 31.763 48.264 ;
     RECT  31.205 6.864 31.777 8.52 ;
     RECT  30.323 44.592 31.817 46.056 ;
     RECT  31.745 57.456 31.817 57.576 ;
     RECT  30.773 14.352 31.885 15.192 ;
     RECT  31.777 6.24 31.907 8.52 ;
     RECT  31.741 1.2 31.961 3.432 ;
     RECT  31.961 1.2 31.997 2.904 ;
     RECT  31.705 59.808 32.005 62.712 ;
     RECT  31.165 34.752 32.033 34.776 ;
     RECT  31.637 31.44 32.065 31.464 ;
     RECT  31.907 6.24 32.101 6.264 ;
     RECT  31.309 20.928 32.149 21.672 ;
     RECT  31.637 19.248 32.177 19.512 ;
     RECT  31.373 23.328 32.209 24.552 ;
     RECT  31.205 9.792 32.245 13.128 ;
     RECT  31.885 14.256 32.245 15.192 ;
     RECT  32.149 20.928 32.245 22.248 ;
     RECT  32.209 23.28 32.245 24.552 ;
     RECT  31.817 45.984 32.245 46.056 ;
     RECT  31.763 47.04 32.245 47.208 ;
     RECT  32.065 30.72 32.291 31.464 ;
     RECT  32.005 59.808 32.293 63.24 ;
     RECT  31.909 64.656 32.293 64.68 ;
     RECT  32.245 9.792 32.339 15.192 ;
     RECT  31.745 58.608 32.353 58.68 ;
     RECT  32.293 59.808 32.353 64.68 ;
     RECT  31.907 7.344 32.389 8.52 ;
     RECT  32.245 20.928 32.389 24.552 ;
     RECT  30.844 42 32.389 42.168 ;
     RECT  30.844 43.248 32.389 43.272 ;
     RECT  32.101 6.048 32.425 6.264 ;
     RECT  32.389 42 32.429 43.272 ;
     RECT  32.339 10.56 32.461 15.192 ;
     RECT  32.437 28.896 32.461 28.92 ;
     RECT  32.353 58.608 32.483 64.68 ;
     RECT  32.461 28.896 32.524 29.112 ;
     RECT  32.461 10.56 32.533 15.816 ;
     RECT  32.209 50.16 32.569 50.184 ;
     RECT  31.565 51.36 32.569 54.696 ;
     RECT  31.763 48.24 32.605 48.264 ;
     RECT  32.533 10.56 32.609 16.008 ;
     RECT  31.817 44.592 32.609 44.904 ;
     RECT  32.569 50.16 32.609 54.696 ;
     RECT  32.483 59.808 32.617 64.68 ;
     RECT  29.704 17.088 32.641 17.64 ;
     RECT  32.429 42 32.641 42.792 ;
     RECT  32.483 58.608 32.642 58.68 ;
     RECT  31.997 1.728 32.653 2.904 ;
     RECT  32.641 17.088 32.681 17.688 ;
     RECT  32.389 20.928 32.681 25.128 ;
     RECT  32.425 5.136 32.713 6.264 ;
     RECT  32.177 19.248 32.857 19.368 ;
     RECT  32.617 59.808 32.861 59.88 ;
     RECT  31.417 26.832 32.893 27.864 ;
     RECT  32.617 61.008 32.915 64.68 ;
     RECT  31.237 38.736 32.917 38.76 ;
     RECT  31.717 40.224 32.917 40.248 ;
     RECT  32.653 1.728 32.941 2.856 ;
     RECT  32.917 38.736 32.963 40.248 ;
     RECT  32.605 48.24 32.965 48.936 ;
     RECT  31.571 55.824 32.969 55.848 ;
     RECT  32.609 50.688 33.037 54.696 ;
     RECT  32.821 0.528 33.107 0.552 ;
     RECT  32.245 45.984 33.109 47.208 ;
     RECT  32.965 48.24 33.109 49.608 ;
     RECT  32.389 7.344 33.113 9.288 ;
     RECT  32.857 18.912 33.181 19.368 ;
     RECT  32.963 39.36 33.185 40.248 ;
     RECT  32.681 20.928 33.221 24.504 ;
     RECT  32.713 4.56 33.257 6.264 ;
     RECT  32.641 41.616 33.257 42.792 ;
     RECT  33.257 4.56 33.299 5.688 ;
     RECT  32.609 10.56 33.325 14.76 ;
     RECT  32.893 26.448 33.325 27.864 ;
     RECT  33.257 41.616 33.347 42.456 ;
     RECT  32.681 17.376 33.356 17.688 ;
     RECT  33.181 18.912 33.356 19.656 ;
     RECT  33.325 26.256 33.365 27.864 ;
     RECT  33.109 45.984 33.395 49.608 ;
     RECT  31.817 57.456 33.397 57.48 ;
     RECT  33.356 17.376 33.443 19.656 ;
     RECT  32.524 29.088 33.493 29.112 ;
     RECT  32.291 30.72 33.493 30.744 ;
     RECT  32.609 44.592 33.505 44.616 ;
     RECT  33.493 29.088 33.539 30.744 ;
     RECT  33.395 45.984 33.545 49.368 ;
     RECT  33.397 57.456 33.577 57.576 ;
     RECT  33.539 29.088 33.581 29.928 ;
     RECT  32.642 58.656 33.589 58.68 ;
     RECT  33.325 10.176 33.653 14.76 ;
     RECT  32.965 35.328 33.653 35.928 ;
     RECT  33.037 50.688 33.653 55.08 ;
     RECT  32.915 63.216 33.689 64.68 ;
     RECT  33.113 7.344 33.721 8.904 ;
     RECT  32.609 15.744 33.721 16.008 ;
     RECT  32.497 33.024 33.757 33.048 ;
     RECT  33.577 56.976 33.757 57.576 ;
     RECT  33.347 41.616 33.761 41.64 ;
     RECT  33.653 10.56 33.797 14.76 ;
     RECT  33.757 32.304 33.797 33.048 ;
     RECT  33.721 15.744 33.829 16.056 ;
     RECT  33.443 17.376 33.829 17.688 ;
     RECT  33.797 10.704 33.973 14.76 ;
     RECT  33.829 15.744 33.973 17.688 ;
     RECT  33.443 18.816 33.973 19.656 ;
     RECT  33.365 26.256 33.973 26.808 ;
     RECT  33.757 56.784 33.973 57.576 ;
     RECT  33.365 27.84 34.021 27.864 ;
     RECT  33.581 29.088 34.021 29.4 ;
     RECT  33.973 56.352 34.021 57.576 ;
     RECT  33.589 58.656 34.021 59.208 ;
     RECT  32.915 61.008 34.045 62.184 ;
     RECT  33.221 21.264 34.117 24.504 ;
     RECT  33.505 43.824 34.117 44.616 ;
     RECT  33.545 45.984 34.117 48.264 ;
     RECT  34.045 61.008 34.117 62.232 ;
     RECT  33.689 63.216 34.117 63.816 ;
     RECT  33.653 51.216 34.165 55.08 ;
     RECT  34.021 56.352 34.165 59.208 ;
     RECT  33.185 40.224 34.189 40.248 ;
     RECT  34.117 61.008 34.193 63.816 ;
     RECT  33.299 5.136 34.225 5.688 ;
     RECT  33.721 6.816 34.225 8.904 ;
     RECT  34.193 61.008 34.309 63.24 ;
     RECT  31.345 37.2 34.357 37.224 ;
     RECT  32.941 1.728 34.433 2.28 ;
     RECT  34.225 5.136 34.441 8.904 ;
     RECT  34.117 43.824 34.501 48.264 ;
     RECT  34.357 37.2 34.549 37.656 ;
     RECT  34.549 36.432 34.585 37.656 ;
     RECT  34.189 39.312 34.585 40.248 ;
     RECT  34.268 41.28 34.585 41.304 ;
     RECT  34.165 51.216 34.597 59.208 ;
     RECT  34.441 5.04 34.621 8.904 ;
     RECT  33.973 10.704 34.621 17.688 ;
     RECT  33.973 18.816 34.621 19.8 ;
     RECT  34.117 21.264 34.652 25.032 ;
     RECT  33.973 26.208 34.652 26.808 ;
     RECT  34.585 36.432 34.685 38.184 ;
     RECT  34.585 39.312 34.685 41.304 ;
     RECT  34.433 1.728 34.693 2.856 ;
     RECT  33.541 3.936 34.693 3.96 ;
     RECT  34.501 43.296 34.693 48.264 ;
     RECT  33.545 49.344 34.693 49.368 ;
     RECT  34.309 60.432 34.729 63.24 ;
     RECT  33.577 31.248 34.765 31.272 ;
     RECT  34.685 36.432 34.801 41.304 ;
     RECT  34.693 42.48 34.801 49.368 ;
     RECT  34.693 1.728 34.808 3.96 ;
     RECT  34.621 5.04 34.808 9.624 ;
     RECT  34.621 10.704 34.808 19.8 ;
     RECT  34.652 21.264 34.808 26.808 ;
     RECT  34.021 27.84 34.808 29.4 ;
     RECT  34.765 30.864 34.808 31.272 ;
     RECT  33.797 32.304 34.808 32.328 ;
     RECT  34.657 34.176 34.808 34.2 ;
     RECT  33.653 35.328 34.808 35.352 ;
     RECT  34.801 36.432 34.808 49.368 ;
     RECT  34.597 51.216 34.808 59.304 ;
     RECT  34.729 60.336 34.808 63.24 ;
     RECT  34.808 1.728 35.104 63.24 ;
     RECT  33.649 0.576 35.165 0.6 ;
     RECT  35.104 8.016 35.165 8.04 ;
     RECT  35.104 41.664 35.173 63.24 ;
     RECT  35.173 41.664 35.201 63.288 ;
     RECT  35.104 39.168 35.219 39.768 ;
     RECT  35.201 41.664 35.219 55.272 ;
     RECT  35.104 17.088 35.237 22.536 ;
     RECT  35.201 56.496 35.267 63.288 ;
     RECT  34.789 64.56 35.269 64.68 ;
     RECT  35.104 1.728 35.315 6.792 ;
     RECT  35.267 56.496 35.315 57.672 ;
     RECT  35.219 39.168 35.345 39.336 ;
     RECT  35.315 1.728 35.365 2.904 ;
     RECT  35.237 17.472 35.381 22.536 ;
     RECT  35.219 42.48 35.381 55.272 ;
     RECT  35.267 58.944 35.381 63.288 ;
     RECT  35.104 10.224 35.417 15.768 ;
     RECT  35.104 24.096 35.453 25.128 ;
     RECT  35.104 26.544 35.489 30.888 ;
     RECT  35.381 51.792 35.561 55.272 ;
     RECT  35.381 59.232 35.651 63.288 ;
     RECT  35.365 1.68 35.699 2.904 ;
     RECT  35.417 10.224 35.699 12.216 ;
     RECT  35.381 42.48 35.705 50.28 ;
     RECT  35.453 24.144 35.777 25.128 ;
     RECT  35.315 4.224 35.813 6.792 ;
     RECT  35.777 24.144 35.813 24.456 ;
     RECT  35.813 4.224 35.891 4.248 ;
     RECT  35.705 42.48 35.921 47.736 ;
     RECT  35.417 13.296 35.957 15.768 ;
     RECT  35.921 42.48 35.993 47.304 ;
     RECT  35.699 2.88 36.083 2.904 ;
     RECT  35.651 60.864 36.092 63.288 ;
     RECT  35.269 64.464 36.092 64.68 ;
     RECT  35.699 1.68 36.133 1.8 ;
     RECT  35.489 26.544 36.169 27.096 ;
     RECT  35.489 28.272 36.173 30.888 ;
     RECT  35.561 51.792 36.173 54.744 ;
     RECT  35.315 57.456 36.277 57.672 ;
     RECT  35.381 17.856 36.281 22.536 ;
     RECT  36.169 26.208 36.349 27.096 ;
     RECT  35.104 31.872 36.349 32.232 ;
     RECT  35.993 46.848 36.353 47.304 ;
     RECT  35.651 59.232 36.421 59.88 ;
     RECT  36.281 19.968 36.533 22.536 ;
     RECT  36.277 56.448 36.557 57.672 ;
     RECT  36.133 1.632 36.563 1.8 ;
     RECT  35.813 5.712 36.565 6.792 ;
     RECT  36.349 31.872 36.565 32.664 ;
     RECT  35.104 34.176 36.565 34.2 ;
     RECT  35.957 13.536 36.569 15.768 ;
     RECT  36.565 31.872 36.569 34.2 ;
     RECT  35.993 42.48 36.569 45.432 ;
     RECT  36.173 51.84 36.601 54.744 ;
     RECT  36.281 17.856 36.605 18.888 ;
     RECT  36.421 59.184 36.611 59.88 ;
     RECT  36.569 32.208 36.637 34.2 ;
     RECT  36.611 59.184 36.641 59.208 ;
     RECT  36.601 51.84 36.668 55.08 ;
     RECT  36.557 56.448 36.668 58.152 ;
     RECT  36.173 28.272 36.677 30.168 ;
     RECT  35.705 48.912 36.677 50.28 ;
     RECT  36.457 4.032 36.701 4.056 ;
     RECT  36.533 20.448 36.709 22.536 ;
     RECT  36.677 30 36.713 30.168 ;
     RECT  36.569 13.776 36.781 15.768 ;
     RECT  35.699 10.224 36.785 11.688 ;
     RECT  36.677 28.272 36.785 28.536 ;
     RECT  36.713 30.144 36.785 30.168 ;
     RECT  35.813 24.144 36.817 24.168 ;
     RECT  36.668 51.84 36.821 58.152 ;
     RECT  36.701 3.984 36.851 4.056 ;
     RECT  36.821 56.448 36.853 58.152 ;
     RECT  36.563 1.728 36.889 1.8 ;
     RECT  36.605 17.856 36.929 18.84 ;
     RECT  36.092 60.864 36.956 64.68 ;
     RECT  36.569 42.48 36.965 45.048 ;
     RECT  36.956 60.192 36.965 64.68 ;
     RECT  36.565 5.712 36.997 6.984 ;
     RECT  36.457 7.968 37.001 7.992 ;
     RECT  36.349 25.92 37.033 27.096 ;
     RECT  36.677 49.536 37.069 50.28 ;
     RECT  36.853 56.448 37.109 58.68 ;
     RECT  36.997 4.992 37.181 6.984 ;
     RECT  36.785 28.512 37.217 28.536 ;
     RECT  36.889 1.728 37.235 2.28 ;
     RECT  36.637 32.208 37.285 34.92 ;
     RECT  36.637 37.584 37.285 37.608 ;
     RECT  35.345 39.168 37.285 39.192 ;
     RECT  36.817 23.856 37.321 24.168 ;
     RECT  37.033 25.296 37.321 27.096 ;
     RECT  36.965 42.48 37.321 43.032 ;
     RECT  36.965 60.192 37.325 63.864 ;
     RECT  37.285 37.584 37.331 39.192 ;
     RECT  37.331 38.544 37.333 39.192 ;
     RECT  36.821 51.84 37.34 55.08 ;
     RECT  37.333 38.544 37.372 39.336 ;
     RECT  37.321 42.192 37.405 43.032 ;
     RECT  37.372 39.312 37.42 39.336 ;
     RECT  37.34 51.792 37.427 55.08 ;
     RECT  36.781 13.776 37.465 16.536 ;
     RECT  36.709 20.448 37.465 22.824 ;
     RECT  37.321 23.856 37.465 27.096 ;
     RECT  37.325 60.912 37.468 63.864 ;
     RECT  37.109 56.496 37.513 58.68 ;
     RECT  37.235 1.728 37.609 1.896 ;
     RECT  36.851 3.984 37.619 4.008 ;
     RECT  36.965 44.016 37.619 45.048 ;
     RECT  37.465 13.776 37.649 17.112 ;
     RECT  37.405 42.72 37.657 43.032 ;
     RECT  37.285 32.208 37.667 35.352 ;
     RECT  36.353 47.28 37.667 47.304 ;
     RECT  37.468 60.912 37.685 62.664 ;
     RECT  37.621 46.08 37.708 46.104 ;
     RECT  37.609 1.68 37.715 1.896 ;
     RECT  37.685 61.008 37.715 62.664 ;
     RECT  36.853 40.464 37.717 40.488 ;
     RECT  37.513 58.656 37.724 58.68 ;
     RECT  36.785 10.224 37.753 11.448 ;
     RECT  37.213 12.528 37.753 12.552 ;
     RECT  37.753 10.224 37.757 12.552 ;
     RECT  37.427 52.416 37.763 55.08 ;
     RECT  37.717 39.888 37.829 40.488 ;
     RECT  37.573 59.856 37.829 59.88 ;
     RECT  37.181 5.472 37.897 6.984 ;
     RECT  37.465 20.448 37.933 27.096 ;
     RECT  37.861 46.752 37.945 46.776 ;
     RECT  36.929 18.672 37.957 18.792 ;
     RECT  37.715 1.728 38.003 1.896 ;
     RECT  37.715 61.584 38.051 62.664 ;
     RECT  38.003 1.728 38.099 1.848 ;
     RECT  37.069 49.536 38.149 50.712 ;
     RECT  37.933 20.448 38.153 27.384 ;
     RECT  37.649 13.824 38.197 17.112 ;
     RECT  37.957 18.144 38.197 18.792 ;
     RECT  37.757 10.848 38.221 12.552 ;
     RECT  37.667 34.896 38.333 35.352 ;
     RECT  37.829 39.888 38.333 39.96 ;
     RECT  37.513 56.496 38.339 57.672 ;
     RECT  37.724 58.656 38.341 58.728 ;
     RECT  38.221 10.848 38.369 12.744 ;
     RECT  38.153 20.448 38.405 22.824 ;
     RECT  37.763 52.416 38.405 54.744 ;
     RECT  37.897 5.472 38.437 7.368 ;
     RECT  38.405 20.448 38.437 21.288 ;
     RECT  37.468 63.792 38.437 63.864 ;
     RECT  38.197 13.824 38.441 18.792 ;
     RECT  37.657 43.008 38.473 43.032 ;
     RECT  37.619 44.016 38.473 44.232 ;
     RECT  38.369 10.848 38.549 12.552 ;
     RECT  38.441 13.92 38.581 18.792 ;
     RECT  38.437 20.352 38.581 21.288 ;
     RECT  37.667 32.208 38.585 33.72 ;
     RECT  38.051 62.16 38.588 62.664 ;
     RECT  38.437 63.792 38.588 64.68 ;
     RECT  38.585 32.208 38.621 32.664 ;
     RECT  38.621 32.208 38.657 32.472 ;
     RECT  38.437 5.472 38.689 7.896 ;
     RECT  38.588 62.16 38.693 64.68 ;
     RECT  38.405 52.464 38.761 54.744 ;
     RECT  38.329 37.056 38.773 37.08 ;
     RECT  37.537 30.864 38.797 30.888 ;
     RECT  38.341 58.656 38.797 59.592 ;
     RECT  38.677 61.056 38.797 61.08 ;
     RECT  38.153 24.336 38.801 27.384 ;
     RECT  38.333 39.936 38.801 39.96 ;
     RECT  38.581 13.92 38.819 21.288 ;
     RECT  38.773 36.24 38.819 37.08 ;
     RECT  38.819 13.92 38.86 19.272 ;
     RECT  38.819 36.24 38.86 36.264 ;
     RECT  38.333 34.896 38.865 35.16 ;
     RECT  38.339 56.688 38.869 57.672 ;
     RECT  38.797 58.656 38.869 61.08 ;
     RECT  38.149 9.84 38.873 9.864 ;
     RECT  38.585 33.696 38.873 33.72 ;
     RECT  38.797 30.048 38.909 30.888 ;
     RECT  38.801 26.064 38.941 27.384 ;
     RECT  38.819 20.352 38.945 21.288 ;
     RECT  38.801 24.336 39.089 24.696 ;
     RECT  38.099 1.728 39.164 1.8 ;
     RECT  38.549 10.848 39.197 12.504 ;
     RECT  38.869 56.688 39.205 61.08 ;
     RECT  38.653 38.4 39.337 38.424 ;
     RECT  39.337 38.16 39.349 38.424 ;
     RECT  38.365 41.664 39.356 41.688 ;
     RECT  38.473 43.008 39.356 44.232 ;
     RECT  39.205 56.688 39.373 61.128 ;
     RECT  38.693 62.16 39.373 63.24 ;
     RECT  39.356 41.664 39.397 44.232 ;
     RECT  39.164 1.728 39.481 2.28 ;
     RECT  38.941 26.064 39.589 27.48 ;
     RECT  37.717 29.04 39.589 29.064 ;
     RECT  39.089 24.336 39.661 24.648 ;
     RECT  38.149 49.536 39.692 51.432 ;
     RECT  38.761 52.464 39.692 55.32 ;
     RECT  39.661 24.192 39.733 24.648 ;
     RECT  38.86 13.92 39.836 18.792 ;
     RECT  39.769 48.096 39.877 48.12 ;
     RECT  39.373 56.688 39.877 63.24 ;
     RECT  38.693 64.512 39.877 64.68 ;
     RECT  38.657 32.448 39.884 32.472 ;
     RECT  38.909 30.048 39.925 30.072 ;
     RECT  39.869 0.576 39.953 0.6 ;
     RECT  38.865 34.896 40.021 35.112 ;
     RECT  39.884 32.448 40.057 32.952 ;
     RECT  39.877 36.336 40.069 36.36 ;
     RECT  39.877 56.352 40.097 64.68 ;
     RECT  39.481 1.728 40.208 2.904 ;
     RECT  40.021 3.984 40.208 4.008 ;
     RECT  38.689 5.472 40.208 8.472 ;
     RECT  39.197 10.848 40.208 11.976 ;
     RECT  39.836 13.008 40.208 18.792 ;
     RECT  38.945 20.448 40.208 21.288 ;
     RECT  38.405 22.512 40.208 22.824 ;
     RECT  39.733 23.856 40.208 24.648 ;
     RECT  39.589 26.064 40.208 29.064 ;
     RECT  39.925 30.048 40.208 30.6 ;
     RECT  40.057 32.448 40.208 33.048 ;
     RECT  40.021 34.656 40.208 35.112 ;
     RECT  40.069 36.336 40.208 36.552 ;
     RECT  39.349 38.16 40.208 39.432 ;
     RECT  39.397 41.664 40.208 45.048 ;
     RECT  39.877 47.136 40.208 48.504 ;
     RECT  39.692 49.536 40.208 55.32 ;
     RECT  40.097 56.352 40.208 63.24 ;
     RECT  40.208 1.728 40.504 63.24 ;
     RECT  40.504 50.256 40.643 55.752 ;
     RECT  40.504 1.728 40.691 3.048 ;
     RECT  40.021 0.144 40.741 0.408 ;
     RECT  40.504 13.248 40.745 18.264 ;
     RECT  40.643 50.256 40.745 53.592 ;
     RECT  40.643 54.672 40.745 55.752 ;
     RECT  40.741 0.096 40.825 0.408 ;
     RECT  40.745 51.264 40.889 53.592 ;
     RECT  40.504 46.704 40.961 46.728 ;
     RECT  40.889 51.264 41.068 51.288 ;
     RECT  40.745 13.248 41.069 16.44 ;
     RECT  40.691 1.728 41.075 2.856 ;
     RECT  40.504 42.144 41.075 45.384 ;
     RECT  40.504 56.976 41.123 57.624 ;
     RECT  40.504 61.008 41.125 63.24 ;
     RECT  40.097 64.416 41.125 64.68 ;
     RECT  40.504 34.656 41.141 34.68 ;
     RECT  41.075 42.144 41.141 43.128 ;
     RECT  41.141 42.144 41.213 43.032 ;
     RECT  40.504 59.808 41.249 59.832 ;
     RECT  40.504 29.088 41.315 30.6 ;
     RECT  40.504 10.8 41.321 11.976 ;
     RECT  40.745 17.664 41.393 18.264 ;
     RECT  41.125 61.008 41.465 64.68 ;
     RECT  40.504 9.696 41.497 9.72 ;
     RECT  40.504 20.544 41.497 21.192 ;
     RECT  40.504 22.176 41.497 24.792 ;
     RECT  41.321 10.8 41.5 11.4 ;
     RECT  40.504 36.336 41.501 36.552 ;
     RECT  41.465 63.264 41.555 64.68 ;
     RECT  41.497 20.544 41.557 25.032 ;
     RECT  41.069 13.248 41.573 13.272 ;
     RECT  41.557 20.544 41.573 25.08 ;
     RECT  40.504 26.064 41.573 26.856 ;
     RECT  40.889 52.368 41.605 53.592 ;
     RECT  40.745 54.672 41.605 54.696 ;
     RECT  41.497 9.696 41.645 9.816 ;
     RECT  40.745 50.256 41.645 50.28 ;
     RECT  41.075 44.4 41.651 45.384 ;
     RECT  40.504 5.328 41.677 8.328 ;
     RECT  41.645 9.792 41.677 9.816 ;
     RECT  41.605 0.576 41.689 0.6 ;
     RECT  41.123 56.976 41.689 57.048 ;
     RECT  41.069 14.448 41.789 16.44 ;
     RECT  40.745 55.728 41.821 55.752 ;
     RECT  41.677 5.28 41.857 8.328 ;
     RECT  40.504 31.728 41.857 33.048 ;
     RECT  41.789 14.448 41.861 16.104 ;
     RECT  40.504 39.216 41.861 39.24 ;
     RECT  41.213 42.96 41.897 43.032 ;
     RECT  41.857 5.28 41.969 8.664 ;
     RECT  41.555 63.648 41.969 64.68 ;
     RECT  41.605 52.368 41.989 54.696 ;
     RECT  41.821 55.728 41.989 56.472 ;
     RECT  41.315 29.088 42.001 30.216 ;
     RECT  41.969 5.28 42.005 6.984 ;
     RECT  41.075 1.728 42.035 2.28 ;
     RECT  41.857 31.44 42.073 33.048 ;
     RECT  42.035 1.728 42.077 1.848 ;
     RECT  42.077 1.824 42.131 1.848 ;
     RECT  41.573 21.168 42.181 25.08 ;
     RECT  41.573 26.064 42.181 26.568 ;
     RECT  41.989 52.368 42.181 56.472 ;
     RECT  42.073 31.44 42.217 33.096 ;
     RECT  42.217 31.44 42.293 33.144 ;
     RECT  41.821 40.272 42.325 40.296 ;
     RECT  42.181 21.168 42.329 26.568 ;
     RECT  41.969 8.016 42.437 8.664 ;
     RECT  40.504 58.704 42.556 58.728 ;
     RECT  41.465 61.008 42.565 62.184 ;
     RECT  41.713 12.528 42.577 12.552 ;
     RECT  42.001 28.848 42.581 30.216 ;
     RECT  42.329 21.168 42.617 25.032 ;
     RECT  42.181 52.32 42.653 56.472 ;
     RECT  42.565 61.008 42.677 62.28 ;
     RECT  42.469 34.752 42.721 34.776 ;
     RECT  42.617 21.168 42.757 23.352 ;
     RECT  42.581 28.848 42.757 29.784 ;
     RECT  42.721 34.752 42.757 35.304 ;
     RECT  42.677 60.384 42.757 62.28 ;
     RECT  42.757 60.384 42.761 62.664 ;
     RECT  42.757 28.416 42.797 29.784 ;
     RECT  42.757 20.976 42.803 23.352 ;
     RECT  42.797 28.416 42.803 29.4 ;
     RECT  42.437 8.016 42.833 8.616 ;
     RECT  41.651 44.4 42.833 44.424 ;
     RECT  41.5 10.896 42.865 11.4 ;
     RECT  42.577 12.528 42.865 12.936 ;
     RECT  42.329 26.304 42.865 26.568 ;
     RECT  42.653 52.32 42.869 55.272 ;
     RECT  42.869 52.32 42.899 54.072 ;
     RECT  42.293 31.44 42.937 31.944 ;
     RECT  42.757 34.128 42.941 35.4 ;
     RECT  41.501 36.432 42.941 36.552 ;
     RECT  42.761 61.008 42.949 62.664 ;
     RECT  41.969 63.792 42.949 64.68 ;
     RECT  42.865 26.304 42.973 26.76 ;
     RECT  42.937 31.392 42.973 31.944 ;
     RECT  42.617 24.528 42.977 25.032 ;
     RECT  42.941 34.128 42.977 34.872 ;
     RECT  42.869 55.056 42.995 55.272 ;
     RECT  42.899 52.32 43.037 53.016 ;
     RECT  41.677 9.792 43.045 9.912 ;
     RECT  42.865 10.896 43.045 12.936 ;
     RECT  42.005 5.28 43.073 6.696 ;
     RECT  42.361 48.432 43.081 48.456 ;
     RECT  42.803 20.976 43.085 21 ;
     RECT  42.995 55.248 43.085 55.272 ;
     RECT  43.073 5.088 43.117 6.696 ;
     RECT  42.325 39.6 43.117 40.296 ;
     RECT  41.677 41.904 43.117 41.928 ;
     RECT  43.037 51.84 43.121 53.016 ;
     RECT  43.117 5.088 43.157 6.936 ;
     RECT  41.861 14.928 43.189 16.104 ;
     RECT  42.803 22.176 43.193 23.352 ;
     RECT  42.949 61.008 43.193 64.68 ;
     RECT  43.045 9.792 43.225 12.936 ;
     RECT  43.157 5.76 43.229 6.936 ;
     RECT  43.225 9.744 43.229 12.936 ;
     RECT  42.803 28.416 43.229 29.112 ;
     RECT  43.229 5.76 43.265 6.792 ;
     RECT  42.973 26.304 43.337 26.856 ;
     RECT  43.229 10.752 43.373 12.936 ;
     RECT  42.973 30.96 43.373 31.944 ;
     RECT  43.229 9.744 43.445 9.768 ;
     RECT  42.293 33.072 43.477 33.144 ;
     RECT  42.977 34.128 43.477 34.152 ;
     RECT  43.081 58.8 43.481 58.824 ;
     RECT  43.117 39.6 43.513 41.928 ;
     RECT  41.897 43.008 43.513 43.032 ;
     RECT  42.653 56.4 43.523 56.472 ;
     RECT  43.373 30.96 43.553 31.416 ;
     RECT  43.477 33.072 43.553 34.152 ;
     RECT  43.513 39.6 43.553 43.032 ;
     RECT  43.193 61.056 43.571 64.68 ;
     RECT  43.121 52.464 43.597 53.016 ;
     RECT  43.189 14.112 43.621 16.104 ;
     RECT  43.553 39.6 43.657 40.296 ;
     RECT  43.081 47.904 43.661 48.456 ;
     RECT  43.373 11.184 43.697 12.936 ;
     RECT  43.571 61.536 43.697 64.68 ;
     RECT  43.621 14.016 43.729 16.104 ;
     RECT  43.597 52.464 43.763 52.92 ;
     RECT  43.337 26.304 43.765 26.76 ;
     RECT  40.504 37.632 43.805 37.656 ;
     RECT  43.229 29.088 43.873 29.112 ;
     RECT  43.553 41.712 43.873 43.032 ;
     RECT  42.977 24.768 43.909 25.032 ;
     RECT  43.765 26.256 43.909 26.76 ;
     RECT  43.697 11.184 43.913 11.352 ;
     RECT  43.553 33.12 43.913 34.152 ;
     RECT  43.523 56.448 43.913 56.472 ;
     RECT  43.189 35.904 43.949 35.928 ;
     RECT  43.913 33.6 44.089 34.152 ;
     RECT  43.553 31.152 44.201 31.416 ;
     RECT  44.117 52.416 44.201 52.44 ;
     RECT  42.899 54.048 44.233 54.072 ;
     RECT  43.909 24.768 44.237 26.76 ;
     RECT  43.265 5.856 44.293 6.792 ;
     RECT  44.233 54.048 44.3 54.12 ;
     RECT  44.269 10.032 44.341 10.056 ;
     RECT  43.913 11.184 44.341 11.256 ;
     RECT  44.3 54.048 44.376 54.648 ;
     RECT  43.193 22.512 44.377 23.352 ;
     RECT  44.293 5.616 44.38 6.792 ;
     RECT  42.833 8.16 44.381 8.616 ;
     RECT  44.305 60.432 44.389 60.456 ;
     RECT  44.237 25.488 44.413 26.76 ;
     RECT  43.697 12.912 44.417 12.936 ;
     RECT  43.873 29.088 44.449 29.592 ;
     RECT  44.341 10.032 44.453 11.256 ;
     RECT  43.697 61.536 44.453 62.664 ;
     RECT  44.453 62.16 44.476 62.664 ;
     RECT  43.009 19.968 44.485 19.992 ;
     RECT  44.38 5.952 44.489 6.792 ;
     RECT  44.381 8.16 44.489 8.472 ;
     RECT  44.449 29.088 44.489 29.64 ;
     RECT  44.201 31.392 44.489 31.416 ;
     RECT  44.485 19.344 44.521 20.808 ;
     RECT  44.453 10.032 44.525 10.056 ;
     RECT  43.657 39.312 44.561 40.296 ;
     RECT  43.873 41.712 44.561 43.944 ;
     RECT  43.729 14.016 44.593 16.536 ;
     RECT  41.393 17.664 44.593 18.168 ;
     RECT  44.376 54.048 44.597 54.888 ;
     RECT  43.697 63.792 44.597 64.68 ;
     RECT  44.476 62.448 44.677 62.664 ;
     RECT  44.377 22.512 44.701 23.592 ;
     RECT  44.593 14.016 44.725 18.168 ;
     RECT  44.561 41.712 44.737 41.736 ;
     RECT  44.597 54.048 44.737 54.072 ;
     RECT  44.305 36.48 44.773 36.504 ;
     RECT  44.521 19.344 44.809 21.48 ;
     RECT  44.701 22.512 44.809 23.88 ;
     RECT  44.089 33.6 44.845 34.68 ;
     RECT  44.725 13.872 44.881 18.168 ;
     RECT  44.809 19.344 44.881 23.88 ;
     RECT  44.845 33.6 44.881 34.728 ;
     RECT  44.597 64.656 44.921 64.68 ;
     RECT  44.677 62.448 44.993 62.76 ;
     RECT  44.413 25.488 45.097 26.904 ;
     RECT  44.489 6 45.277 6.792 ;
     RECT  44.489 8.16 45.277 8.184 ;
     RECT  44.881 13.872 45.301 23.88 ;
     RECT  45.097 25.488 45.301 27.096 ;
     RECT  44.809 31.824 45.385 31.848 ;
     RECT  44.881 33.6 45.385 34.92 ;
     RECT  44.684 12.768 45.529 12.792 ;
     RECT  45.301 13.872 45.529 27.096 ;
     RECT  45.277 6 45.608 8.184 ;
     RECT  44.453 11.232 45.608 11.256 ;
     RECT  45.529 12.768 45.608 27.096 ;
     RECT  44.489 29.52 45.608 29.64 ;
     RECT  45.169 30.672 45.608 30.696 ;
     RECT  45.385 31.824 45.608 35.016 ;
     RECT  44.773 36.48 45.608 36.84 ;
     RECT  44.737 38.736 45.608 38.76 ;
     RECT  44.561 40.272 45.608 40.296 ;
     RECT  44.737 41.424 45.608 41.736 ;
     RECT  44.561 42.72 45.608 43.944 ;
     RECT  42.469 49.488 45.608 49.512 ;
     RECT  44.737 53.568 45.608 54.072 ;
     RECT  44.993 62.448 45.608 62.652 ;
     RECT  45.608 2.148 45.712 62.652 ;
     RECT  45.712 2.418 45.785 62.472 ;
     RECT  45.785 2.418 45.904 62.382 ;
     RECT  45.904 19.872 46.073 27.672 ;
     RECT  45.904 6 46.109 8.184 ;
     RECT  45.904 36.816 46.145 36.84 ;
     RECT  45.904 11.136 46.181 11.256 ;
     RECT  45.904 29.088 46.217 35.304 ;
     RECT  45.904 43.92 46.307 43.944 ;
     RECT  45.904 50.736 46.333 50.76 ;
     RECT  46.109 6.384 46.451 8.184 ;
     RECT  45.904 13.296 46.451 17.064 ;
     RECT  46.073 19.968 46.469 27.672 ;
     RECT  46.469 21.216 46.505 27.672 ;
     RECT  45.904 42.72 46.613 42.84 ;
     RECT  46.451 6.384 46.721 7.8 ;
     RECT  45.904 49.488 46.721 49.512 ;
     RECT  46.217 29.088 46.865 35.208 ;
     RECT  45.904 53.568 46.885 54.072 ;
     RECT  46.885 52.32 46.931 54.072 ;
     RECT  46.931 52.32 46.972 53.016 ;
     RECT  46.613 42.72 46.973 42.744 ;
     RECT  46.865 29.088 47.045 31.224 ;
     RECT  45.904 18.72 47.075 18.744 ;
     RECT  47.045 30.672 47.081 31.224 ;
     RECT  46.469 19.968 47.153 20.088 ;
     RECT  46.505 21.456 47.153 27.672 ;
     RECT  46.451 15.792 47.261 17.064 ;
     RECT  45.904 10.032 47.276 10.056 ;
     RECT  47.276 9.648 47.317 10.056 ;
     RECT  46.181 11.136 47.317 11.16 ;
     RECT  47.317 39.12 47.324 39.144 ;
     RECT  47.317 9.648 47.363 11.16 ;
     RECT  46.865 32.256 47.363 35.208 ;
     RECT  45.904 41.424 47.363 41.736 ;
     RECT  47.363 34.848 47.369 35.208 ;
     RECT  47.363 10.848 47.401 11.16 ;
     RECT  47.045 29.088 47.401 29.592 ;
     RECT  47.293 36.96 47.411 36.984 ;
     RECT  47.324 38.16 47.411 39.144 ;
     RECT  47.401 10.848 47.441 11.4 ;
     RECT  47.401 28.992 47.468 29.592 ;
     RECT  47.369 34.896 47.549 35.208 ;
     RECT  47.545 50.688 47.581 50.712 ;
     RECT  46.451 13.296 47.653 13.992 ;
     RECT  47.153 21.552 47.689 27.672 ;
     RECT  47.153 20.064 47.693 20.088 ;
     RECT  47.549 34.896 47.693 35.064 ;
     RECT  47.653 13.296 47.765 14.712 ;
     RECT  47.261 17.04 47.833 17.064 ;
     RECT  47.441 11.136 47.837 11.4 ;
     RECT  46.721 6.384 47.909 7.416 ;
     RECT  47.581 50.16 47.913 50.712 ;
     RECT  47.509 43.92 47.977 43.944 ;
     RECT  47.913 50.16 47.987 51.288 ;
     RECT  47.693 34.896 48.017 35.016 ;
     RECT  47.977 43.296 48.017 43.944 ;
     RECT  47.411 39.024 48.037 39.144 ;
     RECT  47.363 41.424 48.083 41.64 ;
     RECT  47.909 6.672 48.125 7.416 ;
     RECT  47.765 13.296 48.125 14.088 ;
     RECT  48.037 39.024 48.125 39.864 ;
     RECT  47.987 50.16 48.125 50.184 ;
     RECT  47.081 30.768 48.337 31.224 ;
     RECT  47.363 32.256 48.337 33.432 ;
     RECT  48.337 30.768 48.373 33.432 ;
     RECT  48.373 30.768 48.409 33.672 ;
     RECT  47.833 17.04 48.469 17.112 ;
     RECT  47.689 21.552 48.469 27.912 ;
     RECT  47.468 28.944 48.469 29.592 ;
     RECT  48.469 21.552 48.485 29.592 ;
     RECT  47.261 15.792 48.515 15.816 ;
     RECT  48.125 7.2 48.521 7.416 ;
     RECT  48.485 21.648 48.593 29.592 ;
     RECT  48.593 29.52 48.665 29.592 ;
     RECT  48.409 30.768 48.665 34.2 ;
     RECT  48.125 13.92 48.845 14.088 ;
     RECT  48.665 30.768 48.881 32.328 ;
     RECT  48.469 16.896 49.021 17.112 ;
     RECT  47.837 11.376 49.097 11.4 ;
     RECT  49.021 16.848 49.165 17.112 ;
     RECT  49.165 6.96 49.189 6.984 ;
     RECT  48.083 41.616 49.201 41.64 ;
     RECT  49.165 16.08 49.237 17.112 ;
     RECT  48.665 33.648 49.237 34.2 ;
     RECT  49.189 6.144 49.249 6.984 ;
     RECT  48.193 19.92 49.381 19.944 ;
     RECT  48.845 13.92 49.561 14.04 ;
     RECT  49.237 33.648 49.597 34.968 ;
     RECT  49.381 19.68 49.621 19.944 ;
     RECT  46.972 52.992 49.633 53.016 ;
     RECT  49.237 16.08 49.637 17.256 ;
     RECT  49.633 52.848 49.673 53.016 ;
     RECT  49.525 9.84 49.705 9.864 ;
     RECT  49.621 19.68 49.709 20.568 ;
     RECT  49.249 6.144 49.745 6.168 ;
     RECT  49.597 33.648 49.813 35.112 ;
     RECT  48.125 39.024 49.853 39.048 ;
     RECT  49.561 13.056 49.993 14.04 ;
     RECT  46.931 54.048 49.993 54.072 ;
     RECT  49.993 54.048 50.029 54.36 ;
     RECT  49.993 18.768 50.053 18.792 ;
     RECT  48.881 30.816 50.101 32.328 ;
     RECT  48.665 29.568 50.137 29.592 ;
     RECT  48.593 21.648 50.173 28.536 ;
     RECT  50.137 29.568 50.173 29.64 ;
     RECT  49.709 20.352 50.209 20.568 ;
     RECT  50.173 21.648 50.209 29.64 ;
     RECT  49.993 13.056 50.389 14.952 ;
     RECT  49.637 16.08 50.389 16.92 ;
     RECT  50.101 30.816 50.389 32.52 ;
     RECT  50.389 30.816 50.497 32.568 ;
     RECT  49.813 33.648 50.533 36.072 ;
     RECT  45.904 45.936 50.677 45.96 ;
     RECT  50.677 45.84 50.725 45.96 ;
     RECT  50.497 30.816 50.749 32.616 ;
     RECT  50.533 33.648 50.749 36.84 ;
     RECT  47.987 51.264 50.749 51.288 ;
     RECT  50.749 30.816 50.821 36.84 ;
     RECT  50.821 30.72 50.869 36.84 ;
     RECT  48.013 48.144 50.869 48.168 ;
     RECT  50.749 50.736 50.869 51.288 ;
     RECT  50.029 8.16 50.929 8.184 ;
     RECT  50.929 7.92 51.008 8.184 ;
     RECT  49.705 9.648 51.008 9.864 ;
     RECT  50.389 13.056 51.008 16.92 ;
     RECT  50.053 18.192 51.008 18.792 ;
     RECT  50.209 20.352 51.008 29.64 ;
     RECT  50.869 30.672 51.008 36.84 ;
     RECT  49.993 38.112 51.008 38.136 ;
     RECT  49.201 41.616 51.008 42.024 ;
     RECT  48.017 43.296 51.008 43.32 ;
     RECT  50.353 44.448 51.008 44.472 ;
     RECT  50.725 45.696 51.008 45.96 ;
     RECT  50.869 47.424 51.008 48.168 ;
     RECT  50.869 50.304 51.008 51.288 ;
     RECT  49.673 52.848 51.008 52.872 ;
     RECT  50.029 53.904 51.008 54.36 ;
     RECT  47.905 56.832 51.008 56.856 ;
     RECT  51.008 2.148 51.112 62.652 ;
     RECT  51.112 2.418 51.304 62.382 ;
     RECT  51.304 11.76 51.329 13.08 ;
     RECT  51.304 14.928 51.329 18.024 ;
     RECT  51.304 28.608 51.329 36.84 ;
     RECT  51.304 20.592 51.365 25.464 ;
     RECT  51.365 21.168 51.437 25.464 ;
     RECT  51.329 11.76 51.443 12.984 ;
     RECT  51.329 28.608 51.581 34.92 ;
     RECT  51.304 53.52 51.587 54.168 ;
     RECT  51.304 56.352 51.587 56.856 ;
     RECT  51.304 6.864 51.683 6.888 ;
     RECT  51.437 21.168 51.797 22.2 ;
     RECT  51.304 9.6 52.013 9.816 ;
     RECT  51.304 50.304 52.157 50.328 ;
     RECT  51.329 15.072 52.259 18.024 ;
     RECT  51.304 45.6 52.265 45.72 ;
     RECT  51.581 28.608 52.301 34.632 ;
     RECT  51.797 21.648 52.405 22.2 ;
     RECT  52.259 15.072 52.441 17.64 ;
     RECT  52.441 14.16 52.445 17.64 ;
     RECT  51.587 53.52 52.445 53.928 ;
     RECT  51.304 40.992 52.453 42.744 ;
     RECT  51.304 43.824 52.453 43.848 ;
     RECT  51.304 51.984 52.453 52.008 ;
     RECT  52.453 40.992 52.499 43.848 ;
     RECT  52.453 51.84 52.499 52.008 ;
     RECT  52.499 43.296 52.553 43.848 ;
     RECT  51.443 12.528 52.589 12.552 ;
     RECT  51.329 36.048 52.621 36.84 ;
     RECT  51.587 56.352 52.661 56.376 ;
     RECT  52.405 21.648 52.693 22.488 ;
     RECT  51.437 23.904 52.693 25.464 ;
     RECT  52.301 28.608 52.909 29.256 ;
     RECT  52.621 36.048 52.945 37.368 ;
     RECT  52.445 14.16 52.949 15.048 ;
     RECT  52.693 21.648 52.981 25.464 ;
     RECT  52.981 21.12 53.017 25.464 ;
     RECT  51.304 26.544 53.017 27.432 ;
     RECT  52.909 28.512 53.021 29.256 ;
     RECT  52.499 40.992 53.093 42.216 ;
     RECT  52.553 43.296 53.093 43.56 ;
     RECT  51.304 7.92 53.125 7.944 ;
     RECT  52.013 9.6 53.161 9.624 ;
     RECT  53.125 7.92 53.165 8.424 ;
     RECT  52.945 35.76 53.165 37.368 ;
     RECT  53.197 63.84 53.459 63.864 ;
     RECT  52.445 53.568 53.485 53.928 ;
     RECT  53.233 62.736 53.509 62.76 ;
     RECT  52.949 15.024 53.521 15.048 ;
     RECT  52.445 16.032 53.521 17.64 ;
     RECT  53.509 62.64 53.593 62.76 ;
     RECT  53.165 35.76 53.633 36.84 ;
     RECT  53.521 15.024 53.669 17.64 ;
     RECT  52.909 18.816 53.669 18.84 ;
     RECT  53.161 9.504 53.701 9.624 ;
     RECT  53.485 52.992 53.701 54.168 ;
     RECT  53.593 62.64 53.701 63.288 ;
     RECT  52.301 30.288 53.737 34.632 ;
     RECT  53.66 57.024 53.747 57.048 ;
     RECT  53.701 52.992 53.777 54.504 ;
     RECT  53.701 62.112 53.843 63.288 ;
     RECT  52.405 11.376 53.917 11.4 ;
     RECT  53.777 53.904 53.957 54.504 ;
     RECT  53.843 62.112 53.957 63.24 ;
     RECT  53.737 30.288 53.989 34.776 ;
     RECT  53.161 38.64 54.092 38.664 ;
     RECT  53.017 21.12 54.097 27.432 ;
     RECT  53.021 28.512 54.097 29.064 ;
     RECT  53.957 62.112 54.131 62.664 ;
     RECT  53.701 9.504 54.169 10.296 ;
     RECT  53.917 11.376 54.169 12.36 ;
     RECT  53.165 8.4 54.173 8.424 ;
     RECT  53.093 41.616 54.173 42.216 ;
     RECT  53.093 43.296 54.173 43.32 ;
     RECT  54.092 38.016 54.179 38.664 ;
     RECT  52.499 51.84 54.209 51.864 ;
     RECT  54.169 9.504 54.281 12.36 ;
     RECT  54.179 38.64 54.38 38.664 ;
     RECT  54.097 21.12 54.385 29.064 ;
     RECT  53.773 44.448 54.389 44.472 ;
     RECT  54.385 20.88 54.419 29.064 ;
     RECT  54.281 10.848 54.421 12.36 ;
     RECT  54.281 9.504 54.428 9.624 ;
     RECT  54.421 10.848 54.467 14.088 ;
     RECT  54.38 38.64 54.467 38.76 ;
     RECT  54.173 41.616 54.467 41.64 ;
     RECT  54.131 62.112 54.469 62.424 ;
     RECT  54.428 9.216 54.515 9.624 ;
     RECT  53.669 15.744 54.565 17.64 ;
     RECT  53.989 30.288 54.601 35.064 ;
     RECT  53.633 36.48 54.601 36.84 ;
     RECT  54.469 62.064 54.605 62.424 ;
     RECT  54.515 9.6 54.611 9.624 ;
     RECT  54.605 62.16 54.641 62.424 ;
     RECT  54.467 10.848 54.659 11.4 ;
     RECT  54.467 13.296 54.677 14.088 ;
     RECT  54.601 30.288 54.709 36.84 ;
     RECT  54.641 62.208 54.713 62.424 ;
     RECT  54.659 10.848 54.749 10.872 ;
     RECT  54.277 57.072 54.785 57.096 ;
     RECT  54.565 15.744 54.821 17.736 ;
     RECT  54.709 29.616 54.857 36.84 ;
     RECT  54.421 43.344 54.997 43.368 ;
     RECT  54.821 15.744 55.069 17.64 ;
     RECT  54.419 20.88 55.105 28.248 ;
     RECT  55.069 14.784 55.181 17.64 ;
     RECT  52.265 45.6 55.292 45.624 ;
     RECT  54.673 19.344 55.321 19.368 ;
     RECT  55.105 20.544 55.321 28.248 ;
     RECT  54.857 29.616 55.325 35.016 ;
     RECT  55.292 45.6 55.333 45.96 ;
     RECT  55.181 14.784 55.361 16.152 ;
     RECT  55.333 45.264 55.379 45.96 ;
     RECT  54.997 43.344 55.429 43.896 ;
     RECT  53.957 54.48 55.477 54.504 ;
     RECT  55.321 19.344 55.645 28.248 ;
     RECT  55.645 18.96 55.825 28.248 ;
     RECT  55.429 42.768 56.041 43.896 ;
     RECT  55.379 45.264 56.041 45.288 ;
     RECT  55.325 30.24 56.156 35.016 ;
     RECT  54.857 36.096 56.156 36.84 ;
     RECT  54.469 7.344 56.408 7.368 ;
     RECT  54.677 13.296 56.408 13.32 ;
     RECT  55.361 15.744 56.408 16.152 ;
     RECT  55.181 17.328 56.408 17.64 ;
     RECT  55.825 18.96 56.408 28.488 ;
     RECT  56.156 30.24 56.408 36.84 ;
     RECT  54.467 38.64 56.408 38.664 ;
     RECT  54.629 40.608 56.408 40.632 ;
     RECT  56.041 42.768 56.408 45.288 ;
     RECT  55.477 54.48 56.408 54.744 ;
     RECT  56.408 2.148 56.512 62.652 ;
     RECT  56.512 2.418 56.704 62.382 ;
     RECT  56.704 13.632 56.819 13.656 ;
     RECT  56.704 15.936 56.873 17.64 ;
     RECT  56.704 20.16 56.981 27.096 ;
     RECT  56.873 15.936 57.053 17.112 ;
     RECT  56.704 28.128 57.089 35.064 ;
     RECT  57.053 15.936 57.161 17.016 ;
     RECT  56.981 20.496 57.593 27.096 ;
     RECT  56.704 44.448 57.665 44.472 ;
     RECT  56.704 18.816 57.695 18.984 ;
     RECT  56.704 42.528 57.733 42.552 ;
     RECT  56.704 37.056 57.737 37.608 ;
     RECT  57.733 42.528 57.773 42.792 ;
     RECT  57.695 18.672 57.779 18.984 ;
     RECT  57.737 37.056 57.881 37.08 ;
     RECT  57.161 16.032 57.953 17.016 ;
     RECT  57.779 18.672 58.169 18.696 ;
     RECT  57.773 42.768 58.277 42.792 ;
     RECT  57.089 30.288 58.453 35.064 ;
     RECT  57.089 28.128 58.597 28.776 ;
     RECT  58.453 30.096 58.597 35.064 ;
     RECT  57.593 21.024 58.705 27.096 ;
     RECT  58.597 28.128 58.705 35.064 ;
     RECT  58.705 21.024 58.777 35.256 ;
     RECT  58.777 20.832 59.281 35.256 ;
     RECT  59.281 20.112 59.641 36.072 ;
     RECT  59.353 38.592 59.821 38.616 ;
     RECT  59.821 38.256 60.073 38.616 ;
     RECT  59.641 19.92 60.109 36.072 ;
     RECT  59.461 37.056 60.109 37.08 ;
     RECT  60.109 19.92 60.325 37.08 ;
     RECT  60.073 38.256 60.325 38.76 ;
     RECT  57.953 16.032 60.329 16.104 ;
     RECT  60.329 16.032 60.473 16.056 ;
     RECT  59.677 43.536 60.545 43.56 ;
     RECT  60.325 19.92 60.581 38.76 ;
     RECT  60.469 18.624 60.653 18.648 ;
     RECT  60.581 20.112 60.901 38.76 ;
     RECT  60.757 17.088 60.997 17.112 ;
     RECT  60.997 17.088 61.477 17.4 ;
     RECT  61.549 42.288 61.585 42.312 ;
     RECT  61.477 16.848 61.808 17.4 ;
     RECT  60.901 20.112 61.808 38.856 ;
     RECT  61.729 40.08 61.808 40.104 ;
     RECT  61.585 42.288 61.808 42.792 ;
     RECT  60.973 46.704 61.808 46.728 ;
     RECT  61.808 2.148 61.912 62.652 ;
     RECT  61.912 2.418 62.104 62.382 ;
     RECT  62.104 14.928 62.525 14.952 ;
     RECT  62.104 42.192 63.133 44.232 ;
     RECT  63.133 42.192 63.169 45.096 ;
     RECT  62.104 20.016 63.241 37.992 ;
     RECT  62.104 16.08 63.277 18.984 ;
     RECT  63.241 20.016 63.277 38.184 ;
     RECT  63.277 16.08 63.745 38.184 ;
     RECT  63.277 54.576 63.817 54.696 ;
     RECT  63.745 16.08 64.764 38.28 ;
     RECT  63.169 42.192 64.764 45.192 ;
     RECT  63.817 54.48 64.764 54.696 ;
    LAYER M5 ;
     RECT  16.08 0.016 42.12 0.131 ;
     RECT  16.176 0.131 42.12 1.763 ;
     RECT  16.272 1.763 42.12 1.811 ;
     RECT  16.272 1.811 38.088 1.859 ;
     RECT  39.216 1.811 42.12 1.859 ;
     RECT  27.024 1.859 37.992 1.907 ;
     RECT  2.4 2.137 2.52 2.151 ;
     RECT  7.8 2.137 7.92 2.151 ;
     RECT  13.2 2.137 13.32 2.151 ;
     RECT  45.6 2.137 45.72 2.151 ;
     RECT  51 2.137 51.12 2.151 ;
     RECT  56.4 2.137 56.52 2.151 ;
     RECT  61.8 2.137 61.92 2.151 ;
     RECT  16.272 1.859 25.896 2.195 ;
     RECT  16.272 2.195 19.176 2.291 ;
     RECT  20.208 2.195 25.896 2.291 ;
     RECT  27.024 1.907 37.608 2.291 ;
     RECT  39.216 1.859 42.024 2.291 ;
     RECT  23.184 2.291 25.896 2.821 ;
     RECT  27.024 2.291 31.608 2.821 ;
     RECT  39.792 2.291 41.064 2.867 ;
     RECT  21.36 2.291 21.672 2.915 ;
     RECT  23.184 2.821 31.608 2.915 ;
     RECT  32.592 2.291 33.288 2.915 ;
     RECT  39.792 2.867 40.68 2.915 ;
     RECT  40.032 2.915 40.68 3.059 ;
     RECT  21.456 2.915 21.672 3.443 ;
     RECT  23.184 2.915 26.424 3.443 ;
     RECT  27.6 2.915 31.608 3.443 ;
     RECT  32.88 2.915 33.288 3.925 ;
     RECT  34.464 2.291 37.608 3.925 ;
     RECT  17.808 2.291 18.912 4.019 ;
     RECT  21.456 3.443 21.48 4.019 ;
     RECT  23.184 3.443 24.936 4.019 ;
     RECT  27.888 3.443 31.608 4.019 ;
     RECT  32.88 3.925 37.608 4.019 ;
     RECT  40.032 3.059 40.512 4.019 ;
     RECT  32.88 4.019 36.84 4.067 ;
     RECT  32.88 4.067 35.88 4.259 ;
     RECT  18.432 4.019 18.912 4.403 ;
     RECT  29.04 4.019 31.608 4.595 ;
     RECT  18.6 4.403 18.912 5.029 ;
     RECT  32.88 4.259 35.688 5.075 ;
     RECT  24 4.019 24.648 5.077 ;
     RECT  27.888 4.019 28.056 5.123 ;
     RECT  40.2 4.019 40.512 5.317 ;
     RECT  18.6 5.029 19.032 5.605 ;
     RECT  32.88 5.075 35.592 5.747 ;
     RECT  43.104 5.077 43.128 6.179 ;
     RECT  28.032 5.123 28.056 6.181 ;
     RECT  29.184 4.595 31.608 6.181 ;
     RECT  17.664 5.605 19.032 6.275 ;
     RECT  44.304 5.605 44.328 6.275 ;
     RECT  26.4 3.443 26.424 6.277 ;
     RECT  28.032 6.181 31.608 6.323 ;
     RECT  26.4 6.277 26.616 6.421 ;
     RECT  28.032 6.323 28.248 6.421 ;
     RECT  20.256 5.077 20.28 6.469 ;
     RECT  18.6 6.275 19.032 6.515 ;
     RECT  29.4 6.323 31.608 6.565 ;
     RECT  20.256 6.469 20.808 6.707 ;
     RECT  26.4 6.421 28.248 6.755 ;
     RECT  23.76 5.077 24.888 6.805 ;
     RECT  51 2.151 51.312 6.853 ;
     RECT  29.4 6.565 31.896 6.899 ;
     RECT  49.2 6.133 49.224 6.995 ;
     RECT  26.4 6.755 26.616 7.475 ;
     RECT  45.6 2.151 45.912 7.765 ;
     RECT  18.6 6.515 18.912 7.909 ;
     RECT  51 6.853 51.672 7.955 ;
     RECT  29.4 6.899 31.608 7.957 ;
     RECT  32.88 5.747 35.112 7.957 ;
     RECT  23.76 6.805 25.368 8.003 ;
     RECT  40.2 5.317 41.064 8.195 ;
     RECT  18.336 7.909 18.912 8.579 ;
     RECT  18.48 8.579 18.912 8.821 ;
     RECT  20.256 6.707 20.28 8.821 ;
     RECT  18.48 8.821 20.28 9.251 ;
     RECT  54.48 7.333 54.504 9.251 ;
     RECT  45.6 7.765 46.44 9.637 ;
     RECT  18.48 9.251 19.368 9.827 ;
     RECT  29.4 7.957 35.112 10.213 ;
     RECT  36.384 6.181 36.408 10.213 ;
     RECT  21.408 9.061 21.432 10.259 ;
     RECT  29.4 10.213 36.408 10.741 ;
     RECT  40.2 8.195 40.728 10.837 ;
     RECT  26.4 7.475 26.424 10.883 ;
     RECT  45.6 9.637 47.352 10.883 ;
     RECT  54.576 9.589 54.6 10.931 ;
     RECT  40.2 10.837 41.448 10.979 ;
     RECT  28.032 6.755 28.248 11.125 ;
     RECT  29.4 10.741 37.08 11.125 ;
     RECT  18.48 9.827 18.912 11.267 ;
     RECT  23.76 8.003 25.32 11.365 ;
     RECT  23.76 11.365 26.232 11.459 ;
     RECT  28.032 11.125 37.08 11.459 ;
     RECT  28.032 11.459 36.408 11.651 ;
     RECT  18.6 11.267 18.912 11.749 ;
     RECT  51 7.955 51.312 11.749 ;
     RECT  28.032 11.651 30.024 11.941 ;
     RECT  40.2 10.979 40.728 11.941 ;
     RECT  54.624 11.365 54.648 11.941 ;
     RECT  27.936 11.941 30.024 11.987 ;
     RECT  31.584 11.651 36.408 12.083 ;
     RECT  32.16 12.083 36.408 12.227 ;
     RECT  21.456 11.797 21.48 12.517 ;
     RECT  21.072 12.517 21.48 12.563 ;
     RECT  26.208 11.459 26.232 12.563 ;
     RECT  45.6 10.883 46.44 12.757 ;
     RECT  29.4 11.987 30.024 12.803 ;
     RECT  27.936 11.987 28.248 12.901 ;
     RECT  51 11.749 51.432 12.995 ;
     RECT  39.888 11.941 41.16 13.043 ;
     RECT  29.4 12.803 29.832 13.093 ;
     RECT  18.6 11.749 19.656 13.283 ;
     RECT  40.2 13.043 41.16 13.283 ;
     RECT  56.4 2.151 56.712 13.621 ;
     RECT  32.16 12.227 35.112 13.715 ;
     RECT  29.28 13.093 29.832 13.859 ;
     RECT  44.736 12.757 46.44 13.907 ;
     RECT  54.432 11.941 54.648 14.099 ;
     RECT  21.072 12.563 21.096 14.291 ;
     RECT  27.888 12.901 28.248 14.291 ;
     RECT  36.384 12.227 36.408 14.773 ;
     RECT  44.976 13.907 46.44 14.963 ;
     RECT  32.16 13.715 32.616 15.203 ;
     RECT  27.936 14.291 28.248 15.253 ;
     RECT  23.76 11.459 24.6 15.397 ;
     RECT  36.384 14.773 36.456 15.443 ;
     RECT  51 12.995 51.312 15.685 ;
     RECT  21.84 14.821 21.864 15.731 ;
     RECT  36.384 15.443 36.408 15.731 ;
     RECT  22.992 15.397 24.6 16.019 ;
     RECT  27.888 15.253 28.248 16.019 ;
     RECT  27.936 16.019 28.248 16.595 ;
     RECT  37.632 16.117 37.656 16.837 ;
     RECT  54.624 14.099 54.648 17.075 ;
     RECT  33.888 13.715 35.112 17.077 ;
     RECT  61.8 2.151 62.112 17.077 ;
     RECT  29.4 13.859 29.832 17.123 ;
     RECT  37.632 16.837 38.232 17.123 ;
     RECT  61.008 17.077 62.112 17.411 ;
     RECT  27.936 16.595 27.96 17.509 ;
     RECT  27.648 17.509 27.96 17.555 ;
     RECT  32.592 15.203 32.616 17.605 ;
     RECT  33.888 17.077 35.208 17.699 ;
     RECT  51 15.685 52.248 18.035 ;
     RECT  38.208 17.123 38.232 18.133 ;
     RECT  44.976 14.963 45.912 18.133 ;
     RECT  51 18.035 52.152 18.181 ;
     RECT  37.968 18.133 38.232 18.229 ;
     RECT  32.16 17.605 32.616 18.565 ;
     RECT  56.4 13.621 56.808 18.661 ;
     RECT  32.16 18.565 33.432 18.757 ;
     RECT  50.064 18.181 52.152 18.803 ;
     RECT  56.4 18.661 57.768 18.851 ;
     RECT  57.744 18.851 57.768 18.995 ;
     RECT  44.688 18.133 45.912 19.333 ;
     RECT  31.296 18.757 33.432 19.379 ;
     RECT  31.296 19.379 32.616 19.523 ;
     RECT  37.968 18.229 38.808 19.523 ;
     RECT  7.8 2.151 8.112 19.621 ;
     RECT  34.8 17.699 35.112 19.765 ;
     RECT  47.04 18.709 47.064 20.003 ;
     RECT  56.4 18.851 56.712 20.149 ;
     RECT  6.672 19.957 6.696 20.533 ;
     RECT  7.8 19.621 8.568 20.533 ;
     RECT  6.672 20.533 8.568 20.579 ;
     RECT  44.496 19.333 45.912 20.579 ;
     RECT  49.632 19.909 49.656 20.579 ;
     RECT  44.496 20.579 44.52 20.819 ;
     RECT  56.304 20.149 56.712 20.867 ;
     RECT  6.816 20.579 8.568 21.155 ;
     RECT  32.16 19.523 32.616 21.155 ;
     RECT  11.04 20.725 11.064 21.395 ;
     RECT  45.6 20.579 45.912 21.637 ;
     RECT  48.48 15.781 48.504 21.637 ;
     RECT  51 18.803 52.152 21.731 ;
     RECT  13.2 2.151 13.512 22.021 ;
     RECT  27.648 17.555 27.672 22.165 ;
     RECT  40.2 13.283 40.512 22.165 ;
     RECT  13.104 22.021 13.848 22.211 ;
     RECT  32.16 21.155 32.184 22.213 ;
     RECT  32.16 22.213 32.28 22.259 ;
     RECT  37.968 19.523 37.992 22.259 ;
     RECT  45.024 21.637 45.912 22.451 ;
     RECT  23.76 16.019 24.6 22.499 ;
     RECT  21.456 20.485 21.48 22.739 ;
     RECT  33.984 19.765 35.112 22.739 ;
     RECT  7.8 21.155 8.112 22.741 ;
     RECT  18.6 13.283 18.912 22.741 ;
     RECT  20.208 22.357 20.232 22.741 ;
     RECT  18.6 22.741 20.232 22.787 ;
     RECT  27.648 22.165 27.96 22.787 ;
     RECT  42.768 20.965 42.792 22.787 ;
     RECT  36.864 22.213 36.888 22.835 ;
     RECT  11.472 21.493 11.496 23.027 ;
     RECT  40.2 22.165 41.016 23.267 ;
     RECT  32.256 22.259 32.28 23.317 ;
     RECT  24 22.499 24.6 23.411 ;
     RECT  7.8 22.741 8.232 23.603 ;
     RECT  48.48 21.637 48.552 23.891 ;
     RECT  20.88 22.789 20.904 24.371 ;
     RECT  40.2 23.267 40.512 24.469 ;
     RECT  42.192 23.317 42.216 24.469 ;
     RECT  45.6 22.451 45.912 24.469 ;
     RECT  31.392 23.317 32.28 24.563 ;
     RECT  18.6 22.787 19.368 24.611 ;
     RECT  49.536 23.845 49.56 24.611 ;
     RECT  34.8 22.739 35.112 24.997 ;
     RECT  27.936 22.787 27.96 25.045 ;
     RECT  29.4 17.123 29.712 25.045 ;
     RECT  27.936 25.045 29.712 25.091 ;
     RECT  0.144 24.181 0.168 25.379 ;
     RECT  13.2 22.211 13.848 25.715 ;
     RECT  34.704 24.997 35.112 25.715 ;
     RECT  40.2 24.469 42.216 25.715 ;
     RECT  10.752 25.045 10.776 26.197 ;
     RECT  22.176 24.805 22.2 26.243 ;
     RECT  9.888 26.197 10.776 26.291 ;
     RECT  43.92 25.621 43.944 26.291 ;
     RECT  45.312 24.469 45.912 26.531 ;
     RECT  40.2 25.715 41.592 26.579 ;
     RECT  13.2 25.715 13.8 26.675 ;
     RECT  7.8 23.603 8.112 26.677 ;
     RECT  9.888 26.291 9.912 26.819 ;
     RECT  45.6 26.531 45.912 27.205 ;
     RECT  32.256 24.563 32.28 27.301 ;
     RECT  45.6 27.205 46.776 27.301 ;
     RECT  48.48 23.891 48.504 27.301 ;
     RECT  28.464 25.091 29.712 27.347 ;
     RECT  7.68 26.677 8.112 27.395 ;
     RECT  13.2 26.675 13.512 27.877 ;
     RECT  29.4 27.347 29.712 27.877 ;
     RECT  20.112 27.877 20.136 28.261 ;
     RECT  20.112 28.261 20.568 28.307 ;
     RECT  34.8 25.715 35.112 28.453 ;
     RECT  51 21.731 51.312 28.453 ;
     RECT  22.8 27.301 22.824 28.499 ;
     RECT  18.6 24.611 19.032 28.547 ;
     RECT  54.384 24.085 54.408 28.597 ;
     RECT  24 23.411 24.312 28.837 ;
     RECT  25.296 27.301 25.32 28.837 ;
     RECT  21.696 27.877 21.72 28.931 ;
     RECT  32.256 27.301 32.472 28.931 ;
     RECT  45.6 27.301 48.504 28.979 ;
     RECT  53.856 28.597 54.408 29.075 ;
     RECT  20.544 28.307 20.568 29.123 ;
     RECT  24 28.837 25.32 29.123 ;
     RECT  45.6 28.979 46.776 29.123 ;
     RECT  50.88 28.453 51.312 29.267 ;
     RECT  40.2 26.579 41.304 29.365 ;
     RECT  34.032 28.453 35.112 29.411 ;
     RECT  48.48 28.979 48.504 29.603 ;
     RECT  29.4 27.877 30.264 29.699 ;
     RECT  13.104 27.877 13.512 29.891 ;
     RECT  34.8 29.411 35.112 29.893 ;
     RECT  40.2 29.365 41.64 30.227 ;
     RECT  28.032 29.029 28.056 30.419 ;
     RECT  12 29.893 12.024 30.565 ;
     RECT  40.2 30.227 41.304 30.565 ;
     RECT  39.936 30.565 41.304 30.611 ;
     RECT  51 29.267 51.312 30.661 ;
     RECT  33.504 29.893 33.528 30.755 ;
     RECT  34.8 29.893 35.352 30.757 ;
     RECT  61.8 17.411 62.112 30.757 ;
     RECT  10.464 30.133 10.488 30.803 ;
     RECT  19.92 30.565 19.944 30.851 ;
     RECT  61.8 30.757 62.664 30.899 ;
     RECT  45.6 29.123 46.008 30.949 ;
     RECT  56.4 20.867 56.712 30.949 ;
     RECT  45.6 30.949 46.056 31.381 ;
     RECT  50.88 30.661 51.312 31.573 ;
     RECT  0.144 31.429 0.168 31.619 ;
     RECT  11.664 30.565 12.024 31.667 ;
     RECT  50.784 31.573 51.312 31.669 ;
     RECT  34.8 30.757 35.448 31.907 ;
     RECT  42.768 29.365 42.792 31.955 ;
     RECT  55.584 30.949 56.712 31.955 ;
     RECT  45.6 31.381 46.392 32.531 ;
     RECT  50.736 31.669 51.312 32.627 ;
     RECT  31.104 32.341 31.128 32.725 ;
     RECT  32.256 28.931 32.28 32.725 ;
     RECT  48.48 32.341 48.504 32.725 ;
     RECT  31.104 32.725 32.28 32.771 ;
     RECT  39.936 30.611 40.512 32.963 ;
     RECT  7.8 27.395 8.112 33.541 ;
     RECT  13.2 29.891 13.512 33.541 ;
     RECT  6.576 30.469 6.6 33.587 ;
     RECT  45.6 32.531 46.008 33.683 ;
     RECT  48.384 32.725 48.504 33.683 ;
     RECT  10.176 32.437 10.2 33.827 ;
     RECT  48.48 33.683 48.504 33.827 ;
     RECT  53.856 29.075 53.88 34.069 ;
     RECT  53.856 34.069 54.12 34.115 ;
     RECT  13.2 33.541 13.992 34.165 ;
     RECT  54.096 34.115 54.12 34.403 ;
     RECT  56.4 31.955 56.712 34.741 ;
     RECT  13.2 34.165 14.808 34.787 ;
     RECT  47.328 34.117 47.352 34.883 ;
     RECT  55.92 34.741 56.712 35.027 ;
     RECT  18.6 28.547 18.912 35.029 ;
     RECT  7.68 33.541 8.112 35.317 ;
     RECT  24 29.123 24.408 35.317 ;
     RECT  34.8 31.907 35.112 35.317 ;
     RECT  37.632 34.501 37.656 35.363 ;
     RECT  42.768 34.117 42.792 35.411 ;
     RECT  13.2 34.787 13.512 35.797 ;
     RECT  51 32.627 51.312 35.845 ;
     RECT  18.6 35.029 19.464 35.893 ;
     RECT  11.664 31.667 11.688 35.939 ;
     RECT  24 35.317 24.696 35.939 ;
     RECT  31.344 32.771 32.28 35.939 ;
     RECT  7.632 35.317 8.112 35.987 ;
     RECT  56.208 35.027 56.712 35.987 ;
     RECT  24 35.939 24.408 36.083 ;
     RECT  28.224 34.741 28.248 36.227 ;
     RECT  50.88 35.845 51.312 36.515 ;
     RECT  40.08 32.963 40.512 36.563 ;
     RECT  5.184 35.317 5.208 36.755 ;
     RECT  13.2 35.797 13.704 36.755 ;
     RECT  17.664 35.893 19.464 37.091 ;
     RECT  38.784 35.125 38.808 37.091 ;
     RECT  29.4 29.699 29.712 37.477 ;
     RECT  34.368 35.317 35.112 37.667 ;
     RECT  20.448 36.517 20.472 38.005 ;
     RECT  21.648 36.997 21.672 38.005 ;
     RECT  20.448 38.005 21.672 38.051 ;
     RECT  18.6 37.091 19.464 38.101 ;
     RECT  20.448 38.051 21.288 38.101 ;
     RECT  40.2 36.563 40.512 38.149 ;
     RECT  15.12 34.885 15.144 38.197 ;
     RECT  54.144 38.005 54.168 38.629 ;
     RECT  54.144 38.629 54.696 38.675 ;
     RECT  29.4 37.477 30.024 38.723 ;
     RECT  31.728 35.939 32.28 38.725 ;
     RECT  45.6 33.683 45.912 38.725 ;
     RECT  18.6 38.101 21.288 38.819 ;
     RECT  26.784 36.997 26.808 38.819 ;
     RECT  47.376 36.949 47.4 39.109 ;
     RECT  37.296 37.573 37.32 39.203 ;
     RECT  20.736 38.819 21.24 39.251 ;
     RECT  18.6 38.819 19.656 39.301 ;
     RECT  31.728 38.725 32.952 39.395 ;
     RECT  15.12 38.197 15.768 39.443 ;
     RECT  39.36 38.149 40.512 39.443 ;
     RECT  34.56 37.667 35.112 39.733 ;
     RECT  47.328 39.109 47.4 39.829 ;
     RECT  10.848 38.725 10.872 39.875 ;
     RECT  18 39.301 19.656 39.923 ;
     RECT  34.56 39.733 35.208 40.213 ;
     RECT  31.728 39.395 32.28 40.259 ;
     RECT  44.784 38.725 45.912 40.261 ;
     RECT  44.448 40.261 45.912 40.307 ;
     RECT  25.776 36.997 25.8 40.499 ;
     RECT  54.432 38.675 54.696 40.643 ;
     RECT  24 36.083 24.312 40.933 ;
     RECT  26.112 40.885 26.136 40.981 ;
     RECT  20.736 39.251 20.76 41.075 ;
     RECT  18.6 39.923 19.656 41.171 ;
     RECT  34.512 40.213 35.208 41.269 ;
     RECT  45.6 40.307 45.912 41.413 ;
     RECT  47.328 39.829 48.072 41.459 ;
     RECT  0.144 41.413 0.168 41.603 ;
     RECT  7.68 35.987 8.112 41.651 ;
     RECT  34.32 41.269 35.208 41.699 ;
     RECT  52.992 40.981 53.016 41.699 ;
     RECT  47.328 41.459 47.352 41.747 ;
     RECT  29.4 38.723 29.712 41.797 ;
     RECT  23.904 40.933 24.312 41.939 ;
     RECT  22.8 41.845 22.824 42.083 ;
     RECT  32.256 40.259 32.28 42.133 ;
     RECT  11.52 41.029 11.544 42.179 ;
     RECT  37.344 39.301 37.368 42.227 ;
     RECT  33.312 41.605 33.336 42.467 ;
     RECT  26.112 40.981 26.184 42.613 ;
     RECT  40.2 39.443 40.512 42.613 ;
     RECT  31.728 42.133 32.28 42.709 ;
     RECT  29.04 41.797 29.712 42.805 ;
     RECT  30.768 42.709 32.28 42.805 ;
     RECT  28.512 42.805 32.28 42.851 ;
     RECT  37.584 42.709 37.608 42.997 ;
     RECT  44.448 40.307 44.472 43.141 ;
     RECT  45.504 41.413 45.912 43.141 ;
     RECT  44.448 43.141 45.912 43.187 ;
     RECT  16.176 42.421 16.2 43.235 ;
     RECT  26.112 42.613 26.712 43.331 ;
     RECT  54.432 40.643 54.456 43.379 ;
     RECT  39.408 42.613 41.064 43.523 ;
     RECT  22.896 42.949 22.92 43.571 ;
     RECT  52.464 42.181 52.488 43.571 ;
     RECT  0.144 43.525 0.168 43.715 ;
     RECT  28.512 42.851 30.312 43.763 ;
     RECT  29.4 43.763 30.312 43.811 ;
     RECT  7.8 41.651 8.112 43.861 ;
     RECT  34.32 41.699 35.112 43.861 ;
     RECT  44.976 43.187 45.912 43.909 ;
     RECT  44.976 43.909 46.296 43.955 ;
     RECT  37.584 42.997 37.656 44.005 ;
     RECT  26.112 43.331 26.184 44.051 ;
     RECT  5.184 42.709 5.208 44.339 ;
     RECT  34.224 43.861 35.112 44.627 ;
     RECT  37.584 44.005 37.896 45.059 ;
     RECT  39.408 43.523 40.512 45.059 ;
     RECT  26.16 44.051 26.184 45.155 ;
     RECT  24 41.939 24.312 45.301 ;
     RECT  41.616 44.389 41.64 45.395 ;
     RECT  18.6 41.171 18.912 45.541 ;
     RECT  12.192 44.389 12.216 45.635 ;
     RECT  51 36.515 51.312 45.685 ;
     RECT  50.736 45.685 51.312 45.875 ;
     RECT  55.344 45.253 55.368 45.971 ;
     RECT  37.872 45.059 37.896 46.069 ;
     RECT  34.368 44.627 35.112 46.211 ;
     RECT  24 45.301 24.408 46.453 ;
     RECT  13.2 36.755 13.512 46.645 ;
     RECT  15.12 39.443 15.144 46.645 ;
     RECT  18.288 45.541 18.912 46.787 ;
     RECT  31.728 42.851 32.28 46.883 ;
     RECT  24 46.453 24.456 46.979 ;
     RECT  29.4 43.811 29.712 47.029 ;
     RECT  29.136 47.029 29.712 47.125 ;
     RECT  40.2 45.059 40.512 47.125 ;
     RECT  20.784 42.997 20.808 47.173 ;
     RECT  37.632 46.069 37.896 47.315 ;
     RECT  31.728 46.883 31.752 47.363 ;
     RECT  34.8 46.211 35.112 47.749 ;
     RECT  20.784 47.173 21.288 47.939 ;
     RECT  7.8 43.861 8.952 48.421 ;
     RECT  39.888 47.125 40.512 48.515 ;
     RECT  7.8 48.421 9.576 48.659 ;
     RECT  22.512 47.845 22.536 48.659 ;
     RECT  28.512 47.125 29.712 48.659 ;
     RECT  30.816 48.229 30.84 48.755 ;
     RECT  11.136 46.645 11.16 48.901 ;
     RECT  20.784 47.939 20.808 48.997 ;
     RECT  24 46.979 24.312 48.997 ;
     RECT  29.136 48.659 29.712 48.997 ;
     RECT  9.552 48.659 9.576 49.043 ;
     RECT  13.2 46.645 15.144 49.043 ;
     RECT  20.784 48.997 21.048 49.043 ;
     RECT  11.136 48.901 12.024 49.187 ;
     RECT  34.512 47.749 35.112 49.379 ;
     RECT  7.8 48.659 8.112 49.477 ;
     RECT  18.6 46.787 18.912 49.477 ;
     RECT  42.768 48.421 42.792 49.523 ;
     RECT  40.2 48.515 40.512 49.525 ;
     RECT  12 49.187 12.024 49.571 ;
     RECT  33.36 47.845 33.384 49.619 ;
     RECT  24 48.997 24.504 49.715 ;
     RECT  39.744 49.525 40.512 50.101 ;
     RECT  13.2 49.043 14.232 50.197 ;
     RECT  13.2 50.197 14.568 50.243 ;
     RECT  29.136 48.997 30.264 50.437 ;
     RECT  18.6 49.477 19.896 50.531 ;
     RECT  37.872 47.315 37.896 50.677 ;
     RECT  39.696 50.101 40.512 50.677 ;
     RECT  7.392 49.477 8.112 50.723 ;
     RECT  45.6 43.955 46.296 50.771 ;
     RECT  50.88 45.875 51.312 50.771 ;
     RECT  29.136 50.437 31.032 51.253 ;
     RECT  39.408 50.677 40.512 51.253 ;
     RECT  47.952 50.677 47.976 51.299 ;
     RECT  18.6 50.531 19.848 51.347 ;
     RECT  28.416 51.253 31.032 51.637 ;
     RECT  33.264 51.541 33.288 51.781 ;
     RECT  34.8 49.379 35.112 51.781 ;
     RECT  34.8 51.781 35.832 51.829 ;
     RECT  37.104 50.677 37.896 51.829 ;
     RECT  11.376 51.205 11.4 51.923 ;
     RECT  52.464 51.829 52.488 52.019 ;
     RECT  28.416 51.637 31.32 52.357 ;
     RECT  33.072 51.781 33.288 52.357 ;
     RECT  39.408 51.253 41.016 52.357 ;
     RECT  28.176 52.357 31.32 52.405 ;
     RECT  32.688 52.357 33.288 52.405 ;
     RECT  34.8 51.829 37.896 52.405 ;
     RECT  39.408 52.357 41.496 52.405 ;
     RECT  43.056 51.829 43.08 52.405 ;
     RECT  28.176 52.405 33.288 52.885 ;
     RECT  39.408 52.405 41.592 52.885 ;
     RECT  42.768 52.405 43.08 52.885 ;
     RECT  44.16 52.405 44.184 52.885 ;
     RECT  14.544 50.243 14.568 52.931 ;
     RECT  27.84 52.885 33.288 52.981 ;
     RECT  34.56 52.405 37.896 52.981 ;
     RECT  39.408 52.885 44.184 52.981 ;
     RECT  24 49.715 24.312 53.413 ;
     RECT  25.584 52.405 25.608 53.413 ;
     RECT  46.896 52.309 46.92 53.603 ;
     RECT  24 53.413 25.608 53.941 ;
     RECT  23.616 53.941 25.608 54.085 ;
     RECT  27.648 52.981 44.184 54.085 ;
     RECT  51 50.771 51.312 54.133 ;
     RECT  27.072 54.085 44.472 54.373 ;
     RECT  56.4 35.987 56.712 54.469 ;
     RECT  13.2 50.243 13.512 54.565 ;
     RECT  13.104 54.565 13.512 54.661 ;
     RECT  14.592 52.981 14.616 54.661 ;
     RECT  13.104 54.661 14.616 54.707 ;
     RECT  55.488 54.469 56.712 54.755 ;
     RECT  26.736 54.373 44.472 54.899 ;
     RECT  26.736 54.899 44.376 55.045 ;
     RECT  18.6 51.347 18.912 55.669 ;
     RECT  9.696 54.997 9.72 56.435 ;
     RECT  51 54.133 51.576 56.867 ;
     RECT  23.28 54.085 25.608 56.869 ;
     RECT  26.64 55.045 44.376 56.869 ;
     RECT  12 55.573 12.024 57.059 ;
     RECT  13.2 54.707 13.992 57.059 ;
     RECT  18.6 55.669 19.272 57.059 ;
     RECT  53.712 54.133 53.736 57.059 ;
     RECT  21.024 49.043 21.048 57.635 ;
     RECT  23.28 56.869 44.376 57.635 ;
     RECT  26.64 57.635 44.376 60.467 ;
     RECT  23.28 57.635 25.608 61.237 ;
     RECT  26.64 60.467 44.184 61.525 ;
     RECT  23.184 61.237 25.608 61.619 ;
     RECT  54.48 62.053 54.504 62.101 ;
     RECT  23.184 61.619 25.416 62.149 ;
     RECT  26.64 61.525 44.232 62.149 ;
     RECT  53.712 62.101 54.504 62.389 ;
     RECT  26.64 62.149 44.424 62.437 ;
     RECT  45.6 50.771 45.912 62.437 ;
     RECT  22.704 62.149 25.416 62.629 ;
     RECT  53.712 62.389 54.6 62.629 ;
     RECT  2.4 2.151 2.712 62.649 ;
     RECT  7.8 50.723 8.112 62.649 ;
     RECT  13.2 57.059 13.512 62.649 ;
     RECT  18.6 57.059 18.912 62.649 ;
     RECT  26.64 62.437 45.912 62.649 ;
     RECT  51 56.867 51.312 62.649 ;
     RECT  56.4 54.755 56.712 62.649 ;
     RECT  61.8 30.899 62.112 62.649 ;
     RECT  2.4 62.649 2.52 62.663 ;
     RECT  7.8 62.649 7.92 62.663 ;
     RECT  13.2 62.649 13.32 62.663 ;
     RECT  18.6 62.649 18.72 62.663 ;
     RECT  26.64 62.649 45.72 62.663 ;
     RECT  51 62.649 51.12 62.663 ;
     RECT  56.4 62.649 56.52 62.663 ;
     RECT  61.8 62.649 61.92 62.663 ;
     RECT  22.704 62.629 25.608 62.725 ;
     RECT  53.52 62.629 54.6 62.725 ;
     RECT  22.608 62.725 25.608 63.205 ;
     RECT  26.64 62.663 44.808 63.205 ;
     RECT  22.608 63.205 44.808 64.784 ;
     RECT  53.328 62.725 54.6 64.784 ;
     RECT  38.088 1.811 39.216 1.859 ;
     RECT  25.896 1.859 27.024 2.821 ;
     RECT  37.992 1.859 39.216 1.907 ;
     RECT  19.176 2.195 20.208 2.291 ;
     RECT  21.672 2.291 23.184 3.443 ;
     RECT  31.608 2.291 32.592 2.915 ;
     RECT  33.288 2.291 34.464 3.925 ;
     RECT  26.424 2.915 27.6 3.443 ;
     RECT  31.608 2.915 32.88 6.565 ;
     RECT  24.936 3.443 26.4 4.019 ;
     RECT  26.424 3.443 27.888 5.123 ;
     RECT  23.76 4.019 24 5.077 ;
     RECT  24.648 4.019 26.4 5.077 ;
     RECT  28.056 4.019 29.04 4.595 ;
     RECT  18.432 4.403 18.6 5.605 ;
     RECT  28.056 4.595 29.184 6.181 ;
     RECT  35.592 5.075 35.688 5.747 ;
     RECT  19.032 5.077 20.256 6.515 ;
     RECT  24.888 5.077 26.4 6.805 ;
     RECT  26.424 5.123 28.032 6.277 ;
     RECT  43.128 5.605 44.304 6.179 ;
     RECT  44.328 5.605 45.6 6.275 ;
     RECT  35.112 5.747 35.688 6.181 ;
     RECT  35.112 6.181 36.384 10.213 ;
     RECT  26.616 6.277 28.032 6.421 ;
     RECT  28.248 6.323 29.4 11.125 ;
     RECT  18.912 6.515 20.256 8.821 ;
     RECT  31.896 6.565 32.88 6.899 ;
     RECT  26.616 6.755 28.032 7.475 ;
     RECT  25.368 6.805 26.4 8.003 ;
     RECT  31.608 6.899 32.88 7.957 ;
     RECT  25.32 8.003 26.4 10.883 ;
     RECT  20.28 9.061 21.408 9.251 ;
     RECT  25.32 10.883 26.232 11.365 ;
     RECT  54.576 10.931 54.6 11.365 ;
     RECT  40.728 10.979 41.16 11.941 ;
     RECT  54.576 11.365 54.624 11.941 ;
     RECT  28.248 11.987 29.4 13.093 ;
     RECT  35.112 12.227 36.384 15.731 ;
     RECT  19.656 12.517 21.072 13.283 ;
     RECT  28.248 13.093 29.28 13.859 ;
     RECT  32.616 13.715 33.888 17.699 ;
     RECT  28.248 13.859 29.4 16.595 ;
     RECT  27.888 14.291 27.936 15.253 ;
     RECT  21.864 15.397 22.992 15.731 ;
     RECT  35.112 15.731 35.208 17.077 ;
     RECT  27.888 16.019 27.936 17.509 ;
     RECT  27.96 16.595 29.4 17.555 ;
     RECT  37.968 17.123 38.208 18.133 ;
     RECT  32.616 17.699 34.8 18.565 ;
     RECT  38.808 18.229 40.2 19.523 ;
     RECT  33.432 18.565 34.8 19.379 ;
     RECT  45.912 18.709 47.04 20.003 ;
     RECT  47.064 18.709 48.48 20.003 ;
     RECT  50.064 18.803 51 19.909 ;
     RECT  56.712 18.851 57.744 18.995 ;
     RECT  32.616 19.379 34.8 19.765 ;
     RECT  32.616 19.765 33.984 21.155 ;
     RECT  48.504 19.909 49.632 20.579 ;
     RECT  49.656 19.909 51 20.579 ;
     RECT  6.696 19.957 7.8 20.533 ;
     RECT  44.52 20.579 45.6 20.819 ;
     RECT  48.504 20.579 48.552 21.637 ;
     RECT  45.024 20.819 45.6 21.637 ;
     RECT  32.184 21.155 32.28 22.213 ;
     RECT  27.96 22.165 29.4 25.045 ;
     RECT  36.888 22.213 37.968 22.259 ;
     RECT  32.16 22.259 32.256 23.317 ;
     RECT  18.912 22.357 20.208 22.741 ;
     RECT  20.232 22.357 21.456 22.739 ;
     RECT  20.232 22.739 20.904 22.787 ;
     RECT  19.368 22.787 20.904 22.789 ;
     RECT  19.368 22.789 20.88 24.371 ;
     RECT  40.512 23.267 41.016 23.317 ;
     RECT  40.512 23.317 42.192 24.469 ;
     RECT  48.552 23.845 49.536 23.891 ;
     RECT  49.56 23.845 51 24.611 ;
     RECT  48.504 23.891 49.536 24.611 ;
     RECT  43.944 25.621 45.312 26.291 ;
     RECT  22.824 27.301 24 28.499 ;
     RECT  24.312 27.301 25.296 28.837 ;
     RECT  19.032 27.877 20.112 28.307 ;
     RECT  21.72 27.877 22.8 28.499 ;
     RECT  20.568 28.261 21.696 28.931 ;
     RECT  19.032 28.307 20.544 28.547 ;
     RECT  32.28 28.931 32.472 29.893 ;
     RECT  28.056 29.029 29.4 30.419 ;
     RECT  50.88 29.267 51 30.661 ;
     RECT  41.64 29.365 42.768 30.227 ;
     RECT  34.032 29.411 34.8 29.893 ;
     RECT  13.104 29.891 13.2 29.893 ;
     RECT  12.024 29.893 13.2 31.667 ;
     RECT  32.28 29.893 33.504 30.755 ;
     RECT  33.528 29.893 34.8 30.755 ;
     RECT  10.488 30.133 12 30.565 ;
     RECT  41.304 30.227 42.768 30.611 ;
     RECT  6.6 30.469 7.8 33.541 ;
     RECT  10.488 30.565 11.664 30.803 ;
     RECT  18.912 30.565 19.92 30.851 ;
     RECT  11.688 31.667 13.2 35.939 ;
     RECT  29.712 32.341 31.104 32.771 ;
     RECT  31.128 32.341 32.256 32.725 ;
     RECT  10.2 32.437 11.664 33.827 ;
     RECT  6.6 33.541 7.68 33.587 ;
     RECT  45.912 33.683 46.008 34.117 ;
     RECT  45.912 34.117 47.328 34.883 ;
     RECT  28.248 34.741 29.4 36.227 ;
     RECT  13.512 34.787 14.808 34.885 ;
     RECT  13.512 34.885 15.12 35.797 ;
     RECT  37.656 35.125 38.784 35.363 ;
     RECT  38.808 35.125 40.08 36.563 ;
     RECT  13.704 35.797 15.12 36.755 ;
     RECT  24.408 35.939 24.696 36.083 ;
     RECT  24.312 36.083 24.696 36.997 ;
     RECT  19.464 36.517 20.448 38.101 ;
     RECT  38.808 36.563 40.2 37.091 ;
     RECT  45.912 36.949 47.376 39.109 ;
     RECT  20.472 36.997 21.648 38.005 ;
     RECT  24.312 36.997 25.776 40.499 ;
     RECT  25.8 36.997 26.784 38.819 ;
     RECT  39.36 37.091 40.2 38.149 ;
     RECT  19.656 38.819 20.736 41.075 ;
     RECT  45.912 39.109 47.328 41.747 ;
     RECT  44.472 40.307 45.6 41.413 ;
     RECT  53.016 40.981 54.432 41.699 ;
     RECT  44.472 41.413 45.504 43.141 ;
     RECT  32.28 41.605 33.312 42.467 ;
     RECT  33.336 41.605 34.32 42.467 ;
     RECT  22.824 41.845 23.904 41.939 ;
     RECT  22.824 41.939 24 42.083 ;
     RECT  22.896 42.083 24 42.949 ;
     RECT  51.312 42.181 52.464 43.571 ;
     RECT  15.144 42.421 16.176 43.235 ;
     RECT  34.224 42.467 34.32 43.861 ;
     RECT  29.712 42.709 30.768 42.805 ;
     RECT  30.312 42.851 31.728 43.811 ;
     RECT  22.92 42.949 24 43.571 ;
     RECT  40.512 43.523 41.064 44.389 ;
     RECT  37.896 44.005 39.408 45.059 ;
     RECT  12.216 44.389 13.2 45.635 ;
     RECT  40.512 44.389 41.616 45.395 ;
     RECT  37.632 45.059 37.872 46.069 ;
     RECT  55.368 45.253 56.4 45.971 ;
     RECT  21.288 47.845 22.512 47.939 ;
     RECT  22.536 47.845 24 48.659 ;
     RECT  33.384 47.845 34.512 49.379 ;
     RECT  20.808 47.939 22.512 48.659 ;
     RECT  29.712 48.229 30.816 48.755 ;
     RECT  39.888 48.515 40.2 49.525 ;
     RECT  8.112 48.659 9.552 49.043 ;
     RECT  20.808 48.659 21.048 48.997 ;
     RECT  29.712 48.755 30.264 48.997 ;
     RECT  12.024 48.901 13.2 49.571 ;
     RECT  14.232 49.043 14.568 50.197 ;
     RECT  20.784 49.043 21.024 49.477 ;
     RECT  33.384 49.379 34.8 49.619 ;
     RECT  19.896 49.477 21.024 50.531 ;
     RECT  13.512 50.243 14.544 52.931 ;
     RECT  19.848 50.531 21.024 51.347 ;
     RECT  37.896 50.677 39.408 52.981 ;
     RECT  33.288 51.541 34.8 52.405 ;
     RECT  35.832 51.781 37.104 51.829 ;
     RECT  51.312 51.829 52.464 52.019 ;
     RECT  45.912 52.309 46.896 53.603 ;
     RECT  31.32 52.357 32.688 52.405 ;
     RECT  24.312 52.405 25.584 53.413 ;
     RECT  33.288 52.405 34.56 52.981 ;
     RECT  41.592 52.405 42.768 52.885 ;
     RECT  43.08 52.405 44.16 52.885 ;
     RECT  44.184 52.405 45.6 54.085 ;
     RECT  13.512 52.931 14.568 52.981 ;
     RECT  13.512 52.981 14.592 54.661 ;
     RECT  25.608 54.085 27.072 54.373 ;
     RECT  44.472 54.085 45.6 54.899 ;
     RECT  25.608 54.373 26.736 55.045 ;
     RECT  13.104 54.707 13.2 55.573 ;
     RECT  44.376 54.899 45.6 60.467 ;
     RECT  25.608 55.045 26.64 56.869 ;
     RECT  12.024 55.573 13.2 57.059 ;
     RECT  25.608 57.635 26.64 61.619 ;
     RECT  44.184 60.467 45.6 61.525 ;
     RECT  44.232 61.525 45.6 62.149 ;
     RECT  25.416 61.619 26.64 62.629 ;
     RECT  44.424 62.149 45.6 62.437 ;
     RECT  25.608 62.629 26.64 63.205 ;
  END
END ot_hgi_hc_quarter_link6
END LIBRARY
